VERSION 5.7 ;
  NOWIREEXTENSIONATPIN ON ;
  DIVIDERCHAR "/" ;
  BUSBITCHARS "[]" ;
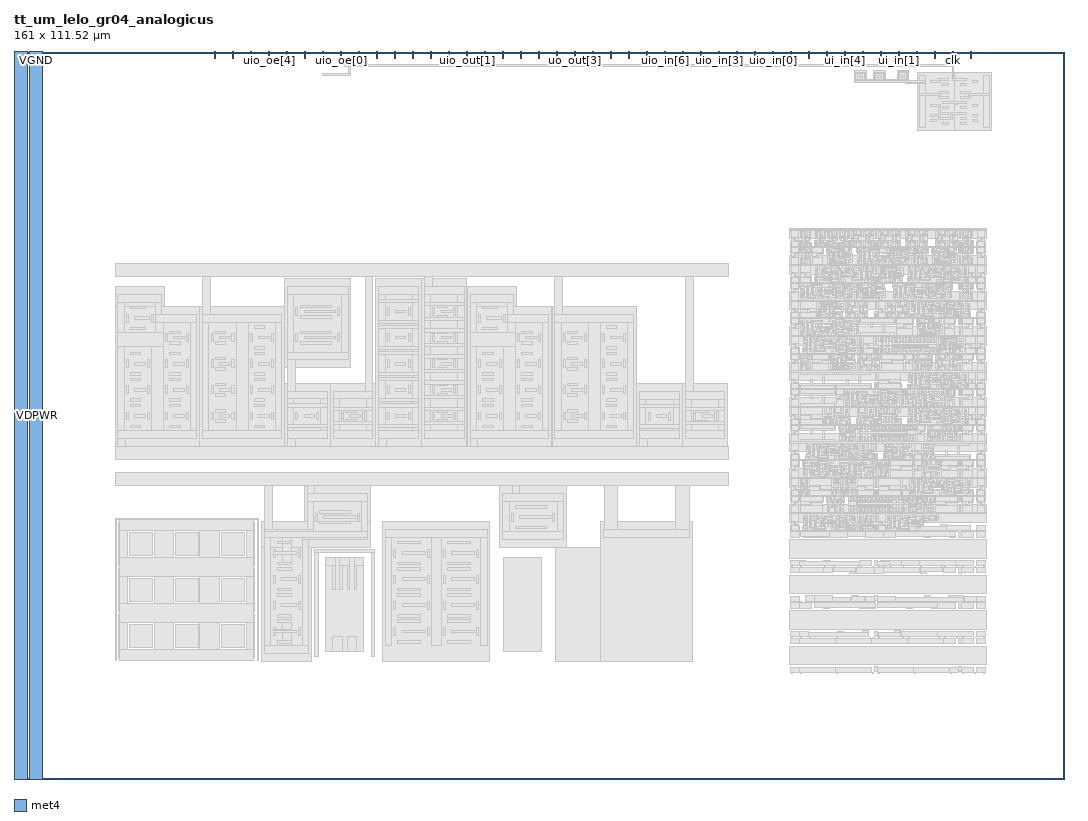
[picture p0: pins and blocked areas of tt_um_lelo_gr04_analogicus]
MACRO tt_um_lelo_gr04_analogicus
  CLASS BLOCK ;
  FOREIGN tt_um_lelo_gr04_analogicus ;
  ORIGIN 0.000 0.000 ;
  SIZE 161.000 BY 111.520 ;
  PIN uio_oe[0]
    DIRECTION OUTPUT ;
    USE SIGNAL ;
    PORT
      LAYER met4 ;
        RECT 49.990 110.520 50.290 111.520 ;
    END
  END uio_oe[0]
  PIN uio_oe[1]
    DIRECTION OUTPUT ;
    USE SIGNAL ;
    PORT
      LAYER met4 ;
        RECT 47.230 110.520 47.530 111.520 ;
    END
  END uio_oe[1]
  PIN uio_oe[2]
    DIRECTION OUTPUT ;
    USE SIGNAL ;
    PORT
      LAYER met4 ;
        RECT 44.470 110.520 44.770 111.520 ;
    END
  END uio_oe[2]
  PIN uio_oe[3]
    DIRECTION OUTPUT ;
    USE SIGNAL ;
    PORT
      LAYER met4 ;
        RECT 41.710 110.520 42.010 111.520 ;
    END
  END uio_oe[3]
  PIN uio_oe[4]
    DIRECTION OUTPUT ;
    USE SIGNAL ;
    PORT
      LAYER met4 ;
        RECT 38.950 110.520 39.250 111.520 ;
    END
  END uio_oe[4]
  PIN uio_oe[5]
    DIRECTION OUTPUT ;
    USE SIGNAL ;
    PORT
      LAYER met4 ;
        RECT 36.190 110.520 36.490 111.520 ;
    END
  END uio_oe[5]
  PIN uio_oe[6]
    DIRECTION OUTPUT ;
    USE SIGNAL ;
    PORT
      LAYER met4 ;
        RECT 33.430 110.520 33.730 111.520 ;
    END
  END uio_oe[6]
  PIN uio_oe[7]
    DIRECTION OUTPUT ;
    USE SIGNAL ;
    PORT
      LAYER met4 ;
        RECT 30.670 110.520 30.970 111.520 ;
    END
  END uio_oe[7]
  PIN uio_out[7]
    DIRECTION OUTPUT ;
    USE SIGNAL ;
    ANTENNADIFFAREA 0.445500 ;
    PORT
      LAYER met4 ;
        RECT 52.750 110.520 53.050 111.520 ;
    END
  END uio_out[7]
  PIN uio_out[6]
    DIRECTION OUTPUT ;
    USE SIGNAL ;
    ANTENNADIFFAREA 0.445500 ;
    PORT
      LAYER met4 ;
        RECT 55.510 110.520 55.810 111.520 ;
    END
  END uio_out[6]
  PIN uio_out[5]
    DIRECTION OUTPUT ;
    USE SIGNAL ;
    ANTENNADIFFAREA 0.445500 ;
    PORT
      LAYER met4 ;
        RECT 58.270 110.520 58.570 111.520 ;
    END
  END uio_out[5]
  PIN uio_out[4]
    DIRECTION OUTPUT ;
    USE SIGNAL ;
    ANTENNADIFFAREA 0.445500 ;
    PORT
      LAYER met4 ;
        RECT 61.030 110.520 61.330 111.520 ;
    END
  END uio_out[4]
  PIN uio_out[3]
    DIRECTION OUTPUT ;
    USE SIGNAL ;
    ANTENNADIFFAREA 0.445500 ;
    PORT
      LAYER met4 ;
        RECT 63.790 110.520 64.090 111.520 ;
    END
  END uio_out[3]
  PIN uio_out[2]
    DIRECTION OUTPUT ;
    USE SIGNAL ;
    ANTENNADIFFAREA 0.445500 ;
    PORT
      LAYER met4 ;
        RECT 66.550 110.520 66.850 111.520 ;
    END
  END uio_out[2]
  PIN uio_out[1]
    DIRECTION OUTPUT ;
    USE SIGNAL ;
    ANTENNADIFFAREA 0.445500 ;
    PORT
      LAYER met4 ;
        RECT 69.310 110.520 69.610 111.520 ;
    END
  END uio_out[1]
  PIN uio_out[0]
    DIRECTION OUTPUT ;
    USE SIGNAL ;
    ANTENNADIFFAREA 0.445500 ;
    PORT
      LAYER met4 ;
        RECT 72.070 110.520 72.370 111.520 ;
    END
  END uio_out[0]
  PIN uo_out[7]
    DIRECTION OUTPUT ;
    USE SIGNAL ;
    PORT
      LAYER met4 ;
        RECT 74.830 110.520 75.130 111.520 ;
    END
  END uo_out[7]
  PIN uo_out[6]
    DIRECTION OUTPUT ;
    USE SIGNAL ;
    PORT
      LAYER met4 ;
        RECT 77.590 110.520 77.890 111.520 ;
    END
  END uo_out[6]
  PIN uo_out[5]
    DIRECTION OUTPUT ;
    USE SIGNAL ;
    PORT
      LAYER met4 ;
        RECT 80.350 110.520 80.650 111.520 ;
    END
  END uo_out[5]
  PIN ui_in[4]
    DIRECTION INPUT ;
    USE SIGNAL ;
    PORT
      LAYER met4 ;
        RECT 127.270 110.520 127.570 111.520 ;
    END
  END ui_in[4]
  PIN ui_in[3]
    DIRECTION INPUT ;
    USE SIGNAL ;
    PORT
      LAYER met4 ;
        RECT 130.030 110.520 130.330 111.520 ;
    END
  END ui_in[3]
  PIN ui_in[2]
    DIRECTION INPUT ;
    USE SIGNAL ;
    PORT
      LAYER met4 ;
        RECT 132.790 110.520 133.090 111.520 ;
    END
  END ui_in[2]
  PIN ui_in[1]
    DIRECTION INPUT ;
    USE SIGNAL ;
    ANTENNAGATEAREA 0.490500 ;
    ANTENNADIFFAREA 0.202500 ;
    PORT
      LAYER met4 ;
        RECT 135.550 110.520 135.850 111.520 ;
    END
  END ui_in[1]
  PIN ui_in[0]
    DIRECTION INPUT ;
    USE SIGNAL ;
    ANTENNAGATEAREA 0.399000 ;
    ANTENNADIFFAREA 0.202500 ;
    PORT
      LAYER met4 ;
        RECT 138.310 110.520 138.610 111.520 ;
    END
  END ui_in[0]
  PIN rst_n
    DIRECTION INPUT ;
    USE SIGNAL ;
    ANTENNAGATEAREA 0.328500 ;
    ANTENNADIFFAREA 0.202500 ;
    PORT
      LAYER met4 ;
        RECT 141.070 110.520 141.370 111.520 ;
    END
  END rst_n
  PIN clk
    DIRECTION INPUT ;
    USE SIGNAL ;
    ANTENNAGATEAREA 0.852000 ;
    PORT
      LAYER met4 ;
        RECT 143.830 110.520 144.130 111.520 ;
    END
  END clk
  PIN ena
    DIRECTION INPUT ;
    USE SIGNAL ;
    PORT
      LAYER met4 ;
        RECT 146.590 110.520 146.890 111.520 ;
    END
  END ena
  PIN uio_in[4]
    DIRECTION INPUT ;
    USE SIGNAL ;
    PORT
      LAYER met4 ;
        RECT 105.190 110.520 105.490 111.520 ;
    END
  END uio_in[4]
  PIN uio_in[3]
    DIRECTION INPUT ;
    USE SIGNAL ;
    PORT
      LAYER met4 ;
        RECT 107.950 110.520 108.250 111.520 ;
    END
  END uio_in[3]
  PIN uio_in[2]
    DIRECTION INPUT ;
    USE SIGNAL ;
    PORT
      LAYER met4 ;
        RECT 110.710 110.520 111.010 111.520 ;
    END
  END uio_in[2]
  PIN uio_in[1]
    DIRECTION INPUT ;
    USE SIGNAL ;
    PORT
      LAYER met4 ;
        RECT 113.470 110.520 113.770 111.520 ;
    END
  END uio_in[1]
  PIN uio_in[0]
    DIRECTION INPUT ;
    USE SIGNAL ;
    PORT
      LAYER met4 ;
        RECT 116.230 110.520 116.530 111.520 ;
    END
  END uio_in[0]
  PIN ui_in[7]
    DIRECTION INPUT ;
    USE SIGNAL ;
    PORT
      LAYER met4 ;
        RECT 118.990 110.520 119.290 111.520 ;
    END
  END ui_in[7]
  PIN ui_in[6]
    DIRECTION INPUT ;
    USE SIGNAL ;
    PORT
      LAYER met4 ;
        RECT 121.750 110.520 122.050 111.520 ;
    END
  END ui_in[6]
  PIN ui_in[5]
    DIRECTION INPUT ;
    USE SIGNAL ;
    PORT
      LAYER met4 ;
        RECT 124.510 110.520 124.810 111.520 ;
    END
  END ui_in[5]
  PIN uo_out[4]
    DIRECTION OUTPUT ;
    USE SIGNAL ;
    PORT
      LAYER met4 ;
        RECT 83.110 110.520 83.410 111.520 ;
    END
  END uo_out[4]
  PIN uo_out[3]
    DIRECTION OUTPUT ;
    USE SIGNAL ;
    PORT
      LAYER met4 ;
        RECT 85.870 110.520 86.170 111.520 ;
    END
  END uo_out[3]
  PIN uo_out[2]
    DIRECTION OUTPUT ;
    USE SIGNAL ;
    PORT
      LAYER met4 ;
        RECT 88.630 110.520 88.930 111.520 ;
    END
  END uo_out[2]
  PIN uo_out[1]
    DIRECTION OUTPUT ;
    USE SIGNAL ;
    ANTENNAGATEAREA 0.288000 ;
    ANTENNADIFFAREA 0.445500 ;
    PORT
      LAYER met4 ;
        RECT 91.390 110.520 91.690 111.520 ;
    END
  END uo_out[1]
  PIN uo_out[0]
    DIRECTION OUTPUT ;
    USE SIGNAL ;
    ANTENNAGATEAREA 0.213000 ;
    ANTENNADIFFAREA 2.246400 ;
    PORT
      LAYER met4 ;
        RECT 94.150 110.520 94.450 111.520 ;
    END
  END uo_out[0]
  PIN uio_in[7]
    DIRECTION INPUT ;
    USE SIGNAL ;
    PORT
      LAYER met4 ;
        RECT 96.910 110.520 97.210 111.520 ;
    END
  END uio_in[7]
  PIN uio_in[6]
    DIRECTION INPUT ;
    USE SIGNAL ;
    PORT
      LAYER met4 ;
        RECT 99.670 110.520 99.970 111.520 ;
    END
  END uio_in[6]
  PIN uio_in[5]
    DIRECTION INPUT ;
    USE SIGNAL ;
    PORT
      LAYER met4 ;
        RECT 102.430 110.520 102.730 111.520 ;
    END
  END uio_in[5]
  PIN VDPWR
    DIRECTION INOUT ;
    USE POWER ;
    PORT
      LAYER met4 ;
        RECT 0.000 0.000 2.000 111.520 ;
    END
  END VDPWR
  PIN VGND
    DIRECTION INOUT ;
    USE GROUND ;
    PORT
      LAYER met4 ;
        RECT 2.400 0.000 4.400 111.520 ;
    END
  END VGND
  OBS
      LAYER pwell ;
        RECT 128.915 106.755 130.745 108.585 ;
        RECT 131.790 106.750 133.620 108.580 ;
        RECT 135.400 106.860 137.230 108.690 ;
        RECT 138.500 99.500 144.200 108.300 ;
      LAYER nwell ;
        RECT 144.200 99.500 149.900 108.300 ;
        RECT 118.870 82.825 149.150 84.430 ;
      LAYER pwell ;
        RECT 119.065 81.625 120.435 82.435 ;
        RECT 120.445 82.305 121.790 82.535 ;
        RECT 122.745 82.305 124.090 82.535 ;
        RECT 124.585 82.305 125.930 82.535 ;
        RECT 126.910 82.305 128.255 82.535 ;
        RECT 120.445 81.625 122.275 82.305 ;
        RECT 122.745 81.625 124.575 82.305 ;
        RECT 124.585 81.625 126.415 82.305 ;
        RECT 126.425 81.625 128.255 82.305 ;
        RECT 128.360 82.305 129.280 82.535 ;
        RECT 128.360 81.625 131.825 82.305 ;
        RECT 131.955 81.710 132.385 82.495 ;
        RECT 132.500 82.305 133.420 82.535 ;
        RECT 136.640 82.305 137.560 82.535 ;
        RECT 141.240 82.305 142.160 82.535 ;
        RECT 132.500 81.625 135.965 82.305 ;
        RECT 136.640 81.625 140.105 82.305 ;
        RECT 141.240 81.625 144.705 82.305 ;
        RECT 144.835 81.710 145.265 82.495 ;
        RECT 145.770 82.305 147.115 82.535 ;
        RECT 145.285 81.625 147.115 82.305 ;
        RECT 147.585 81.625 148.955 82.435 ;
        RECT 119.205 81.415 119.375 81.625 ;
        RECT 121.965 81.415 122.135 81.625 ;
        RECT 122.425 81.575 122.595 81.605 ;
        RECT 124.265 81.575 124.435 81.625 ;
        RECT 122.420 81.465 122.595 81.575 ;
        RECT 124.260 81.465 124.435 81.575 ;
        RECT 122.425 81.415 122.595 81.465 ;
        RECT 124.265 81.435 124.435 81.465 ;
        RECT 125.000 81.415 125.170 81.605 ;
        RECT 126.105 81.435 126.275 81.625 ;
        RECT 126.565 81.435 126.735 81.625 ;
        RECT 128.860 81.465 128.980 81.575 ;
        RECT 129.325 81.415 129.495 81.605 ;
        RECT 131.625 81.435 131.795 81.625 ;
        RECT 135.765 81.435 135.935 81.625 ;
        RECT 136.220 81.465 136.340 81.575 ;
        RECT 138.525 81.415 138.695 81.605 ;
        RECT 139.905 81.435 140.075 81.625 ;
        RECT 140.375 81.575 140.535 81.580 ;
        RECT 140.360 81.470 140.535 81.575 ;
        RECT 140.360 81.465 140.480 81.470 ;
        RECT 141.100 81.415 141.270 81.605 ;
        RECT 144.505 81.435 144.675 81.625 ;
        RECT 145.425 81.415 145.595 81.625 ;
        RECT 147.260 81.465 147.380 81.575 ;
        RECT 148.645 81.415 148.815 81.625 ;
        RECT 119.065 80.605 120.435 81.415 ;
        RECT 120.445 80.735 122.275 81.415 ;
        RECT 120.445 80.505 121.790 80.735 ;
        RECT 122.285 80.605 124.115 81.415 ;
        RECT 124.585 80.735 128.485 81.415 ;
        RECT 129.185 80.735 138.375 81.415 ;
        RECT 138.385 80.735 140.215 81.415 ;
        RECT 124.585 80.505 125.515 80.735 ;
        RECT 133.695 80.515 134.625 80.735 ;
        RECT 137.455 80.505 138.375 80.735 ;
        RECT 138.870 80.505 140.215 80.735 ;
        RECT 140.685 80.735 144.585 81.415 ;
        RECT 140.685 80.505 141.615 80.735 ;
        RECT 144.835 80.545 145.265 81.330 ;
        RECT 145.285 80.735 147.115 81.415 ;
        RECT 145.770 80.505 147.115 80.735 ;
        RECT 147.585 80.605 148.955 81.415 ;
      LAYER nwell ;
        RECT 118.870 77.385 149.150 80.215 ;
      LAYER pwell ;
        RECT 15.500 72.510 23.100 75.510 ;
        RECT 15.500 51.030 28.460 72.510 ;
      LAYER nwell ;
        RECT 28.500 51.030 41.460 72.510 ;
      LAYER pwell ;
        RECT 41.500 63.030 51.660 76.710 ;
        RECT 41.500 51.030 48.460 60.710 ;
      LAYER nwell ;
        RECT 48.500 51.030 55.460 60.710 ;
      LAYER pwell ;
        RECT 55.500 51.030 62.460 76.710 ;
      LAYER nwell ;
        RECT 62.500 51.030 69.460 76.710 ;
      LAYER pwell ;
        RECT 119.065 76.185 120.435 76.995 ;
        RECT 120.445 76.185 122.275 76.995 ;
        RECT 122.745 76.865 123.665 77.095 ;
        RECT 126.495 76.865 127.425 77.085 ;
        RECT 122.745 76.185 131.935 76.865 ;
        RECT 131.955 76.270 132.385 77.055 ;
        RECT 132.405 76.865 133.335 77.095 ;
        RECT 141.515 76.865 142.445 77.085 ;
        RECT 145.275 76.865 146.195 77.095 ;
        RECT 132.405 76.185 136.305 76.865 ;
        RECT 137.005 76.185 146.195 76.865 ;
        RECT 146.205 76.185 147.575 76.995 ;
        RECT 147.585 76.185 148.955 76.995 ;
        RECT 119.205 75.975 119.375 76.185 ;
        RECT 120.585 75.975 120.755 76.185 ;
        RECT 122.420 76.025 122.540 76.135 ;
        RECT 130.060 75.975 130.230 76.165 ;
        RECT 131.625 75.995 131.795 76.185 ;
        RECT 132.820 75.995 132.990 76.185 ;
        RECT 133.935 76.020 134.095 76.130 ;
        RECT 134.845 75.975 135.015 76.165 ;
        RECT 136.680 76.025 136.800 76.135 ;
        RECT 137.145 75.995 137.315 76.185 ;
        RECT 144.055 76.020 144.215 76.130 ;
        RECT 145.425 75.975 145.595 76.165 ;
        RECT 146.345 75.995 146.515 76.185 ;
        RECT 147.260 76.025 147.380 76.135 ;
        RECT 148.645 75.975 148.815 76.185 ;
        RECT 69.500 72.510 77.100 75.510 ;
        RECT 119.065 75.165 120.435 75.975 ;
        RECT 120.445 75.295 129.635 75.975 ;
        RECT 124.955 75.075 125.885 75.295 ;
        RECT 128.715 75.065 129.635 75.295 ;
        RECT 129.645 75.295 133.545 75.975 ;
        RECT 134.705 75.295 143.895 75.975 ;
        RECT 129.645 75.065 130.575 75.295 ;
        RECT 139.215 75.075 140.145 75.295 ;
        RECT 142.975 75.065 143.895 75.295 ;
        RECT 144.835 75.105 145.265 75.890 ;
        RECT 145.285 75.295 147.115 75.975 ;
        RECT 145.770 75.065 147.115 75.295 ;
        RECT 147.585 75.165 148.955 75.975 ;
        RECT 69.500 51.030 82.460 72.510 ;
      LAYER nwell ;
        RECT 82.500 51.030 95.460 72.510 ;
        RECT 118.870 71.945 149.150 74.775 ;
      LAYER pwell ;
        RECT 119.065 70.745 120.435 71.555 ;
        RECT 120.445 70.745 123.195 71.555 ;
        RECT 123.205 71.425 124.135 71.655 ;
        RECT 127.440 71.425 128.360 71.655 ;
        RECT 123.205 70.745 127.105 71.425 ;
        RECT 127.440 70.745 130.905 71.425 ;
        RECT 131.955 70.830 132.385 71.615 ;
        RECT 132.405 70.745 133.775 71.555 ;
        RECT 136.440 71.425 137.360 71.655 ;
        RECT 141.975 71.425 142.905 71.645 ;
        RECT 145.735 71.425 146.655 71.655 ;
        RECT 133.895 70.745 137.360 71.425 ;
        RECT 137.465 70.745 146.655 71.425 ;
        RECT 147.585 70.745 148.955 71.555 ;
        RECT 119.205 70.535 119.375 70.745 ;
        RECT 120.585 70.535 120.755 70.745 ;
        RECT 123.620 70.555 123.790 70.745 ;
        RECT 129.785 70.535 129.955 70.725 ;
        RECT 130.705 70.555 130.875 70.745 ;
        RECT 131.175 70.590 131.335 70.700 ;
        RECT 132.545 70.555 132.715 70.745 ;
        RECT 133.925 70.555 134.095 70.745 ;
        RECT 135.305 70.535 135.475 70.725 ;
        RECT 137.605 70.555 137.775 70.745 ;
        RECT 138.060 70.585 138.180 70.695 ;
        RECT 138.800 70.535 138.970 70.725 ;
        RECT 142.665 70.535 142.835 70.725 ;
        RECT 144.500 70.585 144.620 70.695 ;
        RECT 145.425 70.535 145.595 70.725 ;
        RECT 146.815 70.590 146.975 70.700 ;
        RECT 147.260 70.585 147.380 70.695 ;
        RECT 148.645 70.535 148.815 70.745 ;
        RECT 119.065 69.725 120.435 70.535 ;
        RECT 120.445 69.855 129.635 70.535 ;
        RECT 124.955 69.635 125.885 69.855 ;
        RECT 128.715 69.625 129.635 69.855 ;
        RECT 129.645 69.725 135.155 70.535 ;
        RECT 135.165 69.725 137.915 70.535 ;
        RECT 138.385 69.855 142.285 70.535 ;
        RECT 138.385 69.625 139.315 69.855 ;
        RECT 142.525 69.725 144.355 70.535 ;
        RECT 144.835 69.665 145.265 70.450 ;
        RECT 145.285 69.725 147.115 70.535 ;
        RECT 147.585 69.725 148.955 70.535 ;
      LAYER nwell ;
        RECT 118.870 66.505 149.150 69.335 ;
      LAYER pwell ;
        RECT 119.065 65.305 120.435 66.115 ;
        RECT 125.415 65.985 126.345 66.205 ;
        RECT 129.175 65.985 130.095 66.215 ;
        RECT 120.905 65.305 130.095 65.985 ;
        RECT 130.105 65.305 131.935 66.115 ;
        RECT 131.955 65.390 132.385 66.175 ;
        RECT 141.605 65.985 142.535 66.215 ;
        RECT 132.405 65.305 141.510 65.985 ;
        RECT 141.605 65.305 145.505 65.985 ;
        RECT 145.745 65.305 147.575 66.115 ;
        RECT 147.585 65.305 148.955 66.115 ;
        RECT 119.205 65.095 119.375 65.305 ;
        RECT 120.585 65.255 120.755 65.285 ;
        RECT 120.580 65.145 120.755 65.255 ;
        RECT 120.585 65.095 120.755 65.145 ;
        RECT 121.045 65.115 121.215 65.305 ;
        RECT 122.425 65.095 122.595 65.285 ;
        RECT 125.460 65.095 125.630 65.285 ;
        RECT 130.245 65.115 130.415 65.305 ;
        RECT 132.545 65.095 132.715 65.305 ;
        RECT 133.005 65.095 133.175 65.285 ;
        RECT 136.685 65.095 136.855 65.285 ;
        RECT 138.070 65.095 138.240 65.285 ;
        RECT 142.020 65.115 142.190 65.305 ;
        RECT 144.505 65.095 144.675 65.285 ;
        RECT 145.425 65.095 145.595 65.285 ;
        RECT 145.885 65.115 146.055 65.305 ;
        RECT 147.260 65.145 147.380 65.255 ;
        RECT 148.645 65.095 148.815 65.305 ;
        RECT 119.065 64.285 120.435 65.095 ;
        RECT 120.445 64.415 122.275 65.095 ;
        RECT 122.285 64.285 125.035 65.095 ;
        RECT 125.045 64.415 128.945 65.095 ;
        RECT 129.280 64.415 132.745 65.095 ;
        RECT 125.045 64.185 125.975 64.415 ;
        RECT 129.280 64.185 130.200 64.415 ;
        RECT 132.865 64.285 136.535 65.095 ;
        RECT 136.545 64.285 137.915 65.095 ;
        RECT 137.925 64.185 140.845 65.095 ;
        RECT 141.240 64.415 144.705 65.095 ;
        RECT 141.240 64.185 142.160 64.415 ;
        RECT 144.835 64.225 145.265 65.010 ;
        RECT 145.285 64.285 147.115 65.095 ;
        RECT 147.585 64.285 148.955 65.095 ;
      LAYER nwell ;
        RECT 118.870 61.065 149.150 63.895 ;
      LAYER pwell ;
        RECT 95.500 51.000 102.460 60.680 ;
      LAYER nwell ;
        RECT 102.500 51.000 109.460 60.680 ;
      LAYER pwell ;
        RECT 119.065 59.865 120.435 60.675 ;
        RECT 120.445 59.865 125.955 60.675 ;
        RECT 125.965 59.865 131.475 60.675 ;
        RECT 131.955 59.950 132.385 60.735 ;
        RECT 132.405 59.865 136.075 60.675 ;
        RECT 141.515 60.545 142.445 60.765 ;
        RECT 145.275 60.545 146.195 60.775 ;
        RECT 137.005 59.865 146.195 60.545 ;
        RECT 146.205 59.865 147.575 60.675 ;
        RECT 147.585 59.865 148.955 60.675 ;
        RECT 119.205 59.655 119.375 59.865 ;
        RECT 120.585 59.655 120.755 59.865 ;
        RECT 126.105 59.655 126.275 59.865 ;
        RECT 127.485 59.655 127.655 59.845 ;
        RECT 131.620 59.705 131.740 59.815 ;
        RECT 132.545 59.675 132.715 59.865 ;
        RECT 136.235 59.710 136.395 59.820 ;
        RECT 137.145 59.675 137.315 59.865 ;
        RECT 138.985 59.655 139.155 59.845 ;
        RECT 139.450 59.655 139.620 59.845 ;
        RECT 143.130 59.655 143.300 59.845 ;
        RECT 144.500 59.705 144.620 59.815 ;
        RECT 145.425 59.655 145.595 59.845 ;
        RECT 146.345 59.675 146.515 59.865 ;
        RECT 147.260 59.705 147.380 59.815 ;
        RECT 148.645 59.655 148.815 59.865 ;
        RECT 119.065 58.845 120.435 59.655 ;
        RECT 120.445 58.845 125.955 59.655 ;
        RECT 125.965 58.845 127.335 59.655 ;
        RECT 127.345 58.975 136.535 59.655 ;
        RECT 131.855 58.755 132.785 58.975 ;
        RECT 135.615 58.745 136.535 58.975 ;
        RECT 136.545 58.975 139.295 59.655 ;
        RECT 136.545 58.745 137.475 58.975 ;
        RECT 139.305 58.745 142.975 59.655 ;
        RECT 142.985 58.745 144.335 59.655 ;
        RECT 144.835 58.785 145.265 59.570 ;
        RECT 145.285 58.845 147.115 59.655 ;
        RECT 147.585 58.845 148.955 59.655 ;
      LAYER nwell ;
        RECT 118.870 55.625 149.150 58.455 ;
      LAYER pwell ;
        RECT 119.065 54.425 120.435 55.235 ;
        RECT 120.445 54.425 124.115 55.235 ;
        RECT 124.145 54.425 125.495 55.335 ;
        RECT 125.505 54.425 128.255 55.335 ;
        RECT 129.185 54.425 131.935 55.335 ;
        RECT 131.955 54.510 132.385 55.295 ;
        RECT 134.485 55.105 136.075 55.335 ;
        RECT 141.515 55.105 142.445 55.325 ;
        RECT 145.275 55.105 146.195 55.335 ;
        RECT 132.405 54.425 136.075 55.105 ;
        RECT 137.005 54.425 146.195 55.105 ;
        RECT 146.205 54.425 147.575 55.235 ;
        RECT 147.585 54.425 148.955 55.235 ;
        RECT 119.205 54.215 119.375 54.425 ;
        RECT 120.585 54.215 120.755 54.425 ;
        RECT 125.180 54.235 125.350 54.425 ;
        RECT 125.645 54.235 125.815 54.425 ;
        RECT 126.100 54.265 126.220 54.375 ;
        RECT 126.565 54.215 126.735 54.405 ;
        RECT 128.415 54.270 128.575 54.380 ;
        RECT 129.325 54.215 129.495 54.425 ;
        RECT 132.550 54.235 132.720 54.425 ;
        RECT 136.235 54.270 136.395 54.380 ;
        RECT 137.145 54.235 137.315 54.425 ;
        RECT 138.525 54.215 138.695 54.405 ;
        RECT 142.660 54.215 142.830 54.405 ;
        RECT 144.505 54.215 144.675 54.405 ;
        RECT 145.425 54.215 145.595 54.405 ;
        RECT 146.345 54.235 146.515 54.425 ;
        RECT 147.260 54.265 147.380 54.375 ;
        RECT 148.645 54.215 148.815 54.425 ;
        RECT 119.065 53.405 120.435 54.215 ;
        RECT 120.445 53.405 125.955 54.215 ;
        RECT 126.425 53.535 129.165 54.215 ;
        RECT 129.185 53.535 138.290 54.215 ;
        RECT 138.385 53.405 139.755 54.215 ;
        RECT 140.055 53.305 142.975 54.215 ;
        RECT 142.985 53.305 144.800 54.215 ;
        RECT 144.835 53.345 145.265 54.130 ;
        RECT 145.285 53.405 147.115 54.215 ;
        RECT 147.585 53.405 148.955 54.215 ;
      LAYER nwell ;
        RECT 118.870 50.185 149.150 53.015 ;
      LAYER pwell ;
        RECT 119.065 48.985 120.435 49.795 ;
        RECT 125.875 49.665 126.805 49.885 ;
        RECT 129.635 49.665 130.555 49.895 ;
        RECT 121.365 48.985 130.555 49.665 ;
        RECT 130.585 48.985 131.935 49.895 ;
        RECT 131.955 49.070 132.385 49.855 ;
        RECT 133.325 49.665 134.245 49.895 ;
        RECT 135.825 49.805 136.775 49.895 ;
        RECT 133.325 48.985 135.615 49.665 ;
        RECT 135.825 48.985 137.755 49.805 ;
        RECT 137.925 48.985 139.295 49.795 ;
        RECT 139.305 48.985 141.120 49.895 ;
        RECT 141.145 48.985 146.655 49.795 ;
        RECT 147.585 48.985 148.955 49.795 ;
        RECT 119.205 48.775 119.375 48.985 ;
        RECT 120.595 48.935 120.755 48.940 ;
        RECT 120.580 48.830 120.755 48.935 ;
        RECT 120.580 48.825 120.700 48.830 ;
        RECT 121.505 48.795 121.675 48.985 ;
        RECT 129.785 48.775 129.955 48.965 ;
        RECT 130.245 48.795 130.415 48.965 ;
        RECT 131.620 48.795 131.790 48.985 ;
        RECT 130.265 48.775 130.415 48.795 ;
        RECT 132.550 48.775 132.720 48.965 ;
        RECT 134.385 48.775 134.555 48.965 ;
        RECT 135.305 48.795 135.475 48.985 ;
        RECT 137.605 48.965 137.755 48.985 ;
        RECT 137.605 48.795 137.775 48.965 ;
        RECT 138.065 48.775 138.235 48.985 ;
        RECT 139.445 48.775 139.615 48.965 ;
        RECT 140.825 48.795 140.995 48.985 ;
        RECT 141.285 48.795 141.455 48.985 ;
        RECT 142.205 48.775 142.375 48.965 ;
        RECT 145.425 48.775 145.595 48.965 ;
        RECT 146.815 48.830 146.975 48.940 ;
        RECT 147.260 48.825 147.380 48.935 ;
        RECT 148.645 48.775 148.815 48.985 ;
        RECT 119.065 47.965 120.435 48.775 ;
        RECT 120.905 48.095 130.095 48.775 ;
        RECT 120.905 47.865 121.825 48.095 ;
        RECT 124.655 47.875 125.585 48.095 ;
        RECT 130.265 47.955 132.195 48.775 ;
        RECT 131.245 47.865 132.195 47.955 ;
        RECT 132.405 47.865 134.175 48.775 ;
        RECT 134.245 47.965 137.915 48.775 ;
        RECT 137.925 47.965 139.295 48.775 ;
        RECT 139.305 47.865 142.055 48.775 ;
        RECT 142.065 47.965 144.815 48.775 ;
        RECT 144.835 47.905 145.265 48.690 ;
        RECT 145.285 47.965 147.115 48.775 ;
        RECT 147.585 47.965 148.955 48.775 ;
      LAYER nwell ;
        RECT 44.500 39.480 54.660 44.980 ;
      LAYER pwell ;
        RECT 16.085 38.620 22.785 39.385 ;
        RECT 16.085 33.450 16.850 38.620 ;
        RECT 22.020 33.450 22.785 38.620 ;
        RECT 16.085 32.685 22.785 33.450 ;
        RECT 23.135 38.620 29.835 39.385 ;
        RECT 23.135 33.450 23.900 38.620 ;
        RECT 29.070 33.450 29.835 38.620 ;
        RECT 23.135 32.685 29.835 33.450 ;
        RECT 30.185 38.620 36.885 39.385 ;
        RECT 30.185 33.450 30.950 38.620 ;
        RECT 36.120 33.450 36.885 38.620 ;
        RECT 30.185 32.685 36.885 33.450 ;
      LAYER nwell ;
        RECT 38.000 35.500 54.660 39.480 ;
      LAYER pwell ;
        RECT 16.085 31.570 22.785 32.335 ;
        RECT 16.085 26.400 16.850 31.570 ;
        RECT 22.020 26.400 22.785 31.570 ;
        RECT 16.085 25.635 22.785 26.400 ;
        RECT 23.135 31.570 29.835 32.335 ;
        RECT 23.135 26.400 23.900 31.570 ;
        RECT 29.070 26.400 29.835 31.570 ;
        RECT 23.135 25.635 29.835 26.400 ;
        RECT 30.185 31.570 36.885 32.335 ;
        RECT 30.185 26.400 30.950 31.570 ;
        RECT 36.120 26.400 36.885 31.570 ;
        RECT 30.185 25.635 36.885 26.400 ;
        RECT 16.085 24.520 22.785 25.285 ;
        RECT 16.085 19.350 16.850 24.520 ;
        RECT 22.020 19.350 22.785 24.520 ;
        RECT 16.085 18.585 22.785 19.350 ;
        RECT 23.135 24.520 29.835 25.285 ;
        RECT 23.135 19.350 23.900 24.520 ;
        RECT 29.070 19.350 29.835 24.520 ;
        RECT 23.135 18.585 29.835 19.350 ;
        RECT 30.185 24.520 36.885 25.285 ;
        RECT 30.185 19.350 30.950 24.520 ;
        RECT 36.120 19.350 36.885 24.520 ;
        RECT 30.185 18.585 36.885 19.350 ;
      LAYER nwell ;
        RECT 38.000 18.000 45.600 35.500 ;
      LAYER pwell ;
        RECT 47.820 19.500 53.580 33.900 ;
      LAYER nwell ;
        RECT 56.500 18.000 72.980 39.480 ;
        RECT 74.500 35.500 84.660 44.980 ;
        RECT 118.870 44.745 149.150 47.575 ;
      LAYER pwell ;
        RECT 119.065 43.545 120.435 44.355 ;
        RECT 120.445 43.545 121.815 44.325 ;
        RECT 121.825 43.545 125.495 44.355 ;
        RECT 125.505 43.545 127.320 44.455 ;
        RECT 127.360 43.545 129.175 44.455 ;
        RECT 129.185 43.545 131.935 44.355 ;
        RECT 131.955 43.630 132.385 44.415 ;
        RECT 132.405 43.545 136.075 44.355 ;
        RECT 136.085 43.545 137.455 44.355 ;
        RECT 141.975 44.225 142.905 44.445 ;
        RECT 145.735 44.225 147.075 44.455 ;
        RECT 137.465 43.545 147.075 44.225 ;
        RECT 147.585 43.545 148.955 44.355 ;
        RECT 119.205 43.335 119.375 43.545 ;
        RECT 120.595 43.525 120.765 43.545 ;
        RECT 120.585 43.355 120.765 43.525 ;
        RECT 121.965 43.355 122.135 43.545 ;
        RECT 124.260 43.385 124.380 43.495 ;
        RECT 120.585 43.335 120.755 43.355 ;
        RECT 124.725 43.335 124.895 43.525 ;
        RECT 127.025 43.355 127.195 43.545 ;
        RECT 127.485 43.495 127.655 43.545 ;
        RECT 127.480 43.385 127.655 43.495 ;
        RECT 127.485 43.355 127.655 43.385 ;
        RECT 129.325 43.355 129.495 43.545 ;
        RECT 132.545 43.355 132.715 43.545 ;
        RECT 136.225 43.355 136.395 43.545 ;
        RECT 136.685 43.335 136.855 43.525 ;
        RECT 137.605 43.355 137.775 43.545 ;
        RECT 138.985 43.335 139.155 43.525 ;
        RECT 139.445 43.335 139.615 43.525 ;
        RECT 141.285 43.335 141.455 43.525 ;
        RECT 145.425 43.335 145.595 43.525 ;
        RECT 147.260 43.385 147.380 43.495 ;
        RECT 148.645 43.335 148.815 43.545 ;
        RECT 119.065 42.525 120.435 43.335 ;
        RECT 120.445 42.525 124.115 43.335 ;
        RECT 124.585 42.425 127.335 43.335 ;
        RECT 127.890 42.655 136.995 43.335 ;
        RECT 137.005 42.655 139.295 43.335 ;
        RECT 137.005 42.425 137.925 42.655 ;
        RECT 139.320 42.425 141.135 43.335 ;
        RECT 141.145 42.525 144.815 43.335 ;
        RECT 144.835 42.465 145.265 43.250 ;
        RECT 145.285 42.525 147.115 43.335 ;
        RECT 147.585 42.525 148.955 43.335 ;
        RECT 75.120 19.500 80.880 33.900 ;
        RECT 83.000 18.000 89.960 35.480 ;
      LAYER nwell ;
        RECT 90.000 18.000 104.000 39.480 ;
        RECT 118.870 39.305 149.150 42.135 ;
      LAYER pwell ;
        RECT 119.065 38.105 120.435 38.915 ;
        RECT 125.415 38.785 126.345 39.005 ;
        RECT 129.175 38.785 130.095 39.015 ;
        RECT 120.905 38.105 130.095 38.785 ;
        RECT 130.165 38.105 131.935 39.015 ;
        RECT 131.955 38.190 132.385 38.975 ;
        RECT 132.405 38.105 133.775 38.915 ;
        RECT 138.295 38.785 139.225 39.005 ;
        RECT 142.055 38.785 142.975 39.015 ;
        RECT 133.785 38.105 142.975 38.785 ;
        RECT 142.985 38.105 146.655 38.915 ;
        RECT 147.585 38.105 148.955 38.915 ;
        RECT 119.205 37.895 119.375 38.105 ;
        RECT 120.560 37.915 120.730 38.085 ;
        RECT 121.045 37.915 121.215 38.105 ;
        RECT 120.620 37.895 120.730 37.915 ;
        RECT 125.185 37.895 125.355 38.085 ;
        RECT 127.945 37.895 128.115 38.085 ;
        RECT 130.705 37.895 130.875 38.085 ;
        RECT 131.620 37.915 131.790 38.105 ;
        RECT 132.545 37.915 132.715 38.105 ;
        RECT 133.465 37.895 133.635 38.085 ;
        RECT 133.925 37.915 134.095 38.105 ;
        RECT 135.305 37.895 135.475 38.085 ;
        RECT 143.125 37.915 143.295 38.105 ;
        RECT 144.500 37.945 144.620 38.055 ;
        RECT 145.425 37.895 145.595 38.085 ;
        RECT 146.815 37.950 146.975 38.060 ;
        RECT 147.260 37.945 147.380 38.055 ;
        RECT 148.645 37.895 148.815 38.105 ;
        RECT 119.065 37.085 120.435 37.895 ;
        RECT 120.620 37.215 125.035 37.895 ;
        RECT 121.105 36.985 125.035 37.215 ;
        RECT 125.045 37.085 127.795 37.895 ;
        RECT 127.805 37.215 130.545 37.895 ;
        RECT 130.565 37.085 133.315 37.895 ;
        RECT 133.340 36.985 135.155 37.895 ;
        RECT 135.165 37.215 144.355 37.895 ;
        RECT 139.675 36.995 140.605 37.215 ;
        RECT 143.435 36.985 144.355 37.215 ;
        RECT 144.835 37.025 145.265 37.810 ;
        RECT 145.285 37.085 147.115 37.895 ;
        RECT 147.585 37.085 148.955 37.895 ;
      LAYER nwell ;
        RECT 118.870 33.865 149.150 36.695 ;
      LAYER pwell ;
        RECT 119.065 32.665 120.435 33.475 ;
        RECT 120.445 33.345 121.365 33.575 ;
        RECT 124.195 33.345 125.125 33.565 ;
        RECT 120.445 32.665 129.635 33.345 ;
        RECT 129.645 32.665 131.475 33.475 ;
        RECT 131.955 32.750 132.385 33.535 ;
        RECT 132.890 33.345 134.235 33.575 ;
        RECT 132.405 32.665 134.235 33.345 ;
        RECT 134.245 32.665 136.075 33.475 ;
        RECT 136.085 32.665 138.835 33.575 ;
        RECT 138.845 32.665 144.355 33.475 ;
        RECT 144.365 32.665 147.115 33.475 ;
        RECT 147.585 32.665 148.955 33.475 ;
        RECT 119.205 32.455 119.375 32.665 ;
        RECT 120.585 32.455 120.755 32.645 ;
        RECT 124.265 32.455 124.435 32.645 ;
        RECT 125.645 32.455 125.815 32.645 ;
        RECT 129.325 32.455 129.495 32.665 ;
        RECT 129.785 32.475 129.955 32.665 ;
        RECT 131.620 32.505 131.740 32.615 ;
        RECT 132.545 32.475 132.715 32.665 ;
        RECT 133.000 32.455 133.170 32.645 ;
        RECT 133.465 32.455 133.635 32.645 ;
        RECT 134.385 32.475 134.555 32.665 ;
        RECT 136.225 32.475 136.395 32.665 ;
        RECT 138.985 32.475 139.155 32.665 ;
        RECT 142.205 32.455 142.375 32.645 ;
        RECT 142.665 32.455 142.835 32.645 ;
        RECT 144.505 32.615 144.675 32.665 ;
        RECT 144.500 32.505 144.675 32.615 ;
        RECT 144.505 32.475 144.675 32.505 ;
        RECT 145.425 32.455 145.595 32.645 ;
        RECT 147.260 32.505 147.380 32.615 ;
        RECT 148.645 32.455 148.815 32.665 ;
        RECT 119.065 31.645 120.435 32.455 ;
        RECT 120.445 31.645 124.115 32.455 ;
        RECT 124.125 31.645 125.495 32.455 ;
        RECT 125.615 31.775 129.080 32.455 ;
        RECT 128.160 31.545 129.080 31.775 ;
        RECT 129.185 31.545 131.935 32.455 ;
        RECT 131.965 31.545 133.315 32.455 ;
        RECT 133.325 31.645 138.835 32.455 ;
        RECT 138.940 31.775 142.405 32.455 ;
        RECT 138.940 31.545 139.860 31.775 ;
        RECT 142.525 31.645 144.355 32.455 ;
        RECT 144.835 31.585 145.265 32.370 ;
        RECT 145.285 31.645 147.115 32.455 ;
        RECT 147.585 31.645 148.955 32.455 ;
      LAYER nwell ;
        RECT 118.870 28.425 149.150 31.255 ;
      LAYER pwell ;
        RECT 119.065 27.225 120.435 28.035 ;
        RECT 121.375 27.225 122.725 28.135 ;
        RECT 122.755 27.225 125.485 28.135 ;
        RECT 128.465 28.045 129.415 28.135 ;
        RECT 125.505 27.225 128.245 27.905 ;
        RECT 128.465 27.225 130.395 28.045 ;
        RECT 130.565 27.225 131.935 28.035 ;
        RECT 131.955 27.310 132.385 28.095 ;
        RECT 132.405 27.225 135.155 28.035 ;
        RECT 139.675 27.905 140.605 28.125 ;
        RECT 143.325 27.905 145.535 28.135 ;
        RECT 135.165 27.225 145.535 27.905 ;
        RECT 145.745 27.225 147.575 28.035 ;
        RECT 147.585 27.225 148.955 28.035 ;
        RECT 119.205 27.015 119.375 27.225 ;
        RECT 120.585 27.015 120.755 27.205 ;
        RECT 121.505 27.035 121.675 27.225 ;
        RECT 122.420 27.065 122.540 27.175 ;
        RECT 122.885 27.015 123.055 27.205 ;
        RECT 125.185 27.035 125.355 27.225 ;
        RECT 125.645 27.035 125.815 27.225 ;
        RECT 130.245 27.205 130.395 27.225 ;
        RECT 130.245 27.035 130.415 27.205 ;
        RECT 130.705 27.035 130.875 27.225 ;
        RECT 132.545 27.015 132.715 27.225 ;
        RECT 135.305 27.035 135.475 27.225 ;
        RECT 141.745 27.015 141.915 27.205 ;
        RECT 144.500 27.065 144.620 27.175 ;
        RECT 145.425 27.015 145.595 27.205 ;
        RECT 145.885 27.035 146.055 27.225 ;
        RECT 147.260 27.065 147.380 27.175 ;
        RECT 148.645 27.015 148.815 27.225 ;
        RECT 119.065 26.205 120.435 27.015 ;
        RECT 120.445 26.205 122.275 27.015 ;
        RECT 122.745 26.335 132.025 27.015 ;
        RECT 132.405 26.335 141.595 27.015 ;
        RECT 124.105 26.115 125.025 26.335 ;
        RECT 129.690 26.215 132.025 26.335 ;
        RECT 131.105 26.105 132.025 26.215 ;
        RECT 136.915 26.115 137.845 26.335 ;
        RECT 140.675 26.105 141.595 26.335 ;
        RECT 141.605 26.205 144.355 27.015 ;
        RECT 144.835 26.145 145.265 26.930 ;
        RECT 145.285 26.205 147.115 27.015 ;
        RECT 147.585 26.205 148.955 27.015 ;
      LAYER nwell ;
        RECT 118.870 22.985 149.150 25.815 ;
      LAYER pwell ;
        RECT 119.065 21.785 120.435 22.595 ;
        RECT 120.445 21.785 121.815 22.595 ;
        RECT 126.335 22.465 127.265 22.685 ;
        RECT 130.095 22.465 131.015 22.695 ;
        RECT 121.825 21.785 131.015 22.465 ;
        RECT 131.955 21.870 132.385 22.655 ;
        RECT 135.060 22.465 135.980 22.695 ;
        RECT 132.515 21.785 135.980 22.465 ;
        RECT 136.085 21.785 141.595 22.595 ;
        RECT 141.605 21.785 147.115 22.595 ;
        RECT 147.585 21.785 148.955 22.595 ;
        RECT 119.205 21.575 119.375 21.785 ;
        RECT 120.585 21.575 120.755 21.785 ;
        RECT 121.965 21.595 122.135 21.785 ;
        RECT 126.105 21.575 126.275 21.765 ;
        RECT 131.175 21.630 131.335 21.740 ;
        RECT 131.625 21.575 131.795 21.765 ;
        RECT 132.545 21.595 132.715 21.785 ;
        RECT 136.225 21.595 136.395 21.785 ;
        RECT 137.145 21.575 137.315 21.765 ;
        RECT 141.745 21.595 141.915 21.785 ;
        RECT 142.665 21.575 142.835 21.765 ;
        RECT 144.500 21.625 144.620 21.735 ;
        RECT 145.425 21.575 145.595 21.765 ;
        RECT 147.260 21.625 147.380 21.735 ;
        RECT 148.645 21.575 148.815 21.785 ;
        RECT 119.065 20.765 120.435 21.575 ;
        RECT 120.445 20.765 125.955 21.575 ;
        RECT 125.965 20.765 131.475 21.575 ;
        RECT 131.485 20.765 136.995 21.575 ;
        RECT 137.005 20.765 142.515 21.575 ;
        RECT 142.525 20.765 144.355 21.575 ;
        RECT 144.835 20.705 145.265 21.490 ;
        RECT 145.285 20.765 147.115 21.575 ;
        RECT 147.585 20.765 148.955 21.575 ;
      LAYER nwell ;
        RECT 118.870 17.545 149.150 20.375 ;
      LAYER pwell ;
        RECT 119.065 16.345 120.435 17.155 ;
        RECT 120.445 16.345 125.955 17.155 ;
        RECT 125.965 16.345 131.475 17.155 ;
        RECT 131.955 16.430 132.385 17.215 ;
        RECT 132.405 16.345 137.915 17.155 ;
        RECT 137.925 16.345 143.435 17.155 ;
        RECT 143.445 16.345 144.815 17.155 ;
        RECT 144.835 16.430 145.265 17.215 ;
        RECT 145.285 16.345 147.115 17.155 ;
        RECT 147.585 16.345 148.955 17.155 ;
        RECT 119.205 16.155 119.375 16.345 ;
        RECT 120.585 16.155 120.755 16.345 ;
        RECT 126.105 16.155 126.275 16.345 ;
        RECT 131.620 16.185 131.740 16.295 ;
        RECT 132.545 16.155 132.715 16.345 ;
        RECT 138.065 16.155 138.235 16.345 ;
        RECT 143.585 16.155 143.755 16.345 ;
        RECT 145.425 16.155 145.595 16.345 ;
        RECT 147.260 16.185 147.380 16.295 ;
        RECT 148.645 16.155 148.815 16.345 ;
      LAYER li1 ;
        RECT 50.730 109.320 144.130 109.620 ;
        RECT 51.310 108.170 51.610 109.320 ;
        RECT 47.260 107.870 51.610 108.170 ;
        RECT 129.095 108.235 130.565 108.405 ;
        RECT 129.095 107.220 129.265 108.235 ;
        RECT 129.585 107.505 130.075 107.835 ;
        RECT 130.395 107.220 130.565 108.235 ;
        RECT 131.970 108.230 133.440 108.400 ;
        RECT 131.970 107.220 132.140 108.230 ;
        RECT 132.460 107.500 132.950 107.830 ;
        RECT 133.270 107.220 133.440 108.230 ;
        RECT 135.580 108.340 137.050 108.510 ;
        RECT 135.580 107.220 135.750 108.340 ;
        RECT 136.070 107.610 136.560 107.940 ;
        RECT 136.880 107.220 137.050 108.340 ;
        RECT 129.040 107.150 137.050 107.220 ;
        RECT 138.800 107.150 139.700 107.900 ;
        RECT 143.830 107.450 144.130 109.320 ;
        RECT 129.040 106.730 139.700 107.150 ;
        RECT 141.800 107.150 143.300 107.450 ;
        RECT 143.830 107.150 146.000 107.450 ;
        RECT 141.800 107.050 142.100 107.150 ;
        RECT 140.600 106.750 142.100 107.050 ;
        RECT 146.900 106.750 147.800 107.050 ;
        RECT 136.680 106.710 139.700 106.730 ;
        RECT 138.800 105.050 139.700 106.710 ;
        RECT 142.400 106.650 143.240 106.670 ;
        RECT 145.100 106.650 145.940 106.670 ;
        RECT 142.400 106.350 143.300 106.650 ;
        RECT 145.100 106.350 146.000 106.650 ;
        RECT 142.400 105.450 143.240 105.470 ;
        RECT 145.100 105.450 145.940 105.470 ;
        RECT 141.800 105.150 143.300 105.450 ;
        RECT 145.100 105.150 146.600 105.450 ;
        RECT 141.800 105.050 142.100 105.150 ;
        RECT 138.800 104.750 142.100 105.050 ;
        RECT 138.800 99.900 139.700 104.750 ;
        RECT 141.800 104.650 142.100 104.750 ;
        RECT 146.300 105.050 146.600 105.150 ;
        RECT 148.700 105.050 149.600 107.900 ;
        RECT 146.300 104.750 149.600 105.050 ;
        RECT 142.400 104.650 143.240 104.670 ;
        RECT 145.100 104.650 145.940 104.670 ;
        RECT 146.300 104.650 146.600 104.750 ;
        RECT 141.800 104.350 143.300 104.650 ;
        RECT 145.100 104.350 146.600 104.650 ;
        RECT 144.240 103.850 144.620 103.860 ;
        RECT 142.400 103.550 146.000 103.850 ;
        RECT 140.600 103.150 142.100 103.450 ;
        RECT 144.240 103.400 144.620 103.550 ;
        RECT 146.900 103.150 147.800 103.450 ;
        RECT 140.600 101.550 141.500 101.850 ;
        RECT 141.800 101.450 142.100 103.150 ;
        RECT 142.400 103.050 143.240 103.070 ;
        RECT 145.100 103.050 145.940 103.070 ;
        RECT 142.400 102.750 143.300 103.050 ;
        RECT 145.100 102.750 146.000 103.050 ;
        RECT 142.400 102.250 143.240 102.270 ;
        RECT 142.400 101.950 143.300 102.250 ;
        RECT 143.600 101.950 146.000 102.250 ;
        RECT 143.600 101.450 143.900 101.950 ;
        RECT 146.900 101.550 147.800 101.850 ;
        RECT 141.800 101.150 143.900 101.450 ;
        RECT 145.100 101.150 146.000 101.450 ;
        RECT 140.600 100.750 141.500 101.050 ;
        RECT 146.900 100.750 147.800 101.050 ;
        RECT 142.400 100.650 143.240 100.670 ;
        RECT 145.100 100.650 145.940 100.670 ;
        RECT 142.400 100.350 143.300 100.650 ;
        RECT 145.100 100.350 146.000 100.650 ;
        RECT 148.700 99.900 149.600 104.750 ;
        RECT 119.060 84.155 148.960 84.325 ;
        RECT 119.145 83.065 120.355 84.155 ;
        RECT 119.145 82.355 119.665 82.895 ;
        RECT 119.835 82.525 120.355 83.065 ;
        RECT 120.530 83.005 120.790 84.155 ;
        RECT 120.965 83.080 121.220 83.985 ;
        RECT 121.390 83.395 121.720 84.155 ;
        RECT 121.935 83.225 122.105 83.985 ;
        RECT 119.145 81.605 120.355 82.355 ;
        RECT 120.530 81.605 120.790 82.445 ;
        RECT 120.965 82.350 121.135 83.080 ;
        RECT 121.390 83.055 122.105 83.225 ;
        RECT 121.390 82.845 121.560 83.055 ;
        RECT 122.830 83.005 123.090 84.155 ;
        RECT 123.265 83.080 123.520 83.985 ;
        RECT 123.690 83.395 124.020 84.155 ;
        RECT 124.235 83.225 124.405 83.985 ;
        RECT 121.305 82.515 121.560 82.845 ;
        RECT 120.965 81.775 121.220 82.350 ;
        RECT 121.390 82.325 121.560 82.515 ;
        RECT 121.840 82.505 122.195 82.875 ;
        RECT 121.390 82.155 122.105 82.325 ;
        RECT 121.390 81.605 121.720 81.985 ;
        RECT 121.935 81.775 122.105 82.155 ;
        RECT 122.830 81.605 123.090 82.445 ;
        RECT 123.265 82.350 123.435 83.080 ;
        RECT 123.690 83.055 124.405 83.225 ;
        RECT 123.690 82.845 123.860 83.055 ;
        RECT 124.670 83.005 124.930 84.155 ;
        RECT 125.105 83.080 125.360 83.985 ;
        RECT 125.530 83.395 125.860 84.155 ;
        RECT 126.075 83.225 126.245 83.985 ;
        RECT 123.605 82.515 123.860 82.845 ;
        RECT 123.265 81.775 123.520 82.350 ;
        RECT 123.690 82.325 123.860 82.515 ;
        RECT 124.140 82.505 124.495 82.875 ;
        RECT 123.690 82.155 124.405 82.325 ;
        RECT 123.690 81.605 124.020 81.985 ;
        RECT 124.235 81.775 124.405 82.155 ;
        RECT 124.670 81.605 124.930 82.445 ;
        RECT 125.105 82.350 125.275 83.080 ;
        RECT 125.530 83.055 126.245 83.225 ;
        RECT 126.595 83.225 126.765 83.985 ;
        RECT 126.980 83.395 127.310 84.155 ;
        RECT 126.595 83.055 127.310 83.225 ;
        RECT 127.480 83.080 127.735 83.985 ;
        RECT 125.530 82.845 125.700 83.055 ;
        RECT 125.445 82.515 125.700 82.845 ;
        RECT 125.105 81.775 125.360 82.350 ;
        RECT 125.530 82.325 125.700 82.515 ;
        RECT 125.980 82.505 126.335 82.875 ;
        RECT 126.505 82.505 126.860 82.875 ;
        RECT 127.140 82.845 127.310 83.055 ;
        RECT 127.140 82.515 127.395 82.845 ;
        RECT 127.140 82.325 127.310 82.515 ;
        RECT 127.565 82.350 127.735 83.080 ;
        RECT 127.910 83.005 128.170 84.155 ;
        RECT 128.345 83.015 128.730 83.985 ;
        RECT 128.900 83.695 129.225 84.155 ;
        RECT 129.745 83.525 130.025 83.985 ;
        RECT 128.900 83.305 130.025 83.525 ;
        RECT 125.530 82.155 126.245 82.325 ;
        RECT 125.530 81.605 125.860 81.985 ;
        RECT 126.075 81.775 126.245 82.155 ;
        RECT 126.595 82.155 127.310 82.325 ;
        RECT 126.595 81.775 126.765 82.155 ;
        RECT 126.980 81.605 127.310 81.985 ;
        RECT 127.480 81.775 127.735 82.350 ;
        RECT 127.910 81.605 128.170 82.445 ;
        RECT 128.345 82.345 128.625 83.015 ;
        RECT 128.900 82.845 129.350 83.305 ;
        RECT 130.215 83.135 130.615 83.985 ;
        RECT 131.015 83.695 131.285 84.155 ;
        RECT 131.455 83.525 131.740 83.985 ;
        RECT 128.795 82.515 129.350 82.845 ;
        RECT 129.520 82.575 130.615 83.135 ;
        RECT 128.900 82.405 129.350 82.515 ;
        RECT 128.345 81.775 128.730 82.345 ;
        RECT 128.900 82.235 130.025 82.405 ;
        RECT 128.900 81.605 129.225 82.065 ;
        RECT 129.745 81.775 130.025 82.235 ;
        RECT 130.215 81.775 130.615 82.575 ;
        RECT 130.785 83.305 131.740 83.525 ;
        RECT 130.785 82.405 130.995 83.305 ;
        RECT 131.165 82.575 131.855 83.135 ;
        RECT 132.025 82.990 132.315 84.155 ;
        RECT 132.485 83.015 132.870 83.985 ;
        RECT 133.040 83.695 133.365 84.155 ;
        RECT 133.885 83.525 134.165 83.985 ;
        RECT 133.040 83.305 134.165 83.525 ;
        RECT 130.785 82.235 131.740 82.405 ;
        RECT 132.485 82.345 132.765 83.015 ;
        RECT 133.040 82.845 133.490 83.305 ;
        RECT 134.355 83.135 134.755 83.985 ;
        RECT 135.155 83.695 135.425 84.155 ;
        RECT 135.595 83.525 135.880 83.985 ;
        RECT 132.935 82.515 133.490 82.845 ;
        RECT 133.660 82.575 134.755 83.135 ;
        RECT 133.040 82.405 133.490 82.515 ;
        RECT 131.015 81.605 131.285 82.065 ;
        RECT 131.455 81.775 131.740 82.235 ;
        RECT 132.025 81.605 132.315 82.330 ;
        RECT 132.485 81.775 132.870 82.345 ;
        RECT 133.040 82.235 134.165 82.405 ;
        RECT 133.040 81.605 133.365 82.065 ;
        RECT 133.885 81.775 134.165 82.235 ;
        RECT 134.355 81.775 134.755 82.575 ;
        RECT 134.925 83.305 135.880 83.525 ;
        RECT 134.925 82.405 135.135 83.305 ;
        RECT 135.305 82.575 135.995 83.135 ;
        RECT 136.625 83.015 137.010 83.985 ;
        RECT 137.180 83.695 137.505 84.155 ;
        RECT 138.025 83.525 138.305 83.985 ;
        RECT 137.180 83.305 138.305 83.525 ;
        RECT 134.925 82.235 135.880 82.405 ;
        RECT 135.155 81.605 135.425 82.065 ;
        RECT 135.595 81.775 135.880 82.235 ;
        RECT 136.625 82.345 136.905 83.015 ;
        RECT 137.180 82.845 137.630 83.305 ;
        RECT 138.495 83.135 138.895 83.985 ;
        RECT 139.295 83.695 139.565 84.155 ;
        RECT 139.735 83.525 140.020 83.985 ;
        RECT 137.075 82.515 137.630 82.845 ;
        RECT 137.800 82.575 138.895 83.135 ;
        RECT 137.180 82.405 137.630 82.515 ;
        RECT 136.625 81.775 137.010 82.345 ;
        RECT 137.180 82.235 138.305 82.405 ;
        RECT 137.180 81.605 137.505 82.065 ;
        RECT 138.025 81.775 138.305 82.235 ;
        RECT 138.495 81.775 138.895 82.575 ;
        RECT 139.065 83.305 140.020 83.525 ;
        RECT 139.065 82.405 139.275 83.305 ;
        RECT 139.445 82.575 140.135 83.135 ;
        RECT 141.225 83.015 141.610 83.985 ;
        RECT 141.780 83.695 142.105 84.155 ;
        RECT 142.625 83.525 142.905 83.985 ;
        RECT 141.780 83.305 142.905 83.525 ;
        RECT 139.065 82.235 140.020 82.405 ;
        RECT 139.295 81.605 139.565 82.065 ;
        RECT 139.735 81.775 140.020 82.235 ;
        RECT 141.225 82.345 141.505 83.015 ;
        RECT 141.780 82.845 142.230 83.305 ;
        RECT 143.095 83.135 143.495 83.985 ;
        RECT 143.895 83.695 144.165 84.155 ;
        RECT 144.335 83.525 144.620 83.985 ;
        RECT 141.675 82.515 142.230 82.845 ;
        RECT 142.400 82.575 143.495 83.135 ;
        RECT 141.780 82.405 142.230 82.515 ;
        RECT 141.225 81.775 141.610 82.345 ;
        RECT 141.780 82.235 142.905 82.405 ;
        RECT 141.780 81.605 142.105 82.065 ;
        RECT 142.625 81.775 142.905 82.235 ;
        RECT 143.095 81.775 143.495 82.575 ;
        RECT 143.665 83.305 144.620 83.525 ;
        RECT 143.665 82.405 143.875 83.305 ;
        RECT 144.045 82.575 144.735 83.135 ;
        RECT 144.905 82.990 145.195 84.155 ;
        RECT 145.455 83.225 145.625 83.985 ;
        RECT 145.840 83.395 146.170 84.155 ;
        RECT 145.455 83.055 146.170 83.225 ;
        RECT 146.340 83.080 146.595 83.985 ;
        RECT 145.365 82.505 145.720 82.875 ;
        RECT 146.000 82.845 146.170 83.055 ;
        RECT 146.000 82.515 146.255 82.845 ;
        RECT 143.665 82.235 144.620 82.405 ;
        RECT 143.895 81.605 144.165 82.065 ;
        RECT 144.335 81.775 144.620 82.235 ;
        RECT 144.905 81.605 145.195 82.330 ;
        RECT 146.000 82.325 146.170 82.515 ;
        RECT 146.425 82.350 146.595 83.080 ;
        RECT 146.770 83.005 147.030 84.155 ;
        RECT 147.665 83.065 148.875 84.155 ;
        RECT 147.665 82.525 148.185 83.065 ;
        RECT 145.455 82.155 146.170 82.325 ;
        RECT 145.455 81.775 145.625 82.155 ;
        RECT 145.840 81.605 146.170 81.985 ;
        RECT 146.340 81.775 146.595 82.350 ;
        RECT 146.770 81.605 147.030 82.445 ;
        RECT 148.355 82.355 148.875 82.895 ;
        RECT 147.665 81.605 148.875 82.355 ;
        RECT 119.060 81.435 148.960 81.605 ;
        RECT 119.145 80.685 120.355 81.435 ;
        RECT 119.145 80.145 119.665 80.685 ;
        RECT 120.530 80.595 120.790 81.435 ;
        RECT 120.965 80.690 121.220 81.265 ;
        RECT 121.390 81.055 121.720 81.435 ;
        RECT 121.935 80.885 122.105 81.265 ;
        RECT 121.390 80.715 122.105 80.885 ;
        RECT 119.835 79.975 120.355 80.515 ;
        RECT 15.500 77.030 109.500 79.030 ;
        RECT 119.145 78.885 120.355 79.975 ;
        RECT 120.530 78.885 120.790 80.035 ;
        RECT 120.965 79.960 121.135 80.690 ;
        RECT 121.390 80.525 121.560 80.715 ;
        RECT 122.365 80.665 124.035 81.435 ;
        RECT 124.670 80.695 124.925 81.265 ;
        RECT 125.095 81.035 125.425 81.435 ;
        RECT 125.850 80.900 126.380 81.265 ;
        RECT 126.570 81.095 126.845 81.265 ;
        RECT 126.565 80.925 126.845 81.095 ;
        RECT 125.850 80.865 126.025 80.900 ;
        RECT 125.095 80.695 126.025 80.865 ;
        RECT 121.305 80.195 121.560 80.525 ;
        RECT 121.390 79.985 121.560 80.195 ;
        RECT 121.840 80.165 122.195 80.535 ;
        RECT 122.365 80.145 123.115 80.665 ;
        RECT 120.965 79.055 121.220 79.960 ;
        RECT 121.390 79.815 122.105 79.985 ;
        RECT 123.285 79.975 124.035 80.495 ;
        RECT 121.390 78.885 121.720 79.645 ;
        RECT 121.935 79.055 122.105 79.815 ;
        RECT 122.365 78.885 124.035 79.975 ;
        RECT 124.670 80.025 124.840 80.695 ;
        RECT 125.095 80.525 125.265 80.695 ;
        RECT 125.010 80.195 125.265 80.525 ;
        RECT 125.490 80.195 125.685 80.525 ;
        RECT 124.670 79.055 125.005 80.025 ;
        RECT 125.175 78.885 125.345 80.025 ;
        RECT 125.515 79.225 125.685 80.195 ;
        RECT 125.855 79.565 126.025 80.695 ;
        RECT 126.195 79.905 126.365 80.705 ;
        RECT 126.570 80.105 126.845 80.925 ;
        RECT 127.015 79.905 127.205 81.265 ;
        RECT 127.385 80.900 127.895 81.435 ;
        RECT 128.115 80.625 128.360 81.230 ;
        RECT 129.270 80.885 129.525 81.175 ;
        RECT 129.695 81.055 130.025 81.435 ;
        RECT 129.270 80.715 130.020 80.885 ;
        RECT 127.405 80.455 128.635 80.625 ;
        RECT 126.195 79.735 127.205 79.905 ;
        RECT 127.375 79.890 128.125 80.080 ;
        RECT 125.855 79.395 126.980 79.565 ;
        RECT 127.375 79.225 127.545 79.890 ;
        RECT 128.295 79.645 128.635 80.455 ;
        RECT 129.270 79.895 129.620 80.545 ;
        RECT 129.790 79.725 130.020 80.715 ;
        RECT 125.515 79.055 127.545 79.225 ;
        RECT 127.715 78.885 127.885 79.645 ;
        RECT 128.120 79.235 128.635 79.645 ;
        RECT 129.270 79.555 130.020 79.725 ;
        RECT 129.270 79.055 129.525 79.555 ;
        RECT 129.695 78.885 130.025 79.385 ;
        RECT 130.195 79.055 130.365 81.175 ;
        RECT 130.725 81.075 131.055 81.435 ;
        RECT 131.225 81.045 131.720 81.215 ;
        RECT 131.925 81.045 132.780 81.215 ;
        RECT 130.595 79.855 131.055 80.905 ;
        RECT 130.535 79.070 130.860 79.855 ;
        RECT 131.225 79.685 131.395 81.045 ;
        RECT 131.565 80.135 131.915 80.755 ;
        RECT 132.085 80.535 132.440 80.755 ;
        RECT 132.085 79.945 132.255 80.535 ;
        RECT 132.610 80.335 132.780 81.045 ;
        RECT 133.655 80.975 133.985 81.435 ;
        RECT 134.195 81.075 134.545 81.245 ;
        RECT 132.985 80.505 133.775 80.755 ;
        RECT 134.195 80.685 134.455 81.075 ;
        RECT 134.765 80.985 135.715 81.265 ;
        RECT 135.885 80.995 136.075 81.435 ;
        RECT 136.245 81.055 137.315 81.225 ;
        RECT 133.945 80.335 134.115 80.515 ;
        RECT 131.225 79.515 131.620 79.685 ;
        RECT 131.790 79.555 132.255 79.945 ;
        RECT 132.425 80.165 134.115 80.335 ;
        RECT 131.450 79.385 131.620 79.515 ;
        RECT 132.425 79.385 132.595 80.165 ;
        RECT 134.285 79.995 134.455 80.685 ;
        RECT 132.955 79.825 134.455 79.995 ;
        RECT 134.645 80.025 134.855 80.815 ;
        RECT 135.025 80.195 135.375 80.815 ;
        RECT 135.545 80.205 135.715 80.985 ;
        RECT 136.245 80.825 136.415 81.055 ;
        RECT 135.885 80.655 136.415 80.825 ;
        RECT 135.885 80.375 136.105 80.655 ;
        RECT 136.585 80.485 136.825 80.885 ;
        RECT 135.545 80.035 135.950 80.205 ;
        RECT 136.285 80.115 136.825 80.485 ;
        RECT 136.995 80.700 137.315 81.055 ;
        RECT 137.560 80.975 137.865 81.435 ;
        RECT 138.035 80.725 138.290 81.255 ;
        RECT 136.995 80.525 137.320 80.700 ;
        RECT 136.995 80.225 137.910 80.525 ;
        RECT 137.170 80.195 137.910 80.225 ;
        RECT 134.645 79.865 135.320 80.025 ;
        RECT 135.780 79.945 135.950 80.035 ;
        RECT 134.645 79.855 135.610 79.865 ;
        RECT 134.285 79.685 134.455 79.825 ;
        RECT 131.030 78.885 131.280 79.345 ;
        RECT 131.450 79.055 131.700 79.385 ;
        RECT 131.915 79.055 132.595 79.385 ;
        RECT 132.765 79.485 133.840 79.655 ;
        RECT 134.285 79.515 134.845 79.685 ;
        RECT 135.150 79.565 135.610 79.855 ;
        RECT 135.780 79.775 137.000 79.945 ;
        RECT 132.765 79.145 132.935 79.485 ;
        RECT 133.170 78.885 133.500 79.315 ;
        RECT 133.670 79.145 133.840 79.485 ;
        RECT 134.135 78.885 134.505 79.345 ;
        RECT 134.675 79.055 134.845 79.515 ;
        RECT 135.780 79.395 135.950 79.775 ;
        RECT 137.170 79.605 137.340 80.195 ;
        RECT 138.080 80.075 138.290 80.725 ;
        RECT 138.555 80.885 138.725 81.265 ;
        RECT 138.940 81.055 139.270 81.435 ;
        RECT 138.555 80.715 139.270 80.885 ;
        RECT 138.465 80.165 138.820 80.535 ;
        RECT 139.100 80.525 139.270 80.715 ;
        RECT 139.440 80.690 139.695 81.265 ;
        RECT 139.100 80.195 139.355 80.525 ;
        RECT 135.080 79.055 135.950 79.395 ;
        RECT 136.540 79.435 137.340 79.605 ;
        RECT 136.120 78.885 136.370 79.345 ;
        RECT 136.540 79.145 136.710 79.435 ;
        RECT 136.890 78.885 137.220 79.265 ;
        RECT 137.560 78.885 137.865 80.025 ;
        RECT 138.035 79.195 138.290 80.075 ;
        RECT 139.100 79.985 139.270 80.195 ;
        RECT 138.555 79.815 139.270 79.985 ;
        RECT 139.525 79.960 139.695 80.690 ;
        RECT 139.870 80.595 140.130 81.435 ;
        RECT 140.770 80.695 141.025 81.265 ;
        RECT 141.195 81.035 141.525 81.435 ;
        RECT 141.950 80.900 142.480 81.265 ;
        RECT 142.670 81.095 142.945 81.265 ;
        RECT 142.665 80.925 142.945 81.095 ;
        RECT 141.950 80.865 142.125 80.900 ;
        RECT 141.195 80.695 142.125 80.865 ;
        RECT 138.555 79.055 138.725 79.815 ;
        RECT 138.940 78.885 139.270 79.645 ;
        RECT 139.440 79.055 139.695 79.960 ;
        RECT 139.870 78.885 140.130 80.035 ;
        RECT 140.770 80.025 140.940 80.695 ;
        RECT 141.195 80.525 141.365 80.695 ;
        RECT 141.110 80.195 141.365 80.525 ;
        RECT 141.590 80.195 141.785 80.525 ;
        RECT 140.770 79.055 141.105 80.025 ;
        RECT 141.275 78.885 141.445 80.025 ;
        RECT 141.615 79.225 141.785 80.195 ;
        RECT 141.955 79.565 142.125 80.695 ;
        RECT 142.295 79.905 142.465 80.705 ;
        RECT 142.670 80.105 142.945 80.925 ;
        RECT 143.115 79.905 143.305 81.265 ;
        RECT 143.485 80.900 143.995 81.435 ;
        RECT 144.215 80.625 144.460 81.230 ;
        RECT 144.905 80.710 145.195 81.435 ;
        RECT 145.455 80.885 145.625 81.265 ;
        RECT 145.840 81.055 146.170 81.435 ;
        RECT 145.455 80.715 146.170 80.885 ;
        RECT 143.505 80.455 144.735 80.625 ;
        RECT 142.295 79.735 143.305 79.905 ;
        RECT 143.475 79.890 144.225 80.080 ;
        RECT 141.955 79.395 143.080 79.565 ;
        RECT 143.475 79.225 143.645 79.890 ;
        RECT 144.395 79.645 144.735 80.455 ;
        RECT 145.365 80.165 145.720 80.535 ;
        RECT 146.000 80.525 146.170 80.715 ;
        RECT 146.340 80.690 146.595 81.265 ;
        RECT 146.000 80.195 146.255 80.525 ;
        RECT 141.615 79.055 143.645 79.225 ;
        RECT 143.815 78.885 143.985 79.645 ;
        RECT 144.220 79.235 144.735 79.645 ;
        RECT 144.905 78.885 145.195 80.050 ;
        RECT 146.000 79.985 146.170 80.195 ;
        RECT 145.455 79.815 146.170 79.985 ;
        RECT 146.425 79.960 146.595 80.690 ;
        RECT 146.770 80.595 147.030 81.435 ;
        RECT 147.665 80.685 148.875 81.435 ;
        RECT 145.455 79.055 145.625 79.815 ;
        RECT 145.840 78.885 146.170 79.645 ;
        RECT 146.340 79.055 146.595 79.960 ;
        RECT 146.770 78.885 147.030 80.035 ;
        RECT 147.665 79.975 148.185 80.515 ;
        RECT 148.355 80.145 148.875 80.685 ;
        RECT 147.665 78.885 148.875 79.975 ;
        RECT 119.060 78.715 148.960 78.885 ;
        RECT 119.145 77.625 120.355 78.715 ;
        RECT 120.525 77.625 122.195 78.715 ;
        RECT 15.940 73.070 22.660 74.270 ;
        RECT 15.940 68.470 16.900 73.070 ;
        RECT 17.860 72.070 20.100 72.470 ;
        RECT 21.700 71.270 22.660 73.070 ;
        RECT 28.940 71.270 30.140 77.030 ;
        RECT 41.940 74.270 51.220 75.470 ;
        RECT 17.220 70.070 17.540 71.270 ;
        RECT 18.500 70.470 20.740 70.870 ;
        RECT 21.060 70.070 21.380 71.270 ;
        RECT 21.700 70.070 28.020 71.270 ;
        RECT 17.860 68.870 20.100 69.270 ;
        RECT 21.700 68.470 22.900 70.070 ;
        RECT 15.940 66.270 22.900 68.470 ;
        RECT 23.860 68.270 25.460 68.670 ;
        RECT 23.220 67.070 23.540 68.270 ;
        RECT 24.500 67.470 26.100 67.870 ;
        RECT 26.420 67.070 26.740 68.270 ;
        RECT 23.860 66.670 25.460 67.070 ;
        RECT 15.940 53.470 16.900 66.270 ;
        RECT 17.860 65.070 19.460 65.470 ;
        RECT 17.220 63.070 17.540 64.270 ;
        RECT 18.500 63.470 20.100 63.870 ;
        RECT 20.420 63.070 20.740 64.270 ;
        RECT 17.860 61.870 19.460 62.270 ;
        RECT 17.860 61.070 19.460 61.470 ;
        RECT 17.220 59.070 17.540 60.270 ;
        RECT 18.500 59.470 20.100 59.870 ;
        RECT 20.420 59.070 20.740 60.270 ;
        RECT 17.860 57.870 19.460 58.270 ;
        RECT 17.860 57.070 19.460 57.470 ;
        RECT 17.220 55.070 17.540 56.270 ;
        RECT 18.500 55.470 20.100 55.870 ;
        RECT 20.420 55.070 20.740 56.270 ;
        RECT 17.860 53.870 19.460 54.270 ;
        RECT 21.060 53.470 22.900 66.270 ;
        RECT 23.860 65.070 25.460 65.470 ;
        RECT 23.220 63.070 23.540 64.270 ;
        RECT 24.500 63.470 26.100 63.870 ;
        RECT 26.420 63.070 26.740 64.270 ;
        RECT 23.860 61.870 25.460 62.270 ;
        RECT 23.860 61.070 25.460 61.470 ;
        RECT 23.220 59.070 23.540 60.270 ;
        RECT 24.500 59.470 26.100 59.870 ;
        RECT 26.420 59.070 26.740 60.270 ;
        RECT 23.860 57.870 25.460 58.270 ;
        RECT 23.860 57.070 25.460 57.470 ;
        RECT 23.220 55.070 23.540 56.270 ;
        RECT 24.500 55.470 26.100 55.870 ;
        RECT 26.420 55.070 26.740 56.270 ;
        RECT 23.860 53.870 25.460 54.270 ;
        RECT 27.060 53.470 28.020 70.070 ;
        RECT 15.940 52.270 28.020 53.470 ;
        RECT 28.940 70.070 41.020 71.270 ;
        RECT 28.940 53.470 29.900 70.070 ;
        RECT 30.860 68.270 32.460 68.670 ;
        RECT 30.220 67.070 30.540 68.270 ;
        RECT 31.500 67.470 33.100 67.870 ;
        RECT 33.420 67.070 33.740 68.270 ;
        RECT 30.860 66.670 32.460 67.070 ;
        RECT 30.860 64.270 32.460 64.670 ;
        RECT 30.220 63.070 30.540 64.270 ;
        RECT 31.500 63.470 33.100 63.870 ;
        RECT 33.420 63.070 33.740 64.270 ;
        RECT 30.860 62.670 32.460 63.070 ;
        RECT 30.860 60.270 32.460 60.670 ;
        RECT 30.220 59.070 30.540 60.270 ;
        RECT 31.500 59.470 33.100 59.870 ;
        RECT 33.420 59.070 33.740 60.270 ;
        RECT 30.860 58.670 32.460 59.070 ;
        RECT 30.860 56.270 32.460 56.670 ;
        RECT 30.220 55.070 30.540 56.270 ;
        RECT 31.500 55.470 33.100 55.870 ;
        RECT 33.420 55.070 33.740 56.270 ;
        RECT 30.860 54.670 32.460 55.070 ;
        RECT 34.060 53.470 35.900 70.070 ;
        RECT 36.860 69.070 38.460 69.470 ;
        RECT 36.220 67.070 36.540 68.270 ;
        RECT 37.500 67.470 39.100 67.870 ;
        RECT 39.420 67.070 39.740 68.270 ;
        RECT 36.860 65.870 38.460 66.270 ;
        RECT 36.860 65.070 38.460 65.470 ;
        RECT 36.220 63.070 36.540 64.270 ;
        RECT 37.500 63.470 39.100 63.870 ;
        RECT 39.420 63.070 39.740 64.270 ;
        RECT 36.860 61.870 38.460 62.270 ;
        RECT 36.860 61.070 38.460 61.470 ;
        RECT 36.220 59.070 36.540 60.270 ;
        RECT 37.500 59.470 39.100 59.870 ;
        RECT 39.420 59.070 39.740 60.270 ;
        RECT 36.860 57.870 38.460 58.270 ;
        RECT 36.860 57.070 38.460 57.470 ;
        RECT 36.220 55.070 36.540 56.270 ;
        RECT 37.500 55.470 39.100 55.870 ;
        RECT 39.420 55.070 39.740 56.270 ;
        RECT 36.860 53.870 38.460 54.270 ;
        RECT 40.060 53.470 41.020 70.070 ;
        RECT 28.940 52.270 41.020 53.470 ;
        RECT 41.940 65.470 42.900 74.270 ;
        RECT 43.860 72.270 48.660 72.670 ;
        RECT 43.220 71.070 43.540 72.270 ;
        RECT 44.500 71.470 49.300 71.870 ;
        RECT 49.620 71.070 49.940 72.270 ;
        RECT 43.860 70.670 48.660 71.070 ;
        RECT 43.860 68.270 48.660 68.670 ;
        RECT 43.220 67.070 43.540 68.270 ;
        RECT 44.500 67.470 49.300 67.870 ;
        RECT 49.620 67.070 49.940 68.270 ;
        RECT 43.860 66.670 48.660 67.070 ;
        RECT 50.260 65.470 51.220 74.270 ;
        RECT 41.940 64.270 51.220 65.470 ;
        RECT 41.940 59.470 43.140 64.270 ;
        RECT 53.820 59.470 55.020 77.030 ;
        RECT 62.940 75.470 64.140 77.030 ;
        RECT 41.940 58.270 48.020 59.470 ;
        RECT 41.940 57.530 42.900 58.270 ;
        RECT 47.060 57.530 48.020 58.270 ;
        RECT 41.940 57.030 48.020 57.530 ;
        RECT 41.940 54.330 42.900 57.030 ;
        RECT 43.220 55.070 43.540 56.270 ;
        RECT 44.500 55.470 46.100 55.870 ;
        RECT 46.420 55.070 46.740 56.270 ;
        RECT 47.060 54.330 48.020 57.030 ;
        RECT 41.940 53.830 48.020 54.330 ;
        RECT 41.940 53.470 42.900 53.830 ;
        RECT 47.060 53.470 48.020 53.830 ;
        RECT 41.940 52.270 48.020 53.470 ;
        RECT 48.940 58.270 55.020 59.470 ;
        RECT 48.940 57.030 49.900 58.270 ;
        RECT 54.060 57.030 55.020 58.270 ;
        RECT 48.940 56.530 55.020 57.030 ;
        RECT 48.940 54.830 49.900 56.530 ;
        RECT 50.860 56.270 52.460 56.530 ;
        RECT 50.220 55.070 50.540 56.270 ;
        RECT 51.500 55.470 53.100 55.870 ;
        RECT 53.420 55.070 53.740 56.270 ;
        RECT 50.860 54.830 52.460 55.070 ;
        RECT 54.060 54.830 55.020 56.530 ;
        RECT 48.940 54.330 55.020 54.830 ;
        RECT 48.940 53.470 49.900 54.330 ;
        RECT 54.060 53.470 55.020 54.330 ;
        RECT 48.940 52.270 55.020 53.470 ;
        RECT 55.940 74.270 62.020 75.470 ;
        RECT 55.940 73.530 56.900 74.270 ;
        RECT 61.060 73.530 62.020 74.270 ;
        RECT 55.940 73.030 62.020 73.530 ;
        RECT 55.940 70.330 56.900 73.030 ;
        RECT 57.220 71.070 57.540 72.270 ;
        RECT 58.500 71.470 60.100 71.870 ;
        RECT 60.420 71.070 60.740 72.270 ;
        RECT 61.060 70.330 62.020 73.030 ;
        RECT 55.940 69.830 62.020 70.330 ;
        RECT 55.940 69.530 56.900 69.830 ;
        RECT 61.060 69.530 62.020 69.830 ;
        RECT 55.940 69.030 62.020 69.530 ;
        RECT 55.940 66.330 56.900 69.030 ;
        RECT 57.220 67.070 57.540 68.270 ;
        RECT 58.500 67.470 60.100 67.870 ;
        RECT 60.420 67.070 60.740 68.270 ;
        RECT 61.060 66.330 62.020 69.030 ;
        RECT 55.940 65.830 62.020 66.330 ;
        RECT 55.940 65.530 56.900 65.830 ;
        RECT 61.060 65.530 62.020 65.830 ;
        RECT 55.940 65.030 62.020 65.530 ;
        RECT 55.940 62.330 56.900 65.030 ;
        RECT 57.220 63.070 57.540 64.270 ;
        RECT 58.500 63.470 60.100 63.870 ;
        RECT 60.420 63.070 60.740 64.270 ;
        RECT 61.060 62.330 62.020 65.030 ;
        RECT 55.940 61.830 62.020 62.330 ;
        RECT 55.940 61.530 56.900 61.830 ;
        RECT 61.060 61.530 62.020 61.830 ;
        RECT 55.940 61.030 62.020 61.530 ;
        RECT 55.940 58.330 56.900 61.030 ;
        RECT 57.220 59.070 57.540 60.270 ;
        RECT 58.500 59.470 60.100 59.870 ;
        RECT 60.420 59.070 60.740 60.270 ;
        RECT 61.060 58.330 62.020 61.030 ;
        RECT 55.940 57.830 62.020 58.330 ;
        RECT 55.940 57.530 56.900 57.830 ;
        RECT 61.060 57.530 62.020 57.830 ;
        RECT 55.940 57.030 62.020 57.530 ;
        RECT 55.940 54.330 56.900 57.030 ;
        RECT 57.220 55.070 57.540 56.270 ;
        RECT 58.500 55.470 60.100 55.870 ;
        RECT 60.420 55.070 60.740 56.270 ;
        RECT 61.060 54.330 62.020 57.030 ;
        RECT 55.940 53.830 62.020 54.330 ;
        RECT 55.940 53.470 56.900 53.830 ;
        RECT 61.060 53.470 62.020 53.830 ;
        RECT 55.940 52.270 62.020 53.470 ;
        RECT 62.940 74.270 69.020 75.470 ;
        RECT 62.940 73.030 63.900 74.270 ;
        RECT 68.060 73.030 69.020 74.270 ;
        RECT 62.940 72.530 69.020 73.030 ;
        RECT 62.940 70.830 63.900 72.530 ;
        RECT 64.860 72.270 66.460 72.530 ;
        RECT 64.220 71.070 64.540 72.270 ;
        RECT 65.500 71.470 67.100 71.870 ;
        RECT 67.420 71.070 67.740 72.270 ;
        RECT 64.860 70.830 66.460 71.070 ;
        RECT 68.060 70.830 69.020 72.530 ;
        RECT 62.940 70.330 69.020 70.830 ;
        RECT 62.940 69.030 63.900 70.330 ;
        RECT 68.060 69.030 69.020 70.330 ;
        RECT 62.940 68.530 69.020 69.030 ;
        RECT 62.940 66.830 63.900 68.530 ;
        RECT 64.860 68.270 66.460 68.530 ;
        RECT 64.220 67.070 64.540 68.270 ;
        RECT 65.500 67.470 67.100 67.870 ;
        RECT 67.420 67.070 67.740 68.270 ;
        RECT 64.860 66.830 66.460 67.070 ;
        RECT 68.060 66.830 69.020 68.530 ;
        RECT 62.940 66.330 69.020 66.830 ;
        RECT 62.940 65.030 63.900 66.330 ;
        RECT 68.060 65.030 69.020 66.330 ;
        RECT 62.940 64.530 69.020 65.030 ;
        RECT 62.940 62.830 63.900 64.530 ;
        RECT 64.860 64.270 66.460 64.530 ;
        RECT 64.220 63.070 64.540 64.270 ;
        RECT 65.500 63.470 67.100 63.870 ;
        RECT 67.420 63.070 67.740 64.270 ;
        RECT 64.860 62.830 66.460 63.070 ;
        RECT 68.060 62.830 69.020 64.530 ;
        RECT 62.940 62.330 69.020 62.830 ;
        RECT 62.940 61.030 63.900 62.330 ;
        RECT 68.060 61.030 69.020 62.330 ;
        RECT 62.940 60.530 69.020 61.030 ;
        RECT 62.940 58.830 63.900 60.530 ;
        RECT 64.860 60.270 66.460 60.530 ;
        RECT 64.220 59.070 64.540 60.270 ;
        RECT 65.500 59.470 67.100 59.870 ;
        RECT 67.420 59.070 67.740 60.270 ;
        RECT 64.860 58.830 66.460 59.070 ;
        RECT 68.060 58.830 69.020 60.530 ;
        RECT 62.940 58.330 69.020 58.830 ;
        RECT 62.940 57.030 63.900 58.330 ;
        RECT 68.060 57.030 69.020 58.330 ;
        RECT 62.940 56.530 69.020 57.030 ;
        RECT 62.940 54.830 63.900 56.530 ;
        RECT 64.860 56.270 66.460 56.530 ;
        RECT 64.220 55.070 64.540 56.270 ;
        RECT 65.500 55.470 67.100 55.870 ;
        RECT 67.420 55.070 67.740 56.270 ;
        RECT 64.860 54.830 66.460 55.070 ;
        RECT 68.060 54.830 69.020 56.530 ;
        RECT 62.940 54.330 69.020 54.830 ;
        RECT 62.940 53.470 63.900 54.330 ;
        RECT 68.060 53.470 69.020 54.330 ;
        RECT 62.940 52.270 69.020 53.470 ;
        RECT 69.940 73.070 76.660 74.270 ;
        RECT 69.940 68.470 70.900 73.070 ;
        RECT 71.860 72.070 74.100 72.470 ;
        RECT 75.700 71.270 76.660 73.070 ;
        RECT 82.940 71.270 84.140 77.030 ;
        RECT 71.220 70.070 71.540 71.270 ;
        RECT 72.500 70.470 74.740 70.870 ;
        RECT 75.060 70.070 75.380 71.270 ;
        RECT 75.700 70.070 82.020 71.270 ;
        RECT 71.860 68.870 74.100 69.270 ;
        RECT 75.700 68.470 76.900 70.070 ;
        RECT 69.940 66.270 76.900 68.470 ;
        RECT 77.860 68.270 79.460 68.670 ;
        RECT 77.220 67.070 77.540 68.270 ;
        RECT 78.500 67.470 80.100 67.870 ;
        RECT 80.420 67.070 80.740 68.270 ;
        RECT 77.860 66.670 79.460 67.070 ;
        RECT 69.940 53.470 70.900 66.270 ;
        RECT 71.860 65.070 73.460 65.470 ;
        RECT 71.220 63.070 71.540 64.270 ;
        RECT 72.500 63.470 74.100 63.870 ;
        RECT 74.420 63.070 74.740 64.270 ;
        RECT 71.860 61.870 73.460 62.270 ;
        RECT 71.860 61.070 73.460 61.470 ;
        RECT 71.220 59.070 71.540 60.270 ;
        RECT 72.500 59.470 74.100 59.870 ;
        RECT 74.420 59.070 74.740 60.270 ;
        RECT 71.860 57.870 73.460 58.270 ;
        RECT 71.860 57.070 73.460 57.470 ;
        RECT 71.220 55.070 71.540 56.270 ;
        RECT 72.500 55.470 74.100 55.870 ;
        RECT 74.420 55.070 74.740 56.270 ;
        RECT 71.860 53.870 73.460 54.270 ;
        RECT 75.060 53.470 76.900 66.270 ;
        RECT 77.860 65.070 79.460 65.470 ;
        RECT 77.220 63.070 77.540 64.270 ;
        RECT 78.500 63.470 80.100 63.870 ;
        RECT 80.420 63.070 80.740 64.270 ;
        RECT 77.860 61.870 79.460 62.270 ;
        RECT 77.860 61.070 79.460 61.470 ;
        RECT 77.220 59.070 77.540 60.270 ;
        RECT 78.500 59.470 80.100 59.870 ;
        RECT 80.420 59.070 80.740 60.270 ;
        RECT 77.860 57.870 79.460 58.270 ;
        RECT 77.860 57.070 79.460 57.470 ;
        RECT 77.220 55.070 77.540 56.270 ;
        RECT 78.500 55.470 80.100 55.870 ;
        RECT 80.420 55.070 80.740 56.270 ;
        RECT 77.860 53.870 79.460 54.270 ;
        RECT 81.060 53.470 82.020 70.070 ;
        RECT 69.940 52.270 82.020 53.470 ;
        RECT 82.940 70.070 95.020 71.270 ;
        RECT 82.940 53.470 83.900 70.070 ;
        RECT 84.860 68.270 86.460 68.670 ;
        RECT 84.220 67.070 84.540 68.270 ;
        RECT 85.500 67.470 87.100 67.870 ;
        RECT 87.420 67.070 87.740 68.270 ;
        RECT 84.860 66.670 86.460 67.070 ;
        RECT 84.860 64.270 86.460 64.670 ;
        RECT 84.220 63.070 84.540 64.270 ;
        RECT 85.500 63.470 87.100 63.870 ;
        RECT 87.420 63.070 87.740 64.270 ;
        RECT 84.860 62.670 86.460 63.070 ;
        RECT 84.860 60.270 86.460 60.670 ;
        RECT 84.220 59.070 84.540 60.270 ;
        RECT 85.500 59.470 87.100 59.870 ;
        RECT 87.420 59.070 87.740 60.270 ;
        RECT 84.860 58.670 86.460 59.070 ;
        RECT 84.860 56.270 86.460 56.670 ;
        RECT 84.220 55.070 84.540 56.270 ;
        RECT 85.500 55.470 87.100 55.870 ;
        RECT 87.420 55.070 87.740 56.270 ;
        RECT 84.860 54.670 86.460 55.070 ;
        RECT 88.060 53.470 89.900 70.070 ;
        RECT 90.860 69.070 92.460 69.470 ;
        RECT 90.220 67.070 90.540 68.270 ;
        RECT 91.500 67.470 93.100 67.870 ;
        RECT 93.420 67.070 93.740 68.270 ;
        RECT 90.860 65.870 92.460 66.270 ;
        RECT 90.860 65.070 92.460 65.470 ;
        RECT 90.220 63.070 90.540 64.270 ;
        RECT 91.500 63.470 93.100 63.870 ;
        RECT 93.420 63.070 93.740 64.270 ;
        RECT 90.860 61.870 92.460 62.270 ;
        RECT 90.860 61.070 92.460 61.470 ;
        RECT 90.220 59.070 90.540 60.270 ;
        RECT 91.500 59.470 93.100 59.870 ;
        RECT 93.420 59.070 93.740 60.270 ;
        RECT 90.860 57.870 92.460 58.270 ;
        RECT 90.860 57.070 92.460 57.470 ;
        RECT 90.220 55.070 90.540 56.270 ;
        RECT 91.500 55.470 93.100 55.870 ;
        RECT 93.420 55.070 93.740 56.270 ;
        RECT 90.860 53.870 92.460 54.270 ;
        RECT 94.060 53.470 95.020 70.070 ;
        RECT 102.940 59.440 104.140 77.030 ;
        RECT 119.145 76.915 119.665 77.455 ;
        RECT 119.835 77.085 120.355 77.625 ;
        RECT 120.525 76.935 121.275 77.455 ;
        RECT 121.445 77.105 122.195 77.625 ;
        RECT 122.830 77.525 123.085 78.405 ;
        RECT 123.255 77.575 123.560 78.715 ;
        RECT 123.900 78.335 124.230 78.715 ;
        RECT 124.410 78.165 124.580 78.455 ;
        RECT 124.750 78.255 125.000 78.715 ;
        RECT 123.780 77.995 124.580 78.165 ;
        RECT 125.170 78.205 126.040 78.545 ;
        RECT 119.145 76.165 120.355 76.915 ;
        RECT 120.525 76.165 122.195 76.935 ;
        RECT 122.830 76.875 123.040 77.525 ;
        RECT 123.780 77.405 123.950 77.995 ;
        RECT 125.170 77.825 125.340 78.205 ;
        RECT 126.275 78.085 126.445 78.545 ;
        RECT 126.615 78.255 126.985 78.715 ;
        RECT 127.280 78.115 127.450 78.455 ;
        RECT 127.620 78.285 127.950 78.715 ;
        RECT 128.185 78.115 128.355 78.455 ;
        RECT 124.120 77.655 125.340 77.825 ;
        RECT 125.510 77.745 125.970 78.035 ;
        RECT 126.275 77.915 126.835 78.085 ;
        RECT 127.280 77.945 128.355 78.115 ;
        RECT 128.525 78.215 129.205 78.545 ;
        RECT 129.420 78.215 129.670 78.545 ;
        RECT 129.840 78.255 130.090 78.715 ;
        RECT 126.665 77.775 126.835 77.915 ;
        RECT 125.510 77.735 126.475 77.745 ;
        RECT 125.170 77.565 125.340 77.655 ;
        RECT 125.800 77.575 126.475 77.735 ;
        RECT 123.210 77.375 123.950 77.405 ;
        RECT 123.210 77.075 124.125 77.375 ;
        RECT 123.800 76.900 124.125 77.075 ;
        RECT 122.830 76.345 123.085 76.875 ;
        RECT 123.255 76.165 123.560 76.625 ;
        RECT 123.805 76.545 124.125 76.900 ;
        RECT 124.295 77.115 124.835 77.485 ;
        RECT 125.170 77.395 125.575 77.565 ;
        RECT 124.295 76.715 124.535 77.115 ;
        RECT 125.015 76.945 125.235 77.225 ;
        RECT 124.705 76.775 125.235 76.945 ;
        RECT 124.705 76.545 124.875 76.775 ;
        RECT 125.405 76.615 125.575 77.395 ;
        RECT 125.745 76.785 126.095 77.405 ;
        RECT 126.265 76.785 126.475 77.575 ;
        RECT 126.665 77.605 128.165 77.775 ;
        RECT 126.665 76.915 126.835 77.605 ;
        RECT 128.525 77.435 128.695 78.215 ;
        RECT 129.500 78.085 129.670 78.215 ;
        RECT 127.005 77.265 128.695 77.435 ;
        RECT 128.865 77.655 129.330 78.045 ;
        RECT 129.500 77.915 129.895 78.085 ;
        RECT 127.005 77.085 127.175 77.265 ;
        RECT 123.805 76.375 124.875 76.545 ;
        RECT 125.045 76.165 125.235 76.605 ;
        RECT 125.405 76.335 126.355 76.615 ;
        RECT 126.665 76.525 126.925 76.915 ;
        RECT 127.345 76.845 128.135 77.095 ;
        RECT 126.575 76.355 126.925 76.525 ;
        RECT 127.135 76.165 127.465 76.625 ;
        RECT 128.340 76.555 128.510 77.265 ;
        RECT 128.865 77.065 129.035 77.655 ;
        RECT 128.680 76.845 129.035 77.065 ;
        RECT 129.205 76.845 129.555 77.465 ;
        RECT 129.725 76.555 129.895 77.915 ;
        RECT 130.260 77.745 130.585 78.530 ;
        RECT 130.065 76.695 130.525 77.745 ;
        RECT 128.340 76.385 129.195 76.555 ;
        RECT 129.400 76.385 129.895 76.555 ;
        RECT 130.065 76.165 130.395 76.525 ;
        RECT 130.755 76.425 130.925 78.545 ;
        RECT 131.095 78.215 131.425 78.715 ;
        RECT 131.595 78.045 131.850 78.545 ;
        RECT 131.100 77.875 131.850 78.045 ;
        RECT 131.100 76.885 131.330 77.875 ;
        RECT 131.500 77.055 131.850 77.705 ;
        RECT 132.025 77.550 132.315 78.715 ;
        RECT 132.490 77.575 132.825 78.545 ;
        RECT 132.995 77.575 133.165 78.715 ;
        RECT 133.335 78.375 135.365 78.545 ;
        RECT 132.490 76.905 132.660 77.575 ;
        RECT 133.335 77.405 133.505 78.375 ;
        RECT 132.830 77.075 133.085 77.405 ;
        RECT 133.310 77.075 133.505 77.405 ;
        RECT 133.675 78.035 134.800 78.205 ;
        RECT 132.915 76.905 133.085 77.075 ;
        RECT 133.675 76.905 133.845 78.035 ;
        RECT 131.100 76.715 131.850 76.885 ;
        RECT 131.095 76.165 131.425 76.545 ;
        RECT 131.595 76.425 131.850 76.715 ;
        RECT 132.025 76.165 132.315 76.890 ;
        RECT 132.490 76.335 132.745 76.905 ;
        RECT 132.915 76.735 133.845 76.905 ;
        RECT 134.015 77.695 135.025 77.865 ;
        RECT 134.015 76.895 134.185 77.695 ;
        RECT 134.390 77.015 134.665 77.495 ;
        RECT 134.385 76.845 134.665 77.015 ;
        RECT 133.670 76.700 133.845 76.735 ;
        RECT 132.915 76.165 133.245 76.565 ;
        RECT 133.670 76.335 134.200 76.700 ;
        RECT 134.390 76.335 134.665 76.845 ;
        RECT 134.835 76.335 135.025 77.695 ;
        RECT 135.195 77.710 135.365 78.375 ;
        RECT 135.535 77.955 135.705 78.715 ;
        RECT 135.940 77.955 136.455 78.365 ;
        RECT 135.195 77.520 135.945 77.710 ;
        RECT 136.115 77.145 136.455 77.955 ;
        RECT 137.090 78.045 137.345 78.545 ;
        RECT 137.515 78.215 137.845 78.715 ;
        RECT 137.090 77.875 137.840 78.045 ;
        RECT 135.225 76.975 136.455 77.145 ;
        RECT 137.090 77.055 137.440 77.705 ;
        RECT 135.205 76.165 135.715 76.700 ;
        RECT 135.935 76.370 136.180 76.975 ;
        RECT 137.610 76.885 137.840 77.875 ;
        RECT 137.090 76.715 137.840 76.885 ;
        RECT 137.090 76.425 137.345 76.715 ;
        RECT 137.515 76.165 137.845 76.545 ;
        RECT 138.015 76.425 138.185 78.545 ;
        RECT 138.355 77.745 138.680 78.530 ;
        RECT 138.850 78.255 139.100 78.715 ;
        RECT 139.270 78.215 139.520 78.545 ;
        RECT 139.735 78.215 140.415 78.545 ;
        RECT 139.270 78.085 139.440 78.215 ;
        RECT 139.045 77.915 139.440 78.085 ;
        RECT 138.415 76.695 138.875 77.745 ;
        RECT 139.045 76.555 139.215 77.915 ;
        RECT 139.610 77.655 140.075 78.045 ;
        RECT 139.385 76.845 139.735 77.465 ;
        RECT 139.905 77.065 140.075 77.655 ;
        RECT 140.245 77.435 140.415 78.215 ;
        RECT 140.585 78.115 140.755 78.455 ;
        RECT 140.990 78.285 141.320 78.715 ;
        RECT 141.490 78.115 141.660 78.455 ;
        RECT 141.955 78.255 142.325 78.715 ;
        RECT 140.585 77.945 141.660 78.115 ;
        RECT 142.495 78.085 142.665 78.545 ;
        RECT 142.900 78.205 143.770 78.545 ;
        RECT 143.940 78.255 144.190 78.715 ;
        RECT 142.105 77.915 142.665 78.085 ;
        RECT 142.105 77.775 142.275 77.915 ;
        RECT 140.775 77.605 142.275 77.775 ;
        RECT 142.970 77.745 143.430 78.035 ;
        RECT 140.245 77.265 141.935 77.435 ;
        RECT 139.905 76.845 140.260 77.065 ;
        RECT 140.430 76.555 140.600 77.265 ;
        RECT 140.805 76.845 141.595 77.095 ;
        RECT 141.765 77.085 141.935 77.265 ;
        RECT 142.105 76.915 142.275 77.605 ;
        RECT 138.545 76.165 138.875 76.525 ;
        RECT 139.045 76.385 139.540 76.555 ;
        RECT 139.745 76.385 140.600 76.555 ;
        RECT 141.475 76.165 141.805 76.625 ;
        RECT 142.015 76.525 142.275 76.915 ;
        RECT 142.465 77.735 143.430 77.745 ;
        RECT 143.600 77.825 143.770 78.205 ;
        RECT 144.360 78.165 144.530 78.455 ;
        RECT 144.710 78.335 145.040 78.715 ;
        RECT 144.360 77.995 145.160 78.165 ;
        RECT 142.465 77.575 143.140 77.735 ;
        RECT 143.600 77.655 144.820 77.825 ;
        RECT 142.465 76.785 142.675 77.575 ;
        RECT 143.600 77.565 143.770 77.655 ;
        RECT 142.845 76.785 143.195 77.405 ;
        RECT 143.365 77.395 143.770 77.565 ;
        RECT 143.365 76.615 143.535 77.395 ;
        RECT 143.705 76.945 143.925 77.225 ;
        RECT 144.105 77.115 144.645 77.485 ;
        RECT 144.990 77.405 145.160 77.995 ;
        RECT 145.380 77.575 145.685 78.715 ;
        RECT 145.855 77.525 146.110 78.405 ;
        RECT 146.285 77.625 147.495 78.715 ;
        RECT 144.990 77.375 145.730 77.405 ;
        RECT 143.705 76.775 144.235 76.945 ;
        RECT 142.015 76.355 142.365 76.525 ;
        RECT 142.585 76.335 143.535 76.615 ;
        RECT 143.705 76.165 143.895 76.605 ;
        RECT 144.065 76.545 144.235 76.775 ;
        RECT 144.405 76.715 144.645 77.115 ;
        RECT 144.815 77.075 145.730 77.375 ;
        RECT 144.815 76.900 145.140 77.075 ;
        RECT 144.815 76.545 145.135 76.900 ;
        RECT 145.900 76.875 146.110 77.525 ;
        RECT 144.065 76.375 145.135 76.545 ;
        RECT 145.380 76.165 145.685 76.625 ;
        RECT 145.855 76.345 146.110 76.875 ;
        RECT 146.285 76.915 146.805 77.455 ;
        RECT 146.975 77.085 147.495 77.625 ;
        RECT 147.665 77.625 148.875 78.715 ;
        RECT 147.665 77.085 148.185 77.625 ;
        RECT 148.355 76.915 148.875 77.455 ;
        RECT 146.285 76.165 147.495 76.915 ;
        RECT 147.665 76.165 148.875 76.915 ;
        RECT 119.060 75.995 148.960 76.165 ;
        RECT 119.145 75.245 120.355 75.995 ;
        RECT 120.530 75.445 120.785 75.735 ;
        RECT 120.955 75.615 121.285 75.995 ;
        RECT 120.530 75.275 121.280 75.445 ;
        RECT 119.145 74.705 119.665 75.245 ;
        RECT 119.835 74.535 120.355 75.075 ;
        RECT 119.145 73.445 120.355 74.535 ;
        RECT 120.530 74.455 120.880 75.105 ;
        RECT 121.050 74.285 121.280 75.275 ;
        RECT 120.530 74.115 121.280 74.285 ;
        RECT 120.530 73.615 120.785 74.115 ;
        RECT 120.955 73.445 121.285 73.945 ;
        RECT 121.455 73.615 121.625 75.735 ;
        RECT 121.985 75.635 122.315 75.995 ;
        RECT 122.485 75.605 122.980 75.775 ;
        RECT 123.185 75.605 124.040 75.775 ;
        RECT 121.855 74.415 122.315 75.465 ;
        RECT 121.795 73.630 122.120 74.415 ;
        RECT 122.485 74.245 122.655 75.605 ;
        RECT 122.825 74.695 123.175 75.315 ;
        RECT 123.345 75.095 123.700 75.315 ;
        RECT 123.345 74.505 123.515 75.095 ;
        RECT 123.870 74.895 124.040 75.605 ;
        RECT 124.915 75.535 125.245 75.995 ;
        RECT 125.455 75.635 125.805 75.805 ;
        RECT 124.245 75.065 125.035 75.315 ;
        RECT 125.455 75.245 125.715 75.635 ;
        RECT 126.025 75.545 126.975 75.825 ;
        RECT 127.145 75.555 127.335 75.995 ;
        RECT 127.505 75.615 128.575 75.785 ;
        RECT 125.205 74.895 125.375 75.075 ;
        RECT 122.485 74.075 122.880 74.245 ;
        RECT 123.050 74.115 123.515 74.505 ;
        RECT 123.685 74.725 125.375 74.895 ;
        RECT 122.710 73.945 122.880 74.075 ;
        RECT 123.685 73.945 123.855 74.725 ;
        RECT 125.545 74.555 125.715 75.245 ;
        RECT 124.215 74.385 125.715 74.555 ;
        RECT 125.905 74.585 126.115 75.375 ;
        RECT 126.285 74.755 126.635 75.375 ;
        RECT 126.805 74.765 126.975 75.545 ;
        RECT 127.505 75.385 127.675 75.615 ;
        RECT 127.145 75.215 127.675 75.385 ;
        RECT 127.145 74.935 127.365 75.215 ;
        RECT 127.845 75.045 128.085 75.445 ;
        RECT 126.805 74.595 127.210 74.765 ;
        RECT 127.545 74.675 128.085 75.045 ;
        RECT 128.255 75.260 128.575 75.615 ;
        RECT 128.820 75.535 129.125 75.995 ;
        RECT 129.295 75.285 129.550 75.815 ;
        RECT 128.255 75.085 128.580 75.260 ;
        RECT 128.255 74.785 129.170 75.085 ;
        RECT 128.430 74.755 129.170 74.785 ;
        RECT 125.905 74.425 126.580 74.585 ;
        RECT 127.040 74.505 127.210 74.595 ;
        RECT 125.905 74.415 126.870 74.425 ;
        RECT 125.545 74.245 125.715 74.385 ;
        RECT 122.290 73.445 122.540 73.905 ;
        RECT 122.710 73.615 122.960 73.945 ;
        RECT 123.175 73.615 123.855 73.945 ;
        RECT 124.025 74.045 125.100 74.215 ;
        RECT 125.545 74.075 126.105 74.245 ;
        RECT 126.410 74.125 126.870 74.415 ;
        RECT 127.040 74.335 128.260 74.505 ;
        RECT 124.025 73.705 124.195 74.045 ;
        RECT 124.430 73.445 124.760 73.875 ;
        RECT 124.930 73.705 125.100 74.045 ;
        RECT 125.395 73.445 125.765 73.905 ;
        RECT 125.935 73.615 126.105 74.075 ;
        RECT 127.040 73.955 127.210 74.335 ;
        RECT 128.430 74.165 128.600 74.755 ;
        RECT 129.340 74.635 129.550 75.285 ;
        RECT 126.340 73.615 127.210 73.955 ;
        RECT 127.800 73.995 128.600 74.165 ;
        RECT 127.380 73.445 127.630 73.905 ;
        RECT 127.800 73.705 127.970 73.995 ;
        RECT 128.150 73.445 128.480 73.825 ;
        RECT 128.820 73.445 129.125 74.585 ;
        RECT 129.295 73.755 129.550 74.635 ;
        RECT 129.730 75.255 129.985 75.825 ;
        RECT 130.155 75.595 130.485 75.995 ;
        RECT 130.910 75.460 131.440 75.825 ;
        RECT 130.910 75.425 131.085 75.460 ;
        RECT 130.155 75.255 131.085 75.425 ;
        RECT 129.730 74.585 129.900 75.255 ;
        RECT 130.155 75.085 130.325 75.255 ;
        RECT 130.070 74.755 130.325 75.085 ;
        RECT 130.550 74.755 130.745 75.085 ;
        RECT 129.730 73.615 130.065 74.585 ;
        RECT 130.235 73.445 130.405 74.585 ;
        RECT 130.575 73.785 130.745 74.755 ;
        RECT 130.915 74.125 131.085 75.255 ;
        RECT 131.255 74.465 131.425 75.265 ;
        RECT 131.630 74.975 131.905 75.825 ;
        RECT 131.625 74.805 131.905 74.975 ;
        RECT 131.630 74.665 131.905 74.805 ;
        RECT 132.075 74.465 132.265 75.825 ;
        RECT 132.445 75.460 132.955 75.995 ;
        RECT 133.175 75.185 133.420 75.790 ;
        RECT 134.790 75.445 135.045 75.735 ;
        RECT 135.215 75.615 135.545 75.995 ;
        RECT 134.790 75.275 135.540 75.445 ;
        RECT 132.465 75.015 133.695 75.185 ;
        RECT 131.255 74.295 132.265 74.465 ;
        RECT 132.435 74.450 133.185 74.640 ;
        RECT 130.915 73.955 132.040 74.125 ;
        RECT 132.435 73.785 132.605 74.450 ;
        RECT 133.355 74.205 133.695 75.015 ;
        RECT 134.790 74.455 135.140 75.105 ;
        RECT 135.310 74.285 135.540 75.275 ;
        RECT 130.575 73.615 132.605 73.785 ;
        RECT 132.775 73.445 132.945 74.205 ;
        RECT 133.180 73.795 133.695 74.205 ;
        RECT 134.790 74.115 135.540 74.285 ;
        RECT 134.790 73.615 135.045 74.115 ;
        RECT 135.215 73.445 135.545 73.945 ;
        RECT 135.715 73.615 135.885 75.735 ;
        RECT 136.245 75.635 136.575 75.995 ;
        RECT 136.745 75.605 137.240 75.775 ;
        RECT 137.445 75.605 138.300 75.775 ;
        RECT 136.115 74.415 136.575 75.465 ;
        RECT 136.055 73.630 136.380 74.415 ;
        RECT 136.745 74.245 136.915 75.605 ;
        RECT 137.085 74.695 137.435 75.315 ;
        RECT 137.605 75.095 137.960 75.315 ;
        RECT 137.605 74.505 137.775 75.095 ;
        RECT 138.130 74.895 138.300 75.605 ;
        RECT 139.175 75.535 139.505 75.995 ;
        RECT 139.715 75.635 140.065 75.805 ;
        RECT 138.505 75.065 139.295 75.315 ;
        RECT 139.715 75.245 139.975 75.635 ;
        RECT 140.285 75.545 141.235 75.825 ;
        RECT 141.405 75.555 141.595 75.995 ;
        RECT 141.765 75.615 142.835 75.785 ;
        RECT 139.465 74.895 139.635 75.075 ;
        RECT 136.745 74.075 137.140 74.245 ;
        RECT 137.310 74.115 137.775 74.505 ;
        RECT 137.945 74.725 139.635 74.895 ;
        RECT 136.970 73.945 137.140 74.075 ;
        RECT 137.945 73.945 138.115 74.725 ;
        RECT 139.805 74.555 139.975 75.245 ;
        RECT 138.475 74.385 139.975 74.555 ;
        RECT 140.165 74.585 140.375 75.375 ;
        RECT 140.545 74.755 140.895 75.375 ;
        RECT 141.065 74.765 141.235 75.545 ;
        RECT 141.765 75.385 141.935 75.615 ;
        RECT 141.405 75.215 141.935 75.385 ;
        RECT 141.405 74.935 141.625 75.215 ;
        RECT 142.105 75.045 142.345 75.445 ;
        RECT 141.065 74.595 141.470 74.765 ;
        RECT 141.805 74.675 142.345 75.045 ;
        RECT 142.515 75.260 142.835 75.615 ;
        RECT 143.080 75.535 143.385 75.995 ;
        RECT 143.555 75.285 143.810 75.815 ;
        RECT 142.515 75.085 142.840 75.260 ;
        RECT 142.515 74.785 143.430 75.085 ;
        RECT 142.690 74.755 143.430 74.785 ;
        RECT 140.165 74.425 140.840 74.585 ;
        RECT 141.300 74.505 141.470 74.595 ;
        RECT 140.165 74.415 141.130 74.425 ;
        RECT 139.805 74.245 139.975 74.385 ;
        RECT 136.550 73.445 136.800 73.905 ;
        RECT 136.970 73.615 137.220 73.945 ;
        RECT 137.435 73.615 138.115 73.945 ;
        RECT 138.285 74.045 139.360 74.215 ;
        RECT 139.805 74.075 140.365 74.245 ;
        RECT 140.670 74.125 141.130 74.415 ;
        RECT 141.300 74.335 142.520 74.505 ;
        RECT 138.285 73.705 138.455 74.045 ;
        RECT 138.690 73.445 139.020 73.875 ;
        RECT 139.190 73.705 139.360 74.045 ;
        RECT 139.655 73.445 140.025 73.905 ;
        RECT 140.195 73.615 140.365 74.075 ;
        RECT 141.300 73.955 141.470 74.335 ;
        RECT 142.690 74.165 142.860 74.755 ;
        RECT 143.600 74.635 143.810 75.285 ;
        RECT 144.905 75.270 145.195 75.995 ;
        RECT 145.455 75.445 145.625 75.825 ;
        RECT 145.840 75.615 146.170 75.995 ;
        RECT 145.455 75.275 146.170 75.445 ;
        RECT 145.365 74.725 145.720 75.095 ;
        RECT 146.000 75.085 146.170 75.275 ;
        RECT 146.340 75.250 146.595 75.825 ;
        RECT 146.000 74.755 146.255 75.085 ;
        RECT 140.600 73.615 141.470 73.955 ;
        RECT 142.060 73.995 142.860 74.165 ;
        RECT 141.640 73.445 141.890 73.905 ;
        RECT 142.060 73.705 142.230 73.995 ;
        RECT 142.410 73.445 142.740 73.825 ;
        RECT 143.080 73.445 143.385 74.585 ;
        RECT 143.555 73.755 143.810 74.635 ;
        RECT 144.905 73.445 145.195 74.610 ;
        RECT 146.000 74.545 146.170 74.755 ;
        RECT 145.455 74.375 146.170 74.545 ;
        RECT 146.425 74.520 146.595 75.250 ;
        RECT 146.770 75.155 147.030 75.995 ;
        RECT 147.665 75.245 148.875 75.995 ;
        RECT 145.455 73.615 145.625 74.375 ;
        RECT 145.840 73.445 146.170 74.205 ;
        RECT 146.340 73.615 146.595 74.520 ;
        RECT 146.770 73.445 147.030 74.595 ;
        RECT 147.665 74.535 148.185 75.075 ;
        RECT 148.355 74.705 148.875 75.245 ;
        RECT 147.665 73.445 148.875 74.535 ;
        RECT 119.060 73.275 148.960 73.445 ;
        RECT 119.145 72.185 120.355 73.275 ;
        RECT 120.525 72.185 123.115 73.275 ;
        RECT 119.145 71.475 119.665 72.015 ;
        RECT 119.835 71.645 120.355 72.185 ;
        RECT 120.525 71.495 121.735 72.015 ;
        RECT 121.905 71.665 123.115 72.185 ;
        RECT 123.290 72.135 123.625 73.105 ;
        RECT 123.795 72.135 123.965 73.275 ;
        RECT 124.135 72.935 126.165 73.105 ;
        RECT 119.145 70.725 120.355 71.475 ;
        RECT 120.525 70.725 123.115 71.495 ;
        RECT 123.290 71.465 123.460 72.135 ;
        RECT 124.135 71.965 124.305 72.935 ;
        RECT 123.630 71.635 123.885 71.965 ;
        RECT 124.110 71.635 124.305 71.965 ;
        RECT 124.475 72.595 125.600 72.765 ;
        RECT 123.715 71.465 123.885 71.635 ;
        RECT 124.475 71.465 124.645 72.595 ;
        RECT 123.290 70.895 123.545 71.465 ;
        RECT 123.715 71.295 124.645 71.465 ;
        RECT 124.815 72.255 125.825 72.425 ;
        RECT 124.815 71.455 124.985 72.255 ;
        RECT 125.190 71.575 125.465 72.055 ;
        RECT 125.185 71.405 125.465 71.575 ;
        RECT 124.470 71.260 124.645 71.295 ;
        RECT 123.715 70.725 124.045 71.125 ;
        RECT 124.470 70.895 125.000 71.260 ;
        RECT 125.190 70.895 125.465 71.405 ;
        RECT 125.635 70.895 125.825 72.255 ;
        RECT 125.995 72.270 126.165 72.935 ;
        RECT 126.335 72.515 126.505 73.275 ;
        RECT 126.740 72.515 127.255 72.925 ;
        RECT 125.995 72.080 126.745 72.270 ;
        RECT 126.915 71.705 127.255 72.515 ;
        RECT 126.025 71.535 127.255 71.705 ;
        RECT 127.425 72.135 127.810 73.105 ;
        RECT 127.980 72.815 128.305 73.275 ;
        RECT 128.825 72.645 129.105 73.105 ;
        RECT 127.980 72.425 129.105 72.645 ;
        RECT 126.005 70.725 126.515 71.260 ;
        RECT 126.735 70.930 126.980 71.535 ;
        RECT 127.425 71.465 127.705 72.135 ;
        RECT 127.980 71.965 128.430 72.425 ;
        RECT 129.295 72.255 129.695 73.105 ;
        RECT 130.095 72.815 130.365 73.275 ;
        RECT 130.535 72.645 130.820 73.105 ;
        RECT 127.875 71.635 128.430 71.965 ;
        RECT 128.600 71.695 129.695 72.255 ;
        RECT 127.980 71.525 128.430 71.635 ;
        RECT 127.425 70.895 127.810 71.465 ;
        RECT 127.980 71.355 129.105 71.525 ;
        RECT 127.980 70.725 128.305 71.185 ;
        RECT 128.825 70.895 129.105 71.355 ;
        RECT 129.295 70.895 129.695 71.695 ;
        RECT 129.865 72.425 130.820 72.645 ;
        RECT 129.865 71.525 130.075 72.425 ;
        RECT 130.245 71.695 130.935 72.255 ;
        RECT 132.025 72.110 132.315 73.275 ;
        RECT 132.485 72.185 133.695 73.275 ;
        RECT 133.980 72.645 134.265 73.105 ;
        RECT 134.435 72.815 134.705 73.275 ;
        RECT 133.980 72.425 134.935 72.645 ;
        RECT 129.865 71.355 130.820 71.525 ;
        RECT 132.485 71.475 133.005 72.015 ;
        RECT 133.175 71.645 133.695 72.185 ;
        RECT 133.865 71.695 134.555 72.255 ;
        RECT 134.725 71.525 134.935 72.425 ;
        RECT 130.095 70.725 130.365 71.185 ;
        RECT 130.535 70.895 130.820 71.355 ;
        RECT 132.025 70.725 132.315 71.450 ;
        RECT 132.485 70.725 133.695 71.475 ;
        RECT 133.980 71.355 134.935 71.525 ;
        RECT 135.105 72.255 135.505 73.105 ;
        RECT 135.695 72.645 135.975 73.105 ;
        RECT 136.495 72.815 136.820 73.275 ;
        RECT 135.695 72.425 136.820 72.645 ;
        RECT 135.105 71.695 136.200 72.255 ;
        RECT 136.370 71.965 136.820 72.425 ;
        RECT 136.990 72.135 137.375 73.105 ;
        RECT 137.550 72.605 137.805 73.105 ;
        RECT 137.975 72.775 138.305 73.275 ;
        RECT 137.550 72.435 138.300 72.605 ;
        RECT 133.980 70.895 134.265 71.355 ;
        RECT 134.435 70.725 134.705 71.185 ;
        RECT 135.105 70.895 135.505 71.695 ;
        RECT 136.370 71.635 136.925 71.965 ;
        RECT 136.370 71.525 136.820 71.635 ;
        RECT 135.695 71.355 136.820 71.525 ;
        RECT 137.095 71.465 137.375 72.135 ;
        RECT 137.550 71.615 137.900 72.265 ;
        RECT 135.695 70.895 135.975 71.355 ;
        RECT 136.495 70.725 136.820 71.185 ;
        RECT 136.990 70.895 137.375 71.465 ;
        RECT 138.070 71.445 138.300 72.435 ;
        RECT 137.550 71.275 138.300 71.445 ;
        RECT 137.550 70.985 137.805 71.275 ;
        RECT 137.975 70.725 138.305 71.105 ;
        RECT 138.475 70.985 138.645 73.105 ;
        RECT 138.815 72.305 139.140 73.090 ;
        RECT 139.310 72.815 139.560 73.275 ;
        RECT 139.730 72.775 139.980 73.105 ;
        RECT 140.195 72.775 140.875 73.105 ;
        RECT 139.730 72.645 139.900 72.775 ;
        RECT 139.505 72.475 139.900 72.645 ;
        RECT 138.875 71.255 139.335 72.305 ;
        RECT 139.505 71.115 139.675 72.475 ;
        RECT 140.070 72.215 140.535 72.605 ;
        RECT 139.845 71.405 140.195 72.025 ;
        RECT 140.365 71.625 140.535 72.215 ;
        RECT 140.705 71.995 140.875 72.775 ;
        RECT 141.045 72.675 141.215 73.015 ;
        RECT 141.450 72.845 141.780 73.275 ;
        RECT 141.950 72.675 142.120 73.015 ;
        RECT 142.415 72.815 142.785 73.275 ;
        RECT 141.045 72.505 142.120 72.675 ;
        RECT 142.955 72.645 143.125 73.105 ;
        RECT 143.360 72.765 144.230 73.105 ;
        RECT 144.400 72.815 144.650 73.275 ;
        RECT 142.565 72.475 143.125 72.645 ;
        RECT 142.565 72.335 142.735 72.475 ;
        RECT 141.235 72.165 142.735 72.335 ;
        RECT 143.430 72.305 143.890 72.595 ;
        RECT 140.705 71.825 142.395 71.995 ;
        RECT 140.365 71.405 140.720 71.625 ;
        RECT 140.890 71.115 141.060 71.825 ;
        RECT 141.265 71.405 142.055 71.655 ;
        RECT 142.225 71.645 142.395 71.825 ;
        RECT 142.565 71.475 142.735 72.165 ;
        RECT 139.005 70.725 139.335 71.085 ;
        RECT 139.505 70.945 140.000 71.115 ;
        RECT 140.205 70.945 141.060 71.115 ;
        RECT 141.935 70.725 142.265 71.185 ;
        RECT 142.475 71.085 142.735 71.475 ;
        RECT 142.925 72.295 143.890 72.305 ;
        RECT 144.060 72.385 144.230 72.765 ;
        RECT 144.820 72.725 144.990 73.015 ;
        RECT 145.170 72.895 145.500 73.275 ;
        RECT 144.820 72.555 145.620 72.725 ;
        RECT 142.925 72.135 143.600 72.295 ;
        RECT 144.060 72.215 145.280 72.385 ;
        RECT 142.925 71.345 143.135 72.135 ;
        RECT 144.060 72.125 144.230 72.215 ;
        RECT 143.305 71.345 143.655 71.965 ;
        RECT 143.825 71.955 144.230 72.125 ;
        RECT 143.825 71.175 143.995 71.955 ;
        RECT 144.165 71.505 144.385 71.785 ;
        RECT 144.565 71.675 145.105 72.045 ;
        RECT 145.450 71.965 145.620 72.555 ;
        RECT 145.840 72.135 146.145 73.275 ;
        RECT 146.315 72.085 146.570 72.965 ;
        RECT 145.450 71.935 146.190 71.965 ;
        RECT 144.165 71.335 144.695 71.505 ;
        RECT 142.475 70.915 142.825 71.085 ;
        RECT 143.045 70.895 143.995 71.175 ;
        RECT 144.165 70.725 144.355 71.165 ;
        RECT 144.525 71.105 144.695 71.335 ;
        RECT 144.865 71.275 145.105 71.675 ;
        RECT 145.275 71.635 146.190 71.935 ;
        RECT 145.275 71.460 145.600 71.635 ;
        RECT 145.275 71.105 145.595 71.460 ;
        RECT 146.360 71.435 146.570 72.085 ;
        RECT 147.665 72.185 148.875 73.275 ;
        RECT 147.665 71.645 148.185 72.185 ;
        RECT 148.355 71.475 148.875 72.015 ;
        RECT 144.525 70.935 145.595 71.105 ;
        RECT 145.840 70.725 146.145 71.185 ;
        RECT 146.315 70.905 146.570 71.435 ;
        RECT 147.665 70.725 148.875 71.475 ;
        RECT 119.060 70.555 148.960 70.725 ;
        RECT 119.145 69.805 120.355 70.555 ;
        RECT 120.530 70.005 120.785 70.295 ;
        RECT 120.955 70.175 121.285 70.555 ;
        RECT 120.530 69.835 121.280 70.005 ;
        RECT 119.145 69.265 119.665 69.805 ;
        RECT 119.835 69.095 120.355 69.635 ;
        RECT 119.145 68.005 120.355 69.095 ;
        RECT 120.530 69.015 120.880 69.665 ;
        RECT 121.050 68.845 121.280 69.835 ;
        RECT 120.530 68.675 121.280 68.845 ;
        RECT 120.530 68.175 120.785 68.675 ;
        RECT 120.955 68.005 121.285 68.505 ;
        RECT 121.455 68.175 121.625 70.295 ;
        RECT 121.985 70.195 122.315 70.555 ;
        RECT 122.485 70.165 122.980 70.335 ;
        RECT 123.185 70.165 124.040 70.335 ;
        RECT 121.855 68.975 122.315 70.025 ;
        RECT 121.795 68.190 122.120 68.975 ;
        RECT 122.485 68.805 122.655 70.165 ;
        RECT 122.825 69.255 123.175 69.875 ;
        RECT 123.345 69.655 123.700 69.875 ;
        RECT 123.345 69.065 123.515 69.655 ;
        RECT 123.870 69.455 124.040 70.165 ;
        RECT 124.915 70.095 125.245 70.555 ;
        RECT 125.455 70.195 125.805 70.365 ;
        RECT 124.245 69.625 125.035 69.875 ;
        RECT 125.455 69.805 125.715 70.195 ;
        RECT 126.025 70.105 126.975 70.385 ;
        RECT 127.145 70.115 127.335 70.555 ;
        RECT 127.505 70.175 128.575 70.345 ;
        RECT 125.205 69.455 125.375 69.635 ;
        RECT 122.485 68.635 122.880 68.805 ;
        RECT 123.050 68.675 123.515 69.065 ;
        RECT 123.685 69.285 125.375 69.455 ;
        RECT 122.710 68.505 122.880 68.635 ;
        RECT 123.685 68.505 123.855 69.285 ;
        RECT 125.545 69.115 125.715 69.805 ;
        RECT 124.215 68.945 125.715 69.115 ;
        RECT 125.905 69.145 126.115 69.935 ;
        RECT 126.285 69.315 126.635 69.935 ;
        RECT 126.805 69.325 126.975 70.105 ;
        RECT 127.505 69.945 127.675 70.175 ;
        RECT 127.145 69.775 127.675 69.945 ;
        RECT 127.145 69.495 127.365 69.775 ;
        RECT 127.845 69.605 128.085 70.005 ;
        RECT 126.805 69.155 127.210 69.325 ;
        RECT 127.545 69.235 128.085 69.605 ;
        RECT 128.255 69.820 128.575 70.175 ;
        RECT 128.820 70.095 129.125 70.555 ;
        RECT 129.295 69.845 129.550 70.375 ;
        RECT 129.725 70.010 135.070 70.555 ;
        RECT 128.255 69.645 128.580 69.820 ;
        RECT 128.255 69.345 129.170 69.645 ;
        RECT 128.430 69.315 129.170 69.345 ;
        RECT 125.905 68.985 126.580 69.145 ;
        RECT 127.040 69.065 127.210 69.155 ;
        RECT 125.905 68.975 126.870 68.985 ;
        RECT 125.545 68.805 125.715 68.945 ;
        RECT 122.290 68.005 122.540 68.465 ;
        RECT 122.710 68.175 122.960 68.505 ;
        RECT 123.175 68.175 123.855 68.505 ;
        RECT 124.025 68.605 125.100 68.775 ;
        RECT 125.545 68.635 126.105 68.805 ;
        RECT 126.410 68.685 126.870 68.975 ;
        RECT 127.040 68.895 128.260 69.065 ;
        RECT 124.025 68.265 124.195 68.605 ;
        RECT 124.430 68.005 124.760 68.435 ;
        RECT 124.930 68.265 125.100 68.605 ;
        RECT 125.395 68.005 125.765 68.465 ;
        RECT 125.935 68.175 126.105 68.635 ;
        RECT 127.040 68.515 127.210 68.895 ;
        RECT 128.430 68.725 128.600 69.315 ;
        RECT 129.340 69.195 129.550 69.845 ;
        RECT 126.340 68.175 127.210 68.515 ;
        RECT 127.800 68.555 128.600 68.725 ;
        RECT 127.380 68.005 127.630 68.465 ;
        RECT 127.800 68.265 127.970 68.555 ;
        RECT 128.150 68.005 128.480 68.385 ;
        RECT 128.820 68.005 129.125 69.145 ;
        RECT 129.295 68.315 129.550 69.195 ;
        RECT 131.310 69.180 131.650 70.010 ;
        RECT 135.245 69.785 137.835 70.555 ;
        RECT 138.470 69.815 138.725 70.385 ;
        RECT 138.895 70.155 139.225 70.555 ;
        RECT 139.650 70.020 140.180 70.385 ;
        RECT 140.370 70.215 140.645 70.385 ;
        RECT 140.365 70.045 140.645 70.215 ;
        RECT 139.650 69.985 139.825 70.020 ;
        RECT 138.895 69.815 139.825 69.985 ;
        RECT 133.130 68.440 133.480 69.690 ;
        RECT 135.245 69.265 136.455 69.785 ;
        RECT 136.625 69.095 137.835 69.615 ;
        RECT 129.725 68.005 135.070 68.440 ;
        RECT 135.245 68.005 137.835 69.095 ;
        RECT 138.470 69.145 138.640 69.815 ;
        RECT 138.895 69.645 139.065 69.815 ;
        RECT 138.810 69.315 139.065 69.645 ;
        RECT 139.290 69.315 139.485 69.645 ;
        RECT 138.470 68.175 138.805 69.145 ;
        RECT 138.975 68.005 139.145 69.145 ;
        RECT 139.315 68.345 139.485 69.315 ;
        RECT 139.655 68.685 139.825 69.815 ;
        RECT 139.995 69.025 140.165 69.825 ;
        RECT 140.370 69.225 140.645 70.045 ;
        RECT 140.815 69.025 141.005 70.385 ;
        RECT 141.185 70.020 141.695 70.555 ;
        RECT 141.915 69.745 142.160 70.350 ;
        RECT 142.605 69.785 144.275 70.555 ;
        RECT 144.905 69.830 145.195 70.555 ;
        RECT 145.365 69.785 147.035 70.555 ;
        RECT 147.665 69.805 148.875 70.555 ;
        RECT 141.205 69.575 142.435 69.745 ;
        RECT 139.995 68.855 141.005 69.025 ;
        RECT 141.175 69.010 141.925 69.200 ;
        RECT 139.655 68.515 140.780 68.685 ;
        RECT 141.175 68.345 141.345 69.010 ;
        RECT 142.095 68.765 142.435 69.575 ;
        RECT 142.605 69.265 143.355 69.785 ;
        RECT 143.525 69.095 144.275 69.615 ;
        RECT 145.365 69.265 146.115 69.785 ;
        RECT 139.315 68.175 141.345 68.345 ;
        RECT 141.515 68.005 141.685 68.765 ;
        RECT 141.920 68.355 142.435 68.765 ;
        RECT 142.605 68.005 144.275 69.095 ;
        RECT 144.905 68.005 145.195 69.170 ;
        RECT 146.285 69.095 147.035 69.615 ;
        RECT 145.365 68.005 147.035 69.095 ;
        RECT 147.665 69.095 148.185 69.635 ;
        RECT 148.355 69.265 148.875 69.805 ;
        RECT 147.665 68.005 148.875 69.095 ;
        RECT 119.060 67.835 148.960 68.005 ;
        RECT 119.145 66.745 120.355 67.835 ;
        RECT 120.990 67.165 121.245 67.665 ;
        RECT 121.415 67.335 121.745 67.835 ;
        RECT 120.990 66.995 121.740 67.165 ;
        RECT 119.145 66.035 119.665 66.575 ;
        RECT 119.835 66.205 120.355 66.745 ;
        RECT 120.990 66.175 121.340 66.825 ;
        RECT 119.145 65.285 120.355 66.035 ;
        RECT 121.510 66.005 121.740 66.995 ;
        RECT 120.990 65.835 121.740 66.005 ;
        RECT 120.990 65.545 121.245 65.835 ;
        RECT 121.415 65.285 121.745 65.665 ;
        RECT 121.915 65.545 122.085 67.665 ;
        RECT 122.255 66.865 122.580 67.650 ;
        RECT 122.750 67.375 123.000 67.835 ;
        RECT 123.170 67.335 123.420 67.665 ;
        RECT 123.635 67.335 124.315 67.665 ;
        RECT 123.170 67.205 123.340 67.335 ;
        RECT 122.945 67.035 123.340 67.205 ;
        RECT 122.315 65.815 122.775 66.865 ;
        RECT 122.945 65.675 123.115 67.035 ;
        RECT 123.510 66.775 123.975 67.165 ;
        RECT 123.285 65.965 123.635 66.585 ;
        RECT 123.805 66.185 123.975 66.775 ;
        RECT 124.145 66.555 124.315 67.335 ;
        RECT 124.485 67.235 124.655 67.575 ;
        RECT 124.890 67.405 125.220 67.835 ;
        RECT 125.390 67.235 125.560 67.575 ;
        RECT 125.855 67.375 126.225 67.835 ;
        RECT 124.485 67.065 125.560 67.235 ;
        RECT 126.395 67.205 126.565 67.665 ;
        RECT 126.800 67.325 127.670 67.665 ;
        RECT 127.840 67.375 128.090 67.835 ;
        RECT 126.005 67.035 126.565 67.205 ;
        RECT 126.005 66.895 126.175 67.035 ;
        RECT 124.675 66.725 126.175 66.895 ;
        RECT 126.870 66.865 127.330 67.155 ;
        RECT 124.145 66.385 125.835 66.555 ;
        RECT 123.805 65.965 124.160 66.185 ;
        RECT 124.330 65.675 124.500 66.385 ;
        RECT 124.705 65.965 125.495 66.215 ;
        RECT 125.665 66.205 125.835 66.385 ;
        RECT 126.005 66.035 126.175 66.725 ;
        RECT 122.445 65.285 122.775 65.645 ;
        RECT 122.945 65.505 123.440 65.675 ;
        RECT 123.645 65.505 124.500 65.675 ;
        RECT 125.375 65.285 125.705 65.745 ;
        RECT 125.915 65.645 126.175 66.035 ;
        RECT 126.365 66.855 127.330 66.865 ;
        RECT 127.500 66.945 127.670 67.325 ;
        RECT 128.260 67.285 128.430 67.575 ;
        RECT 128.610 67.455 128.940 67.835 ;
        RECT 128.260 67.115 129.060 67.285 ;
        RECT 126.365 66.695 127.040 66.855 ;
        RECT 127.500 66.775 128.720 66.945 ;
        RECT 126.365 65.905 126.575 66.695 ;
        RECT 127.500 66.685 127.670 66.775 ;
        RECT 126.745 65.905 127.095 66.525 ;
        RECT 127.265 66.515 127.670 66.685 ;
        RECT 127.265 65.735 127.435 66.515 ;
        RECT 127.605 66.065 127.825 66.345 ;
        RECT 128.005 66.235 128.545 66.605 ;
        RECT 128.890 66.525 129.060 67.115 ;
        RECT 129.280 66.695 129.585 67.835 ;
        RECT 129.755 66.645 130.010 67.525 ;
        RECT 130.185 66.745 131.855 67.835 ;
        RECT 128.890 66.495 129.630 66.525 ;
        RECT 127.605 65.895 128.135 66.065 ;
        RECT 125.915 65.475 126.265 65.645 ;
        RECT 126.485 65.455 127.435 65.735 ;
        RECT 127.605 65.285 127.795 65.725 ;
        RECT 127.965 65.665 128.135 65.895 ;
        RECT 128.305 65.835 128.545 66.235 ;
        RECT 128.715 66.195 129.630 66.495 ;
        RECT 128.715 66.020 129.040 66.195 ;
        RECT 128.715 65.665 129.035 66.020 ;
        RECT 129.800 65.995 130.010 66.645 ;
        RECT 127.965 65.495 129.035 65.665 ;
        RECT 129.280 65.285 129.585 65.745 ;
        RECT 129.755 65.465 130.010 65.995 ;
        RECT 130.185 66.055 130.935 66.575 ;
        RECT 131.105 66.225 131.855 66.745 ;
        RECT 132.025 66.670 132.315 67.835 ;
        RECT 132.495 67.025 132.790 67.835 ;
        RECT 132.970 66.525 133.215 67.665 ;
        RECT 133.390 67.025 133.650 67.835 ;
        RECT 134.250 67.830 140.525 67.835 ;
        RECT 133.830 66.525 134.080 67.660 ;
        RECT 134.250 67.035 134.510 67.830 ;
        RECT 134.680 66.935 134.940 67.660 ;
        RECT 135.110 67.105 135.370 67.830 ;
        RECT 135.540 66.935 135.800 67.660 ;
        RECT 135.970 67.105 136.230 67.830 ;
        RECT 136.400 66.935 136.660 67.660 ;
        RECT 136.830 67.105 137.090 67.830 ;
        RECT 137.260 66.935 137.520 67.660 ;
        RECT 137.690 67.105 137.935 67.830 ;
        RECT 138.105 66.935 138.365 67.660 ;
        RECT 138.550 67.105 138.795 67.830 ;
        RECT 138.965 66.935 139.225 67.660 ;
        RECT 139.410 67.105 139.655 67.830 ;
        RECT 139.825 66.935 140.085 67.660 ;
        RECT 140.270 67.105 140.525 67.830 ;
        RECT 134.680 66.920 140.085 66.935 ;
        RECT 140.695 66.920 140.985 67.660 ;
        RECT 141.155 67.090 141.425 67.835 ;
        RECT 134.680 66.695 141.425 66.920 ;
        RECT 130.185 65.285 131.855 66.055 ;
        RECT 132.025 65.285 132.315 66.010 ;
        RECT 132.485 65.965 132.800 66.525 ;
        RECT 132.970 66.275 140.090 66.525 ;
        RECT 132.485 65.285 132.790 65.795 ;
        RECT 132.970 65.465 133.220 66.275 ;
        RECT 133.390 65.285 133.650 65.810 ;
        RECT 133.830 65.465 134.080 66.275 ;
        RECT 140.260 66.105 141.425 66.695 ;
        RECT 134.680 65.935 141.425 66.105 ;
        RECT 141.690 66.695 142.025 67.665 ;
        RECT 142.195 66.695 142.365 67.835 ;
        RECT 142.535 67.495 144.565 67.665 ;
        RECT 141.690 66.025 141.860 66.695 ;
        RECT 142.535 66.525 142.705 67.495 ;
        RECT 142.030 66.195 142.285 66.525 ;
        RECT 142.510 66.195 142.705 66.525 ;
        RECT 142.875 67.155 144.000 67.325 ;
        RECT 142.115 66.025 142.285 66.195 ;
        RECT 142.875 66.025 143.045 67.155 ;
        RECT 134.250 65.285 134.510 65.845 ;
        RECT 134.680 65.480 134.940 65.935 ;
        RECT 135.110 65.285 135.370 65.765 ;
        RECT 135.540 65.480 135.800 65.935 ;
        RECT 135.970 65.285 136.230 65.765 ;
        RECT 136.400 65.480 136.660 65.935 ;
        RECT 136.830 65.285 137.075 65.765 ;
        RECT 137.245 65.480 137.520 65.935 ;
        RECT 137.690 65.285 137.935 65.765 ;
        RECT 138.105 65.480 138.365 65.935 ;
        RECT 138.545 65.285 138.795 65.765 ;
        RECT 138.965 65.480 139.225 65.935 ;
        RECT 139.405 65.285 139.655 65.765 ;
        RECT 139.825 65.480 140.085 65.935 ;
        RECT 140.265 65.285 140.525 65.765 ;
        RECT 140.695 65.480 140.955 65.935 ;
        RECT 141.125 65.285 141.425 65.765 ;
        RECT 141.690 65.455 141.945 66.025 ;
        RECT 142.115 65.855 143.045 66.025 ;
        RECT 143.215 66.815 144.225 66.985 ;
        RECT 143.215 66.015 143.385 66.815 ;
        RECT 143.590 66.135 143.865 66.615 ;
        RECT 143.585 65.965 143.865 66.135 ;
        RECT 142.870 65.820 143.045 65.855 ;
        RECT 142.115 65.285 142.445 65.685 ;
        RECT 142.870 65.455 143.400 65.820 ;
        RECT 143.590 65.455 143.865 65.965 ;
        RECT 144.035 65.455 144.225 66.815 ;
        RECT 144.395 66.830 144.565 67.495 ;
        RECT 144.735 67.075 144.905 67.835 ;
        RECT 145.140 67.075 145.655 67.485 ;
        RECT 144.395 66.640 145.145 66.830 ;
        RECT 145.315 66.265 145.655 67.075 ;
        RECT 145.825 66.745 147.495 67.835 ;
        RECT 144.425 66.095 145.655 66.265 ;
        RECT 144.405 65.285 144.915 65.820 ;
        RECT 145.135 65.490 145.380 66.095 ;
        RECT 145.825 66.055 146.575 66.575 ;
        RECT 146.745 66.225 147.495 66.745 ;
        RECT 147.665 66.745 148.875 67.835 ;
        RECT 147.665 66.205 148.185 66.745 ;
        RECT 145.825 65.285 147.495 66.055 ;
        RECT 148.355 66.035 148.875 66.575 ;
        RECT 147.665 65.285 148.875 66.035 ;
        RECT 119.060 65.115 148.960 65.285 ;
        RECT 119.145 64.365 120.355 65.115 ;
        RECT 120.525 64.615 120.785 64.945 ;
        RECT 120.995 64.635 121.270 65.115 ;
        RECT 119.145 63.825 119.665 64.365 ;
        RECT 119.835 63.655 120.355 64.195 ;
        RECT 119.145 62.565 120.355 63.655 ;
        RECT 120.525 63.705 120.695 64.615 ;
        RECT 121.480 64.545 121.685 64.945 ;
        RECT 121.855 64.715 122.190 65.115 ;
        RECT 120.865 63.875 121.225 64.455 ;
        RECT 121.480 64.375 122.165 64.545 ;
        RECT 121.405 63.705 121.655 64.205 ;
        RECT 120.525 63.535 121.655 63.705 ;
        RECT 120.525 62.765 120.795 63.535 ;
        RECT 121.825 63.345 122.165 64.375 ;
        RECT 122.365 64.345 124.955 65.115 ;
        RECT 125.130 64.375 125.385 64.945 ;
        RECT 125.555 64.715 125.885 65.115 ;
        RECT 126.310 64.580 126.840 64.945 ;
        RECT 126.310 64.545 126.485 64.580 ;
        RECT 125.555 64.375 126.485 64.545 ;
        RECT 122.365 63.825 123.575 64.345 ;
        RECT 123.745 63.655 124.955 64.175 ;
        RECT 120.965 62.565 121.295 63.345 ;
        RECT 121.500 63.170 122.165 63.345 ;
        RECT 121.500 62.765 121.685 63.170 ;
        RECT 121.855 62.565 122.190 62.990 ;
        RECT 122.365 62.565 124.955 63.655 ;
        RECT 125.130 63.705 125.300 64.375 ;
        RECT 125.555 64.205 125.725 64.375 ;
        RECT 125.470 63.875 125.725 64.205 ;
        RECT 125.950 63.875 126.145 64.205 ;
        RECT 125.130 62.735 125.465 63.705 ;
        RECT 125.635 62.565 125.805 63.705 ;
        RECT 125.975 62.905 126.145 63.875 ;
        RECT 126.315 63.245 126.485 64.375 ;
        RECT 126.655 63.585 126.825 64.385 ;
        RECT 127.030 64.095 127.305 64.945 ;
        RECT 127.025 63.925 127.305 64.095 ;
        RECT 127.030 63.785 127.305 63.925 ;
        RECT 127.475 63.585 127.665 64.945 ;
        RECT 127.845 64.580 128.355 65.115 ;
        RECT 128.575 64.305 128.820 64.910 ;
        RECT 129.265 64.375 129.650 64.945 ;
        RECT 129.820 64.655 130.145 65.115 ;
        RECT 130.665 64.485 130.945 64.945 ;
        RECT 127.865 64.135 129.095 64.305 ;
        RECT 126.655 63.415 127.665 63.585 ;
        RECT 127.835 63.570 128.585 63.760 ;
        RECT 126.315 63.075 127.440 63.245 ;
        RECT 127.835 62.905 128.005 63.570 ;
        RECT 128.755 63.325 129.095 64.135 ;
        RECT 125.975 62.735 128.005 62.905 ;
        RECT 128.175 62.565 128.345 63.325 ;
        RECT 128.580 62.915 129.095 63.325 ;
        RECT 129.265 63.705 129.545 64.375 ;
        RECT 129.820 64.315 130.945 64.485 ;
        RECT 129.820 64.205 130.270 64.315 ;
        RECT 129.715 63.875 130.270 64.205 ;
        RECT 131.135 64.145 131.535 64.945 ;
        RECT 131.935 64.655 132.205 65.115 ;
        RECT 132.375 64.485 132.660 64.945 ;
        RECT 129.265 62.735 129.650 63.705 ;
        RECT 129.820 63.415 130.270 63.875 ;
        RECT 130.440 63.585 131.535 64.145 ;
        RECT 129.820 63.195 130.945 63.415 ;
        RECT 129.820 62.565 130.145 63.025 ;
        RECT 130.665 62.735 130.945 63.195 ;
        RECT 131.135 62.735 131.535 63.585 ;
        RECT 131.705 64.315 132.660 64.485 ;
        RECT 132.945 64.345 136.455 65.115 ;
        RECT 136.625 64.365 137.835 65.115 ;
        RECT 138.015 64.390 138.345 64.900 ;
        RECT 138.515 64.715 138.845 65.115 ;
        RECT 139.895 64.545 140.225 64.885 ;
        RECT 140.395 64.715 140.725 65.115 ;
        RECT 131.705 63.415 131.915 64.315 ;
        RECT 132.085 63.585 132.775 64.145 ;
        RECT 132.945 63.825 134.595 64.345 ;
        RECT 134.765 63.655 136.455 64.175 ;
        RECT 136.625 63.825 137.145 64.365 ;
        RECT 137.315 63.655 137.835 64.195 ;
        RECT 131.705 63.195 132.660 63.415 ;
        RECT 131.935 62.565 132.205 63.025 ;
        RECT 132.375 62.735 132.660 63.195 ;
        RECT 132.945 62.565 136.455 63.655 ;
        RECT 136.625 62.565 137.835 63.655 ;
        RECT 138.015 63.625 138.205 64.390 ;
        RECT 138.515 64.375 140.880 64.545 ;
        RECT 138.515 64.205 138.685 64.375 ;
        RECT 138.375 63.875 138.685 64.205 ;
        RECT 138.855 63.875 139.160 64.205 ;
        RECT 138.015 62.775 138.345 63.625 ;
        RECT 138.515 62.565 138.765 63.705 ;
        RECT 138.945 63.545 139.160 63.875 ;
        RECT 139.335 63.545 139.620 64.205 ;
        RECT 139.815 63.545 140.080 64.205 ;
        RECT 140.295 63.545 140.540 64.205 ;
        RECT 140.710 63.375 140.880 64.375 ;
        RECT 138.955 63.205 140.245 63.375 ;
        RECT 138.955 62.785 139.205 63.205 ;
        RECT 139.435 62.565 139.765 63.035 ;
        RECT 139.995 62.785 140.245 63.205 ;
        RECT 140.425 63.205 140.880 63.375 ;
        RECT 141.225 64.375 141.610 64.945 ;
        RECT 141.780 64.655 142.105 65.115 ;
        RECT 142.625 64.485 142.905 64.945 ;
        RECT 141.225 63.705 141.505 64.375 ;
        RECT 141.780 64.315 142.905 64.485 ;
        RECT 141.780 64.205 142.230 64.315 ;
        RECT 141.675 63.875 142.230 64.205 ;
        RECT 143.095 64.145 143.495 64.945 ;
        RECT 143.895 64.655 144.165 65.115 ;
        RECT 144.335 64.485 144.620 64.945 ;
        RECT 140.425 62.775 140.755 63.205 ;
        RECT 141.225 62.735 141.610 63.705 ;
        RECT 141.780 63.415 142.230 63.875 ;
        RECT 142.400 63.585 143.495 64.145 ;
        RECT 141.780 63.195 142.905 63.415 ;
        RECT 141.780 62.565 142.105 63.025 ;
        RECT 142.625 62.735 142.905 63.195 ;
        RECT 143.095 62.735 143.495 63.585 ;
        RECT 143.665 64.315 144.620 64.485 ;
        RECT 144.905 64.390 145.195 65.115 ;
        RECT 145.365 64.345 147.035 65.115 ;
        RECT 147.665 64.365 148.875 65.115 ;
        RECT 143.665 63.415 143.875 64.315 ;
        RECT 144.045 63.585 144.735 64.145 ;
        RECT 145.365 63.825 146.115 64.345 ;
        RECT 143.665 63.195 144.620 63.415 ;
        RECT 143.895 62.565 144.165 63.025 ;
        RECT 144.335 62.735 144.620 63.195 ;
        RECT 144.905 62.565 145.195 63.730 ;
        RECT 146.285 63.655 147.035 64.175 ;
        RECT 145.365 62.565 147.035 63.655 ;
        RECT 147.665 63.655 148.185 64.195 ;
        RECT 148.355 63.825 148.875 64.365 ;
        RECT 147.665 62.565 148.875 63.655 ;
        RECT 119.060 62.395 148.960 62.565 ;
        RECT 119.145 61.305 120.355 62.395 ;
        RECT 120.525 61.960 125.870 62.395 ;
        RECT 126.045 61.960 131.390 62.395 ;
        RECT 119.145 60.595 119.665 61.135 ;
        RECT 119.835 60.765 120.355 61.305 ;
        RECT 119.145 59.845 120.355 60.595 ;
        RECT 122.110 60.390 122.450 61.220 ;
        RECT 123.930 60.710 124.280 61.960 ;
        RECT 127.630 60.390 127.970 61.220 ;
        RECT 129.450 60.710 129.800 61.960 ;
        RECT 132.025 61.230 132.315 62.395 ;
        RECT 132.485 61.305 135.995 62.395 ;
        RECT 137.090 61.725 137.345 62.225 ;
        RECT 137.515 61.895 137.845 62.395 ;
        RECT 137.090 61.555 137.840 61.725 ;
        RECT 132.485 60.615 134.135 61.135 ;
        RECT 134.305 60.785 135.995 61.305 ;
        RECT 137.090 60.735 137.440 61.385 ;
        RECT 120.525 59.845 125.870 60.390 ;
        RECT 126.045 59.845 131.390 60.390 ;
        RECT 132.025 59.845 132.315 60.570 ;
        RECT 132.485 59.845 135.995 60.615 ;
        RECT 137.610 60.565 137.840 61.555 ;
        RECT 137.090 60.395 137.840 60.565 ;
        RECT 137.090 60.105 137.345 60.395 ;
        RECT 137.515 59.845 137.845 60.225 ;
        RECT 138.015 60.105 138.185 62.225 ;
        RECT 138.355 61.425 138.680 62.210 ;
        RECT 138.850 61.935 139.100 62.395 ;
        RECT 139.270 61.895 139.520 62.225 ;
        RECT 139.735 61.895 140.415 62.225 ;
        RECT 139.270 61.765 139.440 61.895 ;
        RECT 139.045 61.595 139.440 61.765 ;
        RECT 138.415 60.375 138.875 61.425 ;
        RECT 139.045 60.235 139.215 61.595 ;
        RECT 139.610 61.335 140.075 61.725 ;
        RECT 139.385 60.525 139.735 61.145 ;
        RECT 139.905 60.745 140.075 61.335 ;
        RECT 140.245 61.115 140.415 61.895 ;
        RECT 140.585 61.795 140.755 62.135 ;
        RECT 140.990 61.965 141.320 62.395 ;
        RECT 141.490 61.795 141.660 62.135 ;
        RECT 141.955 61.935 142.325 62.395 ;
        RECT 140.585 61.625 141.660 61.795 ;
        RECT 142.495 61.765 142.665 62.225 ;
        RECT 142.900 61.885 143.770 62.225 ;
        RECT 143.940 61.935 144.190 62.395 ;
        RECT 142.105 61.595 142.665 61.765 ;
        RECT 142.105 61.455 142.275 61.595 ;
        RECT 140.775 61.285 142.275 61.455 ;
        RECT 142.970 61.425 143.430 61.715 ;
        RECT 140.245 60.945 141.935 61.115 ;
        RECT 139.905 60.525 140.260 60.745 ;
        RECT 140.430 60.235 140.600 60.945 ;
        RECT 140.805 60.525 141.595 60.775 ;
        RECT 141.765 60.765 141.935 60.945 ;
        RECT 142.105 60.595 142.275 61.285 ;
        RECT 138.545 59.845 138.875 60.205 ;
        RECT 139.045 60.065 139.540 60.235 ;
        RECT 139.745 60.065 140.600 60.235 ;
        RECT 141.475 59.845 141.805 60.305 ;
        RECT 142.015 60.205 142.275 60.595 ;
        RECT 142.465 61.415 143.430 61.425 ;
        RECT 143.600 61.505 143.770 61.885 ;
        RECT 144.360 61.845 144.530 62.135 ;
        RECT 144.710 62.015 145.040 62.395 ;
        RECT 144.360 61.675 145.160 61.845 ;
        RECT 142.465 61.255 143.140 61.415 ;
        RECT 143.600 61.335 144.820 61.505 ;
        RECT 142.465 60.465 142.675 61.255 ;
        RECT 143.600 61.245 143.770 61.335 ;
        RECT 142.845 60.465 143.195 61.085 ;
        RECT 143.365 61.075 143.770 61.245 ;
        RECT 143.365 60.295 143.535 61.075 ;
        RECT 143.705 60.625 143.925 60.905 ;
        RECT 144.105 60.795 144.645 61.165 ;
        RECT 144.990 61.085 145.160 61.675 ;
        RECT 145.380 61.255 145.685 62.395 ;
        RECT 145.855 61.205 146.110 62.085 ;
        RECT 146.285 61.305 147.495 62.395 ;
        RECT 144.990 61.055 145.730 61.085 ;
        RECT 143.705 60.455 144.235 60.625 ;
        RECT 142.015 60.035 142.365 60.205 ;
        RECT 142.585 60.015 143.535 60.295 ;
        RECT 143.705 59.845 143.895 60.285 ;
        RECT 144.065 60.225 144.235 60.455 ;
        RECT 144.405 60.395 144.645 60.795 ;
        RECT 144.815 60.755 145.730 61.055 ;
        RECT 144.815 60.580 145.140 60.755 ;
        RECT 144.815 60.225 145.135 60.580 ;
        RECT 145.900 60.555 146.110 61.205 ;
        RECT 144.065 60.055 145.135 60.225 ;
        RECT 145.380 59.845 145.685 60.305 ;
        RECT 145.855 60.025 146.110 60.555 ;
        RECT 146.285 60.595 146.805 61.135 ;
        RECT 146.975 60.765 147.495 61.305 ;
        RECT 147.665 61.305 148.875 62.395 ;
        RECT 147.665 60.765 148.185 61.305 ;
        RECT 148.355 60.595 148.875 61.135 ;
        RECT 146.285 59.845 147.495 60.595 ;
        RECT 147.665 59.845 148.875 60.595 ;
        RECT 119.060 59.675 148.960 59.845 ;
        RECT 82.940 52.270 95.020 53.470 ;
        RECT 95.940 58.240 102.020 59.440 ;
        RECT 95.940 57.500 96.900 58.240 ;
        RECT 101.060 57.500 102.020 58.240 ;
        RECT 95.940 57.000 102.020 57.500 ;
        RECT 95.940 54.300 96.900 57.000 ;
        RECT 97.220 55.040 97.540 56.240 ;
        RECT 98.500 55.440 100.100 55.840 ;
        RECT 100.420 55.040 100.740 56.240 ;
        RECT 101.060 54.300 102.020 57.000 ;
        RECT 95.940 53.800 102.020 54.300 ;
        RECT 95.940 53.440 96.900 53.800 ;
        RECT 101.060 53.440 102.020 53.800 ;
        RECT 15.940 51.030 17.140 52.270 ;
        RECT 41.940 51.030 43.140 52.270 ;
        RECT 55.940 51.030 57.140 52.270 ;
        RECT 69.940 51.030 71.140 52.270 ;
        RECT 95.940 52.240 102.020 53.440 ;
        RECT 102.940 58.240 109.020 59.440 ;
        RECT 119.145 58.925 120.355 59.675 ;
        RECT 120.525 59.130 125.870 59.675 ;
        RECT 119.145 58.385 119.665 58.925 ;
        RECT 102.940 57.000 103.900 58.240 ;
        RECT 108.060 57.000 109.020 58.240 ;
        RECT 119.835 58.215 120.355 58.755 ;
        RECT 122.110 58.300 122.450 59.130 ;
        RECT 126.045 58.925 127.255 59.675 ;
        RECT 127.430 59.125 127.685 59.415 ;
        RECT 127.855 59.295 128.185 59.675 ;
        RECT 127.430 58.955 128.180 59.125 ;
        RECT 119.145 57.125 120.355 58.215 ;
        RECT 123.930 57.560 124.280 58.810 ;
        RECT 126.045 58.385 126.565 58.925 ;
        RECT 126.735 58.215 127.255 58.755 ;
        RECT 120.525 57.125 125.870 57.560 ;
        RECT 126.045 57.125 127.255 58.215 ;
        RECT 127.430 58.135 127.780 58.785 ;
        RECT 127.950 57.965 128.180 58.955 ;
        RECT 127.430 57.795 128.180 57.965 ;
        RECT 127.430 57.295 127.685 57.795 ;
        RECT 127.855 57.125 128.185 57.625 ;
        RECT 128.355 57.295 128.525 59.415 ;
        RECT 128.885 59.315 129.215 59.675 ;
        RECT 129.385 59.285 129.880 59.455 ;
        RECT 130.085 59.285 130.940 59.455 ;
        RECT 128.755 58.095 129.215 59.145 ;
        RECT 128.695 57.310 129.020 58.095 ;
        RECT 129.385 57.925 129.555 59.285 ;
        RECT 129.725 58.375 130.075 58.995 ;
        RECT 130.245 58.775 130.600 58.995 ;
        RECT 130.245 58.185 130.415 58.775 ;
        RECT 130.770 58.575 130.940 59.285 ;
        RECT 131.815 59.215 132.145 59.675 ;
        RECT 132.355 59.315 132.705 59.485 ;
        RECT 131.145 58.745 131.935 58.995 ;
        RECT 132.355 58.925 132.615 59.315 ;
        RECT 132.925 59.225 133.875 59.505 ;
        RECT 134.045 59.235 134.235 59.675 ;
        RECT 134.405 59.295 135.475 59.465 ;
        RECT 132.105 58.575 132.275 58.755 ;
        RECT 129.385 57.755 129.780 57.925 ;
        RECT 129.950 57.795 130.415 58.185 ;
        RECT 130.585 58.405 132.275 58.575 ;
        RECT 129.610 57.625 129.780 57.755 ;
        RECT 130.585 57.625 130.755 58.405 ;
        RECT 132.445 58.235 132.615 58.925 ;
        RECT 131.115 58.065 132.615 58.235 ;
        RECT 132.805 58.265 133.015 59.055 ;
        RECT 133.185 58.435 133.535 59.055 ;
        RECT 133.705 58.445 133.875 59.225 ;
        RECT 134.405 59.065 134.575 59.295 ;
        RECT 134.045 58.895 134.575 59.065 ;
        RECT 134.045 58.615 134.265 58.895 ;
        RECT 134.745 58.725 134.985 59.125 ;
        RECT 133.705 58.275 134.110 58.445 ;
        RECT 134.445 58.355 134.985 58.725 ;
        RECT 135.155 58.940 135.475 59.295 ;
        RECT 135.720 59.215 136.025 59.675 ;
        RECT 136.195 58.965 136.450 59.495 ;
        RECT 135.155 58.765 135.480 58.940 ;
        RECT 135.155 58.465 136.070 58.765 ;
        RECT 135.330 58.435 136.070 58.465 ;
        RECT 132.805 58.105 133.480 58.265 ;
        RECT 133.940 58.185 134.110 58.275 ;
        RECT 132.805 58.095 133.770 58.105 ;
        RECT 132.445 57.925 132.615 58.065 ;
        RECT 129.190 57.125 129.440 57.585 ;
        RECT 129.610 57.295 129.860 57.625 ;
        RECT 130.075 57.295 130.755 57.625 ;
        RECT 130.925 57.725 132.000 57.895 ;
        RECT 132.445 57.755 133.005 57.925 ;
        RECT 133.310 57.805 133.770 58.095 ;
        RECT 133.940 58.015 135.160 58.185 ;
        RECT 130.925 57.385 131.095 57.725 ;
        RECT 131.330 57.125 131.660 57.555 ;
        RECT 131.830 57.385 132.000 57.725 ;
        RECT 132.295 57.125 132.665 57.585 ;
        RECT 132.835 57.295 133.005 57.755 ;
        RECT 133.940 57.635 134.110 58.015 ;
        RECT 135.330 57.845 135.500 58.435 ;
        RECT 136.240 58.315 136.450 58.965 ;
        RECT 133.240 57.295 134.110 57.635 ;
        RECT 134.700 57.675 135.500 57.845 ;
        RECT 134.280 57.125 134.530 57.585 ;
        RECT 134.700 57.385 134.870 57.675 ;
        RECT 135.050 57.125 135.380 57.505 ;
        RECT 135.720 57.125 136.025 58.265 ;
        RECT 136.195 57.435 136.450 58.315 ;
        RECT 136.645 58.985 136.885 59.505 ;
        RECT 137.055 59.180 137.450 59.675 ;
        RECT 138.015 59.345 138.185 59.490 ;
        RECT 137.810 59.150 138.185 59.345 ;
        RECT 136.645 58.180 136.820 58.985 ;
        RECT 137.810 58.815 137.980 59.150 ;
        RECT 138.465 59.105 138.705 59.480 ;
        RECT 138.875 59.170 139.210 59.675 ;
        RECT 139.385 59.200 139.725 59.460 ;
        RECT 138.465 58.955 138.685 59.105 ;
        RECT 136.995 58.455 137.980 58.815 ;
        RECT 138.150 58.625 138.685 58.955 ;
        RECT 136.995 58.435 138.280 58.455 ;
        RECT 137.420 58.285 138.280 58.435 ;
        RECT 136.645 57.395 136.950 58.180 ;
        RECT 137.125 57.805 137.820 58.115 ;
        RECT 137.130 57.125 137.815 57.595 ;
        RECT 137.995 57.340 138.280 58.285 ;
        RECT 138.450 57.975 138.685 58.625 ;
        RECT 138.855 58.145 139.155 58.995 ;
        RECT 138.450 57.745 139.125 57.975 ;
        RECT 138.455 57.125 138.785 57.575 ;
        RECT 138.955 57.315 139.125 57.745 ;
        RECT 139.385 57.595 139.645 59.200 ;
        RECT 139.895 59.195 140.225 59.675 ;
        RECT 140.415 59.025 140.830 59.460 ;
        RECT 141.000 59.160 141.950 59.345 ;
        RECT 139.815 58.950 140.830 59.025 ;
        RECT 139.815 58.855 140.635 58.950 ;
        RECT 139.815 57.935 139.985 58.855 ;
        RECT 140.305 58.125 140.635 58.685 ;
        RECT 140.835 58.435 141.215 58.765 ;
        RECT 141.525 58.435 141.745 59.160 ;
        RECT 142.180 58.765 142.385 59.365 ;
        RECT 142.555 58.950 142.895 59.675 ;
        RECT 143.085 58.865 143.325 59.675 ;
        RECT 143.495 58.865 143.825 59.505 ;
        RECT 143.995 58.865 144.265 59.675 ;
        RECT 144.905 58.950 145.195 59.675 ;
        RECT 145.365 58.905 147.035 59.675 ;
        RECT 147.665 58.925 148.875 59.675 ;
        RECT 140.835 58.315 141.135 58.435 ;
        RECT 140.825 58.145 141.135 58.315 ;
        RECT 140.835 58.140 141.135 58.145 ;
        RECT 142.005 58.135 142.385 58.765 ;
        RECT 142.615 58.135 142.870 58.765 ;
        RECT 143.065 58.435 143.415 58.685 ;
        RECT 143.585 58.265 143.755 58.865 ;
        RECT 143.925 58.435 144.275 58.685 ;
        RECT 145.365 58.385 146.115 58.905 ;
        RECT 143.075 58.095 143.755 58.265 ;
        RECT 139.815 57.765 140.665 57.935 ;
        RECT 139.385 57.335 139.725 57.595 ;
        RECT 139.895 57.125 140.145 57.585 ;
        RECT 140.335 57.335 140.665 57.765 ;
        RECT 140.835 57.795 142.805 57.965 ;
        RECT 140.835 57.295 141.005 57.795 ;
        RECT 141.215 57.125 141.465 57.585 ;
        RECT 141.675 57.295 141.845 57.795 ;
        RECT 142.145 57.125 142.395 57.585 ;
        RECT 142.635 57.295 142.805 57.795 ;
        RECT 143.075 57.310 143.405 58.095 ;
        RECT 143.935 57.125 144.265 58.265 ;
        RECT 144.905 57.125 145.195 58.290 ;
        RECT 146.285 58.215 147.035 58.735 ;
        RECT 145.365 57.125 147.035 58.215 ;
        RECT 147.665 58.215 148.185 58.755 ;
        RECT 148.355 58.385 148.875 58.925 ;
        RECT 147.665 57.125 148.875 58.215 ;
        RECT 102.940 56.500 109.020 57.000 ;
        RECT 119.060 56.955 148.960 57.125 ;
        RECT 102.940 54.800 103.900 56.500 ;
        RECT 104.860 56.240 106.460 56.500 ;
        RECT 104.220 55.040 104.540 56.240 ;
        RECT 105.500 55.440 107.100 55.840 ;
        RECT 107.420 55.040 107.740 56.240 ;
        RECT 104.860 54.800 106.460 55.040 ;
        RECT 108.060 54.800 109.020 56.500 ;
        RECT 119.145 55.865 120.355 56.955 ;
        RECT 120.525 55.865 124.035 56.955 ;
        RECT 102.940 54.300 109.020 54.800 ;
        RECT 119.145 55.155 119.665 55.695 ;
        RECT 119.835 55.325 120.355 55.865 ;
        RECT 120.525 55.175 122.175 55.695 ;
        RECT 122.345 55.345 124.035 55.865 ;
        RECT 124.215 55.815 124.545 56.955 ;
        RECT 125.075 55.985 125.405 56.770 ;
        RECT 124.725 55.815 125.405 55.985 ;
        RECT 124.205 55.395 124.555 55.645 ;
        RECT 124.725 55.215 124.895 55.815 ;
        RECT 125.065 55.395 125.415 55.645 ;
        RECT 125.585 55.350 125.865 56.785 ;
        RECT 126.035 56.180 126.745 56.955 ;
        RECT 126.915 56.010 127.245 56.785 ;
        RECT 126.095 55.795 127.245 56.010 ;
        RECT 119.145 54.405 120.355 55.155 ;
        RECT 120.525 54.405 124.035 55.175 ;
        RECT 124.215 54.405 124.485 55.215 ;
        RECT 124.655 54.575 124.985 55.215 ;
        RECT 125.155 54.405 125.395 55.215 ;
        RECT 125.585 54.575 125.925 55.350 ;
        RECT 126.095 55.225 126.380 55.795 ;
        RECT 126.565 55.395 127.035 55.625 ;
        RECT 127.440 55.595 127.655 56.710 ;
        RECT 127.835 56.235 128.165 56.955 ;
        RECT 127.945 55.595 128.175 55.935 ;
        RECT 127.205 55.415 127.655 55.595 ;
        RECT 127.205 55.395 127.535 55.415 ;
        RECT 127.845 55.395 128.175 55.595 ;
        RECT 129.265 55.350 129.545 56.785 ;
        RECT 129.715 56.180 130.425 56.955 ;
        RECT 130.595 56.010 130.925 56.785 ;
        RECT 129.775 55.795 130.925 56.010 ;
        RECT 126.095 55.035 126.805 55.225 ;
        RECT 126.505 54.895 126.805 55.035 ;
        RECT 126.995 55.035 128.175 55.225 ;
        RECT 126.995 54.955 127.325 55.035 ;
        RECT 126.505 54.885 126.820 54.895 ;
        RECT 126.505 54.875 126.830 54.885 ;
        RECT 126.505 54.870 126.840 54.875 ;
        RECT 126.095 54.405 126.265 54.865 ;
        RECT 126.505 54.860 126.845 54.870 ;
        RECT 126.505 54.855 126.850 54.860 ;
        RECT 126.505 54.845 126.855 54.855 ;
        RECT 126.505 54.840 126.860 54.845 ;
        RECT 126.505 54.575 126.865 54.840 ;
        RECT 127.495 54.405 127.665 54.865 ;
        RECT 127.835 54.575 128.175 55.035 ;
        RECT 129.265 54.575 129.605 55.350 ;
        RECT 129.775 55.225 130.060 55.795 ;
        RECT 130.245 55.395 130.715 55.625 ;
        RECT 131.120 55.595 131.335 56.710 ;
        RECT 131.515 56.235 131.845 56.955 ;
        RECT 131.625 55.595 131.855 55.935 ;
        RECT 132.025 55.790 132.315 56.955 ;
        RECT 132.495 56.575 132.825 56.955 ;
        RECT 130.885 55.415 131.335 55.595 ;
        RECT 130.885 55.395 131.215 55.415 ;
        RECT 131.525 55.395 131.855 55.595 ;
        RECT 129.775 55.035 130.485 55.225 ;
        RECT 130.185 54.895 130.485 55.035 ;
        RECT 130.675 55.035 131.855 55.225 ;
        RECT 130.675 54.955 131.005 55.035 ;
        RECT 130.185 54.885 130.500 54.895 ;
        RECT 130.185 54.875 130.510 54.885 ;
        RECT 130.185 54.870 130.520 54.875 ;
        RECT 129.775 54.405 129.945 54.865 ;
        RECT 130.185 54.860 130.525 54.870 ;
        RECT 130.185 54.855 130.530 54.860 ;
        RECT 130.185 54.845 130.535 54.855 ;
        RECT 130.185 54.840 130.540 54.845 ;
        RECT 130.185 54.575 130.545 54.840 ;
        RECT 131.175 54.405 131.345 54.865 ;
        RECT 131.515 54.575 131.855 55.035 ;
        RECT 132.025 54.405 132.315 55.130 ;
        RECT 132.525 55.075 132.730 56.395 ;
        RECT 133.000 55.985 133.250 56.785 ;
        RECT 133.470 56.235 133.800 56.955 ;
        RECT 133.985 55.985 134.235 56.785 ;
        RECT 134.635 56.155 134.965 56.955 ;
        RECT 132.900 55.815 134.955 55.985 ;
        RECT 135.135 55.815 135.470 56.785 ;
        RECT 135.645 56.155 135.975 56.955 ;
        RECT 137.090 56.285 137.345 56.785 ;
        RECT 137.515 56.455 137.845 56.955 ;
        RECT 137.090 56.115 137.840 56.285 ;
        RECT 132.900 54.905 133.070 55.815 ;
        RECT 132.575 54.575 133.070 54.905 ;
        RECT 133.290 54.740 133.645 55.645 ;
        RECT 133.820 55.625 133.990 55.645 ;
        RECT 133.820 54.735 134.120 55.625 ;
        RECT 134.300 54.735 134.560 55.645 ;
        RECT 134.730 55.635 134.955 55.815 ;
        RECT 134.730 55.395 135.125 55.635 ;
        RECT 134.730 54.405 134.965 55.210 ;
        RECT 135.295 55.125 135.470 55.815 ;
        RECT 137.090 55.295 137.440 55.945 ;
        RECT 135.135 54.915 135.470 55.125 ;
        RECT 135.135 54.745 135.475 54.915 ;
        RECT 135.135 54.660 135.470 54.745 ;
        RECT 135.135 54.615 135.465 54.660 ;
        RECT 135.655 54.405 135.985 55.130 ;
        RECT 137.610 55.125 137.840 56.115 ;
        RECT 137.090 54.955 137.840 55.125 ;
        RECT 137.090 54.665 137.345 54.955 ;
        RECT 137.515 54.405 137.845 54.785 ;
        RECT 138.015 54.665 138.185 56.785 ;
        RECT 138.355 55.985 138.680 56.770 ;
        RECT 138.850 56.495 139.100 56.955 ;
        RECT 139.270 56.455 139.520 56.785 ;
        RECT 139.735 56.455 140.415 56.785 ;
        RECT 139.270 56.325 139.440 56.455 ;
        RECT 139.045 56.155 139.440 56.325 ;
        RECT 138.415 54.935 138.875 55.985 ;
        RECT 139.045 54.795 139.215 56.155 ;
        RECT 139.610 55.895 140.075 56.285 ;
        RECT 139.385 55.085 139.735 55.705 ;
        RECT 139.905 55.305 140.075 55.895 ;
        RECT 140.245 55.675 140.415 56.455 ;
        RECT 140.585 56.355 140.755 56.695 ;
        RECT 140.990 56.525 141.320 56.955 ;
        RECT 141.490 56.355 141.660 56.695 ;
        RECT 141.955 56.495 142.325 56.955 ;
        RECT 140.585 56.185 141.660 56.355 ;
        RECT 142.495 56.325 142.665 56.785 ;
        RECT 142.900 56.445 143.770 56.785 ;
        RECT 143.940 56.495 144.190 56.955 ;
        RECT 142.105 56.155 142.665 56.325 ;
        RECT 142.105 56.015 142.275 56.155 ;
        RECT 140.775 55.845 142.275 56.015 ;
        RECT 142.970 55.985 143.430 56.275 ;
        RECT 140.245 55.505 141.935 55.675 ;
        RECT 139.905 55.085 140.260 55.305 ;
        RECT 140.430 54.795 140.600 55.505 ;
        RECT 140.805 55.085 141.595 55.335 ;
        RECT 141.765 55.325 141.935 55.505 ;
        RECT 142.105 55.155 142.275 55.845 ;
        RECT 138.545 54.405 138.875 54.765 ;
        RECT 139.045 54.625 139.540 54.795 ;
        RECT 139.745 54.625 140.600 54.795 ;
        RECT 141.475 54.405 141.805 54.865 ;
        RECT 142.015 54.765 142.275 55.155 ;
        RECT 142.465 55.975 143.430 55.985 ;
        RECT 143.600 56.065 143.770 56.445 ;
        RECT 144.360 56.405 144.530 56.695 ;
        RECT 144.710 56.575 145.040 56.955 ;
        RECT 144.360 56.235 145.160 56.405 ;
        RECT 142.465 55.815 143.140 55.975 ;
        RECT 143.600 55.895 144.820 56.065 ;
        RECT 142.465 55.025 142.675 55.815 ;
        RECT 143.600 55.805 143.770 55.895 ;
        RECT 142.845 55.025 143.195 55.645 ;
        RECT 143.365 55.635 143.770 55.805 ;
        RECT 143.365 54.855 143.535 55.635 ;
        RECT 143.705 55.185 143.925 55.465 ;
        RECT 144.105 55.355 144.645 55.725 ;
        RECT 144.990 55.645 145.160 56.235 ;
        RECT 145.380 55.815 145.685 56.955 ;
        RECT 145.855 55.765 146.110 56.645 ;
        RECT 146.285 55.865 147.495 56.955 ;
        RECT 144.990 55.615 145.730 55.645 ;
        RECT 143.705 55.015 144.235 55.185 ;
        RECT 142.015 54.595 142.365 54.765 ;
        RECT 142.585 54.575 143.535 54.855 ;
        RECT 143.705 54.405 143.895 54.845 ;
        RECT 144.065 54.785 144.235 55.015 ;
        RECT 144.405 54.955 144.645 55.355 ;
        RECT 144.815 55.315 145.730 55.615 ;
        RECT 144.815 55.140 145.140 55.315 ;
        RECT 144.815 54.785 145.135 55.140 ;
        RECT 145.900 55.115 146.110 55.765 ;
        RECT 144.065 54.615 145.135 54.785 ;
        RECT 145.380 54.405 145.685 54.865 ;
        RECT 145.855 54.585 146.110 55.115 ;
        RECT 146.285 55.155 146.805 55.695 ;
        RECT 146.975 55.325 147.495 55.865 ;
        RECT 147.665 55.865 148.875 56.955 ;
        RECT 147.665 55.325 148.185 55.865 ;
        RECT 148.355 55.155 148.875 55.695 ;
        RECT 146.285 54.405 147.495 55.155 ;
        RECT 147.665 54.405 148.875 55.155 ;
        RECT 102.940 53.440 103.900 54.300 ;
        RECT 108.060 53.440 109.020 54.300 ;
        RECT 119.060 54.235 148.960 54.405 ;
        RECT 102.940 52.240 109.020 53.440 ;
        RECT 119.145 53.485 120.355 54.235 ;
        RECT 120.525 53.690 125.870 54.235 ;
        RECT 126.505 53.735 126.805 54.065 ;
        RECT 126.975 53.755 127.250 54.235 ;
        RECT 119.145 52.945 119.665 53.485 ;
        RECT 119.835 52.775 120.355 53.315 ;
        RECT 122.110 52.860 122.450 53.690 ;
        RECT 95.940 51.030 97.140 52.240 ;
        RECT 119.145 51.685 120.355 52.775 ;
        RECT 123.930 52.120 124.280 53.370 ;
        RECT 126.505 52.825 126.675 53.735 ;
        RECT 127.430 53.585 127.725 53.975 ;
        RECT 127.895 53.755 128.150 54.235 ;
        RECT 128.325 53.585 128.585 53.975 ;
        RECT 128.755 53.755 129.035 54.235 ;
        RECT 129.265 53.725 129.570 54.235 ;
        RECT 126.845 52.995 127.195 53.565 ;
        RECT 127.430 53.415 129.080 53.585 ;
        RECT 127.365 53.075 128.505 53.245 ;
        RECT 127.365 52.825 127.535 53.075 ;
        RECT 128.675 52.905 129.080 53.415 ;
        RECT 129.265 52.995 129.580 53.555 ;
        RECT 129.750 53.245 130.000 54.055 ;
        RECT 130.170 53.710 130.430 54.235 ;
        RECT 130.610 53.245 130.860 54.055 ;
        RECT 131.030 53.675 131.290 54.235 ;
        RECT 131.460 53.585 131.720 54.040 ;
        RECT 131.890 53.755 132.150 54.235 ;
        RECT 132.320 53.585 132.580 54.040 ;
        RECT 132.750 53.755 133.010 54.235 ;
        RECT 133.180 53.585 133.440 54.040 ;
        RECT 133.610 53.755 133.855 54.235 ;
        RECT 134.025 53.585 134.300 54.040 ;
        RECT 134.470 53.755 134.715 54.235 ;
        RECT 134.885 53.585 135.145 54.040 ;
        RECT 135.325 53.755 135.575 54.235 ;
        RECT 135.745 53.585 136.005 54.040 ;
        RECT 136.185 53.755 136.435 54.235 ;
        RECT 136.605 53.585 136.865 54.040 ;
        RECT 137.045 53.755 137.305 54.235 ;
        RECT 137.475 53.585 137.735 54.040 ;
        RECT 137.905 53.755 138.205 54.235 ;
        RECT 131.460 53.415 138.205 53.585 ;
        RECT 129.750 52.995 136.870 53.245 ;
        RECT 126.505 52.655 127.535 52.825 ;
        RECT 128.325 52.735 129.080 52.905 ;
        RECT 120.525 51.685 125.870 52.120 ;
        RECT 126.505 51.855 126.815 52.655 ;
        RECT 128.325 52.485 128.585 52.735 ;
        RECT 126.985 51.685 127.295 52.485 ;
        RECT 127.465 52.315 128.585 52.485 ;
        RECT 127.465 51.855 127.725 52.315 ;
        RECT 127.895 51.685 128.150 52.145 ;
        RECT 128.325 51.855 128.585 52.315 ;
        RECT 128.755 51.685 129.040 52.555 ;
        RECT 129.275 51.685 129.570 52.495 ;
        RECT 129.750 51.855 129.995 52.995 ;
        RECT 130.170 51.685 130.430 52.495 ;
        RECT 130.610 51.860 130.860 52.995 ;
        RECT 137.040 52.825 138.205 53.415 ;
        RECT 138.465 53.485 139.675 54.235 ;
        RECT 140.175 53.835 140.505 54.235 ;
        RECT 140.675 53.665 141.005 54.005 ;
        RECT 142.055 53.835 142.385 54.235 ;
        RECT 140.020 53.495 142.385 53.665 ;
        RECT 142.555 53.510 142.885 54.020 ;
        RECT 138.465 52.945 138.985 53.485 ;
        RECT 131.460 52.600 138.205 52.825 ;
        RECT 139.155 52.775 139.675 53.315 ;
        RECT 131.460 52.585 136.865 52.600 ;
        RECT 131.030 51.690 131.290 52.485 ;
        RECT 131.460 51.860 131.720 52.585 ;
        RECT 131.890 51.690 132.150 52.415 ;
        RECT 132.320 51.860 132.580 52.585 ;
        RECT 132.750 51.690 133.010 52.415 ;
        RECT 133.180 51.860 133.440 52.585 ;
        RECT 133.610 51.690 133.870 52.415 ;
        RECT 134.040 51.860 134.300 52.585 ;
        RECT 134.470 51.690 134.715 52.415 ;
        RECT 134.885 51.860 135.145 52.585 ;
        RECT 135.330 51.690 135.575 52.415 ;
        RECT 135.745 51.860 136.005 52.585 ;
        RECT 136.190 51.690 136.435 52.415 ;
        RECT 136.605 51.860 136.865 52.585 ;
        RECT 137.050 51.690 137.305 52.415 ;
        RECT 137.475 51.860 137.765 52.600 ;
        RECT 131.030 51.685 137.305 51.690 ;
        RECT 137.935 51.685 138.205 52.430 ;
        RECT 138.465 51.685 139.675 52.775 ;
        RECT 140.020 52.495 140.190 53.495 ;
        RECT 142.215 53.325 142.385 53.495 ;
        RECT 140.360 52.665 140.605 53.325 ;
        RECT 140.820 52.665 141.085 53.325 ;
        RECT 141.280 52.665 141.565 53.325 ;
        RECT 141.740 52.995 142.045 53.325 ;
        RECT 142.215 52.995 142.525 53.325 ;
        RECT 141.740 52.665 141.955 52.995 ;
        RECT 140.020 52.325 140.475 52.495 ;
        RECT 140.145 51.895 140.475 52.325 ;
        RECT 140.655 52.325 141.945 52.495 ;
        RECT 140.655 51.905 140.905 52.325 ;
        RECT 141.135 51.685 141.465 52.155 ;
        RECT 141.695 51.905 141.945 52.325 ;
        RECT 142.135 51.685 142.385 52.825 ;
        RECT 142.695 52.745 142.885 53.510 ;
        RECT 143.075 53.505 143.375 54.235 ;
        RECT 143.555 53.325 143.785 53.945 ;
        RECT 143.985 53.675 144.210 54.055 ;
        RECT 144.380 53.845 144.710 54.235 ;
        RECT 143.985 53.495 144.315 53.675 ;
        RECT 143.080 52.995 143.375 53.325 ;
        RECT 143.555 52.995 143.970 53.325 ;
        RECT 144.140 52.825 144.315 53.495 ;
        RECT 144.485 52.995 144.725 53.645 ;
        RECT 144.905 53.510 145.195 54.235 ;
        RECT 145.365 53.465 147.035 54.235 ;
        RECT 147.665 53.485 148.875 54.235 ;
        RECT 145.365 52.945 146.115 53.465 ;
        RECT 142.555 51.895 142.885 52.745 ;
        RECT 143.075 52.465 143.970 52.795 ;
        RECT 144.140 52.635 144.725 52.825 ;
        RECT 143.075 52.295 144.280 52.465 ;
        RECT 143.075 51.865 143.405 52.295 ;
        RECT 143.585 51.685 143.780 52.125 ;
        RECT 143.950 51.865 144.280 52.295 ;
        RECT 144.450 51.865 144.725 52.635 ;
        RECT 144.905 51.685 145.195 52.850 ;
        RECT 146.285 52.775 147.035 53.295 ;
        RECT 145.365 51.685 147.035 52.775 ;
        RECT 147.665 52.775 148.185 53.315 ;
        RECT 148.355 52.945 148.875 53.485 ;
        RECT 147.665 51.685 148.875 52.775 ;
        RECT 119.060 51.515 148.960 51.685 ;
        RECT 15.500 49.030 109.500 51.030 ;
        RECT 119.145 50.425 120.355 51.515 ;
        RECT 121.450 50.845 121.705 51.345 ;
        RECT 121.875 51.015 122.205 51.515 ;
        RECT 121.450 50.675 122.200 50.845 ;
        RECT 119.145 49.715 119.665 50.255 ;
        RECT 119.835 49.885 120.355 50.425 ;
        RECT 121.450 49.855 121.800 50.505 ;
        RECT 119.145 48.965 120.355 49.715 ;
        RECT 121.970 49.685 122.200 50.675 ;
        RECT 121.450 49.515 122.200 49.685 ;
        RECT 121.450 49.225 121.705 49.515 ;
        RECT 121.875 48.965 122.205 49.345 ;
        RECT 122.375 49.225 122.545 51.345 ;
        RECT 122.715 50.545 123.040 51.330 ;
        RECT 123.210 51.055 123.460 51.515 ;
        RECT 123.630 51.015 123.880 51.345 ;
        RECT 124.095 51.015 124.775 51.345 ;
        RECT 123.630 50.885 123.800 51.015 ;
        RECT 123.405 50.715 123.800 50.885 ;
        RECT 122.775 49.495 123.235 50.545 ;
        RECT 123.405 49.355 123.575 50.715 ;
        RECT 123.970 50.455 124.435 50.845 ;
        RECT 123.745 49.645 124.095 50.265 ;
        RECT 124.265 49.865 124.435 50.455 ;
        RECT 124.605 50.235 124.775 51.015 ;
        RECT 124.945 50.915 125.115 51.255 ;
        RECT 125.350 51.085 125.680 51.515 ;
        RECT 125.850 50.915 126.020 51.255 ;
        RECT 126.315 51.055 126.685 51.515 ;
        RECT 124.945 50.745 126.020 50.915 ;
        RECT 126.855 50.885 127.025 51.345 ;
        RECT 127.260 51.005 128.130 51.345 ;
        RECT 128.300 51.055 128.550 51.515 ;
        RECT 126.465 50.715 127.025 50.885 ;
        RECT 126.465 50.575 126.635 50.715 ;
        RECT 125.135 50.405 126.635 50.575 ;
        RECT 127.330 50.545 127.790 50.835 ;
        RECT 124.605 50.065 126.295 50.235 ;
        RECT 124.265 49.645 124.620 49.865 ;
        RECT 124.790 49.355 124.960 50.065 ;
        RECT 125.165 49.645 125.955 49.895 ;
        RECT 126.125 49.885 126.295 50.065 ;
        RECT 126.465 49.715 126.635 50.405 ;
        RECT 122.905 48.965 123.235 49.325 ;
        RECT 123.405 49.185 123.900 49.355 ;
        RECT 124.105 49.185 124.960 49.355 ;
        RECT 125.835 48.965 126.165 49.425 ;
        RECT 126.375 49.325 126.635 49.715 ;
        RECT 126.825 50.535 127.790 50.545 ;
        RECT 127.960 50.625 128.130 51.005 ;
        RECT 128.720 50.965 128.890 51.255 ;
        RECT 129.070 51.135 129.400 51.515 ;
        RECT 128.720 50.795 129.520 50.965 ;
        RECT 126.825 50.375 127.500 50.535 ;
        RECT 127.960 50.455 129.180 50.625 ;
        RECT 126.825 49.585 127.035 50.375 ;
        RECT 127.960 50.365 128.130 50.455 ;
        RECT 127.205 49.585 127.555 50.205 ;
        RECT 127.725 50.195 128.130 50.365 ;
        RECT 127.725 49.415 127.895 50.195 ;
        RECT 128.065 49.745 128.285 50.025 ;
        RECT 128.465 49.915 129.005 50.285 ;
        RECT 129.350 50.205 129.520 50.795 ;
        RECT 129.740 50.375 130.045 51.515 ;
        RECT 130.215 50.325 130.470 51.205 ;
        RECT 130.655 50.375 130.985 51.515 ;
        RECT 131.515 50.545 131.845 51.330 ;
        RECT 131.165 50.375 131.845 50.545 ;
        RECT 129.350 50.175 130.090 50.205 ;
        RECT 128.065 49.575 128.595 49.745 ;
        RECT 126.375 49.155 126.725 49.325 ;
        RECT 126.945 49.135 127.895 49.415 ;
        RECT 128.065 48.965 128.255 49.405 ;
        RECT 128.425 49.345 128.595 49.575 ;
        RECT 128.765 49.515 129.005 49.915 ;
        RECT 129.175 49.875 130.090 50.175 ;
        RECT 129.175 49.700 129.500 49.875 ;
        RECT 129.175 49.345 129.495 49.700 ;
        RECT 130.260 49.675 130.470 50.325 ;
        RECT 130.645 49.955 130.995 50.205 ;
        RECT 131.165 49.775 131.335 50.375 ;
        RECT 132.025 50.350 132.315 51.515 ;
        RECT 133.405 50.645 133.680 51.345 ;
        RECT 133.850 50.970 134.105 51.515 ;
        RECT 134.275 51.005 134.755 51.345 ;
        RECT 134.930 50.960 135.535 51.515 ;
        RECT 134.920 50.860 135.535 50.960 ;
        RECT 134.920 50.835 135.105 50.860 ;
        RECT 131.505 49.955 131.855 50.205 ;
        RECT 128.425 49.175 129.495 49.345 ;
        RECT 129.740 48.965 130.045 49.425 ;
        RECT 130.215 49.145 130.470 49.675 ;
        RECT 130.655 48.965 130.925 49.775 ;
        RECT 131.095 49.135 131.425 49.775 ;
        RECT 131.595 48.965 131.835 49.775 ;
        RECT 132.025 48.965 132.315 49.690 ;
        RECT 133.405 49.615 133.575 50.645 ;
        RECT 133.850 50.515 134.605 50.765 ;
        RECT 134.775 50.590 135.105 50.835 ;
        RECT 135.705 50.795 136.165 51.345 ;
        RECT 136.355 50.795 136.685 51.515 ;
        RECT 133.850 50.480 134.620 50.515 ;
        RECT 133.850 50.470 134.635 50.480 ;
        RECT 133.745 50.455 134.640 50.470 ;
        RECT 133.745 50.440 134.660 50.455 ;
        RECT 133.745 50.430 134.680 50.440 ;
        RECT 133.745 50.420 134.705 50.430 ;
        RECT 133.745 50.390 134.775 50.420 ;
        RECT 133.745 50.360 134.795 50.390 ;
        RECT 133.745 50.330 134.815 50.360 ;
        RECT 133.745 50.305 134.845 50.330 ;
        RECT 133.745 50.270 134.880 50.305 ;
        RECT 133.745 50.265 134.910 50.270 ;
        RECT 133.745 49.870 133.975 50.265 ;
        RECT 134.520 50.260 134.910 50.265 ;
        RECT 134.545 50.250 134.910 50.260 ;
        RECT 134.560 50.245 134.910 50.250 ;
        RECT 134.575 50.240 134.910 50.245 ;
        RECT 135.275 50.240 135.535 50.690 ;
        RECT 134.575 50.235 135.535 50.240 ;
        RECT 134.585 50.225 135.535 50.235 ;
        RECT 134.595 50.220 135.535 50.225 ;
        RECT 134.605 50.210 135.535 50.220 ;
        RECT 134.610 50.200 135.535 50.210 ;
        RECT 134.615 50.195 135.535 50.200 ;
        RECT 134.625 50.180 135.535 50.195 ;
        RECT 134.630 50.165 135.535 50.180 ;
        RECT 134.640 50.140 135.535 50.165 ;
        RECT 134.145 49.670 134.475 50.095 ;
        RECT 133.405 49.135 133.665 49.615 ;
        RECT 133.835 48.965 134.085 49.505 ;
        RECT 134.255 49.185 134.475 49.670 ;
        RECT 134.645 50.070 135.535 50.140 ;
        RECT 134.645 49.345 134.815 50.070 ;
        RECT 134.985 49.515 135.535 49.900 ;
        RECT 135.705 49.425 135.955 50.795 ;
        RECT 136.885 50.625 137.185 51.175 ;
        RECT 137.355 50.845 137.635 51.515 ;
        RECT 136.245 50.455 137.185 50.625 ;
        RECT 136.245 50.205 136.415 50.455 ;
        RECT 137.555 50.205 137.820 50.565 ;
        RECT 138.005 50.425 139.215 51.515 ;
        RECT 136.125 49.875 136.415 50.205 ;
        RECT 136.585 49.955 136.925 50.205 ;
        RECT 137.145 49.955 137.820 50.205 ;
        RECT 136.245 49.785 136.415 49.875 ;
        RECT 136.245 49.595 137.635 49.785 ;
        RECT 134.645 49.175 135.535 49.345 ;
        RECT 135.705 49.135 136.265 49.425 ;
        RECT 136.435 48.965 136.685 49.425 ;
        RECT 137.305 49.235 137.635 49.595 ;
        RECT 138.005 49.715 138.525 50.255 ;
        RECT 138.695 49.885 139.215 50.425 ;
        RECT 139.395 50.905 139.725 51.335 ;
        RECT 139.905 51.075 140.100 51.515 ;
        RECT 140.270 50.905 140.600 51.335 ;
        RECT 139.395 50.735 140.600 50.905 ;
        RECT 139.395 50.405 140.290 50.735 ;
        RECT 140.770 50.565 141.045 51.335 ;
        RECT 141.225 51.080 146.570 51.515 ;
        RECT 140.460 50.375 141.045 50.565 ;
        RECT 139.400 49.875 139.695 50.205 ;
        RECT 139.875 49.875 140.290 50.205 ;
        RECT 138.005 48.965 139.215 49.715 ;
        RECT 139.395 48.965 139.695 49.695 ;
        RECT 139.875 49.255 140.105 49.875 ;
        RECT 140.460 49.705 140.635 50.375 ;
        RECT 140.305 49.525 140.635 49.705 ;
        RECT 140.805 49.555 141.045 50.205 ;
        RECT 140.305 49.145 140.530 49.525 ;
        RECT 142.810 49.510 143.150 50.340 ;
        RECT 144.630 49.830 144.980 51.080 ;
        RECT 147.665 50.425 148.875 51.515 ;
        RECT 147.665 49.885 148.185 50.425 ;
        RECT 148.355 49.715 148.875 50.255 ;
        RECT 140.700 48.965 141.030 49.355 ;
        RECT 141.225 48.965 146.570 49.510 ;
        RECT 147.665 48.965 148.875 49.715 ;
        RECT 119.060 48.795 148.960 48.965 ;
        RECT 119.145 48.045 120.355 48.795 ;
        RECT 120.990 48.085 121.245 48.615 ;
        RECT 121.415 48.335 121.720 48.795 ;
        RECT 121.965 48.415 123.035 48.585 ;
        RECT 119.145 47.505 119.665 48.045 ;
        RECT 119.835 47.335 120.355 47.875 ;
        RECT 15.500 45.000 109.500 47.000 ;
        RECT 119.145 46.245 120.355 47.335 ;
        RECT 120.990 47.435 121.200 48.085 ;
        RECT 121.965 48.060 122.285 48.415 ;
        RECT 121.960 47.885 122.285 48.060 ;
        RECT 121.370 47.585 122.285 47.885 ;
        RECT 122.455 47.845 122.695 48.245 ;
        RECT 122.865 48.185 123.035 48.415 ;
        RECT 123.205 48.355 123.395 48.795 ;
        RECT 123.565 48.345 124.515 48.625 ;
        RECT 124.735 48.435 125.085 48.605 ;
        RECT 122.865 48.015 123.395 48.185 ;
        RECT 121.370 47.555 122.110 47.585 ;
        RECT 120.990 46.555 121.245 47.435 ;
        RECT 121.415 46.245 121.720 47.385 ;
        RECT 121.940 46.965 122.110 47.555 ;
        RECT 122.455 47.475 122.995 47.845 ;
        RECT 123.175 47.735 123.395 48.015 ;
        RECT 123.565 47.565 123.735 48.345 ;
        RECT 123.330 47.395 123.735 47.565 ;
        RECT 123.905 47.555 124.255 48.175 ;
        RECT 123.330 47.305 123.500 47.395 ;
        RECT 124.425 47.385 124.635 48.175 ;
        RECT 122.280 47.135 123.500 47.305 ;
        RECT 123.960 47.225 124.635 47.385 ;
        RECT 121.940 46.795 122.740 46.965 ;
        RECT 122.060 46.245 122.390 46.625 ;
        RECT 122.570 46.505 122.740 46.795 ;
        RECT 123.330 46.755 123.500 47.135 ;
        RECT 123.670 47.215 124.635 47.225 ;
        RECT 124.825 48.045 125.085 48.435 ;
        RECT 125.295 48.335 125.625 48.795 ;
        RECT 126.500 48.405 127.355 48.575 ;
        RECT 127.560 48.405 128.055 48.575 ;
        RECT 128.225 48.435 128.555 48.795 ;
        RECT 124.825 47.355 124.995 48.045 ;
        RECT 125.165 47.695 125.335 47.875 ;
        RECT 125.505 47.865 126.295 48.115 ;
        RECT 126.500 47.695 126.670 48.405 ;
        RECT 126.840 47.895 127.195 48.115 ;
        RECT 125.165 47.525 126.855 47.695 ;
        RECT 123.670 46.925 124.130 47.215 ;
        RECT 124.825 47.185 126.325 47.355 ;
        RECT 124.825 47.045 124.995 47.185 ;
        RECT 124.435 46.875 124.995 47.045 ;
        RECT 122.910 46.245 123.160 46.705 ;
        RECT 123.330 46.415 124.200 46.755 ;
        RECT 124.435 46.415 124.605 46.875 ;
        RECT 125.440 46.845 126.515 47.015 ;
        RECT 124.775 46.245 125.145 46.705 ;
        RECT 125.440 46.505 125.610 46.845 ;
        RECT 125.780 46.245 126.110 46.675 ;
        RECT 126.345 46.505 126.515 46.845 ;
        RECT 126.685 46.745 126.855 47.525 ;
        RECT 127.025 47.305 127.195 47.895 ;
        RECT 127.365 47.495 127.715 48.115 ;
        RECT 127.025 46.915 127.490 47.305 ;
        RECT 127.885 47.045 128.055 48.405 ;
        RECT 128.225 47.215 128.685 48.265 ;
        RECT 127.660 46.875 128.055 47.045 ;
        RECT 127.660 46.745 127.830 46.875 ;
        RECT 126.685 46.415 127.365 46.745 ;
        RECT 127.580 46.415 127.830 46.745 ;
        RECT 128.000 46.245 128.250 46.705 ;
        RECT 128.420 46.430 128.745 47.215 ;
        RECT 128.915 46.415 129.085 48.535 ;
        RECT 129.255 48.415 129.585 48.795 ;
        RECT 129.755 48.245 130.010 48.535 ;
        RECT 129.260 48.075 130.010 48.245 ;
        RECT 130.385 48.165 130.715 48.525 ;
        RECT 131.335 48.335 131.585 48.795 ;
        RECT 131.755 48.335 132.315 48.625 ;
        RECT 129.260 47.085 129.490 48.075 ;
        RECT 130.385 47.975 131.775 48.165 ;
        RECT 129.660 47.255 130.010 47.905 ;
        RECT 131.605 47.885 131.775 47.975 ;
        RECT 130.200 47.555 130.875 47.805 ;
        RECT 131.095 47.555 131.435 47.805 ;
        RECT 131.605 47.555 131.895 47.885 ;
        RECT 130.200 47.195 130.465 47.555 ;
        RECT 131.605 47.305 131.775 47.555 ;
        RECT 130.835 47.135 131.775 47.305 ;
        RECT 129.260 46.915 130.010 47.085 ;
        RECT 129.255 46.245 129.585 46.745 ;
        RECT 129.755 46.415 130.010 46.915 ;
        RECT 130.385 46.245 130.665 46.915 ;
        RECT 130.835 46.585 131.135 47.135 ;
        RECT 132.065 46.965 132.315 48.335 ;
        RECT 132.490 48.225 132.745 48.495 ;
        RECT 132.915 48.395 133.245 48.795 ;
        RECT 133.415 48.225 133.585 48.495 ;
        RECT 133.755 48.395 134.085 48.795 ;
        RECT 132.490 48.055 133.715 48.225 ;
        RECT 132.490 47.555 132.825 47.885 ;
        RECT 132.995 47.555 133.375 47.885 ;
        RECT 131.335 46.245 131.665 46.965 ;
        RECT 131.855 46.415 132.315 46.965 ;
        RECT 132.490 46.600 132.825 47.385 ;
        RECT 132.995 46.875 133.230 47.555 ;
        RECT 133.545 47.385 133.715 48.055 ;
        RECT 133.400 47.215 133.715 47.385 ;
        RECT 133.885 47.215 134.155 48.225 ;
        RECT 134.325 48.025 137.835 48.795 ;
        RECT 138.005 48.045 139.215 48.795 ;
        RECT 134.325 47.505 135.975 48.025 ;
        RECT 136.145 47.335 137.835 47.855 ;
        RECT 138.005 47.505 138.525 48.045 ;
        RECT 138.695 47.335 139.215 47.875 ;
        RECT 133.400 46.600 133.570 47.215 ;
        RECT 132.490 46.430 133.570 46.600 ;
        RECT 133.835 46.245 134.150 47.045 ;
        RECT 134.325 46.245 137.835 47.335 ;
        RECT 138.005 46.245 139.215 47.335 ;
        RECT 139.385 47.850 139.725 48.625 ;
        RECT 139.895 48.335 140.065 48.795 ;
        RECT 140.305 48.360 140.665 48.625 ;
        RECT 140.305 48.355 140.660 48.360 ;
        RECT 140.305 48.345 140.655 48.355 ;
        RECT 140.305 48.340 140.650 48.345 ;
        RECT 140.305 48.330 140.645 48.340 ;
        RECT 141.295 48.335 141.465 48.795 ;
        RECT 140.305 48.325 140.640 48.330 ;
        RECT 140.305 48.315 140.630 48.325 ;
        RECT 140.305 48.305 140.620 48.315 ;
        RECT 140.305 48.165 140.605 48.305 ;
        RECT 139.895 47.975 140.605 48.165 ;
        RECT 140.795 48.165 141.125 48.245 ;
        RECT 141.635 48.165 141.975 48.625 ;
        RECT 140.795 47.975 141.975 48.165 ;
        RECT 142.145 48.025 144.735 48.795 ;
        RECT 144.905 48.070 145.195 48.795 ;
        RECT 145.365 48.025 147.035 48.795 ;
        RECT 147.665 48.045 148.875 48.795 ;
        RECT 139.385 46.415 139.665 47.850 ;
        RECT 139.895 47.405 140.180 47.975 ;
        RECT 140.365 47.575 140.835 47.805 ;
        RECT 141.005 47.785 141.335 47.805 ;
        RECT 141.005 47.605 141.455 47.785 ;
        RECT 141.645 47.605 141.975 47.805 ;
        RECT 139.895 47.190 141.045 47.405 ;
        RECT 139.835 46.245 140.545 47.020 ;
        RECT 140.715 46.415 141.045 47.190 ;
        RECT 141.240 46.490 141.455 47.605 ;
        RECT 141.745 47.265 141.975 47.605 ;
        RECT 142.145 47.505 143.355 48.025 ;
        RECT 143.525 47.335 144.735 47.855 ;
        RECT 145.365 47.505 146.115 48.025 ;
        RECT 141.635 46.245 141.965 46.965 ;
        RECT 142.145 46.245 144.735 47.335 ;
        RECT 144.905 46.245 145.195 47.410 ;
        RECT 146.285 47.335 147.035 47.855 ;
        RECT 145.365 46.245 147.035 47.335 ;
        RECT 147.665 47.335 148.185 47.875 ;
        RECT 148.355 47.505 148.875 48.045 ;
        RECT 147.665 46.245 148.875 47.335 ;
        RECT 119.060 46.075 148.960 46.245 ;
        RECT 15.500 39.800 37.470 39.970 ;
        RECT 15.500 18.170 15.670 39.800 ;
        RECT 16.185 38.080 36.785 39.800 ;
        RECT 16.185 33.990 17.390 38.080 ;
        RECT 17.700 34.300 21.170 37.770 ;
        RECT 21.480 33.990 24.485 38.080 ;
        RECT 24.750 34.300 28.220 37.770 ;
        RECT 28.485 33.990 31.490 38.080 ;
        RECT 31.800 34.300 35.270 37.770 ;
        RECT 35.580 33.990 36.785 38.080 ;
        RECT 16.185 30.985 36.785 33.990 ;
        RECT 16.185 26.985 17.390 30.985 ;
        RECT 17.700 27.250 21.170 30.720 ;
        RECT 21.480 26.985 24.485 30.985 ;
        RECT 24.750 27.250 28.220 30.720 ;
        RECT 28.485 26.985 31.490 30.985 ;
        RECT 31.800 27.250 35.270 30.720 ;
        RECT 35.580 26.985 36.785 30.985 ;
        RECT 16.185 23.980 36.785 26.985 ;
        RECT 16.185 19.890 17.390 23.980 ;
        RECT 17.700 20.200 21.170 23.670 ;
        RECT 21.480 19.890 24.485 23.980 ;
        RECT 24.750 20.200 28.220 23.670 ;
        RECT 28.485 19.890 31.490 23.980 ;
        RECT 31.800 20.200 35.270 23.670 ;
        RECT 35.580 19.890 36.785 23.980 ;
        RECT 16.185 18.170 36.785 19.890 ;
        RECT 37.300 18.170 37.470 39.800 ;
        RECT 38.440 38.240 39.640 45.000 ;
        RECT 44.940 43.740 46.140 45.000 ;
        RECT 76.500 43.740 77.500 45.000 ;
        RECT 44.940 42.540 54.220 43.740 ;
        RECT 44.940 38.240 45.900 42.540 ;
        RECT 46.860 40.740 51.660 41.140 ;
        RECT 46.220 39.540 46.540 40.740 ;
        RECT 47.500 39.940 52.300 40.340 ;
        RECT 52.620 39.540 52.940 40.740 ;
        RECT 46.860 39.140 51.660 39.540 ;
        RECT 38.440 37.940 45.900 38.240 ;
        RECT 53.260 37.940 54.220 42.540 ;
        RECT 74.940 42.540 84.220 43.740 ;
        RECT 38.440 37.040 54.220 37.940 ;
        RECT 38.440 20.440 39.400 37.040 ;
        RECT 41.200 36.440 42.600 37.040 ;
        RECT 40.360 36.040 42.600 36.440 ;
        RECT 39.720 34.900 40.040 35.240 ;
        RECT 41.200 34.900 42.600 36.040 ;
        RECT 44.200 36.740 54.220 37.040 ;
        RECT 56.940 37.040 72.540 38.240 ;
        RECT 39.720 34.840 42.600 34.900 ;
        RECT 39.720 34.440 43.240 34.840 ;
        RECT 39.720 34.400 42.600 34.440 ;
        RECT 39.720 34.040 40.040 34.400 ;
        RECT 41.200 33.240 42.600 34.400 ;
        RECT 43.560 34.040 43.880 35.240 ;
        RECT 40.360 32.840 42.600 33.240 ;
        RECT 40.360 32.040 42.600 32.440 ;
        RECT 39.720 30.040 40.040 31.240 ;
        RECT 41.000 30.440 43.240 30.840 ;
        RECT 43.560 30.040 43.880 31.240 ;
        RECT 40.360 28.840 42.600 29.240 ;
        RECT 40.360 28.040 42.600 28.440 ;
        RECT 39.720 26.040 40.040 27.240 ;
        RECT 41.000 26.440 43.240 26.840 ;
        RECT 43.560 26.040 43.880 27.240 ;
        RECT 40.360 24.840 42.600 25.240 ;
        RECT 40.360 24.040 42.600 24.440 ;
        RECT 39.720 22.900 40.040 23.240 ;
        RECT 41.200 22.900 42.600 24.040 ;
        RECT 39.720 22.840 42.600 22.900 ;
        RECT 39.720 22.440 43.240 22.840 ;
        RECT 39.720 22.400 42.600 22.440 ;
        RECT 39.720 22.040 40.040 22.400 ;
        RECT 41.200 21.240 42.600 22.400 ;
        RECT 43.560 22.040 43.880 23.240 ;
        RECT 40.360 20.840 42.600 21.240 ;
        RECT 41.200 20.440 42.600 20.840 ;
        RECT 44.200 20.440 45.160 36.740 ;
        RECT 38.440 19.240 45.160 20.440 ;
        RECT 46.080 34.660 55.320 35.220 ;
        RECT 46.080 18.740 46.640 34.660 ;
        RECT 52.550 33.900 53.450 33.950 ;
        RECT 47.820 32.700 49.260 33.900 ;
        RECT 48.900 29.100 49.260 32.700 ;
        RECT 49.980 32.700 51.420 33.900 ;
        RECT 49.980 29.100 50.340 32.700 ;
        RECT 51.060 29.100 51.420 32.700 ;
        RECT 52.140 32.700 53.580 33.900 ;
        RECT 52.140 29.100 52.500 32.700 ;
        RECT 48.900 19.500 50.340 21.900 ;
        RECT 51.060 19.500 52.500 21.900 ;
        RECT 54.760 18.740 55.320 34.660 ;
        RECT 56.940 20.440 57.900 37.040 ;
        RECT 58.860 36.040 62.380 36.440 ;
        RECT 58.220 34.040 58.540 35.240 ;
        RECT 59.500 34.440 63.020 34.840 ;
        RECT 63.340 34.040 63.660 35.240 ;
        RECT 58.860 32.840 62.380 33.240 ;
        RECT 58.860 32.040 62.380 32.440 ;
        RECT 58.220 30.040 58.540 31.240 ;
        RECT 59.500 30.440 63.020 30.840 ;
        RECT 63.340 30.040 63.660 31.240 ;
        RECT 58.860 28.840 62.380 29.240 ;
        RECT 58.860 28.040 62.380 28.440 ;
        RECT 58.220 26.040 58.540 27.240 ;
        RECT 59.500 26.440 63.020 26.840 ;
        RECT 63.340 26.040 63.660 27.240 ;
        RECT 58.860 24.840 62.380 25.240 ;
        RECT 58.860 24.040 62.380 24.440 ;
        RECT 58.220 22.040 58.540 23.240 ;
        RECT 59.500 22.440 63.020 22.840 ;
        RECT 63.340 22.040 63.660 23.240 ;
        RECT 58.860 20.840 62.380 21.240 ;
        RECT 63.980 20.440 65.500 37.040 ;
        RECT 66.460 36.040 69.980 36.440 ;
        RECT 65.820 34.040 66.140 35.240 ;
        RECT 67.100 34.440 70.620 34.840 ;
        RECT 70.940 34.040 71.260 35.240 ;
        RECT 66.460 32.840 69.980 33.240 ;
        RECT 66.460 32.040 69.980 32.440 ;
        RECT 65.820 30.040 66.140 31.240 ;
        RECT 67.100 30.440 70.620 30.840 ;
        RECT 70.940 30.040 71.260 31.240 ;
        RECT 66.460 28.840 69.980 29.240 ;
        RECT 66.460 28.040 69.980 28.440 ;
        RECT 65.820 26.040 66.140 27.240 ;
        RECT 67.100 26.440 70.620 26.840 ;
        RECT 70.940 26.040 71.260 27.240 ;
        RECT 66.460 24.840 69.980 25.240 ;
        RECT 66.460 24.040 69.980 24.440 ;
        RECT 65.820 22.040 66.140 23.240 ;
        RECT 67.100 22.440 70.620 22.840 ;
        RECT 70.940 22.040 71.260 23.240 ;
        RECT 66.460 20.840 69.980 21.240 ;
        RECT 71.580 20.440 72.540 37.040 ;
        RECT 74.940 37.940 75.900 42.540 ;
        RECT 76.860 41.540 81.660 41.940 ;
        RECT 76.220 39.540 76.540 40.740 ;
        RECT 77.500 39.940 82.300 40.340 ;
        RECT 82.620 39.540 82.940 40.740 ;
        RECT 76.860 38.340 81.660 38.740 ;
        RECT 83.260 37.940 84.220 42.540 ;
        RECT 90.500 38.240 92.500 45.000 ;
        RECT 101.500 38.240 103.500 45.000 ;
        RECT 119.145 44.985 120.355 46.075 ;
        RECT 119.145 44.275 119.665 44.815 ;
        RECT 119.835 44.445 120.355 44.985 ;
        RECT 120.605 45.145 120.785 45.905 ;
        RECT 120.965 45.315 121.295 46.075 ;
        RECT 120.605 44.975 121.280 45.145 ;
        RECT 121.465 45.000 121.735 45.905 ;
        RECT 121.110 44.830 121.280 44.975 ;
        RECT 120.545 44.425 120.885 44.795 ;
        RECT 121.110 44.500 121.385 44.830 ;
        RECT 119.145 43.525 120.355 44.275 ;
        RECT 121.110 44.245 121.280 44.500 ;
        RECT 120.615 44.075 121.280 44.245 ;
        RECT 121.555 44.200 121.735 45.000 ;
        RECT 121.905 44.985 125.415 46.075 ;
        RECT 120.615 43.695 120.785 44.075 ;
        RECT 120.965 43.525 121.295 43.905 ;
        RECT 121.475 43.695 121.735 44.200 ;
        RECT 121.905 44.295 123.555 44.815 ;
        RECT 123.725 44.465 125.415 44.985 ;
        RECT 125.595 45.465 125.925 45.895 ;
        RECT 126.105 45.635 126.300 46.075 ;
        RECT 126.470 45.465 126.800 45.895 ;
        RECT 125.595 45.295 126.800 45.465 ;
        RECT 125.595 44.965 126.490 45.295 ;
        RECT 126.970 45.125 127.245 45.895 ;
        RECT 126.660 44.935 127.245 45.125 ;
        RECT 127.435 45.125 127.710 45.895 ;
        RECT 127.880 45.465 128.210 45.895 ;
        RECT 128.380 45.635 128.575 46.075 ;
        RECT 128.755 45.465 129.085 45.895 ;
        RECT 127.880 45.295 129.085 45.465 ;
        RECT 127.435 44.935 128.020 45.125 ;
        RECT 128.190 44.965 129.085 45.295 ;
        RECT 129.265 44.985 131.855 46.075 ;
        RECT 125.600 44.435 125.895 44.765 ;
        RECT 126.075 44.435 126.490 44.765 ;
        RECT 121.905 43.525 125.415 44.295 ;
        RECT 125.595 43.525 125.895 44.255 ;
        RECT 126.075 43.815 126.305 44.435 ;
        RECT 126.660 44.265 126.835 44.935 ;
        RECT 126.505 44.085 126.835 44.265 ;
        RECT 127.005 44.115 127.245 44.765 ;
        RECT 127.435 44.115 127.675 44.765 ;
        RECT 127.845 44.265 128.020 44.935 ;
        RECT 128.190 44.435 128.605 44.765 ;
        RECT 128.785 44.435 129.080 44.765 ;
        RECT 127.845 44.085 128.175 44.265 ;
        RECT 126.505 43.705 126.730 44.085 ;
        RECT 126.900 43.525 127.230 43.915 ;
        RECT 127.450 43.525 127.780 43.915 ;
        RECT 127.950 43.705 128.175 44.085 ;
        RECT 128.375 43.815 128.605 44.435 ;
        RECT 129.265 44.295 130.475 44.815 ;
        RECT 130.645 44.465 131.855 44.985 ;
        RECT 132.025 44.910 132.315 46.075 ;
        RECT 132.485 44.985 135.995 46.075 ;
        RECT 136.165 44.985 137.375 46.075 ;
        RECT 137.550 45.405 137.805 45.905 ;
        RECT 137.975 45.575 138.305 46.075 ;
        RECT 137.550 45.235 138.300 45.405 ;
        RECT 132.485 44.295 134.135 44.815 ;
        RECT 134.305 44.465 135.995 44.985 ;
        RECT 128.785 43.525 129.085 44.255 ;
        RECT 129.265 43.525 131.855 44.295 ;
        RECT 132.025 43.525 132.315 44.250 ;
        RECT 132.485 43.525 135.995 44.295 ;
        RECT 136.165 44.275 136.685 44.815 ;
        RECT 136.855 44.445 137.375 44.985 ;
        RECT 137.550 44.415 137.900 45.065 ;
        RECT 136.165 43.525 137.375 44.275 ;
        RECT 138.070 44.245 138.300 45.235 ;
        RECT 137.550 44.075 138.300 44.245 ;
        RECT 137.550 43.785 137.805 44.075 ;
        RECT 137.975 43.525 138.305 43.905 ;
        RECT 138.475 43.785 138.645 45.905 ;
        RECT 138.815 45.105 139.140 45.890 ;
        RECT 139.310 45.615 139.560 46.075 ;
        RECT 139.730 45.575 139.980 45.905 ;
        RECT 140.195 45.575 140.875 45.905 ;
        RECT 139.730 45.445 139.900 45.575 ;
        RECT 139.505 45.275 139.900 45.445 ;
        RECT 138.875 44.055 139.335 45.105 ;
        RECT 139.505 43.915 139.675 45.275 ;
        RECT 140.070 45.015 140.535 45.405 ;
        RECT 139.845 44.205 140.195 44.825 ;
        RECT 140.365 44.425 140.535 45.015 ;
        RECT 140.705 44.795 140.875 45.575 ;
        RECT 141.045 45.475 141.215 45.815 ;
        RECT 141.450 45.645 141.780 46.075 ;
        RECT 141.950 45.475 142.120 45.815 ;
        RECT 142.415 45.615 142.785 46.075 ;
        RECT 141.045 45.305 142.120 45.475 ;
        RECT 142.955 45.445 143.125 45.905 ;
        RECT 143.360 45.565 144.230 45.905 ;
        RECT 144.400 45.615 144.650 46.075 ;
        RECT 142.565 45.275 143.125 45.445 ;
        RECT 142.565 45.135 142.735 45.275 ;
        RECT 141.235 44.965 142.735 45.135 ;
        RECT 143.430 45.105 143.890 45.395 ;
        RECT 140.705 44.625 142.395 44.795 ;
        RECT 140.365 44.205 140.720 44.425 ;
        RECT 140.890 43.915 141.060 44.625 ;
        RECT 141.265 44.205 142.055 44.455 ;
        RECT 142.225 44.445 142.395 44.625 ;
        RECT 142.565 44.275 142.735 44.965 ;
        RECT 139.005 43.525 139.335 43.885 ;
        RECT 139.505 43.745 140.000 43.915 ;
        RECT 140.205 43.745 141.060 43.915 ;
        RECT 141.935 43.525 142.265 43.985 ;
        RECT 142.475 43.885 142.735 44.275 ;
        RECT 142.925 45.095 143.890 45.105 ;
        RECT 144.060 45.185 144.230 45.565 ;
        RECT 144.820 45.525 144.990 45.815 ;
        RECT 145.170 45.695 145.500 46.075 ;
        RECT 144.820 45.355 145.620 45.525 ;
        RECT 142.925 44.935 143.600 45.095 ;
        RECT 144.060 45.015 145.280 45.185 ;
        RECT 142.925 44.145 143.135 44.935 ;
        RECT 144.060 44.925 144.230 45.015 ;
        RECT 143.305 44.145 143.655 44.765 ;
        RECT 143.825 44.755 144.230 44.925 ;
        RECT 143.825 43.975 143.995 44.755 ;
        RECT 144.165 44.305 144.385 44.585 ;
        RECT 144.565 44.475 145.105 44.845 ;
        RECT 145.450 44.765 145.620 45.355 ;
        RECT 145.840 44.935 146.145 46.075 ;
        RECT 146.315 44.885 146.565 45.765 ;
        RECT 146.735 44.935 146.985 46.075 ;
        RECT 147.665 44.985 148.875 46.075 ;
        RECT 145.450 44.735 146.190 44.765 ;
        RECT 144.165 44.135 144.695 44.305 ;
        RECT 142.475 43.715 142.825 43.885 ;
        RECT 143.045 43.695 143.995 43.975 ;
        RECT 144.165 43.525 144.355 43.965 ;
        RECT 144.525 43.905 144.695 44.135 ;
        RECT 144.865 44.075 145.105 44.475 ;
        RECT 145.275 44.435 146.190 44.735 ;
        RECT 145.275 44.260 145.600 44.435 ;
        RECT 145.275 43.905 145.595 44.260 ;
        RECT 146.360 44.235 146.565 44.885 ;
        RECT 147.665 44.445 148.185 44.985 ;
        RECT 144.525 43.735 145.595 43.905 ;
        RECT 145.840 43.525 146.145 43.985 ;
        RECT 146.315 43.705 146.565 44.235 ;
        RECT 146.735 43.525 146.985 44.280 ;
        RECT 148.355 44.275 148.875 44.815 ;
        RECT 147.665 43.525 148.875 44.275 ;
        RECT 119.060 43.355 148.960 43.525 ;
        RECT 119.145 42.605 120.355 43.355 ;
        RECT 119.145 42.065 119.665 42.605 ;
        RECT 120.525 42.585 124.035 43.355 ;
        RECT 119.835 41.895 120.355 42.435 ;
        RECT 120.525 42.065 122.175 42.585 ;
        RECT 122.345 41.895 124.035 42.415 ;
        RECT 119.145 40.805 120.355 41.895 ;
        RECT 120.525 40.805 124.035 41.895 ;
        RECT 124.665 42.410 125.005 43.185 ;
        RECT 125.175 42.895 125.345 43.355 ;
        RECT 125.585 42.920 125.945 43.185 ;
        RECT 125.585 42.915 125.940 42.920 ;
        RECT 125.585 42.905 125.935 42.915 ;
        RECT 125.585 42.900 125.930 42.905 ;
        RECT 125.585 42.890 125.925 42.900 ;
        RECT 126.575 42.895 126.745 43.355 ;
        RECT 125.585 42.885 125.920 42.890 ;
        RECT 125.585 42.875 125.910 42.885 ;
        RECT 125.585 42.865 125.900 42.875 ;
        RECT 125.585 42.725 125.885 42.865 ;
        RECT 125.175 42.535 125.885 42.725 ;
        RECT 126.075 42.725 126.405 42.805 ;
        RECT 126.915 42.725 127.255 43.185 ;
        RECT 127.975 42.875 128.275 43.355 ;
        RECT 126.075 42.535 127.255 42.725 ;
        RECT 128.445 42.705 128.705 43.160 ;
        RECT 128.875 42.875 129.135 43.355 ;
        RECT 129.315 42.705 129.575 43.160 ;
        RECT 129.745 42.875 129.995 43.355 ;
        RECT 130.175 42.705 130.435 43.160 ;
        RECT 130.605 42.875 130.855 43.355 ;
        RECT 131.035 42.705 131.295 43.160 ;
        RECT 131.465 42.875 131.710 43.355 ;
        RECT 131.880 42.705 132.155 43.160 ;
        RECT 132.325 42.875 132.570 43.355 ;
        RECT 132.740 42.705 133.000 43.160 ;
        RECT 133.170 42.875 133.430 43.355 ;
        RECT 133.600 42.705 133.860 43.160 ;
        RECT 134.030 42.875 134.290 43.355 ;
        RECT 134.460 42.705 134.720 43.160 ;
        RECT 134.890 42.795 135.150 43.355 ;
        RECT 127.975 42.535 134.720 42.705 ;
        RECT 124.665 40.975 124.945 42.410 ;
        RECT 125.175 41.965 125.460 42.535 ;
        RECT 125.645 42.135 126.115 42.365 ;
        RECT 126.285 42.345 126.615 42.365 ;
        RECT 126.285 42.165 126.735 42.345 ;
        RECT 126.925 42.165 127.255 42.365 ;
        RECT 125.175 41.750 126.325 41.965 ;
        RECT 125.115 40.805 125.825 41.580 ;
        RECT 125.995 40.975 126.325 41.750 ;
        RECT 126.520 41.050 126.735 42.165 ;
        RECT 127.025 41.825 127.255 42.165 ;
        RECT 127.975 41.945 129.140 42.535 ;
        RECT 135.320 42.365 135.570 43.175 ;
        RECT 135.750 42.830 136.010 43.355 ;
        RECT 136.180 42.365 136.430 43.175 ;
        RECT 136.610 42.845 136.915 43.355 ;
        RECT 137.085 42.705 137.345 43.185 ;
        RECT 137.515 42.815 137.765 43.355 ;
        RECT 129.310 42.115 136.430 42.365 ;
        RECT 136.600 42.115 136.915 42.675 ;
        RECT 127.975 41.720 134.720 41.945 ;
        RECT 126.915 40.805 127.245 41.525 ;
        RECT 127.975 40.805 128.245 41.550 ;
        RECT 128.415 40.980 128.705 41.720 ;
        RECT 129.315 41.705 134.720 41.720 ;
        RECT 128.875 40.810 129.130 41.535 ;
        RECT 129.315 40.980 129.575 41.705 ;
        RECT 129.745 40.810 129.990 41.535 ;
        RECT 130.175 40.980 130.435 41.705 ;
        RECT 130.605 40.810 130.850 41.535 ;
        RECT 131.035 40.980 131.295 41.705 ;
        RECT 131.465 40.810 131.710 41.535 ;
        RECT 131.880 40.980 132.140 41.705 ;
        RECT 132.310 40.810 132.570 41.535 ;
        RECT 132.740 40.980 133.000 41.705 ;
        RECT 133.170 40.810 133.430 41.535 ;
        RECT 133.600 40.980 133.860 41.705 ;
        RECT 134.030 40.810 134.290 41.535 ;
        RECT 134.460 40.980 134.720 41.705 ;
        RECT 134.890 40.810 135.150 41.605 ;
        RECT 135.320 40.980 135.570 42.115 ;
        RECT 128.875 40.805 135.150 40.810 ;
        RECT 135.750 40.805 136.010 41.615 ;
        RECT 136.185 40.975 136.430 42.115 ;
        RECT 137.085 41.675 137.255 42.705 ;
        RECT 137.935 42.650 138.155 43.135 ;
        RECT 137.425 42.055 137.655 42.450 ;
        RECT 137.825 42.225 138.155 42.650 ;
        RECT 138.325 42.975 139.215 43.145 ;
        RECT 138.325 42.250 138.495 42.975 ;
        RECT 139.410 42.965 139.740 43.355 ;
        RECT 138.665 42.420 139.215 42.805 ;
        RECT 139.910 42.795 140.135 43.175 ;
        RECT 138.325 42.180 139.215 42.250 ;
        RECT 138.320 42.155 139.215 42.180 ;
        RECT 138.310 42.140 139.215 42.155 ;
        RECT 138.305 42.125 139.215 42.140 ;
        RECT 138.295 42.120 139.215 42.125 ;
        RECT 138.290 42.110 139.215 42.120 ;
        RECT 139.395 42.115 139.635 42.765 ;
        RECT 139.805 42.615 140.135 42.795 ;
        RECT 138.285 42.100 139.215 42.110 ;
        RECT 138.275 42.095 139.215 42.100 ;
        RECT 138.265 42.085 139.215 42.095 ;
        RECT 138.255 42.080 139.215 42.085 ;
        RECT 138.255 42.075 138.590 42.080 ;
        RECT 138.240 42.070 138.590 42.075 ;
        RECT 138.225 42.060 138.590 42.070 ;
        RECT 138.200 42.055 138.590 42.060 ;
        RECT 137.425 42.050 138.590 42.055 ;
        RECT 137.425 42.015 138.560 42.050 ;
        RECT 137.425 41.990 138.525 42.015 ;
        RECT 137.425 41.960 138.495 41.990 ;
        RECT 137.425 41.930 138.475 41.960 ;
        RECT 137.425 41.900 138.455 41.930 ;
        RECT 137.425 41.890 138.385 41.900 ;
        RECT 137.425 41.880 138.360 41.890 ;
        RECT 137.425 41.865 138.340 41.880 ;
        RECT 137.425 41.850 138.320 41.865 ;
        RECT 137.530 41.840 138.315 41.850 ;
        RECT 137.530 41.805 138.300 41.840 ;
        RECT 136.610 40.805 136.905 41.615 ;
        RECT 137.085 40.975 137.360 41.675 ;
        RECT 137.530 41.555 138.285 41.805 ;
        RECT 138.455 41.485 138.785 41.730 ;
        RECT 138.955 41.630 139.215 42.080 ;
        RECT 139.805 41.945 139.980 42.615 ;
        RECT 140.335 42.445 140.565 43.065 ;
        RECT 140.745 42.625 141.045 43.355 ;
        RECT 141.225 42.585 144.735 43.355 ;
        RECT 144.905 42.630 145.195 43.355 ;
        RECT 145.365 42.585 147.035 43.355 ;
        RECT 147.665 42.605 148.875 43.355 ;
        RECT 140.150 42.115 140.565 42.445 ;
        RECT 140.745 42.115 141.040 42.445 ;
        RECT 141.225 42.065 142.875 42.585 ;
        RECT 139.395 41.755 139.980 41.945 ;
        RECT 138.600 41.460 138.785 41.485 ;
        RECT 138.600 41.360 139.215 41.460 ;
        RECT 137.530 40.805 137.785 41.350 ;
        RECT 137.955 40.975 138.435 41.315 ;
        RECT 138.610 40.805 139.215 41.360 ;
        RECT 139.395 40.985 139.670 41.755 ;
        RECT 140.150 41.585 141.045 41.915 ;
        RECT 143.045 41.895 144.735 42.415 ;
        RECT 145.365 42.065 146.115 42.585 ;
        RECT 139.840 41.415 141.045 41.585 ;
        RECT 139.840 40.985 140.170 41.415 ;
        RECT 140.340 40.805 140.535 41.245 ;
        RECT 140.715 40.985 141.045 41.415 ;
        RECT 141.225 40.805 144.735 41.895 ;
        RECT 144.905 40.805 145.195 41.970 ;
        RECT 146.285 41.895 147.035 42.415 ;
        RECT 145.365 40.805 147.035 41.895 ;
        RECT 147.665 41.895 148.185 42.435 ;
        RECT 148.355 42.065 148.875 42.605 ;
        RECT 147.665 40.805 148.875 41.895 ;
        RECT 119.060 40.635 148.960 40.805 ;
        RECT 119.145 39.545 120.355 40.635 ;
        RECT 120.990 39.965 121.245 40.465 ;
        RECT 121.415 40.135 121.745 40.635 ;
        RECT 120.990 39.795 121.740 39.965 ;
        RECT 119.145 38.835 119.665 39.375 ;
        RECT 119.835 39.005 120.355 39.545 ;
        RECT 120.990 38.975 121.340 39.625 ;
        RECT 74.940 36.740 84.220 37.940 ;
        RECT 90.440 37.040 103.560 38.240 ;
        RECT 119.145 38.085 120.355 38.835 ;
        RECT 121.510 38.805 121.740 39.795 ;
        RECT 120.990 38.635 121.740 38.805 ;
        RECT 120.990 38.345 121.245 38.635 ;
        RECT 121.415 38.085 121.745 38.465 ;
        RECT 121.915 38.345 122.085 40.465 ;
        RECT 122.255 39.665 122.580 40.450 ;
        RECT 122.750 40.175 123.000 40.635 ;
        RECT 123.170 40.135 123.420 40.465 ;
        RECT 123.635 40.135 124.315 40.465 ;
        RECT 123.170 40.005 123.340 40.135 ;
        RECT 122.945 39.835 123.340 40.005 ;
        RECT 122.315 38.615 122.775 39.665 ;
        RECT 122.945 38.475 123.115 39.835 ;
        RECT 123.510 39.575 123.975 39.965 ;
        RECT 123.285 38.765 123.635 39.385 ;
        RECT 123.805 38.985 123.975 39.575 ;
        RECT 124.145 39.355 124.315 40.135 ;
        RECT 124.485 40.035 124.655 40.375 ;
        RECT 124.890 40.205 125.220 40.635 ;
        RECT 125.390 40.035 125.560 40.375 ;
        RECT 125.855 40.175 126.225 40.635 ;
        RECT 124.485 39.865 125.560 40.035 ;
        RECT 126.395 40.005 126.565 40.465 ;
        RECT 126.800 40.125 127.670 40.465 ;
        RECT 127.840 40.175 128.090 40.635 ;
        RECT 126.005 39.835 126.565 40.005 ;
        RECT 126.005 39.695 126.175 39.835 ;
        RECT 124.675 39.525 126.175 39.695 ;
        RECT 126.870 39.665 127.330 39.955 ;
        RECT 124.145 39.185 125.835 39.355 ;
        RECT 123.805 38.765 124.160 38.985 ;
        RECT 124.330 38.475 124.500 39.185 ;
        RECT 124.705 38.765 125.495 39.015 ;
        RECT 125.665 39.005 125.835 39.185 ;
        RECT 126.005 38.835 126.175 39.525 ;
        RECT 122.445 38.085 122.775 38.445 ;
        RECT 122.945 38.305 123.440 38.475 ;
        RECT 123.645 38.305 124.500 38.475 ;
        RECT 125.375 38.085 125.705 38.545 ;
        RECT 125.915 38.445 126.175 38.835 ;
        RECT 126.365 39.655 127.330 39.665 ;
        RECT 127.500 39.745 127.670 40.125 ;
        RECT 128.260 40.085 128.430 40.375 ;
        RECT 128.610 40.255 128.940 40.635 ;
        RECT 128.260 39.915 129.060 40.085 ;
        RECT 126.365 39.495 127.040 39.655 ;
        RECT 127.500 39.575 128.720 39.745 ;
        RECT 126.365 38.705 126.575 39.495 ;
        RECT 127.500 39.485 127.670 39.575 ;
        RECT 126.745 38.705 127.095 39.325 ;
        RECT 127.265 39.315 127.670 39.485 ;
        RECT 127.265 38.535 127.435 39.315 ;
        RECT 127.605 38.865 127.825 39.145 ;
        RECT 128.005 39.035 128.545 39.405 ;
        RECT 128.890 39.325 129.060 39.915 ;
        RECT 129.280 39.495 129.585 40.635 ;
        RECT 129.755 39.445 130.010 40.325 ;
        RECT 130.190 39.835 130.505 40.635 ;
        RECT 130.770 40.280 131.850 40.450 ;
        RECT 130.770 39.665 130.940 40.280 ;
        RECT 128.890 39.295 129.630 39.325 ;
        RECT 127.605 38.695 128.135 38.865 ;
        RECT 125.915 38.275 126.265 38.445 ;
        RECT 126.485 38.255 127.435 38.535 ;
        RECT 127.605 38.085 127.795 38.525 ;
        RECT 127.965 38.465 128.135 38.695 ;
        RECT 128.305 38.635 128.545 39.035 ;
        RECT 128.715 38.995 129.630 39.295 ;
        RECT 128.715 38.820 129.040 38.995 ;
        RECT 128.715 38.465 129.035 38.820 ;
        RECT 129.800 38.795 130.010 39.445 ;
        RECT 127.965 38.295 129.035 38.465 ;
        RECT 129.280 38.085 129.585 38.545 ;
        RECT 129.755 38.265 130.010 38.795 ;
        RECT 130.185 38.655 130.455 39.665 ;
        RECT 130.625 39.495 130.940 39.665 ;
        RECT 130.625 38.825 130.795 39.495 ;
        RECT 131.110 39.325 131.345 40.005 ;
        RECT 131.515 39.495 131.850 40.280 ;
        RECT 132.025 39.470 132.315 40.635 ;
        RECT 132.485 39.545 133.695 40.635 ;
        RECT 133.870 39.965 134.125 40.465 ;
        RECT 134.295 40.135 134.625 40.635 ;
        RECT 133.870 39.795 134.620 39.965 ;
        RECT 130.965 38.995 131.345 39.325 ;
        RECT 131.515 38.995 131.850 39.325 ;
        RECT 132.485 38.835 133.005 39.375 ;
        RECT 133.175 39.005 133.695 39.545 ;
        RECT 133.870 38.975 134.220 39.625 ;
        RECT 130.625 38.655 131.850 38.825 ;
        RECT 130.255 38.085 130.585 38.485 ;
        RECT 130.755 38.385 130.925 38.655 ;
        RECT 131.095 38.085 131.425 38.485 ;
        RECT 131.595 38.385 131.850 38.655 ;
        RECT 132.025 38.085 132.315 38.810 ;
        RECT 132.485 38.085 133.695 38.835 ;
        RECT 134.390 38.805 134.620 39.795 ;
        RECT 133.870 38.635 134.620 38.805 ;
        RECT 133.870 38.345 134.125 38.635 ;
        RECT 134.295 38.085 134.625 38.465 ;
        RECT 134.795 38.345 134.965 40.465 ;
        RECT 135.135 39.665 135.460 40.450 ;
        RECT 135.630 40.175 135.880 40.635 ;
        RECT 136.050 40.135 136.300 40.465 ;
        RECT 136.515 40.135 137.195 40.465 ;
        RECT 136.050 40.005 136.220 40.135 ;
        RECT 135.825 39.835 136.220 40.005 ;
        RECT 135.195 38.615 135.655 39.665 ;
        RECT 135.825 38.475 135.995 39.835 ;
        RECT 136.390 39.575 136.855 39.965 ;
        RECT 136.165 38.765 136.515 39.385 ;
        RECT 136.685 38.985 136.855 39.575 ;
        RECT 137.025 39.355 137.195 40.135 ;
        RECT 137.365 40.035 137.535 40.375 ;
        RECT 137.770 40.205 138.100 40.635 ;
        RECT 138.270 40.035 138.440 40.375 ;
        RECT 138.735 40.175 139.105 40.635 ;
        RECT 137.365 39.865 138.440 40.035 ;
        RECT 139.275 40.005 139.445 40.465 ;
        RECT 139.680 40.125 140.550 40.465 ;
        RECT 140.720 40.175 140.970 40.635 ;
        RECT 138.885 39.835 139.445 40.005 ;
        RECT 138.885 39.695 139.055 39.835 ;
        RECT 137.555 39.525 139.055 39.695 ;
        RECT 139.750 39.665 140.210 39.955 ;
        RECT 137.025 39.185 138.715 39.355 ;
        RECT 136.685 38.765 137.040 38.985 ;
        RECT 137.210 38.475 137.380 39.185 ;
        RECT 137.585 38.765 138.375 39.015 ;
        RECT 138.545 39.005 138.715 39.185 ;
        RECT 138.885 38.835 139.055 39.525 ;
        RECT 135.325 38.085 135.655 38.445 ;
        RECT 135.825 38.305 136.320 38.475 ;
        RECT 136.525 38.305 137.380 38.475 ;
        RECT 138.255 38.085 138.585 38.545 ;
        RECT 138.795 38.445 139.055 38.835 ;
        RECT 139.245 39.655 140.210 39.665 ;
        RECT 140.380 39.745 140.550 40.125 ;
        RECT 141.140 40.085 141.310 40.375 ;
        RECT 141.490 40.255 141.820 40.635 ;
        RECT 141.140 39.915 141.940 40.085 ;
        RECT 139.245 39.495 139.920 39.655 ;
        RECT 140.380 39.575 141.600 39.745 ;
        RECT 139.245 38.705 139.455 39.495 ;
        RECT 140.380 39.485 140.550 39.575 ;
        RECT 139.625 38.705 139.975 39.325 ;
        RECT 140.145 39.315 140.550 39.485 ;
        RECT 140.145 38.535 140.315 39.315 ;
        RECT 140.485 38.865 140.705 39.145 ;
        RECT 140.885 39.035 141.425 39.405 ;
        RECT 141.770 39.325 141.940 39.915 ;
        RECT 142.160 39.495 142.465 40.635 ;
        RECT 142.635 39.445 142.890 40.325 ;
        RECT 143.065 39.545 146.575 40.635 ;
        RECT 141.770 39.295 142.510 39.325 ;
        RECT 140.485 38.695 141.015 38.865 ;
        RECT 138.795 38.275 139.145 38.445 ;
        RECT 139.365 38.255 140.315 38.535 ;
        RECT 140.485 38.085 140.675 38.525 ;
        RECT 140.845 38.465 141.015 38.695 ;
        RECT 141.185 38.635 141.425 39.035 ;
        RECT 141.595 38.995 142.510 39.295 ;
        RECT 141.595 38.820 141.920 38.995 ;
        RECT 141.595 38.465 141.915 38.820 ;
        RECT 142.680 38.795 142.890 39.445 ;
        RECT 140.845 38.295 141.915 38.465 ;
        RECT 142.160 38.085 142.465 38.545 ;
        RECT 142.635 38.265 142.890 38.795 ;
        RECT 143.065 38.855 144.715 39.375 ;
        RECT 144.885 39.025 146.575 39.545 ;
        RECT 147.665 39.545 148.875 40.635 ;
        RECT 147.665 39.005 148.185 39.545 ;
        RECT 143.065 38.085 146.575 38.855 ;
        RECT 148.355 38.835 148.875 39.375 ;
        RECT 147.665 38.085 148.875 38.835 ;
        RECT 119.060 37.915 148.960 38.085 ;
        RECT 56.940 19.240 72.540 20.440 ;
        RECT 73.380 34.660 82.620 35.220 ;
        RECT 46.080 18.180 55.320 18.740 ;
        RECT 73.380 18.740 73.940 34.660 ;
        RECT 75.120 32.700 76.560 33.900 ;
        RECT 76.200 29.100 76.560 32.700 ;
        RECT 77.280 32.700 78.720 33.900 ;
        RECT 77.280 29.100 77.640 32.700 ;
        RECT 78.360 29.100 78.720 32.700 ;
        RECT 79.440 32.700 80.880 33.900 ;
        RECT 79.440 29.100 79.800 32.700 ;
        RECT 76.200 19.500 77.640 21.900 ;
        RECT 78.360 19.500 79.800 21.900 ;
        RECT 82.060 18.740 82.620 34.660 ;
        RECT 73.380 18.180 82.620 18.740 ;
        RECT 83.440 33.040 89.520 34.240 ;
        RECT 83.440 20.440 84.400 33.040 ;
        RECT 85.360 32.040 86.960 32.440 ;
        RECT 84.720 30.040 85.040 31.240 ;
        RECT 86.000 30.440 87.600 30.840 ;
        RECT 87.920 30.040 88.240 31.240 ;
        RECT 85.360 28.840 86.960 29.240 ;
        RECT 85.360 28.040 86.960 28.440 ;
        RECT 84.720 26.040 85.040 27.240 ;
        RECT 86.000 26.440 87.600 26.840 ;
        RECT 87.920 26.040 88.240 27.240 ;
        RECT 85.360 24.840 86.960 25.240 ;
        RECT 85.360 23.240 86.960 23.640 ;
        RECT 84.720 22.040 85.040 23.240 ;
        RECT 86.000 22.440 87.600 22.840 ;
        RECT 87.920 22.040 88.240 23.240 ;
        RECT 85.360 21.640 86.960 22.040 ;
        RECT 88.560 20.440 89.520 33.040 ;
        RECT 83.440 19.240 89.520 20.440 ;
        RECT 90.440 20.440 91.400 37.040 ;
        RECT 92.360 36.040 94.600 36.440 ;
        RECT 91.720 34.040 92.040 35.240 ;
        RECT 93.000 34.440 95.240 34.840 ;
        RECT 95.560 34.040 95.880 35.240 ;
        RECT 92.360 32.840 94.600 33.240 ;
        RECT 92.360 32.040 94.600 32.440 ;
        RECT 91.720 30.040 92.040 31.240 ;
        RECT 93.000 30.440 95.240 30.840 ;
        RECT 95.560 30.040 95.880 31.240 ;
        RECT 92.360 28.840 94.600 29.240 ;
        RECT 92.360 28.040 94.600 28.440 ;
        RECT 91.720 26.040 92.040 27.240 ;
        RECT 93.000 26.440 95.240 26.840 ;
        RECT 95.560 26.040 95.880 27.240 ;
        RECT 92.360 24.840 94.600 25.240 ;
        RECT 92.360 24.040 94.600 24.440 ;
        RECT 91.720 22.040 92.040 23.240 ;
        RECT 93.000 22.440 95.240 22.840 ;
        RECT 95.560 22.040 95.880 23.240 ;
        RECT 92.360 20.840 94.600 21.240 ;
        RECT 96.200 20.440 97.800 37.040 ;
        RECT 98.760 36.040 101.000 36.440 ;
        RECT 98.120 34.040 98.440 35.240 ;
        RECT 99.400 34.440 101.640 34.840 ;
        RECT 101.960 34.040 102.280 35.240 ;
        RECT 98.760 32.840 101.000 33.240 ;
        RECT 98.760 32.040 101.000 32.440 ;
        RECT 98.120 30.040 98.440 31.240 ;
        RECT 99.400 30.440 101.640 30.840 ;
        RECT 101.960 30.040 102.280 31.240 ;
        RECT 98.760 28.840 101.000 29.240 ;
        RECT 98.760 28.040 101.000 28.440 ;
        RECT 98.120 26.040 98.440 27.240 ;
        RECT 99.400 26.440 101.640 26.840 ;
        RECT 101.960 26.040 102.280 27.240 ;
        RECT 98.760 24.840 101.000 25.240 ;
        RECT 98.760 24.040 101.000 24.440 ;
        RECT 98.120 22.040 98.440 23.240 ;
        RECT 99.400 22.440 101.640 22.840 ;
        RECT 101.960 22.040 102.280 23.240 ;
        RECT 98.760 20.840 101.000 21.240 ;
        RECT 102.600 20.440 103.560 37.040 ;
        RECT 119.145 37.165 120.355 37.915 ;
        RECT 120.525 37.345 120.960 37.745 ;
        RECT 121.130 37.515 121.515 37.915 ;
        RECT 120.525 37.175 121.515 37.345 ;
        RECT 121.685 37.175 122.110 37.745 ;
        RECT 122.300 37.345 122.555 37.745 ;
        RECT 122.725 37.515 123.110 37.915 ;
        RECT 122.300 37.175 123.110 37.345 ;
        RECT 123.280 37.175 123.525 37.745 ;
        RECT 123.715 37.345 123.970 37.745 ;
        RECT 124.140 37.515 124.525 37.915 ;
        RECT 123.715 37.175 124.525 37.345 ;
        RECT 124.695 37.175 124.955 37.745 ;
        RECT 119.145 36.625 119.665 37.165 ;
        RECT 121.180 37.005 121.515 37.175 ;
        RECT 121.760 37.005 122.110 37.175 ;
        RECT 122.760 37.005 123.110 37.175 ;
        RECT 123.355 37.005 123.525 37.175 ;
        RECT 124.175 37.005 124.525 37.175 ;
        RECT 119.835 36.455 120.355 36.995 ;
        RECT 119.145 35.365 120.355 36.455 ;
        RECT 120.525 36.300 121.010 37.005 ;
        RECT 121.180 36.675 121.590 37.005 ;
        RECT 121.180 36.130 121.515 36.675 ;
        RECT 121.760 36.505 122.590 37.005 ;
        RECT 120.525 35.960 121.515 36.130 ;
        RECT 121.685 36.325 122.590 36.505 ;
        RECT 122.760 36.675 123.185 37.005 ;
        RECT 120.525 35.535 120.960 35.960 ;
        RECT 121.130 35.365 121.515 35.790 ;
        RECT 121.685 35.535 122.110 36.325 ;
        RECT 122.760 36.155 123.110 36.675 ;
        RECT 123.355 36.505 124.005 37.005 ;
        RECT 122.280 35.960 123.110 36.155 ;
        RECT 123.280 36.325 124.005 36.505 ;
        RECT 124.175 36.675 124.600 37.005 ;
        RECT 122.280 35.535 122.555 35.960 ;
        RECT 122.725 35.365 123.110 35.790 ;
        RECT 123.280 35.535 123.525 36.325 ;
        RECT 124.175 36.155 124.525 36.675 ;
        RECT 124.770 36.505 124.955 37.175 ;
        RECT 125.125 37.145 127.715 37.915 ;
        RECT 127.885 37.415 128.185 37.745 ;
        RECT 128.355 37.435 128.630 37.915 ;
        RECT 125.125 36.625 126.335 37.145 ;
        RECT 123.715 35.960 124.525 36.155 ;
        RECT 123.715 35.535 123.970 35.960 ;
        RECT 124.140 35.365 124.525 35.790 ;
        RECT 124.695 35.535 124.955 36.505 ;
        RECT 126.505 36.455 127.715 36.975 ;
        RECT 125.125 35.365 127.715 36.455 ;
        RECT 127.885 36.505 128.055 37.415 ;
        RECT 128.810 37.265 129.105 37.655 ;
        RECT 129.275 37.435 129.530 37.915 ;
        RECT 129.705 37.265 129.965 37.655 ;
        RECT 130.135 37.435 130.415 37.915 ;
        RECT 128.225 36.675 128.575 37.245 ;
        RECT 128.810 37.095 130.460 37.265 ;
        RECT 128.745 36.755 129.885 36.925 ;
        RECT 128.745 36.505 128.915 36.755 ;
        RECT 130.055 36.585 130.460 37.095 ;
        RECT 130.645 37.145 133.235 37.915 ;
        RECT 133.430 37.525 133.760 37.915 ;
        RECT 133.930 37.355 134.155 37.735 ;
        RECT 130.645 36.625 131.855 37.145 ;
        RECT 127.885 36.335 128.915 36.505 ;
        RECT 129.705 36.415 130.460 36.585 ;
        RECT 132.025 36.455 133.235 36.975 ;
        RECT 133.415 36.675 133.655 37.325 ;
        RECT 133.825 37.175 134.155 37.355 ;
        RECT 133.825 36.505 134.000 37.175 ;
        RECT 134.355 37.005 134.585 37.625 ;
        RECT 134.765 37.185 135.065 37.915 ;
        RECT 135.250 37.365 135.505 37.655 ;
        RECT 135.675 37.535 136.005 37.915 ;
        RECT 135.250 37.195 136.000 37.365 ;
        RECT 134.170 36.675 134.585 37.005 ;
        RECT 134.765 36.675 135.060 37.005 ;
        RECT 127.885 35.535 128.195 36.335 ;
        RECT 129.705 36.165 129.965 36.415 ;
        RECT 128.365 35.365 128.675 36.165 ;
        RECT 128.845 35.995 129.965 36.165 ;
        RECT 128.845 35.535 129.105 35.995 ;
        RECT 129.275 35.365 129.530 35.825 ;
        RECT 129.705 35.535 129.965 35.995 ;
        RECT 130.135 35.365 130.420 36.235 ;
        RECT 130.645 35.365 133.235 36.455 ;
        RECT 133.415 36.315 134.000 36.505 ;
        RECT 133.415 35.545 133.690 36.315 ;
        RECT 134.170 36.145 135.065 36.475 ;
        RECT 135.250 36.375 135.600 37.025 ;
        RECT 135.770 36.205 136.000 37.195 ;
        RECT 133.860 35.975 135.065 36.145 ;
        RECT 133.860 35.545 134.190 35.975 ;
        RECT 134.360 35.365 134.555 35.805 ;
        RECT 134.735 35.545 135.065 35.975 ;
        RECT 135.250 36.035 136.000 36.205 ;
        RECT 135.250 35.535 135.505 36.035 ;
        RECT 135.675 35.365 136.005 35.865 ;
        RECT 136.175 35.535 136.345 37.655 ;
        RECT 136.705 37.555 137.035 37.915 ;
        RECT 137.205 37.525 137.700 37.695 ;
        RECT 137.905 37.525 138.760 37.695 ;
        RECT 136.575 36.335 137.035 37.385 ;
        RECT 136.515 35.550 136.840 36.335 ;
        RECT 137.205 36.165 137.375 37.525 ;
        RECT 137.545 36.615 137.895 37.235 ;
        RECT 138.065 37.015 138.420 37.235 ;
        RECT 138.065 36.425 138.235 37.015 ;
        RECT 138.590 36.815 138.760 37.525 ;
        RECT 139.635 37.455 139.965 37.915 ;
        RECT 140.175 37.555 140.525 37.725 ;
        RECT 138.965 36.985 139.755 37.235 ;
        RECT 140.175 37.165 140.435 37.555 ;
        RECT 140.745 37.465 141.695 37.745 ;
        RECT 141.865 37.475 142.055 37.915 ;
        RECT 142.225 37.535 143.295 37.705 ;
        RECT 139.925 36.815 140.095 36.995 ;
        RECT 137.205 35.995 137.600 36.165 ;
        RECT 137.770 36.035 138.235 36.425 ;
        RECT 138.405 36.645 140.095 36.815 ;
        RECT 137.430 35.865 137.600 35.995 ;
        RECT 138.405 35.865 138.575 36.645 ;
        RECT 140.265 36.475 140.435 37.165 ;
        RECT 138.935 36.305 140.435 36.475 ;
        RECT 140.625 36.505 140.835 37.295 ;
        RECT 141.005 36.675 141.355 37.295 ;
        RECT 141.525 36.685 141.695 37.465 ;
        RECT 142.225 37.305 142.395 37.535 ;
        RECT 141.865 37.135 142.395 37.305 ;
        RECT 141.865 36.855 142.085 37.135 ;
        RECT 142.565 36.965 142.805 37.365 ;
        RECT 141.525 36.515 141.930 36.685 ;
        RECT 142.265 36.595 142.805 36.965 ;
        RECT 142.975 37.180 143.295 37.535 ;
        RECT 143.540 37.455 143.845 37.915 ;
        RECT 144.015 37.205 144.270 37.735 ;
        RECT 142.975 37.005 143.300 37.180 ;
        RECT 142.975 36.705 143.890 37.005 ;
        RECT 143.150 36.675 143.890 36.705 ;
        RECT 140.625 36.345 141.300 36.505 ;
        RECT 141.760 36.425 141.930 36.515 ;
        RECT 140.625 36.335 141.590 36.345 ;
        RECT 140.265 36.165 140.435 36.305 ;
        RECT 137.010 35.365 137.260 35.825 ;
        RECT 137.430 35.535 137.680 35.865 ;
        RECT 137.895 35.535 138.575 35.865 ;
        RECT 138.745 35.965 139.820 36.135 ;
        RECT 140.265 35.995 140.825 36.165 ;
        RECT 141.130 36.045 141.590 36.335 ;
        RECT 141.760 36.255 142.980 36.425 ;
        RECT 138.745 35.625 138.915 35.965 ;
        RECT 139.150 35.365 139.480 35.795 ;
        RECT 139.650 35.625 139.820 35.965 ;
        RECT 140.115 35.365 140.485 35.825 ;
        RECT 140.655 35.535 140.825 35.995 ;
        RECT 141.760 35.875 141.930 36.255 ;
        RECT 143.150 36.085 143.320 36.675 ;
        RECT 144.060 36.555 144.270 37.205 ;
        RECT 144.905 37.190 145.195 37.915 ;
        RECT 145.365 37.145 147.035 37.915 ;
        RECT 147.665 37.165 148.875 37.915 ;
        RECT 145.365 36.625 146.115 37.145 ;
        RECT 141.060 35.535 141.930 35.875 ;
        RECT 142.520 35.915 143.320 36.085 ;
        RECT 142.100 35.365 142.350 35.825 ;
        RECT 142.520 35.625 142.690 35.915 ;
        RECT 142.870 35.365 143.200 35.745 ;
        RECT 143.540 35.365 143.845 36.505 ;
        RECT 144.015 35.675 144.270 36.555 ;
        RECT 144.905 35.365 145.195 36.530 ;
        RECT 146.285 36.455 147.035 36.975 ;
        RECT 145.365 35.365 147.035 36.455 ;
        RECT 147.665 36.455 148.185 36.995 ;
        RECT 148.355 36.625 148.875 37.165 ;
        RECT 147.665 35.365 148.875 36.455 ;
        RECT 119.060 35.195 148.960 35.365 ;
        RECT 119.145 34.105 120.355 35.195 ;
        RECT 119.145 33.395 119.665 33.935 ;
        RECT 119.835 33.565 120.355 34.105 ;
        RECT 120.530 34.005 120.785 34.885 ;
        RECT 120.955 34.055 121.260 35.195 ;
        RECT 121.600 34.815 121.930 35.195 ;
        RECT 122.110 34.645 122.280 34.935 ;
        RECT 122.450 34.735 122.700 35.195 ;
        RECT 121.480 34.475 122.280 34.645 ;
        RECT 122.870 34.685 123.740 35.025 ;
        RECT 119.145 32.645 120.355 33.395 ;
        RECT 120.530 33.355 120.740 34.005 ;
        RECT 121.480 33.885 121.650 34.475 ;
        RECT 122.870 34.305 123.040 34.685 ;
        RECT 123.975 34.565 124.145 35.025 ;
        RECT 124.315 34.735 124.685 35.195 ;
        RECT 124.980 34.595 125.150 34.935 ;
        RECT 125.320 34.765 125.650 35.195 ;
        RECT 125.885 34.595 126.055 34.935 ;
        RECT 121.820 34.135 123.040 34.305 ;
        RECT 123.210 34.225 123.670 34.515 ;
        RECT 123.975 34.395 124.535 34.565 ;
        RECT 124.980 34.425 126.055 34.595 ;
        RECT 126.225 34.695 126.905 35.025 ;
        RECT 127.120 34.695 127.370 35.025 ;
        RECT 127.540 34.735 127.790 35.195 ;
        RECT 124.365 34.255 124.535 34.395 ;
        RECT 123.210 34.215 124.175 34.225 ;
        RECT 122.870 34.045 123.040 34.135 ;
        RECT 123.500 34.055 124.175 34.215 ;
        RECT 120.910 33.855 121.650 33.885 ;
        RECT 120.910 33.555 121.825 33.855 ;
        RECT 121.500 33.380 121.825 33.555 ;
        RECT 120.530 32.825 120.785 33.355 ;
        RECT 120.955 32.645 121.260 33.105 ;
        RECT 121.505 33.025 121.825 33.380 ;
        RECT 121.995 33.595 122.535 33.965 ;
        RECT 122.870 33.875 123.275 34.045 ;
        RECT 121.995 33.195 122.235 33.595 ;
        RECT 122.715 33.425 122.935 33.705 ;
        RECT 122.405 33.255 122.935 33.425 ;
        RECT 122.405 33.025 122.575 33.255 ;
        RECT 123.105 33.095 123.275 33.875 ;
        RECT 123.445 33.265 123.795 33.885 ;
        RECT 123.965 33.265 124.175 34.055 ;
        RECT 124.365 34.085 125.865 34.255 ;
        RECT 124.365 33.395 124.535 34.085 ;
        RECT 126.225 33.915 126.395 34.695 ;
        RECT 127.200 34.565 127.370 34.695 ;
        RECT 124.705 33.745 126.395 33.915 ;
        RECT 126.565 34.135 127.030 34.525 ;
        RECT 127.200 34.395 127.595 34.565 ;
        RECT 124.705 33.565 124.875 33.745 ;
        RECT 121.505 32.855 122.575 33.025 ;
        RECT 122.745 32.645 122.935 33.085 ;
        RECT 123.105 32.815 124.055 33.095 ;
        RECT 124.365 33.005 124.625 33.395 ;
        RECT 125.045 33.325 125.835 33.575 ;
        RECT 124.275 32.835 124.625 33.005 ;
        RECT 124.835 32.645 125.165 33.105 ;
        RECT 126.040 33.035 126.210 33.745 ;
        RECT 126.565 33.545 126.735 34.135 ;
        RECT 126.380 33.325 126.735 33.545 ;
        RECT 126.905 33.325 127.255 33.945 ;
        RECT 127.425 33.035 127.595 34.395 ;
        RECT 127.960 34.225 128.285 35.010 ;
        RECT 127.765 33.175 128.225 34.225 ;
        RECT 126.040 32.865 126.895 33.035 ;
        RECT 127.100 32.865 127.595 33.035 ;
        RECT 127.765 32.645 128.095 33.005 ;
        RECT 128.455 32.905 128.625 35.025 ;
        RECT 128.795 34.695 129.125 35.195 ;
        RECT 129.295 34.525 129.550 35.025 ;
        RECT 128.800 34.355 129.550 34.525 ;
        RECT 128.800 33.365 129.030 34.355 ;
        RECT 129.200 33.535 129.550 34.185 ;
        RECT 129.725 34.105 131.395 35.195 ;
        RECT 129.725 33.415 130.475 33.935 ;
        RECT 130.645 33.585 131.395 34.105 ;
        RECT 132.025 34.030 132.315 35.195 ;
        RECT 132.575 34.265 132.745 35.025 ;
        RECT 132.960 34.435 133.290 35.195 ;
        RECT 132.575 34.095 133.290 34.265 ;
        RECT 133.460 34.120 133.715 35.025 ;
        RECT 132.485 33.545 132.840 33.915 ;
        RECT 133.120 33.885 133.290 34.095 ;
        RECT 133.120 33.555 133.375 33.885 ;
        RECT 128.800 33.195 129.550 33.365 ;
        RECT 128.795 32.645 129.125 33.025 ;
        RECT 129.295 32.905 129.550 33.195 ;
        RECT 129.725 32.645 131.395 33.415 ;
        RECT 132.025 32.645 132.315 33.370 ;
        RECT 133.120 33.365 133.290 33.555 ;
        RECT 133.545 33.390 133.715 34.120 ;
        RECT 133.890 34.045 134.150 35.195 ;
        RECT 134.325 34.105 135.995 35.195 ;
        RECT 132.575 33.195 133.290 33.365 ;
        RECT 132.575 32.815 132.745 33.195 ;
        RECT 132.960 32.645 133.290 33.025 ;
        RECT 133.460 32.815 133.715 33.390 ;
        RECT 133.890 32.645 134.150 33.485 ;
        RECT 134.325 33.415 135.075 33.935 ;
        RECT 135.245 33.585 135.995 34.105 ;
        RECT 136.165 33.590 136.445 35.025 ;
        RECT 136.615 34.420 137.325 35.195 ;
        RECT 137.495 34.250 137.825 35.025 ;
        RECT 136.675 34.035 137.825 34.250 ;
        RECT 134.325 32.645 135.995 33.415 ;
        RECT 136.165 32.815 136.505 33.590 ;
        RECT 136.675 33.465 136.960 34.035 ;
        RECT 137.145 33.635 137.615 33.865 ;
        RECT 138.020 33.835 138.235 34.950 ;
        RECT 138.415 34.475 138.745 35.195 ;
        RECT 138.925 34.760 144.270 35.195 ;
        RECT 138.525 33.835 138.755 34.175 ;
        RECT 137.785 33.655 138.235 33.835 ;
        RECT 137.785 33.635 138.115 33.655 ;
        RECT 138.425 33.635 138.755 33.835 ;
        RECT 136.675 33.275 137.385 33.465 ;
        RECT 137.085 33.135 137.385 33.275 ;
        RECT 137.575 33.275 138.755 33.465 ;
        RECT 137.575 33.195 137.905 33.275 ;
        RECT 137.085 33.125 137.400 33.135 ;
        RECT 137.085 33.115 137.410 33.125 ;
        RECT 137.085 33.110 137.420 33.115 ;
        RECT 136.675 32.645 136.845 33.105 ;
        RECT 137.085 33.100 137.425 33.110 ;
        RECT 137.085 33.095 137.430 33.100 ;
        RECT 137.085 33.085 137.435 33.095 ;
        RECT 137.085 33.080 137.440 33.085 ;
        RECT 137.085 32.815 137.445 33.080 ;
        RECT 138.075 32.645 138.245 33.105 ;
        RECT 138.415 32.815 138.755 33.275 ;
        RECT 140.510 33.190 140.850 34.020 ;
        RECT 142.330 33.510 142.680 34.760 ;
        RECT 144.445 34.105 147.035 35.195 ;
        RECT 144.445 33.415 145.655 33.935 ;
        RECT 145.825 33.585 147.035 34.105 ;
        RECT 147.665 34.105 148.875 35.195 ;
        RECT 147.665 33.565 148.185 34.105 ;
        RECT 138.925 32.645 144.270 33.190 ;
        RECT 144.445 32.645 147.035 33.415 ;
        RECT 148.355 33.395 148.875 33.935 ;
        RECT 147.665 32.645 148.875 33.395 ;
        RECT 119.060 32.475 148.960 32.645 ;
        RECT 119.145 31.725 120.355 32.475 ;
        RECT 119.145 31.185 119.665 31.725 ;
        RECT 120.525 31.705 124.035 32.475 ;
        RECT 124.205 31.725 125.415 32.475 ;
        RECT 125.700 31.845 125.985 32.305 ;
        RECT 126.155 32.015 126.425 32.475 ;
        RECT 119.835 31.015 120.355 31.555 ;
        RECT 120.525 31.185 122.175 31.705 ;
        RECT 122.345 31.015 124.035 31.535 ;
        RECT 124.205 31.185 124.725 31.725 ;
        RECT 125.700 31.675 126.655 31.845 ;
        RECT 124.895 31.015 125.415 31.555 ;
        RECT 119.145 29.925 120.355 31.015 ;
        RECT 120.525 29.925 124.035 31.015 ;
        RECT 124.205 29.925 125.415 31.015 ;
        RECT 125.585 30.945 126.275 31.505 ;
        RECT 126.445 30.775 126.655 31.675 ;
        RECT 125.700 30.555 126.655 30.775 ;
        RECT 126.825 31.505 127.225 32.305 ;
        RECT 127.415 31.845 127.695 32.305 ;
        RECT 128.215 32.015 128.540 32.475 ;
        RECT 127.415 31.675 128.540 31.845 ;
        RECT 128.710 31.735 129.095 32.305 ;
        RECT 128.090 31.565 128.540 31.675 ;
        RECT 126.825 30.945 127.920 31.505 ;
        RECT 128.090 31.235 128.645 31.565 ;
        RECT 125.700 30.095 125.985 30.555 ;
        RECT 126.155 29.925 126.425 30.385 ;
        RECT 126.825 30.095 127.225 30.945 ;
        RECT 128.090 30.775 128.540 31.235 ;
        RECT 128.815 31.065 129.095 31.735 ;
        RECT 127.415 30.555 128.540 30.775 ;
        RECT 127.415 30.095 127.695 30.555 ;
        RECT 128.215 29.925 128.540 30.385 ;
        RECT 128.710 30.095 129.095 31.065 ;
        RECT 129.265 31.530 129.605 32.305 ;
        RECT 129.775 32.015 129.945 32.475 ;
        RECT 130.185 32.040 130.545 32.305 ;
        RECT 130.185 32.035 130.540 32.040 ;
        RECT 130.185 32.025 130.535 32.035 ;
        RECT 130.185 32.020 130.530 32.025 ;
        RECT 130.185 32.010 130.525 32.020 ;
        RECT 131.175 32.015 131.345 32.475 ;
        RECT 130.185 32.005 130.520 32.010 ;
        RECT 130.185 31.995 130.510 32.005 ;
        RECT 130.185 31.985 130.500 31.995 ;
        RECT 130.185 31.845 130.485 31.985 ;
        RECT 129.775 31.655 130.485 31.845 ;
        RECT 130.675 31.845 131.005 31.925 ;
        RECT 131.515 31.845 131.855 32.305 ;
        RECT 130.675 31.655 131.855 31.845 ;
        RECT 132.035 31.665 132.305 32.475 ;
        RECT 132.475 31.665 132.805 32.305 ;
        RECT 132.975 31.665 133.215 32.475 ;
        RECT 133.405 31.930 138.750 32.475 ;
        RECT 129.265 30.095 129.545 31.530 ;
        RECT 129.775 31.085 130.060 31.655 ;
        RECT 130.245 31.255 130.715 31.485 ;
        RECT 130.885 31.465 131.215 31.485 ;
        RECT 130.885 31.285 131.335 31.465 ;
        RECT 131.525 31.285 131.855 31.485 ;
        RECT 129.775 30.870 130.925 31.085 ;
        RECT 129.715 29.925 130.425 30.700 ;
        RECT 130.595 30.095 130.925 30.870 ;
        RECT 131.120 30.170 131.335 31.285 ;
        RECT 131.625 30.945 131.855 31.285 ;
        RECT 132.025 31.235 132.375 31.485 ;
        RECT 132.545 31.065 132.715 31.665 ;
        RECT 132.885 31.235 133.235 31.485 ;
        RECT 134.990 31.100 135.330 31.930 ;
        RECT 138.925 31.735 139.310 32.305 ;
        RECT 139.480 32.015 139.805 32.475 ;
        RECT 140.325 31.845 140.605 32.305 ;
        RECT 131.515 29.925 131.845 30.645 ;
        RECT 132.035 29.925 132.365 31.065 ;
        RECT 132.545 30.895 133.225 31.065 ;
        RECT 132.895 30.110 133.225 30.895 ;
        RECT 136.810 30.360 137.160 31.610 ;
        RECT 138.925 31.065 139.205 31.735 ;
        RECT 139.480 31.675 140.605 31.845 ;
        RECT 139.480 31.565 139.930 31.675 ;
        RECT 139.375 31.235 139.930 31.565 ;
        RECT 140.795 31.505 141.195 32.305 ;
        RECT 141.595 32.015 141.865 32.475 ;
        RECT 142.035 31.845 142.320 32.305 ;
        RECT 133.405 29.925 138.750 30.360 ;
        RECT 138.925 30.095 139.310 31.065 ;
        RECT 139.480 30.775 139.930 31.235 ;
        RECT 140.100 30.945 141.195 31.505 ;
        RECT 139.480 30.555 140.605 30.775 ;
        RECT 139.480 29.925 139.805 30.385 ;
        RECT 140.325 30.095 140.605 30.555 ;
        RECT 140.795 30.095 141.195 30.945 ;
        RECT 141.365 31.675 142.320 31.845 ;
        RECT 142.605 31.705 144.275 32.475 ;
        RECT 144.905 31.750 145.195 32.475 ;
        RECT 145.365 31.705 147.035 32.475 ;
        RECT 147.665 31.725 148.875 32.475 ;
        RECT 141.365 30.775 141.575 31.675 ;
        RECT 141.745 30.945 142.435 31.505 ;
        RECT 142.605 31.185 143.355 31.705 ;
        RECT 143.525 31.015 144.275 31.535 ;
        RECT 145.365 31.185 146.115 31.705 ;
        RECT 141.365 30.555 142.320 30.775 ;
        RECT 141.595 29.925 141.865 30.385 ;
        RECT 142.035 30.095 142.320 30.555 ;
        RECT 142.605 29.925 144.275 31.015 ;
        RECT 144.905 29.925 145.195 31.090 ;
        RECT 146.285 31.015 147.035 31.535 ;
        RECT 145.365 29.925 147.035 31.015 ;
        RECT 147.665 31.015 148.185 31.555 ;
        RECT 148.355 31.185 148.875 31.725 ;
        RECT 147.665 29.925 148.875 31.015 ;
        RECT 119.060 29.755 148.960 29.925 ;
        RECT 119.145 28.665 120.355 29.755 ;
        RECT 119.145 27.955 119.665 28.495 ;
        RECT 119.835 28.125 120.355 28.665 ;
        RECT 121.485 28.615 121.715 29.755 ;
        RECT 121.885 28.605 122.215 29.585 ;
        RECT 122.385 28.615 122.595 29.755 ;
        RECT 122.845 28.865 123.105 29.575 ;
        RECT 123.275 29.045 123.605 29.755 ;
        RECT 123.775 28.865 124.005 29.575 ;
        RECT 122.845 28.625 124.005 28.865 ;
        RECT 124.185 28.845 124.455 29.575 ;
        RECT 124.635 29.025 124.975 29.755 ;
        RECT 124.185 28.625 124.955 28.845 ;
        RECT 121.465 28.195 121.795 28.445 ;
        RECT 119.145 27.205 120.355 27.955 ;
        RECT 121.485 27.205 121.715 28.025 ;
        RECT 121.965 28.005 122.215 28.605 ;
        RECT 122.835 28.115 123.135 28.445 ;
        RECT 123.315 28.135 123.840 28.445 ;
        RECT 124.020 28.135 124.485 28.445 ;
        RECT 121.885 27.375 122.215 28.005 ;
        RECT 122.385 27.205 122.595 28.025 ;
        RECT 122.845 27.205 123.135 27.935 ;
        RECT 123.315 27.495 123.545 28.135 ;
        RECT 124.665 27.955 124.955 28.625 ;
        RECT 123.725 27.755 124.955 27.955 ;
        RECT 123.725 27.385 124.035 27.755 ;
        RECT 124.215 27.205 124.885 27.575 ;
        RECT 125.145 27.385 125.405 29.575 ;
        RECT 125.585 28.785 125.895 29.585 ;
        RECT 126.065 28.955 126.375 29.755 ;
        RECT 126.545 29.125 126.805 29.585 ;
        RECT 126.975 29.295 127.230 29.755 ;
        RECT 127.405 29.125 127.665 29.585 ;
        RECT 126.545 28.955 127.665 29.125 ;
        RECT 125.585 28.615 126.615 28.785 ;
        RECT 125.585 27.705 125.755 28.615 ;
        RECT 125.925 27.875 126.275 28.445 ;
        RECT 126.445 28.365 126.615 28.615 ;
        RECT 127.405 28.705 127.665 28.955 ;
        RECT 127.835 28.885 128.120 29.755 ;
        RECT 128.345 29.035 128.805 29.585 ;
        RECT 128.995 29.035 129.325 29.755 ;
        RECT 127.405 28.535 128.160 28.705 ;
        RECT 126.445 28.195 127.585 28.365 ;
        RECT 127.755 28.025 128.160 28.535 ;
        RECT 126.510 27.855 128.160 28.025 ;
        RECT 125.585 27.375 125.885 27.705 ;
        RECT 126.055 27.205 126.330 27.685 ;
        RECT 126.510 27.465 126.805 27.855 ;
        RECT 126.975 27.205 127.230 27.685 ;
        RECT 127.405 27.465 127.665 27.855 ;
        RECT 127.835 27.205 128.115 27.685 ;
        RECT 128.345 27.665 128.595 29.035 ;
        RECT 129.525 28.865 129.825 29.415 ;
        RECT 129.995 29.085 130.275 29.755 ;
        RECT 128.885 28.695 129.825 28.865 ;
        RECT 128.885 28.445 129.055 28.695 ;
        RECT 130.195 28.445 130.460 28.805 ;
        RECT 130.645 28.665 131.855 29.755 ;
        RECT 128.765 28.115 129.055 28.445 ;
        RECT 129.225 28.195 129.565 28.445 ;
        RECT 129.785 28.195 130.460 28.445 ;
        RECT 128.885 28.025 129.055 28.115 ;
        RECT 128.885 27.835 130.275 28.025 ;
        RECT 128.345 27.375 128.905 27.665 ;
        RECT 129.075 27.205 129.325 27.665 ;
        RECT 129.945 27.475 130.275 27.835 ;
        RECT 130.645 27.955 131.165 28.495 ;
        RECT 131.335 28.125 131.855 28.665 ;
        RECT 132.025 28.590 132.315 29.755 ;
        RECT 132.485 28.665 135.075 29.755 ;
        RECT 135.250 29.085 135.505 29.585 ;
        RECT 135.675 29.255 136.005 29.755 ;
        RECT 135.250 28.915 136.000 29.085 ;
        RECT 132.485 27.975 133.695 28.495 ;
        RECT 133.865 28.145 135.075 28.665 ;
        RECT 135.250 28.095 135.600 28.745 ;
        RECT 130.645 27.205 131.855 27.955 ;
        RECT 132.025 27.205 132.315 27.930 ;
        RECT 132.485 27.205 135.075 27.975 ;
        RECT 135.770 27.925 136.000 28.915 ;
        RECT 135.250 27.755 136.000 27.925 ;
        RECT 135.250 27.465 135.505 27.755 ;
        RECT 135.675 27.205 136.005 27.585 ;
        RECT 136.175 27.465 136.345 29.585 ;
        RECT 136.515 28.785 136.840 29.570 ;
        RECT 137.010 29.295 137.260 29.755 ;
        RECT 137.430 29.255 137.680 29.585 ;
        RECT 137.895 29.255 138.575 29.585 ;
        RECT 137.430 29.125 137.600 29.255 ;
        RECT 137.205 28.955 137.600 29.125 ;
        RECT 136.575 27.735 137.035 28.785 ;
        RECT 137.205 27.595 137.375 28.955 ;
        RECT 137.770 28.695 138.235 29.085 ;
        RECT 137.545 27.885 137.895 28.505 ;
        RECT 138.065 28.105 138.235 28.695 ;
        RECT 138.405 28.475 138.575 29.255 ;
        RECT 138.745 29.155 138.915 29.495 ;
        RECT 139.150 29.325 139.480 29.755 ;
        RECT 139.650 29.155 139.820 29.495 ;
        RECT 140.115 29.295 140.485 29.755 ;
        RECT 138.745 28.985 139.820 29.155 ;
        RECT 140.655 29.125 140.825 29.585 ;
        RECT 141.060 29.245 141.930 29.585 ;
        RECT 142.100 29.295 142.350 29.755 ;
        RECT 140.265 28.955 140.825 29.125 ;
        RECT 140.265 28.815 140.435 28.955 ;
        RECT 138.935 28.645 140.435 28.815 ;
        RECT 141.130 28.785 141.590 29.075 ;
        RECT 138.405 28.305 140.095 28.475 ;
        RECT 138.065 27.885 138.420 28.105 ;
        RECT 138.590 27.595 138.760 28.305 ;
        RECT 138.965 27.885 139.755 28.135 ;
        RECT 139.925 28.125 140.095 28.305 ;
        RECT 140.265 27.955 140.435 28.645 ;
        RECT 136.705 27.205 137.035 27.565 ;
        RECT 137.205 27.425 137.700 27.595 ;
        RECT 137.905 27.425 138.760 27.595 ;
        RECT 139.635 27.205 139.965 27.665 ;
        RECT 140.175 27.565 140.435 27.955 ;
        RECT 140.625 28.775 141.590 28.785 ;
        RECT 141.760 28.865 141.930 29.245 ;
        RECT 142.520 29.205 142.690 29.495 ;
        RECT 142.870 29.375 143.200 29.755 ;
        RECT 142.520 29.035 143.320 29.205 ;
        RECT 140.625 28.615 141.300 28.775 ;
        RECT 141.760 28.695 142.980 28.865 ;
        RECT 140.625 27.825 140.835 28.615 ;
        RECT 141.760 28.605 141.930 28.695 ;
        RECT 141.005 27.825 141.355 28.445 ;
        RECT 141.525 28.435 141.930 28.605 ;
        RECT 141.525 27.655 141.695 28.435 ;
        RECT 141.865 27.985 142.085 28.265 ;
        RECT 142.265 28.155 142.805 28.525 ;
        RECT 143.150 28.415 143.320 29.035 ;
        RECT 143.495 28.695 143.665 29.755 ;
        RECT 143.875 28.745 144.165 29.585 ;
        RECT 144.335 28.915 144.505 29.755 ;
        RECT 144.715 28.745 144.965 29.585 ;
        RECT 145.175 28.915 145.345 29.755 ;
        RECT 143.875 28.575 145.600 28.745 ;
        RECT 145.825 28.665 147.495 29.755 ;
        RECT 141.865 27.815 142.395 27.985 ;
        RECT 140.175 27.395 140.525 27.565 ;
        RECT 140.745 27.375 141.695 27.655 ;
        RECT 141.865 27.205 142.055 27.645 ;
        RECT 142.225 27.585 142.395 27.815 ;
        RECT 142.565 27.755 142.805 28.155 ;
        RECT 142.975 28.405 143.320 28.415 ;
        RECT 142.975 28.195 145.005 28.405 ;
        RECT 142.975 27.940 143.300 28.195 ;
        RECT 145.190 28.025 145.600 28.575 ;
        RECT 142.975 27.585 143.295 27.940 ;
        RECT 142.225 27.415 143.295 27.585 ;
        RECT 143.495 27.205 143.665 28.015 ;
        RECT 143.835 27.855 145.600 28.025 ;
        RECT 145.825 27.975 146.575 28.495 ;
        RECT 146.745 28.145 147.495 28.665 ;
        RECT 147.665 28.665 148.875 29.755 ;
        RECT 147.665 28.125 148.185 28.665 ;
        RECT 143.835 27.375 144.165 27.855 ;
        RECT 144.335 27.205 144.505 27.675 ;
        RECT 144.675 27.375 145.005 27.855 ;
        RECT 145.175 27.205 145.345 27.675 ;
        RECT 145.825 27.205 147.495 27.975 ;
        RECT 148.355 27.955 148.875 28.495 ;
        RECT 147.665 27.205 148.875 27.955 ;
        RECT 119.060 27.035 148.960 27.205 ;
        RECT 119.145 26.285 120.355 27.035 ;
        RECT 119.145 25.745 119.665 26.285 ;
        RECT 120.525 26.265 122.195 27.035 ;
        RECT 122.915 26.485 123.085 26.775 ;
        RECT 123.255 26.655 123.585 27.035 ;
        RECT 122.915 26.315 123.580 26.485 ;
        RECT 119.835 25.575 120.355 26.115 ;
        RECT 120.525 25.745 121.275 26.265 ;
        RECT 121.445 25.575 122.195 26.095 ;
        RECT 119.145 24.485 120.355 25.575 ;
        RECT 120.525 24.485 122.195 25.575 ;
        RECT 122.830 25.495 123.180 26.145 ;
        RECT 123.350 25.325 123.580 26.315 ;
        RECT 122.915 25.155 123.580 25.325 ;
        RECT 122.915 24.655 123.085 25.155 ;
        RECT 123.255 24.485 123.585 24.985 ;
        RECT 123.755 24.655 123.980 26.775 ;
        RECT 124.195 26.655 124.525 27.035 ;
        RECT 124.695 26.485 124.865 26.815 ;
        RECT 125.165 26.655 126.180 26.855 ;
        RECT 124.170 26.295 124.865 26.485 ;
        RECT 124.170 25.325 124.340 26.295 ;
        RECT 124.510 25.495 124.920 26.115 ;
        RECT 125.090 25.545 125.310 26.415 ;
        RECT 125.490 26.105 125.840 26.475 ;
        RECT 126.010 25.925 126.180 26.655 ;
        RECT 126.350 26.595 126.760 27.035 ;
        RECT 127.050 26.395 127.300 26.825 ;
        RECT 127.500 26.575 127.820 27.035 ;
        RECT 128.380 26.645 129.230 26.815 ;
        RECT 126.350 26.055 126.760 26.385 ;
        RECT 127.050 26.055 127.470 26.395 ;
        RECT 125.760 25.885 126.180 25.925 ;
        RECT 125.760 25.715 127.110 25.885 ;
        RECT 124.170 25.155 124.865 25.325 ;
        RECT 125.090 25.165 125.590 25.545 ;
        RECT 124.195 24.485 124.525 24.985 ;
        RECT 124.695 24.655 124.865 25.155 ;
        RECT 125.760 24.870 125.930 25.715 ;
        RECT 126.860 25.555 127.110 25.715 ;
        RECT 126.100 25.285 126.350 25.545 ;
        RECT 127.280 25.285 127.470 26.055 ;
        RECT 126.100 25.035 127.470 25.285 ;
        RECT 127.640 26.225 128.890 26.395 ;
        RECT 127.640 25.465 127.810 26.225 ;
        RECT 128.560 26.105 128.890 26.225 ;
        RECT 127.980 25.645 128.160 26.055 ;
        RECT 129.060 25.885 129.230 26.645 ;
        RECT 129.430 26.555 130.090 27.035 ;
        RECT 130.270 26.440 130.590 26.770 ;
        RECT 129.420 26.115 130.080 26.385 ;
        RECT 129.420 26.055 129.750 26.115 ;
        RECT 129.900 25.885 130.230 25.945 ;
        RECT 128.330 25.715 130.230 25.885 ;
        RECT 127.640 25.155 128.160 25.465 ;
        RECT 128.330 25.205 128.500 25.715 ;
        RECT 130.400 25.545 130.590 26.440 ;
        RECT 128.670 25.375 130.590 25.545 ;
        RECT 130.270 25.355 130.590 25.375 ;
        RECT 130.790 26.125 131.040 26.775 ;
        RECT 131.220 26.575 131.505 27.035 ;
        RECT 131.685 26.695 131.940 26.855 ;
        RECT 131.685 26.525 132.025 26.695 ;
        RECT 131.685 26.325 131.940 26.525 ;
        RECT 130.790 25.795 131.590 26.125 ;
        RECT 128.330 25.035 129.540 25.205 ;
        RECT 125.100 24.700 125.930 24.870 ;
        RECT 126.170 24.485 126.550 24.865 ;
        RECT 126.730 24.745 126.900 25.035 ;
        RECT 128.330 24.955 128.500 25.035 ;
        RECT 127.070 24.485 127.400 24.865 ;
        RECT 127.870 24.705 128.500 24.955 ;
        RECT 128.680 24.485 129.100 24.865 ;
        RECT 129.300 24.745 129.540 25.035 ;
        RECT 129.770 24.485 130.100 25.175 ;
        RECT 130.270 24.745 130.440 25.355 ;
        RECT 130.790 25.205 131.040 25.795 ;
        RECT 131.760 25.465 131.940 26.325 ;
        RECT 132.490 26.485 132.745 26.775 ;
        RECT 132.915 26.655 133.245 27.035 ;
        RECT 132.490 26.315 133.240 26.485 ;
        RECT 132.490 25.495 132.840 26.145 ;
        RECT 130.710 24.695 131.040 25.205 ;
        RECT 131.220 24.485 131.505 25.285 ;
        RECT 131.685 24.795 131.940 25.465 ;
        RECT 133.010 25.325 133.240 26.315 ;
        RECT 132.490 25.155 133.240 25.325 ;
        RECT 132.490 24.655 132.745 25.155 ;
        RECT 132.915 24.485 133.245 24.985 ;
        RECT 133.415 24.655 133.585 26.775 ;
        RECT 133.945 26.675 134.275 27.035 ;
        RECT 134.445 26.645 134.940 26.815 ;
        RECT 135.145 26.645 136.000 26.815 ;
        RECT 133.815 25.455 134.275 26.505 ;
        RECT 133.755 24.670 134.080 25.455 ;
        RECT 134.445 25.285 134.615 26.645 ;
        RECT 134.785 25.735 135.135 26.355 ;
        RECT 135.305 26.135 135.660 26.355 ;
        RECT 135.305 25.545 135.475 26.135 ;
        RECT 135.830 25.935 136.000 26.645 ;
        RECT 136.875 26.575 137.205 27.035 ;
        RECT 137.415 26.675 137.765 26.845 ;
        RECT 136.205 26.105 136.995 26.355 ;
        RECT 137.415 26.285 137.675 26.675 ;
        RECT 137.985 26.585 138.935 26.865 ;
        RECT 139.105 26.595 139.295 27.035 ;
        RECT 139.465 26.655 140.535 26.825 ;
        RECT 137.165 25.935 137.335 26.115 ;
        RECT 134.445 25.115 134.840 25.285 ;
        RECT 135.010 25.155 135.475 25.545 ;
        RECT 135.645 25.765 137.335 25.935 ;
        RECT 134.670 24.985 134.840 25.115 ;
        RECT 135.645 24.985 135.815 25.765 ;
        RECT 137.505 25.595 137.675 26.285 ;
        RECT 136.175 25.425 137.675 25.595 ;
        RECT 137.865 25.625 138.075 26.415 ;
        RECT 138.245 25.795 138.595 26.415 ;
        RECT 138.765 25.805 138.935 26.585 ;
        RECT 139.465 26.425 139.635 26.655 ;
        RECT 139.105 26.255 139.635 26.425 ;
        RECT 139.105 25.975 139.325 26.255 ;
        RECT 139.805 26.085 140.045 26.485 ;
        RECT 138.765 25.635 139.170 25.805 ;
        RECT 139.505 25.715 140.045 26.085 ;
        RECT 140.215 26.300 140.535 26.655 ;
        RECT 140.780 26.575 141.085 27.035 ;
        RECT 141.255 26.325 141.510 26.855 ;
        RECT 140.215 26.125 140.540 26.300 ;
        RECT 140.215 25.825 141.130 26.125 ;
        RECT 140.390 25.795 141.130 25.825 ;
        RECT 137.865 25.465 138.540 25.625 ;
        RECT 139.000 25.545 139.170 25.635 ;
        RECT 137.865 25.455 138.830 25.465 ;
        RECT 137.505 25.285 137.675 25.425 ;
        RECT 134.250 24.485 134.500 24.945 ;
        RECT 134.670 24.655 134.920 24.985 ;
        RECT 135.135 24.655 135.815 24.985 ;
        RECT 135.985 25.085 137.060 25.255 ;
        RECT 137.505 25.115 138.065 25.285 ;
        RECT 138.370 25.165 138.830 25.455 ;
        RECT 139.000 25.375 140.220 25.545 ;
        RECT 135.985 24.745 136.155 25.085 ;
        RECT 136.390 24.485 136.720 24.915 ;
        RECT 136.890 24.745 137.060 25.085 ;
        RECT 137.355 24.485 137.725 24.945 ;
        RECT 137.895 24.655 138.065 25.115 ;
        RECT 139.000 24.995 139.170 25.375 ;
        RECT 140.390 25.205 140.560 25.795 ;
        RECT 141.300 25.675 141.510 26.325 ;
        RECT 141.685 26.265 144.275 27.035 ;
        RECT 144.905 26.310 145.195 27.035 ;
        RECT 145.365 26.265 147.035 27.035 ;
        RECT 147.665 26.285 148.875 27.035 ;
        RECT 141.685 25.745 142.895 26.265 ;
        RECT 138.300 24.655 139.170 24.995 ;
        RECT 139.760 25.035 140.560 25.205 ;
        RECT 139.340 24.485 139.590 24.945 ;
        RECT 139.760 24.745 139.930 25.035 ;
        RECT 140.110 24.485 140.440 24.865 ;
        RECT 140.780 24.485 141.085 25.625 ;
        RECT 141.255 24.795 141.510 25.675 ;
        RECT 143.065 25.575 144.275 26.095 ;
        RECT 145.365 25.745 146.115 26.265 ;
        RECT 141.685 24.485 144.275 25.575 ;
        RECT 144.905 24.485 145.195 25.650 ;
        RECT 146.285 25.575 147.035 26.095 ;
        RECT 145.365 24.485 147.035 25.575 ;
        RECT 147.665 25.575 148.185 26.115 ;
        RECT 148.355 25.745 148.875 26.285 ;
        RECT 147.665 24.485 148.875 25.575 ;
        RECT 119.060 24.315 148.960 24.485 ;
        RECT 119.145 23.225 120.355 24.315 ;
        RECT 120.525 23.225 121.735 24.315 ;
        RECT 121.910 23.645 122.165 24.145 ;
        RECT 122.335 23.815 122.665 24.315 ;
        RECT 121.910 23.475 122.660 23.645 ;
        RECT 119.145 22.515 119.665 23.055 ;
        RECT 119.835 22.685 120.355 23.225 ;
        RECT 120.525 22.515 121.045 23.055 ;
        RECT 121.215 22.685 121.735 23.225 ;
        RECT 121.910 22.655 122.260 23.305 ;
        RECT 119.145 21.765 120.355 22.515 ;
        RECT 120.525 21.765 121.735 22.515 ;
        RECT 122.430 22.485 122.660 23.475 ;
        RECT 121.910 22.315 122.660 22.485 ;
        RECT 121.910 22.025 122.165 22.315 ;
        RECT 122.335 21.765 122.665 22.145 ;
        RECT 122.835 22.025 123.005 24.145 ;
        RECT 123.175 23.345 123.500 24.130 ;
        RECT 123.670 23.855 123.920 24.315 ;
        RECT 124.090 23.815 124.340 24.145 ;
        RECT 124.555 23.815 125.235 24.145 ;
        RECT 124.090 23.685 124.260 23.815 ;
        RECT 123.865 23.515 124.260 23.685 ;
        RECT 123.235 22.295 123.695 23.345 ;
        RECT 123.865 22.155 124.035 23.515 ;
        RECT 124.430 23.255 124.895 23.645 ;
        RECT 124.205 22.445 124.555 23.065 ;
        RECT 124.725 22.665 124.895 23.255 ;
        RECT 125.065 23.035 125.235 23.815 ;
        RECT 125.405 23.715 125.575 24.055 ;
        RECT 125.810 23.885 126.140 24.315 ;
        RECT 126.310 23.715 126.480 24.055 ;
        RECT 126.775 23.855 127.145 24.315 ;
        RECT 125.405 23.545 126.480 23.715 ;
        RECT 127.315 23.685 127.485 24.145 ;
        RECT 127.720 23.805 128.590 24.145 ;
        RECT 128.760 23.855 129.010 24.315 ;
        RECT 126.925 23.515 127.485 23.685 ;
        RECT 126.925 23.375 127.095 23.515 ;
        RECT 125.595 23.205 127.095 23.375 ;
        RECT 127.790 23.345 128.250 23.635 ;
        RECT 125.065 22.865 126.755 23.035 ;
        RECT 124.725 22.445 125.080 22.665 ;
        RECT 125.250 22.155 125.420 22.865 ;
        RECT 125.625 22.445 126.415 22.695 ;
        RECT 126.585 22.685 126.755 22.865 ;
        RECT 126.925 22.515 127.095 23.205 ;
        RECT 123.365 21.765 123.695 22.125 ;
        RECT 123.865 21.985 124.360 22.155 ;
        RECT 124.565 21.985 125.420 22.155 ;
        RECT 126.295 21.765 126.625 22.225 ;
        RECT 126.835 22.125 127.095 22.515 ;
        RECT 127.285 23.335 128.250 23.345 ;
        RECT 128.420 23.425 128.590 23.805 ;
        RECT 129.180 23.765 129.350 24.055 ;
        RECT 129.530 23.935 129.860 24.315 ;
        RECT 129.180 23.595 129.980 23.765 ;
        RECT 127.285 23.175 127.960 23.335 ;
        RECT 128.420 23.255 129.640 23.425 ;
        RECT 127.285 22.385 127.495 23.175 ;
        RECT 128.420 23.165 128.590 23.255 ;
        RECT 127.665 22.385 128.015 23.005 ;
        RECT 128.185 22.995 128.590 23.165 ;
        RECT 128.185 22.215 128.355 22.995 ;
        RECT 128.525 22.545 128.745 22.825 ;
        RECT 128.925 22.715 129.465 23.085 ;
        RECT 129.810 23.005 129.980 23.595 ;
        RECT 130.200 23.175 130.505 24.315 ;
        RECT 130.675 23.125 130.930 24.005 ;
        RECT 132.025 23.150 132.315 24.315 ;
        RECT 132.600 23.685 132.885 24.145 ;
        RECT 133.055 23.855 133.325 24.315 ;
        RECT 132.600 23.465 133.555 23.685 ;
        RECT 129.810 22.975 130.550 23.005 ;
        RECT 128.525 22.375 129.055 22.545 ;
        RECT 126.835 21.955 127.185 22.125 ;
        RECT 127.405 21.935 128.355 22.215 ;
        RECT 128.525 21.765 128.715 22.205 ;
        RECT 128.885 22.145 129.055 22.375 ;
        RECT 129.225 22.315 129.465 22.715 ;
        RECT 129.635 22.675 130.550 22.975 ;
        RECT 129.635 22.500 129.960 22.675 ;
        RECT 129.635 22.145 129.955 22.500 ;
        RECT 130.720 22.475 130.930 23.125 ;
        RECT 132.485 22.735 133.175 23.295 ;
        RECT 133.345 22.565 133.555 23.465 ;
        RECT 128.885 21.975 129.955 22.145 ;
        RECT 130.200 21.765 130.505 22.225 ;
        RECT 130.675 21.945 130.930 22.475 ;
        RECT 132.025 21.765 132.315 22.490 ;
        RECT 132.600 22.395 133.555 22.565 ;
        RECT 133.725 23.295 134.125 24.145 ;
        RECT 134.315 23.685 134.595 24.145 ;
        RECT 135.115 23.855 135.440 24.315 ;
        RECT 134.315 23.465 135.440 23.685 ;
        RECT 133.725 22.735 134.820 23.295 ;
        RECT 134.990 23.005 135.440 23.465 ;
        RECT 135.610 23.175 135.995 24.145 ;
        RECT 136.165 23.880 141.510 24.315 ;
        RECT 141.685 23.880 147.030 24.315 ;
        RECT 132.600 21.935 132.885 22.395 ;
        RECT 133.055 21.765 133.325 22.225 ;
        RECT 133.725 21.935 134.125 22.735 ;
        RECT 134.990 22.675 135.545 23.005 ;
        RECT 134.990 22.565 135.440 22.675 ;
        RECT 134.315 22.395 135.440 22.565 ;
        RECT 135.715 22.505 135.995 23.175 ;
        RECT 134.315 21.935 134.595 22.395 ;
        RECT 135.115 21.765 135.440 22.225 ;
        RECT 135.610 21.935 135.995 22.505 ;
        RECT 137.750 22.310 138.090 23.140 ;
        RECT 139.570 22.630 139.920 23.880 ;
        RECT 143.270 22.310 143.610 23.140 ;
        RECT 145.090 22.630 145.440 23.880 ;
        RECT 147.665 23.225 148.875 24.315 ;
        RECT 147.665 22.685 148.185 23.225 ;
        RECT 148.355 22.515 148.875 23.055 ;
        RECT 136.165 21.765 141.510 22.310 ;
        RECT 141.685 21.765 147.030 22.310 ;
        RECT 147.665 21.765 148.875 22.515 ;
        RECT 119.060 21.595 148.960 21.765 ;
        RECT 90.440 19.240 103.560 20.440 ;
        RECT 119.145 20.845 120.355 21.595 ;
        RECT 120.525 21.050 125.870 21.595 ;
        RECT 126.045 21.050 131.390 21.595 ;
        RECT 131.565 21.050 136.910 21.595 ;
        RECT 137.085 21.050 142.430 21.595 ;
        RECT 119.145 20.305 119.665 20.845 ;
        RECT 119.835 20.135 120.355 20.675 ;
        RECT 122.110 20.220 122.450 21.050 ;
        RECT 15.500 18.000 37.470 18.170 ;
        RECT 46.500 18.000 48.500 18.180 ;
        RECT 73.380 18.000 73.940 18.180 ;
        RECT 83.440 18.000 84.640 19.240 ;
        RECT 119.145 19.045 120.355 20.135 ;
        RECT 123.930 19.480 124.280 20.730 ;
        RECT 127.630 20.220 127.970 21.050 ;
        RECT 129.450 19.480 129.800 20.730 ;
        RECT 133.150 20.220 133.490 21.050 ;
        RECT 134.970 19.480 135.320 20.730 ;
        RECT 138.670 20.220 139.010 21.050 ;
        RECT 142.605 20.825 144.275 21.595 ;
        RECT 144.905 20.870 145.195 21.595 ;
        RECT 145.365 20.825 147.035 21.595 ;
        RECT 147.665 20.845 148.875 21.595 ;
        RECT 140.490 19.480 140.840 20.730 ;
        RECT 142.605 20.305 143.355 20.825 ;
        RECT 143.525 20.135 144.275 20.655 ;
        RECT 145.365 20.305 146.115 20.825 ;
        RECT 120.525 19.045 125.870 19.480 ;
        RECT 126.045 19.045 131.390 19.480 ;
        RECT 131.565 19.045 136.910 19.480 ;
        RECT 137.085 19.045 142.430 19.480 ;
        RECT 142.605 19.045 144.275 20.135 ;
        RECT 144.905 19.045 145.195 20.210 ;
        RECT 146.285 20.135 147.035 20.655 ;
        RECT 145.365 19.045 147.035 20.135 ;
        RECT 147.665 20.135 148.185 20.675 ;
        RECT 148.355 20.305 148.875 20.845 ;
        RECT 147.665 19.045 148.875 20.135 ;
        RECT 119.060 18.875 148.960 19.045 ;
        RECT 15.500 16.000 109.500 18.000 ;
        RECT 119.145 17.785 120.355 18.875 ;
        RECT 120.525 18.440 125.870 18.875 ;
        RECT 126.045 18.440 131.390 18.875 ;
        RECT 119.145 17.075 119.665 17.615 ;
        RECT 119.835 17.245 120.355 17.785 ;
        RECT 119.145 16.325 120.355 17.075 ;
        RECT 122.110 16.870 122.450 17.700 ;
        RECT 123.930 17.190 124.280 18.440 ;
        RECT 127.630 16.870 127.970 17.700 ;
        RECT 129.450 17.190 129.800 18.440 ;
        RECT 132.025 17.710 132.315 18.875 ;
        RECT 132.485 18.440 137.830 18.875 ;
        RECT 138.005 18.440 143.350 18.875 ;
        RECT 120.525 16.325 125.870 16.870 ;
        RECT 126.045 16.325 131.390 16.870 ;
        RECT 132.025 16.325 132.315 17.050 ;
        RECT 134.070 16.870 134.410 17.700 ;
        RECT 135.890 17.190 136.240 18.440 ;
        RECT 139.590 16.870 139.930 17.700 ;
        RECT 141.410 17.190 141.760 18.440 ;
        RECT 143.525 17.785 144.735 18.875 ;
        RECT 143.525 17.075 144.045 17.615 ;
        RECT 144.215 17.245 144.735 17.785 ;
        RECT 144.905 17.710 145.195 18.875 ;
        RECT 145.365 17.785 147.035 18.875 ;
        RECT 145.365 17.095 146.115 17.615 ;
        RECT 146.285 17.265 147.035 17.785 ;
        RECT 147.665 17.785 148.875 18.875 ;
        RECT 147.665 17.245 148.185 17.785 ;
        RECT 132.485 16.325 137.830 16.870 ;
        RECT 138.005 16.325 143.350 16.870 ;
        RECT 143.525 16.325 144.735 17.075 ;
        RECT 144.905 16.325 145.195 17.050 ;
        RECT 145.365 16.325 147.035 17.095 ;
        RECT 148.355 17.075 148.875 17.615 ;
        RECT 147.665 16.325 148.875 17.075 ;
        RECT 119.060 16.155 148.960 16.325 ;
      LAYER met1 ;
        RECT 130.490 108.660 130.850 108.960 ;
        RECT 45.130 108.170 45.430 108.200 ;
        RECT 45.130 107.870 47.590 108.170 ;
        RECT 130.520 107.940 130.820 108.660 ;
        RECT 133.110 107.950 133.650 108.450 ;
        RECT 137.080 108.010 137.620 108.090 ;
        RECT 45.130 107.840 45.430 107.870 ;
        RECT 129.500 107.380 131.040 107.940 ;
        RECT 132.430 107.530 133.650 107.950 ;
        RECT 136.080 107.570 137.620 108.010 ;
        RECT 132.430 107.410 133.560 107.530 ;
        RECT 137.080 107.200 137.620 107.570 ;
        RECT 137.170 107.000 137.530 107.200 ;
        RECT 142.400 106.350 143.280 106.690 ;
        RECT 145.100 106.350 145.980 106.690 ;
        RECT 142.400 105.150 143.280 105.490 ;
        RECT 145.100 105.150 145.980 105.490 ;
        RECT 142.400 104.350 143.280 104.690 ;
        RECT 145.100 104.350 145.980 104.690 ;
        RECT 142.400 102.750 143.280 103.090 ;
        RECT 142.400 101.950 143.280 102.290 ;
        RECT 140.970 101.850 141.270 101.910 ;
        RECT 130.540 101.550 141.270 101.850 ;
        RECT 140.970 101.490 141.270 101.550 ;
        RECT 138.110 100.720 141.060 101.020 ;
        RECT 144.270 100.890 144.570 103.750 ;
        RECT 145.100 102.750 145.980 103.090 ;
        RECT 142.400 100.350 143.280 100.690 ;
        RECT 144.240 100.590 144.600 100.890 ;
        RECT 145.100 100.350 145.980 100.690 ;
        RECT 5.470 77.000 17.530 79.000 ;
        RECT 17.220 72.460 17.540 72.470 ;
        RECT 16.500 71.400 17.540 72.460 ;
        RECT 17.220 68.870 17.540 71.400 ;
        RECT 17.220 59.040 17.540 65.470 ;
        RECT 16.520 58.020 17.540 59.040 ;
        RECT 17.220 57.870 17.540 58.020 ;
        RECT 17.220 57.430 17.540 57.470 ;
        RECT 16.500 53.870 17.540 57.430 ;
        RECT 16.500 51.200 17.500 53.870 ;
        RECT 12.000 51.030 14.000 51.060 ;
        RECT 12.000 49.030 17.530 51.030 ;
        RECT 17.860 50.020 18.820 72.470 ;
        RECT 19.780 70.040 20.740 72.470 ;
        RECT 28.470 71.430 29.530 72.430 ;
        RECT 19.780 69.020 20.780 70.040 ;
        RECT 19.780 68.870 20.740 69.020 ;
        RECT 23.220 66.840 23.540 69.470 ;
        RECT 22.520 65.870 23.540 66.840 ;
        RECT 22.520 65.820 23.480 65.870 ;
        RECT 19.140 64.510 20.710 65.470 ;
        RECT 19.140 61.870 20.100 64.510 ;
        RECT 19.140 57.870 20.100 61.470 ;
        RECT 23.220 59.040 23.540 65.470 ;
        RECT 19.140 54.830 20.100 57.470 ;
        RECT 19.140 53.870 20.710 54.830 ;
        RECT 12.000 49.000 14.000 49.030 ;
        RECT 5.500 47.000 7.500 47.030 ;
        RECT 5.500 45.000 17.530 47.000 ;
        RECT 21.020 46.490 21.980 59.040 ;
        RECT 22.520 58.020 23.540 59.040 ;
        RECT 23.220 57.870 23.540 58.020 ;
        RECT 22.500 57.470 23.500 57.530 ;
        RECT 22.500 53.870 23.540 57.470 ;
        RECT 22.500 52.230 23.500 53.870 ;
        RECT 22.470 51.230 23.530 52.230 ;
        RECT 23.860 50.020 24.820 69.470 ;
        RECT 25.140 65.870 26.100 70.040 ;
        RECT 25.140 62.830 26.100 65.470 ;
        RECT 25.140 61.870 26.710 62.830 ;
        RECT 25.140 57.870 26.100 61.470 ;
        RECT 25.140 55.010 26.100 57.470 ;
        RECT 27.020 55.010 27.980 59.040 ;
        RECT 25.110 54.050 26.130 55.010 ;
        RECT 26.990 54.050 28.010 55.010 ;
        RECT 25.140 53.870 26.100 54.050 ;
        RECT 28.500 51.200 29.500 71.430 ;
        RECT 29.960 70.550 30.980 71.510 ;
        RECT 30.220 61.870 30.540 70.550 ;
        RECT 30.220 50.560 30.540 61.470 ;
        RECT 30.860 60.940 31.820 69.470 ;
        RECT 32.140 66.810 33.100 69.470 ;
        RECT 32.140 65.850 33.710 66.810 ;
        RECT 32.140 62.830 33.100 65.850 ;
        RECT 32.110 61.870 33.130 62.830 ;
        RECT 34.220 61.820 35.180 70.040 ;
        RECT 36.865 69.470 37.820 78.035 ;
        RECT 42.520 73.470 43.480 73.500 ;
        RECT 42.520 72.480 43.540 73.470 ;
        RECT 36.220 66.860 36.540 69.470 ;
        RECT 35.520 65.840 36.540 66.860 ;
        RECT 36.860 65.870 37.820 69.470 ;
        RECT 38.140 66.830 39.100 69.470 ;
        RECT 38.110 65.870 39.130 66.830 ;
        RECT 36.220 65.500 36.540 65.840 ;
        RECT 35.520 64.480 36.540 65.500 ;
        RECT 36.865 65.470 37.820 65.870 ;
        RECT 30.820 59.920 31.820 60.940 ;
        RECT 30.860 53.870 31.820 59.920 ;
        RECT 32.140 59.010 33.100 61.470 ;
        RECT 32.110 58.050 33.130 59.010 ;
        RECT 32.140 53.870 33.100 58.050 ;
        RECT 34.220 58.020 35.180 60.940 ;
        RECT 36.220 57.870 36.540 64.480 ;
        RECT 36.860 61.870 37.820 65.470 ;
        RECT 38.140 62.840 39.100 65.470 ;
        RECT 38.140 61.870 39.480 62.840 ;
        RECT 36.865 61.470 37.820 61.870 ;
        RECT 38.520 61.820 39.480 61.870 ;
        RECT 36.860 57.870 37.820 61.470 ;
        RECT 38.140 59.010 39.100 61.470 ;
        RECT 38.110 58.050 39.130 59.010 ;
        RECT 38.140 57.870 39.100 58.050 ;
        RECT 35.500 53.530 36.540 57.550 ;
        RECT 36.865 57.470 37.820 57.870 ;
        RECT 36.860 53.870 37.820 57.470 ;
        RECT 38.140 57.440 39.100 57.470 ;
        RECT 38.140 56.420 39.480 57.440 ;
        RECT 39.920 56.420 40.880 66.860 ;
        RECT 38.140 53.870 39.100 56.420 ;
        RECT 41.520 53.550 42.480 70.040 ;
        RECT 43.220 69.870 43.540 72.480 ;
        RECT 43.220 59.840 43.540 69.470 ;
        RECT 43.220 54.220 43.540 57.470 ;
        RECT 43.040 53.870 43.540 54.220 ;
        RECT 43.040 53.840 43.360 53.870 ;
        RECT 35.470 52.530 36.540 53.530 ;
        RECT 35.500 52.480 36.540 52.530 ;
        RECT 30.000 49.500 31.000 50.560 ;
        RECT 43.860 50.020 44.820 73.470 ;
        RECT 45.120 57.470 46.080 57.500 ;
        RECT 45.120 56.480 46.100 57.470 ;
        RECT 45.140 53.870 46.100 56.480 ;
        RECT 46.480 52.480 47.520 94.550 ;
        RECT 79.110 93.520 80.130 94.480 ;
        RECT 48.340 71.510 49.300 75.040 ;
        RECT 48.340 70.550 50.010 71.510 ;
        RECT 48.340 65.220 49.300 70.550 ;
        RECT 48.310 59.870 48.690 60.190 ;
        RECT 48.340 51.690 48.660 59.870 ;
        RECT 50.220 54.190 50.540 57.470 ;
        RECT 50.010 53.870 50.540 54.190 ;
        RECT 50.860 53.870 51.820 78.040 ;
        RECT 59.120 73.470 60.080 73.500 ;
        RECT 57.220 70.220 57.540 73.470 ;
        RECT 57.040 69.870 57.540 70.220 ;
        RECT 57.040 69.840 57.360 69.870 ;
        RECT 57.220 66.220 57.540 69.470 ;
        RECT 57.040 65.870 57.540 66.220 ;
        RECT 57.040 65.840 57.360 65.870 ;
        RECT 52.140 56.510 53.710 57.470 ;
        RECT 52.140 53.870 53.100 56.510 ;
        RECT 48.310 51.370 48.690 51.690 ;
        RECT 5.500 44.970 7.500 45.000 ;
        RECT 17.910 36.985 20.960 37.560 ;
        RECT 24.960 36.985 28.010 37.560 ;
        RECT 32.010 36.985 35.060 37.560 ;
        RECT 17.910 34.985 35.060 36.985 ;
        RECT 17.910 34.510 20.960 34.985 ;
        RECT 24.960 34.510 28.010 34.985 ;
        RECT 32.010 34.510 35.060 34.985 ;
        RECT 18.485 30.510 20.485 34.510 ;
        RECT 17.910 27.460 20.960 30.510 ;
        RECT 18.485 23.460 20.485 27.460 ;
        RECT 24.785 27.285 28.185 30.685 ;
        RECT 32.485 30.510 34.485 34.510 ;
        RECT 36.970 33.000 38.030 34.000 ;
        RECT 32.010 27.460 35.060 30.510 ;
        RECT 26.020 24.810 26.980 27.285 ;
        RECT 32.485 23.460 34.485 27.460 ;
        RECT 17.910 22.985 20.960 23.460 ;
        RECT 24.960 22.985 28.010 23.460 ;
        RECT 32.010 22.985 35.060 23.460 ;
        RECT 17.910 20.985 35.060 22.985 ;
        RECT 37.000 22.970 38.000 33.000 ;
        RECT 39.720 32.840 40.040 36.440 ;
        RECT 40.360 34.030 41.320 46.010 ;
        RECT 40.360 32.970 41.500 34.030 ;
        RECT 40.360 32.840 41.320 32.970 ;
        RECT 42.280 32.840 43.240 36.440 ;
        RECT 39.720 28.030 40.040 32.440 ;
        RECT 40.360 32.110 41.320 32.440 ;
        RECT 40.260 31.090 41.320 32.110 ;
        RECT 39.000 26.970 40.040 28.030 ;
        RECT 39.720 24.840 40.040 26.970 ;
        RECT 40.360 24.840 41.320 31.090 ;
        RECT 42.280 29.800 43.240 32.440 ;
        RECT 44.020 31.090 44.980 39.510 ;
        RECT 46.220 38.000 46.540 41.940 ;
        RECT 46.860 38.340 47.820 46.010 ;
        RECT 42.250 28.840 43.270 29.800 ;
        RECT 42.280 24.840 43.240 28.440 ;
        RECT 17.910 20.410 20.960 20.985 ;
        RECT 24.960 20.410 28.010 20.985 ;
        RECT 32.010 20.410 35.060 20.985 ;
        RECT 39.720 20.840 40.040 24.440 ;
        RECT 40.360 24.030 41.320 24.440 ;
        RECT 40.360 22.970 41.500 24.030 ;
        RECT 40.360 20.840 41.320 22.970 ;
        RECT 42.280 20.840 43.240 24.440 ;
        RECT 46.000 22.970 47.000 38.000 ;
        RECT 48.030 32.770 49.030 36.530 ;
        RECT 50.000 24.970 51.000 50.530 ;
        RECT 54.500 50.000 55.500 63.560 ;
        RECT 57.220 62.220 57.540 65.470 ;
        RECT 57.040 61.870 57.540 62.220 ;
        RECT 57.040 61.840 57.360 61.870 ;
        RECT 57.220 58.220 57.540 61.470 ;
        RECT 57.040 57.870 57.540 58.220 ;
        RECT 57.040 57.840 57.360 57.870 ;
        RECT 56.520 57.470 57.480 57.500 ;
        RECT 56.520 56.480 57.540 57.470 ;
        RECT 57.220 54.220 57.540 56.480 ;
        RECT 57.040 53.870 57.540 54.220 ;
        RECT 57.040 53.840 57.360 53.870 ;
        RECT 51.340 39.510 52.300 41.940 ;
        RECT 51.340 38.490 52.480 39.510 ;
        RECT 51.340 38.340 52.300 38.490 ;
        RECT 52.520 29.800 53.480 34.010 ;
        RECT 52.490 28.840 53.510 29.800 ;
        RECT 56.000 22.970 57.000 52.260 ;
        RECT 57.860 51.010 58.820 73.470 ;
        RECT 59.120 72.480 60.100 73.470 ;
        RECT 59.140 69.870 60.100 72.480 ;
        RECT 59.120 69.470 60.080 69.500 ;
        RECT 59.120 68.480 60.100 69.470 ;
        RECT 62.020 68.480 62.980 71.040 ;
        RECT 64.220 70.190 64.540 73.470 ;
        RECT 64.010 69.870 64.540 70.190 ;
        RECT 59.140 65.870 60.100 68.480 ;
        RECT 59.120 65.470 60.080 65.500 ;
        RECT 59.120 64.480 60.100 65.470 ;
        RECT 62.020 64.480 62.980 67.040 ;
        RECT 64.220 66.190 64.540 69.470 ;
        RECT 64.010 65.870 64.540 66.190 ;
        RECT 59.140 61.870 60.100 64.480 ;
        RECT 59.120 61.470 60.080 61.500 ;
        RECT 62.020 61.470 62.980 63.040 ;
        RECT 64.220 62.190 64.540 65.470 ;
        RECT 64.010 61.870 64.540 62.190 ;
        RECT 59.120 60.480 60.100 61.470 ;
        RECT 61.990 60.510 63.010 61.470 ;
        RECT 59.140 57.870 60.100 60.480 ;
        RECT 59.120 57.470 60.080 57.500 ;
        RECT 59.120 56.480 60.100 57.470 ;
        RECT 62.020 56.480 62.980 59.040 ;
        RECT 64.220 58.190 64.540 61.470 ;
        RECT 64.010 57.870 64.540 58.190 ;
        RECT 59.140 53.870 60.100 56.480 ;
        RECT 57.830 50.050 58.850 51.010 ;
        RECT 61.650 50.560 62.150 55.310 ;
        RECT 64.220 54.190 64.540 57.470 ;
        RECT 64.010 53.870 64.540 54.190 ;
        RECT 64.860 53.870 65.820 78.040 ;
        RECT 66.140 72.510 67.710 73.470 ;
        RECT 66.140 69.870 67.100 72.510 ;
        RECT 71.220 72.460 71.540 72.470 ;
        RECT 70.500 71.400 71.540 72.460 ;
        RECT 66.140 68.510 67.710 69.470 ;
        RECT 71.220 68.870 71.540 71.400 ;
        RECT 66.140 65.870 67.100 68.510 ;
        RECT 66.140 64.510 67.710 65.470 ;
        RECT 66.140 61.870 67.100 64.510 ;
        RECT 66.140 60.510 67.710 61.470 ;
        RECT 66.140 57.870 67.100 60.510 ;
        RECT 71.220 59.040 71.540 65.470 ;
        RECT 70.520 58.020 71.540 59.040 ;
        RECT 71.220 57.870 71.540 58.020 ;
        RECT 66.140 56.510 67.710 57.470 ;
        RECT 71.220 57.430 71.540 57.470 ;
        RECT 66.140 53.870 67.100 56.510 ;
        RECT 70.500 53.870 71.540 57.430 ;
        RECT 70.500 51.200 71.500 53.870 ;
        RECT 61.500 49.500 62.500 50.560 ;
        RECT 71.860 50.020 72.820 72.470 ;
        RECT 73.780 70.040 74.740 72.470 ;
        RECT 73.780 69.020 74.780 70.040 ;
        RECT 73.780 68.870 74.740 69.020 ;
        RECT 77.220 66.840 77.540 69.470 ;
        RECT 76.520 65.870 77.540 66.840 ;
        RECT 76.520 65.820 77.480 65.870 ;
        RECT 73.140 64.510 74.710 65.470 ;
        RECT 73.140 61.870 74.100 64.510 ;
        RECT 73.140 57.870 74.100 61.470 ;
        RECT 77.220 59.040 77.540 65.470 ;
        RECT 73.140 54.830 74.100 57.470 ;
        RECT 73.140 53.870 74.710 54.830 ;
        RECT 61.650 49.480 62.150 49.500 ;
        RECT 75.020 47.990 75.980 59.040 ;
        RECT 76.520 58.020 77.540 59.040 ;
        RECT 77.220 57.870 77.540 58.020 ;
        RECT 76.500 57.470 77.500 57.530 ;
        RECT 76.500 53.870 77.540 57.470 ;
        RECT 76.500 52.230 77.500 53.870 ;
        RECT 76.470 51.230 77.530 52.230 ;
        RECT 77.860 50.020 78.820 69.470 ;
        RECT 79.140 65.870 80.100 93.520 ;
        RECT 119.060 84.000 148.960 84.480 ;
        RECT 120.050 83.800 120.370 83.860 ;
        RECT 120.985 83.800 121.275 83.845 ;
        RECT 120.050 83.660 121.275 83.800 ;
        RECT 120.050 83.600 120.370 83.660 ;
        RECT 120.985 83.615 121.275 83.660 ;
        RECT 123.270 83.600 123.590 83.860 ;
        RECT 125.110 83.600 125.430 83.860 ;
        RECT 127.425 83.800 127.715 83.845 ;
        RECT 129.250 83.800 129.570 83.860 ;
        RECT 127.425 83.660 129.570 83.800 ;
        RECT 127.425 83.615 127.715 83.660 ;
        RECT 129.250 83.600 129.570 83.660 ;
        RECT 140.290 83.800 140.610 83.860 ;
        RECT 146.285 83.800 146.575 83.845 ;
        RECT 140.290 83.660 146.575 83.800 ;
        RECT 140.290 83.600 140.610 83.660 ;
        RECT 146.285 83.615 146.575 83.660 ;
        RECT 129.250 83.120 129.570 83.180 ;
        RECT 131.105 83.120 131.395 83.165 ;
        RECT 121.980 82.980 131.395 83.120 ;
        RECT 121.980 82.825 122.120 82.980 ;
        RECT 129.250 82.920 129.570 82.980 ;
        RECT 131.105 82.935 131.395 82.980 ;
        RECT 121.905 82.595 122.195 82.825 ;
        RECT 124.205 82.780 124.495 82.825 ;
        RECT 124.205 82.640 125.800 82.780 ;
        RECT 124.205 82.595 124.495 82.640 ;
        RECT 125.660 82.440 125.800 82.640 ;
        RECT 126.030 82.580 126.350 82.840 ;
        RECT 126.490 82.780 126.810 82.840 ;
        RECT 135.245 82.780 135.535 82.825 ;
        RECT 126.490 82.640 135.535 82.780 ;
        RECT 126.490 82.580 126.810 82.640 ;
        RECT 135.245 82.595 135.535 82.640 ;
        RECT 137.530 82.780 137.850 82.840 ;
        RECT 139.385 82.780 139.675 82.825 ;
        RECT 137.530 82.640 139.675 82.780 ;
        RECT 137.530 82.580 137.850 82.640 ;
        RECT 139.385 82.595 139.675 82.640 ;
        RECT 144.430 82.580 144.750 82.840 ;
        RECT 145.350 82.580 145.670 82.840 ;
        RECT 130.170 82.440 130.490 82.500 ;
        RECT 125.660 82.300 130.490 82.440 ;
        RECT 130.170 82.240 130.490 82.300 ;
        RECT 126.030 82.100 126.350 82.160 ;
        RECT 127.870 82.100 128.190 82.160 ;
        RECT 126.030 81.960 128.190 82.100 ;
        RECT 126.030 81.900 126.350 81.960 ;
        RECT 127.870 81.900 128.190 81.960 ;
        RECT 128.330 81.900 128.650 82.160 ;
        RECT 132.470 81.900 132.790 82.160 ;
        RECT 136.610 81.900 136.930 82.160 ;
        RECT 141.225 82.100 141.515 82.145 ;
        RECT 142.590 82.100 142.910 82.160 ;
        RECT 141.225 81.960 142.910 82.100 ;
        RECT 141.225 81.915 141.515 81.960 ;
        RECT 142.590 81.900 142.910 81.960 ;
        RECT 119.060 81.280 148.960 81.760 ;
        RECT 126.505 81.080 126.795 81.125 ;
        RECT 128.330 81.080 128.650 81.140 ;
        RECT 126.505 80.940 128.650 81.080 ;
        RECT 126.505 80.895 126.795 80.940 ;
        RECT 128.330 80.880 128.650 80.940 ;
        RECT 137.530 81.080 137.850 81.140 ;
        RECT 138.005 81.080 138.295 81.125 ;
        RECT 137.530 80.940 138.295 81.080 ;
        RECT 137.530 80.880 137.850 80.940 ;
        RECT 138.005 80.895 138.295 80.940 ;
        RECT 132.930 80.785 133.250 80.800 ;
        RECT 132.925 80.740 133.575 80.785 ;
        RECT 136.525 80.740 136.815 80.785 ;
        RECT 132.925 80.600 136.815 80.740 ;
        RECT 132.925 80.555 133.575 80.600 ;
        RECT 136.225 80.555 136.815 80.600 ;
        RECT 132.930 80.540 133.250 80.555 ;
        RECT 121.430 80.400 121.750 80.460 ;
        RECT 121.905 80.400 122.195 80.445 ;
        RECT 121.430 80.260 122.195 80.400 ;
        RECT 121.430 80.200 121.750 80.260 ;
        RECT 121.905 80.215 122.195 80.260 ;
        RECT 129.730 80.400 130.020 80.445 ;
        RECT 131.565 80.400 131.855 80.445 ;
        RECT 135.145 80.400 135.435 80.445 ;
        RECT 129.730 80.260 135.435 80.400 ;
        RECT 129.730 80.215 130.020 80.260 ;
        RECT 131.565 80.215 131.855 80.260 ;
        RECT 135.145 80.215 135.435 80.260 ;
        RECT 136.225 80.240 136.515 80.555 ;
        RECT 138.080 80.400 138.220 80.895 ;
        RECT 142.590 80.880 142.910 81.140 ;
        RECT 146.270 80.880 146.590 81.140 ;
        RECT 138.465 80.400 138.755 80.445 ;
        RECT 138.080 80.260 138.755 80.400 ;
        RECT 138.465 80.215 138.755 80.260 ;
        RECT 145.365 80.400 145.655 80.445 ;
        RECT 146.270 80.400 146.590 80.460 ;
        RECT 145.365 80.260 146.590 80.400 ;
        RECT 145.365 80.215 145.655 80.260 ;
        RECT 146.270 80.200 146.590 80.260 ;
        RECT 125.570 80.060 125.890 80.120 ;
        RECT 126.965 80.060 127.255 80.105 ;
        RECT 125.570 79.920 127.255 80.060 ;
        RECT 125.570 79.860 125.890 79.920 ;
        RECT 126.965 79.875 127.255 79.920 ;
        RECT 127.885 79.875 128.175 80.105 ;
        RECT 129.265 80.060 129.555 80.105 ;
        RECT 130.645 80.060 130.935 80.105 ;
        RECT 131.090 80.060 131.410 80.120 ;
        RECT 129.265 79.920 129.940 80.060 ;
        RECT 129.265 79.875 129.555 79.920 ;
        RECT 127.410 79.720 127.730 79.780 ;
        RECT 127.960 79.720 128.100 79.875 ;
        RECT 127.410 79.580 128.100 79.720 ;
        RECT 127.410 79.520 127.730 79.580 ;
        RECT 120.970 79.180 121.290 79.440 ;
        RECT 121.890 79.380 122.210 79.440 ;
        RECT 124.665 79.380 124.955 79.425 ;
        RECT 121.890 79.240 124.955 79.380 ;
        RECT 129.800 79.380 129.940 79.920 ;
        RECT 130.645 79.920 131.410 80.060 ;
        RECT 130.645 79.875 130.935 79.920 ;
        RECT 131.090 79.860 131.410 79.920 ;
        RECT 137.070 80.060 137.390 80.120 ;
        RECT 137.070 79.920 139.600 80.060 ;
        RECT 137.070 79.860 137.390 79.920 ;
        RECT 139.460 79.765 139.600 79.920 ;
        RECT 143.050 79.860 143.370 80.120 ;
        RECT 143.525 79.875 143.815 80.105 ;
        RECT 130.135 79.720 130.425 79.765 ;
        RECT 132.025 79.720 132.315 79.765 ;
        RECT 135.145 79.720 135.435 79.765 ;
        RECT 130.135 79.580 135.435 79.720 ;
        RECT 130.135 79.535 130.425 79.580 ;
        RECT 132.025 79.535 132.315 79.580 ;
        RECT 135.145 79.535 135.435 79.580 ;
        RECT 139.385 79.535 139.675 79.765 ;
        RECT 141.670 79.720 141.990 79.780 ;
        RECT 143.600 79.720 143.740 79.875 ;
        RECT 141.670 79.580 143.740 79.720 ;
        RECT 141.670 79.520 141.990 79.580 ;
        RECT 131.550 79.380 131.870 79.440 ;
        RECT 129.800 79.240 131.870 79.380 ;
        RECT 121.890 79.180 122.210 79.240 ;
        RECT 124.665 79.195 124.955 79.240 ;
        RECT 131.550 79.180 131.870 79.240 ;
        RECT 140.750 79.180 141.070 79.440 ;
        RECT 119.060 78.560 148.960 79.040 ;
        RECT 122.825 78.360 123.115 78.405 ;
        RECT 126.490 78.360 126.810 78.420 ;
        RECT 122.825 78.220 126.810 78.360 ;
        RECT 122.825 78.175 123.115 78.220 ;
        RECT 126.490 78.160 126.810 78.220 ;
        RECT 131.090 78.360 131.410 78.420 ;
        RECT 132.485 78.360 132.775 78.405 ;
        RECT 131.090 78.220 132.775 78.360 ;
        RECT 131.090 78.160 131.410 78.220 ;
        RECT 132.485 78.175 132.775 78.220 ;
        RECT 144.430 78.360 144.750 78.420 ;
        RECT 145.825 78.360 146.115 78.405 ;
        RECT 144.430 78.220 146.115 78.360 ;
        RECT 144.430 78.160 144.750 78.220 ;
        RECT 145.825 78.175 146.115 78.220 ;
        RECT 84.190 74.370 84.570 74.690 ;
        RECT 82.470 71.430 83.530 72.430 ;
        RECT 79.140 62.830 80.100 65.470 ;
        RECT 79.140 61.870 80.710 62.830 ;
        RECT 79.140 57.870 80.100 61.470 ;
        RECT 79.140 55.010 80.100 57.470 ;
        RECT 81.020 55.010 81.980 59.040 ;
        RECT 79.110 54.050 80.130 55.010 ;
        RECT 80.990 54.050 82.010 55.010 ;
        RECT 79.140 53.870 80.100 54.050 ;
        RECT 82.500 51.200 83.500 71.430 ;
        RECT 84.220 61.870 84.540 74.370 ;
        RECT 84.220 50.560 84.540 61.470 ;
        RECT 84.860 60.940 85.820 69.470 ;
        RECT 86.140 66.810 87.100 69.470 ;
        RECT 86.140 65.850 87.710 66.810 ;
        RECT 86.140 62.830 87.100 65.850 ;
        RECT 86.110 61.870 87.130 62.830 ;
        RECT 88.220 61.820 89.180 70.040 ;
        RECT 90.865 69.470 91.820 78.035 ;
        RECT 125.685 78.020 125.975 78.065 ;
        RECT 128.805 78.020 129.095 78.065 ;
        RECT 130.695 78.020 130.985 78.065 ;
        RECT 125.685 77.880 130.985 78.020 ;
        RECT 125.685 77.835 125.975 77.880 ;
        RECT 128.805 77.835 129.095 77.880 ;
        RECT 130.695 77.835 130.985 77.880 ;
        RECT 137.955 78.020 138.245 78.065 ;
        RECT 139.845 78.020 140.135 78.065 ;
        RECT 142.965 78.020 143.255 78.065 ;
        RECT 137.955 77.880 143.255 78.020 ;
        RECT 137.955 77.835 138.245 77.880 ;
        RECT 139.845 77.835 140.135 77.880 ;
        RECT 142.965 77.835 143.255 77.880 ;
        RECT 127.410 77.680 127.730 77.740 ;
        RECT 135.245 77.680 135.535 77.725 ;
        RECT 127.410 77.540 135.535 77.680 ;
        RECT 127.410 77.480 127.730 77.540 ;
        RECT 135.245 77.495 135.535 77.540 ;
        RECT 138.465 77.680 138.755 77.725 ;
        RECT 140.750 77.680 141.070 77.740 ;
        RECT 138.465 77.540 141.070 77.680 ;
        RECT 138.465 77.495 138.755 77.540 ;
        RECT 140.750 77.480 141.070 77.540 ;
        RECT 124.605 77.045 124.895 77.360 ;
        RECT 125.685 77.340 125.975 77.385 ;
        RECT 129.265 77.340 129.555 77.385 ;
        RECT 131.100 77.340 131.390 77.385 ;
        RECT 125.685 77.200 131.390 77.340 ;
        RECT 125.685 77.155 125.975 77.200 ;
        RECT 129.265 77.155 129.555 77.200 ;
        RECT 131.100 77.155 131.390 77.200 ;
        RECT 131.550 77.340 131.870 77.400 ;
        RECT 137.070 77.340 137.390 77.400 ;
        RECT 131.550 77.200 137.390 77.340 ;
        RECT 131.550 77.140 131.870 77.200 ;
        RECT 137.070 77.140 137.390 77.200 ;
        RECT 137.550 77.340 137.840 77.385 ;
        RECT 139.385 77.340 139.675 77.385 ;
        RECT 142.965 77.340 143.255 77.385 ;
        RECT 137.550 77.200 143.255 77.340 ;
        RECT 137.550 77.155 137.840 77.200 ;
        RECT 139.385 77.155 139.675 77.200 ;
        RECT 142.965 77.155 143.255 77.200 ;
        RECT 124.305 77.000 124.895 77.045 ;
        RECT 127.545 77.000 128.195 77.045 ;
        RECT 129.710 77.000 130.030 77.060 ;
        RECT 130.185 77.000 130.475 77.045 ;
        RECT 124.305 76.860 128.560 77.000 ;
        RECT 124.305 76.815 124.595 76.860 ;
        RECT 127.545 76.815 128.195 76.860 ;
        RECT 128.420 76.720 128.560 76.860 ;
        RECT 129.710 76.860 130.475 77.000 ;
        RECT 129.710 76.800 130.030 76.860 ;
        RECT 130.185 76.815 130.475 76.860 ;
        RECT 134.325 77.000 134.615 77.045 ;
        RECT 136.610 77.000 136.930 77.060 ;
        RECT 134.325 76.860 136.930 77.000 ;
        RECT 134.325 76.815 134.615 76.860 ;
        RECT 136.610 76.800 136.930 76.860 ;
        RECT 140.745 77.000 141.395 77.045 ;
        RECT 142.130 77.000 142.450 77.060 ;
        RECT 144.045 77.045 144.335 77.360 ;
        RECT 144.045 77.000 144.635 77.045 ;
        RECT 140.745 76.860 144.635 77.000 ;
        RECT 140.745 76.815 141.395 76.860 ;
        RECT 142.130 76.800 142.450 76.860 ;
        RECT 144.345 76.815 144.635 76.860 ;
        RECT 128.330 76.660 128.650 76.720 ;
        RECT 132.930 76.660 133.250 76.720 ;
        RECT 128.330 76.520 133.250 76.660 ;
        RECT 128.330 76.460 128.650 76.520 ;
        RECT 132.930 76.460 133.250 76.520 ;
        RECT 133.850 76.660 134.170 76.720 ;
        RECT 134.785 76.660 135.075 76.705 ;
        RECT 133.850 76.520 135.075 76.660 ;
        RECT 133.850 76.460 134.170 76.520 ;
        RECT 134.785 76.475 135.075 76.520 ;
        RECT 119.060 75.840 148.960 76.320 ;
        RECT 131.550 75.640 131.870 75.700 ;
        RECT 121.060 75.500 131.870 75.640 ;
        RECT 121.060 75.300 121.200 75.500 ;
        RECT 131.550 75.440 131.870 75.500 ;
        RECT 143.970 75.640 144.290 75.700 ;
        RECT 146.285 75.640 146.575 75.685 ;
        RECT 143.970 75.500 146.575 75.640 ;
        RECT 143.970 75.440 144.290 75.500 ;
        RECT 146.285 75.455 146.575 75.500 ;
        RECT 120.600 75.160 121.200 75.300 ;
        RECT 90.220 66.860 90.540 69.470 ;
        RECT 89.520 65.840 90.540 66.860 ;
        RECT 90.860 65.870 91.820 69.470 ;
        RECT 92.140 66.830 93.100 69.470 ;
        RECT 92.110 65.870 93.130 66.830 ;
        RECT 90.220 65.500 90.540 65.840 ;
        RECT 89.520 64.480 90.540 65.500 ;
        RECT 90.865 65.470 91.820 65.870 ;
        RECT 84.820 59.920 85.820 60.940 ;
        RECT 84.860 53.870 85.820 59.920 ;
        RECT 86.140 59.010 87.100 61.470 ;
        RECT 86.110 58.050 87.130 59.010 ;
        RECT 86.140 53.870 87.100 58.050 ;
        RECT 88.220 58.020 89.180 60.940 ;
        RECT 90.220 57.870 90.540 64.480 ;
        RECT 90.860 61.870 91.820 65.470 ;
        RECT 92.140 62.840 93.100 65.470 ;
        RECT 92.140 61.870 93.480 62.840 ;
        RECT 90.865 61.470 91.820 61.870 ;
        RECT 92.520 61.820 93.480 61.870 ;
        RECT 90.860 57.870 91.820 61.470 ;
        RECT 92.140 59.010 93.100 61.470 ;
        RECT 92.110 58.050 93.130 59.010 ;
        RECT 92.140 57.870 93.100 58.050 ;
        RECT 89.480 57.470 90.520 57.550 ;
        RECT 90.865 57.470 91.820 57.870 ;
        RECT 89.480 53.870 90.540 57.470 ;
        RECT 90.860 53.870 91.820 57.470 ;
        RECT 92.140 57.440 93.100 57.470 ;
        RECT 92.140 56.420 93.480 57.440 ;
        RECT 93.920 56.420 94.880 66.860 ;
        RECT 95.400 63.550 96.600 70.100 ;
        RECT 92.140 53.870 93.100 56.420 ;
        RECT 89.480 52.480 90.520 53.870 ;
        RECT 95.520 50.980 96.480 60.510 ;
        RECT 97.220 54.190 97.540 57.440 ;
        RECT 97.040 53.810 97.540 54.190 ;
        RECT 97.860 53.840 98.820 60.510 ;
        RECT 99.120 57.440 100.080 57.470 ;
        RECT 99.120 56.450 100.100 57.440 ;
        RECT 97.220 53.580 97.540 53.810 ;
        RECT 97.180 52.480 98.220 53.580 ;
        RECT 99.140 52.260 100.100 56.450 ;
        RECT 99.000 51.200 100.100 52.260 ;
        RECT 99.140 51.020 100.100 51.200 ;
        RECT 84.000 49.500 85.000 50.560 ;
        RECT 95.490 50.020 96.510 50.980 ;
        RECT 76.220 39.300 76.540 41.940 ;
        RECT 58.860 37.250 59.820 38.210 ;
        RECT 66.460 37.280 67.420 38.210 ;
        RECT 66.460 37.250 67.480 37.280 ;
        RECT 58.220 25.830 58.540 36.440 ;
        RECT 58.830 36.290 59.850 37.250 ;
        RECT 57.520 24.810 58.540 25.830 ;
        RECT 58.220 20.840 58.540 24.810 ;
        RECT 58.860 20.840 59.820 36.290 ;
        RECT 62.060 20.840 63.020 36.440 ;
        RECT 65.820 33.010 66.140 36.440 ;
        RECT 66.460 36.290 67.510 37.250 ;
        RECT 66.460 36.260 67.480 36.290 ;
        RECT 65.200 31.990 66.160 33.010 ;
        RECT 65.820 20.840 66.140 31.990 ;
        RECT 66.460 20.840 67.420 36.260 ;
        RECT 69.660 26.180 70.620 36.440 ;
        RECT 69.630 25.220 70.650 26.180 ;
        RECT 69.660 20.840 70.620 25.220 ;
        RECT 73.500 24.000 74.500 39.300 ;
        RECT 75.635 38.240 76.635 39.300 ;
        RECT 76.860 38.340 77.820 46.010 ;
        RECT 75.390 36.290 76.410 37.250 ;
        RECT 75.420 32.790 76.380 36.290 ;
        RECT 79.620 32.790 80.580 33.810 ;
        RECT 81.340 32.790 82.300 41.940 ;
        RECT 83.000 26.970 84.000 30.530 ;
        RECT 84.720 26.180 85.040 32.440 ;
        RECT 83.990 25.220 85.040 26.180 ;
        RECT 84.720 24.840 85.040 25.220 ;
        RECT 84.720 24.030 85.040 24.440 ;
        RECT 73.470 23.000 74.530 24.000 ;
        RECT 84.130 22.970 85.130 24.030 ;
        RECT 84.720 20.840 85.040 22.970 ;
        RECT 11.970 16.000 17.530 18.000 ;
        RECT 85.360 16.990 86.320 32.440 ;
        RECT 86.640 30.310 87.600 32.440 ;
        RECT 86.620 29.290 87.600 30.310 ;
        RECT 86.640 28.840 87.600 29.290 ;
        RECT 86.640 26.210 87.600 28.440 ;
        RECT 91.720 28.030 92.040 36.440 ;
        RECT 91.000 26.970 92.040 28.030 ;
        RECT 86.620 25.190 87.600 26.210 ;
        RECT 86.640 20.840 87.600 25.190 ;
        RECT 88.970 23.000 90.030 24.000 ;
        RECT 89.000 20.970 90.000 23.000 ;
        RECT 91.720 20.840 92.040 26.970 ;
        RECT 92.360 20.840 93.320 46.010 ;
        RECT 99.020 36.440 99.980 36.470 ;
        RECT 94.250 35.480 95.270 36.440 ;
        RECT 94.280 32.840 95.240 35.480 ;
        RECT 94.250 31.480 95.270 32.440 ;
        RECT 94.280 28.840 95.240 31.480 ;
        RECT 94.250 27.480 95.270 28.440 ;
        RECT 94.280 24.840 95.240 27.480 ;
        RECT 94.250 23.480 95.270 24.440 ;
        RECT 94.280 20.840 95.240 23.480 ;
        RECT 98.120 22.030 98.440 36.440 ;
        RECT 98.760 35.450 99.980 36.440 ;
        RECT 98.760 32.840 99.720 35.450 ;
        RECT 100.680 32.840 101.640 36.480 ;
        RECT 99.020 32.440 99.980 32.470 ;
        RECT 98.760 31.450 99.980 32.440 ;
        RECT 98.760 28.840 99.720 31.450 ;
        RECT 100.680 30.030 101.640 32.480 ;
        RECT 100.680 28.970 102.000 30.030 ;
        RECT 100.680 28.840 101.640 28.970 ;
        RECT 99.020 28.440 99.980 28.470 ;
        RECT 98.760 27.450 99.980 28.440 ;
        RECT 98.760 24.840 99.720 27.450 ;
        RECT 100.680 26.030 101.640 28.480 ;
        RECT 100.680 24.970 102.000 26.030 ;
        RECT 100.680 24.840 101.640 24.970 ;
        RECT 99.020 24.440 99.980 24.470 ;
        RECT 98.760 23.450 99.980 24.440 ;
        RECT 97.500 20.970 98.500 22.030 ;
        RECT 98.120 20.840 98.440 20.970 ;
        RECT 98.760 20.840 99.720 23.450 ;
        RECT 100.680 22.030 101.640 24.480 ;
        RECT 100.680 20.970 102.000 22.030 ;
        RECT 102.500 20.970 103.500 75.030 ;
        RECT 120.600 75.020 120.740 75.160 ;
        RECT 121.890 75.100 122.210 75.360 ;
        RECT 124.185 75.300 124.835 75.345 ;
        RECT 127.785 75.300 128.075 75.345 ;
        RECT 128.330 75.300 128.650 75.360 ;
        RECT 132.470 75.300 132.790 75.360 ;
        RECT 137.530 75.300 137.850 75.360 ;
        RECT 124.185 75.160 128.650 75.300 ;
        RECT 124.185 75.115 124.835 75.160 ;
        RECT 127.485 75.115 128.075 75.160 ;
        RECT 120.510 74.760 120.830 75.020 ;
        RECT 120.990 74.960 121.280 75.005 ;
        RECT 122.825 74.960 123.115 75.005 ;
        RECT 126.405 74.960 126.695 75.005 ;
        RECT 120.990 74.820 126.695 74.960 ;
        RECT 120.990 74.775 121.280 74.820 ;
        RECT 122.825 74.775 123.115 74.820 ;
        RECT 126.405 74.775 126.695 74.820 ;
        RECT 127.485 74.800 127.775 75.115 ;
        RECT 128.330 75.100 128.650 75.160 ;
        RECT 131.640 75.160 132.790 75.300 ;
        RECT 131.640 75.005 131.780 75.160 ;
        RECT 132.470 75.100 132.790 75.160 ;
        RECT 134.860 75.160 137.850 75.300 ;
        RECT 134.860 75.005 135.000 75.160 ;
        RECT 137.530 75.100 137.850 75.160 ;
        RECT 138.445 75.300 139.095 75.345 ;
        RECT 142.045 75.300 142.335 75.345 ;
        RECT 143.510 75.300 143.830 75.360 ;
        RECT 138.445 75.160 143.830 75.300 ;
        RECT 138.445 75.115 139.095 75.160 ;
        RECT 141.745 75.115 142.335 75.160 ;
        RECT 131.565 74.775 131.855 75.005 ;
        RECT 134.785 74.775 135.075 75.005 ;
        RECT 135.250 74.960 135.540 75.005 ;
        RECT 137.085 74.960 137.375 75.005 ;
        RECT 140.665 74.960 140.955 75.005 ;
        RECT 135.250 74.820 140.955 74.960 ;
        RECT 135.250 74.775 135.540 74.820 ;
        RECT 137.085 74.775 137.375 74.820 ;
        RECT 140.665 74.775 140.955 74.820 ;
        RECT 141.745 74.800 142.035 75.115 ;
        RECT 143.510 75.100 143.830 75.160 ;
        RECT 144.430 74.960 144.750 75.020 ;
        RECT 145.365 74.960 145.655 75.005 ;
        RECT 144.430 74.820 145.655 74.960 ;
        RECT 144.430 74.760 144.750 74.820 ;
        RECT 145.365 74.775 145.655 74.820 ;
        RECT 129.250 74.420 129.570 74.680 ;
        RECT 132.010 74.420 132.330 74.680 ;
        RECT 132.485 74.435 132.775 74.665 ;
        RECT 136.165 74.620 136.455 74.665 ;
        RECT 136.610 74.620 136.930 74.680 ;
        RECT 136.165 74.480 136.930 74.620 ;
        RECT 136.165 74.435 136.455 74.480 ;
        RECT 121.395 74.280 121.685 74.325 ;
        RECT 123.285 74.280 123.575 74.325 ;
        RECT 126.405 74.280 126.695 74.325 ;
        RECT 121.395 74.140 126.695 74.280 ;
        RECT 121.395 74.095 121.685 74.140 ;
        RECT 123.285 74.095 123.575 74.140 ;
        RECT 126.405 74.095 126.695 74.140 ;
        RECT 129.710 74.080 130.030 74.340 ;
        RECT 124.650 73.940 124.970 74.000 ;
        RECT 127.410 73.940 127.730 74.000 ;
        RECT 132.560 73.940 132.700 74.435 ;
        RECT 136.610 74.420 136.930 74.480 ;
        RECT 135.655 74.280 135.945 74.325 ;
        RECT 137.545 74.280 137.835 74.325 ;
        RECT 140.665 74.280 140.955 74.325 ;
        RECT 135.655 74.140 140.955 74.280 ;
        RECT 135.655 74.095 135.945 74.140 ;
        RECT 137.545 74.095 137.835 74.140 ;
        RECT 140.665 74.095 140.955 74.140 ;
        RECT 124.650 73.800 132.700 73.940 ;
        RECT 142.590 73.940 142.910 74.000 ;
        RECT 143.525 73.940 143.815 73.985 ;
        RECT 145.350 73.940 145.670 74.000 ;
        RECT 142.590 73.800 145.670 73.940 ;
        RECT 124.650 73.740 124.970 73.800 ;
        RECT 127.410 73.740 127.730 73.800 ;
        RECT 142.590 73.740 142.910 73.800 ;
        RECT 143.525 73.755 143.815 73.800 ;
        RECT 145.350 73.740 145.670 73.800 ;
        RECT 119.060 73.120 148.960 73.600 ;
        RECT 138.415 72.580 138.705 72.625 ;
        RECT 140.305 72.580 140.595 72.625 ;
        RECT 143.425 72.580 143.715 72.625 ;
        RECT 138.415 72.440 143.715 72.580 ;
        RECT 138.415 72.395 138.705 72.440 ;
        RECT 140.305 72.395 140.595 72.440 ;
        RECT 143.425 72.395 143.715 72.440 ;
        RECT 124.650 72.240 124.970 72.300 ;
        RECT 126.045 72.240 126.335 72.285 ;
        RECT 124.650 72.100 126.335 72.240 ;
        RECT 124.650 72.040 124.970 72.100 ;
        RECT 126.045 72.055 126.335 72.100 ;
        RECT 130.170 72.040 130.490 72.300 ;
        RECT 134.325 72.240 134.615 72.285 ;
        RECT 142.590 72.240 142.910 72.300 ;
        RECT 134.325 72.100 142.910 72.240 ;
        RECT 134.325 72.055 134.615 72.100 ;
        RECT 142.590 72.040 142.910 72.100 ;
        RECT 137.530 71.700 137.850 71.960 ;
        RECT 138.010 71.900 138.300 71.945 ;
        RECT 139.845 71.900 140.135 71.945 ;
        RECT 143.425 71.900 143.715 71.945 ;
        RECT 138.010 71.760 143.715 71.900 ;
        RECT 138.010 71.715 138.300 71.760 ;
        RECT 139.845 71.715 140.135 71.760 ;
        RECT 143.425 71.715 143.715 71.760 ;
        RECT 125.125 71.560 125.415 71.605 ;
        RECT 127.425 71.560 127.715 71.605 ;
        RECT 125.125 71.420 127.715 71.560 ;
        RECT 125.125 71.375 125.415 71.420 ;
        RECT 127.425 71.375 127.715 71.420 ;
        RECT 138.925 71.560 139.215 71.605 ;
        RECT 141.205 71.560 141.855 71.605 ;
        RECT 142.130 71.560 142.450 71.620 ;
        RECT 144.505 71.605 144.795 71.920 ;
        RECT 144.505 71.560 145.095 71.605 ;
        RECT 138.925 71.420 140.980 71.560 ;
        RECT 138.925 71.375 139.215 71.420 ;
        RECT 140.840 71.280 140.980 71.420 ;
        RECT 141.205 71.420 145.095 71.560 ;
        RECT 141.205 71.375 141.855 71.420 ;
        RECT 142.130 71.360 142.450 71.420 ;
        RECT 144.805 71.375 145.095 71.420 ;
        RECT 121.890 71.220 122.210 71.280 ;
        RECT 123.285 71.220 123.575 71.265 ;
        RECT 121.890 71.080 123.575 71.220 ;
        RECT 121.890 71.020 122.210 71.080 ;
        RECT 123.285 71.035 123.575 71.080 ;
        RECT 125.585 71.220 125.875 71.265 ;
        RECT 126.030 71.220 126.350 71.280 ;
        RECT 125.585 71.080 126.350 71.220 ;
        RECT 125.585 71.035 125.875 71.080 ;
        RECT 126.030 71.020 126.350 71.080 ;
        RECT 137.085 71.220 137.375 71.265 ;
        RECT 140.290 71.220 140.610 71.280 ;
        RECT 137.085 71.080 140.610 71.220 ;
        RECT 137.085 71.035 137.375 71.080 ;
        RECT 140.290 71.020 140.610 71.080 ;
        RECT 140.750 71.020 141.070 71.280 ;
        RECT 146.270 71.020 146.590 71.280 ;
        RECT 119.060 70.400 148.960 70.880 ;
        RECT 129.265 70.200 129.555 70.245 ;
        RECT 130.170 70.200 130.490 70.260 ;
        RECT 129.265 70.060 130.490 70.200 ;
        RECT 129.265 70.015 129.555 70.060 ;
        RECT 130.170 70.000 130.490 70.060 ;
        RECT 136.610 70.200 136.930 70.260 ;
        RECT 138.465 70.200 138.755 70.245 ;
        RECT 136.610 70.060 138.755 70.200 ;
        RECT 136.610 70.000 136.930 70.060 ;
        RECT 138.465 70.015 138.755 70.060 ;
        RECT 140.290 70.000 140.610 70.260 ;
        RECT 121.890 69.660 122.210 69.920 ;
        RECT 124.185 69.860 124.835 69.905 ;
        RECT 127.785 69.860 128.075 69.905 ;
        RECT 128.330 69.860 128.650 69.920 ;
        RECT 124.185 69.720 128.650 69.860 ;
        RECT 124.185 69.675 124.835 69.720 ;
        RECT 127.485 69.675 128.075 69.720 ;
        RECT 120.510 69.320 120.830 69.580 ;
        RECT 120.990 69.520 121.280 69.565 ;
        RECT 122.825 69.520 123.115 69.565 ;
        RECT 126.405 69.520 126.695 69.565 ;
        RECT 120.990 69.380 126.695 69.520 ;
        RECT 120.990 69.335 121.280 69.380 ;
        RECT 122.825 69.335 123.115 69.380 ;
        RECT 126.405 69.335 126.695 69.380 ;
        RECT 127.485 69.360 127.775 69.675 ;
        RECT 128.330 69.660 128.650 69.720 ;
        RECT 140.290 69.180 140.610 69.240 ;
        RECT 140.765 69.180 141.055 69.225 ;
        RECT 140.290 69.040 141.055 69.180 ;
        RECT 140.290 68.980 140.610 69.040 ;
        RECT 140.765 68.995 141.055 69.040 ;
        RECT 141.225 69.180 141.515 69.225 ;
        RECT 141.670 69.180 141.990 69.240 ;
        RECT 141.225 69.040 141.990 69.180 ;
        RECT 141.225 68.995 141.515 69.040 ;
        RECT 121.395 68.840 121.685 68.885 ;
        RECT 123.285 68.840 123.575 68.885 ;
        RECT 126.405 68.840 126.695 68.885 ;
        RECT 141.300 68.840 141.440 68.995 ;
        RECT 141.670 68.980 141.990 69.040 ;
        RECT 121.395 68.700 126.695 68.840 ;
        RECT 121.395 68.655 121.685 68.700 ;
        RECT 123.285 68.655 123.575 68.700 ;
        RECT 126.405 68.655 126.695 68.700 ;
        RECT 140.840 68.700 141.440 68.840 ;
        RECT 124.650 68.500 124.970 68.560 ;
        RECT 140.840 68.500 140.980 68.700 ;
        RECT 124.650 68.360 140.980 68.500 ;
        RECT 124.650 68.300 124.970 68.360 ;
        RECT 119.060 67.680 148.960 68.160 ;
        RECT 127.870 67.480 128.190 67.540 ;
        RECT 129.725 67.480 130.015 67.525 ;
        RECT 132.010 67.480 132.330 67.540 ;
        RECT 127.870 67.340 132.330 67.480 ;
        RECT 127.870 67.280 128.190 67.340 ;
        RECT 129.725 67.295 130.015 67.340 ;
        RECT 132.010 67.280 132.330 67.340 ;
        RECT 137.530 67.480 137.850 67.540 ;
        RECT 138.925 67.480 139.215 67.525 ;
        RECT 137.530 67.340 139.215 67.480 ;
        RECT 137.530 67.280 137.850 67.340 ;
        RECT 138.925 67.295 139.215 67.340 ;
        RECT 140.750 67.480 141.070 67.540 ;
        RECT 141.685 67.480 141.975 67.525 ;
        RECT 140.750 67.340 141.975 67.480 ;
        RECT 140.750 67.280 141.070 67.340 ;
        RECT 141.685 67.295 141.975 67.340 ;
        RECT 121.855 67.140 122.145 67.185 ;
        RECT 123.745 67.140 124.035 67.185 ;
        RECT 126.865 67.140 127.155 67.185 ;
        RECT 121.855 67.000 127.155 67.140 ;
        RECT 121.855 66.955 122.145 67.000 ;
        RECT 123.745 66.955 124.035 67.000 ;
        RECT 126.865 66.955 127.155 67.000 ;
        RECT 120.985 66.800 121.275 66.845 ;
        RECT 128.790 66.800 129.110 66.860 ;
        RECT 120.985 66.660 129.110 66.800 ;
        RECT 120.985 66.615 121.275 66.660 ;
        RECT 128.790 66.600 129.110 66.660 ;
        RECT 141.670 66.800 141.990 66.860 ;
        RECT 144.445 66.800 144.735 66.845 ;
        RECT 141.670 66.660 144.735 66.800 ;
        RECT 141.670 66.600 141.990 66.660 ;
        RECT 144.445 66.615 144.735 66.660 ;
        RECT 121.450 66.460 121.740 66.505 ;
        RECT 123.285 66.460 123.575 66.505 ;
        RECT 126.865 66.460 127.155 66.505 ;
        RECT 121.450 66.320 127.155 66.460 ;
        RECT 121.450 66.275 121.740 66.320 ;
        RECT 123.285 66.275 123.575 66.320 ;
        RECT 126.865 66.275 127.155 66.320 ;
        RECT 127.870 66.480 128.190 66.520 ;
        RECT 127.870 66.260 128.235 66.480 ;
        RECT 122.350 65.920 122.670 66.180 ;
        RECT 127.945 66.165 128.235 66.260 ;
        RECT 124.645 66.120 125.295 66.165 ;
        RECT 127.945 66.120 128.535 66.165 ;
        RECT 124.645 65.980 128.535 66.120 ;
        RECT 124.645 65.935 125.295 65.980 ;
        RECT 128.245 65.935 128.535 65.980 ;
        RECT 132.485 66.120 132.775 66.165 ;
        RECT 136.610 66.120 136.930 66.180 ;
        RECT 132.485 65.980 136.930 66.120 ;
        RECT 132.485 65.935 132.775 65.980 ;
        RECT 136.610 65.920 136.930 65.980 ;
        RECT 141.210 66.120 141.530 66.180 ;
        RECT 143.525 66.120 143.815 66.165 ;
        RECT 141.210 65.980 143.815 66.120 ;
        RECT 141.210 65.920 141.530 65.980 ;
        RECT 143.525 65.935 143.815 65.980 ;
        RECT 143.970 65.580 144.290 65.840 ;
        RECT 119.060 64.960 148.960 65.440 ;
        RECT 122.350 64.760 122.670 64.820 ;
        RECT 125.125 64.760 125.415 64.805 ;
        RECT 122.350 64.620 125.415 64.760 ;
        RECT 122.350 64.560 122.670 64.620 ;
        RECT 125.125 64.575 125.415 64.620 ;
        RECT 141.210 64.560 141.530 64.820 ;
        RECT 118.210 64.420 118.530 64.480 ;
        RECT 120.985 64.420 121.275 64.465 ;
        RECT 118.210 64.280 121.275 64.420 ;
        RECT 118.210 64.220 118.530 64.280 ;
        RECT 120.985 64.235 121.275 64.280 ;
        RECT 126.965 64.080 127.255 64.125 ;
        RECT 129.265 64.080 129.555 64.125 ;
        RECT 126.965 63.940 129.555 64.080 ;
        RECT 126.965 63.895 127.255 63.940 ;
        RECT 129.265 63.895 129.555 63.940 ;
        RECT 132.010 63.880 132.330 64.140 ;
        RECT 139.830 63.880 140.150 64.140 ;
        RECT 140.305 64.080 140.595 64.125 ;
        RECT 143.970 64.080 144.290 64.140 ;
        RECT 140.305 63.940 144.290 64.080 ;
        RECT 140.305 63.895 140.595 63.940 ;
        RECT 143.970 63.880 144.290 63.940 ;
        RECT 144.445 64.080 144.735 64.125 ;
        RECT 146.270 64.080 146.590 64.140 ;
        RECT 144.445 63.940 146.590 64.080 ;
        RECT 144.445 63.895 144.735 63.940 ;
        RECT 146.270 63.880 146.590 63.940 ;
        RECT 127.410 63.540 127.730 63.800 ;
        RECT 127.885 63.555 128.175 63.785 ;
        RECT 138.925 63.555 139.215 63.785 ;
        RECT 139.385 63.740 139.675 63.785 ;
        RECT 141.670 63.740 141.990 63.800 ;
        RECT 143.050 63.740 143.370 63.800 ;
        RECT 139.385 63.600 143.370 63.740 ;
        RECT 139.385 63.555 139.675 63.600 ;
        RECT 121.905 63.400 122.195 63.445 ;
        RECT 126.490 63.400 126.810 63.460 ;
        RECT 127.960 63.400 128.100 63.555 ;
        RECT 121.905 63.260 126.810 63.400 ;
        RECT 121.905 63.215 122.195 63.260 ;
        RECT 126.490 63.200 126.810 63.260 ;
        RECT 127.500 63.260 128.100 63.400 ;
        RECT 139.000 63.400 139.140 63.555 ;
        RECT 141.670 63.540 141.990 63.600 ;
        RECT 143.050 63.540 143.370 63.600 ;
        RECT 141.210 63.400 141.530 63.460 ;
        RECT 139.000 63.260 141.530 63.400 ;
        RECT 124.650 63.060 124.970 63.120 ;
        RECT 127.500 63.060 127.640 63.260 ;
        RECT 141.210 63.200 141.530 63.260 ;
        RECT 124.650 62.920 127.640 63.060 ;
        RECT 137.530 63.060 137.850 63.120 ;
        RECT 138.005 63.060 138.295 63.105 ;
        RECT 137.530 62.920 138.295 63.060 ;
        RECT 124.650 62.860 124.970 62.920 ;
        RECT 137.530 62.860 137.850 62.920 ;
        RECT 138.005 62.875 138.295 62.920 ;
        RECT 119.060 62.240 148.960 62.720 ;
        RECT 143.970 62.040 144.290 62.100 ;
        RECT 145.825 62.040 146.115 62.085 ;
        RECT 143.970 61.900 146.115 62.040 ;
        RECT 143.970 61.840 144.290 61.900 ;
        RECT 145.825 61.855 146.115 61.900 ;
        RECT 137.955 61.700 138.245 61.745 ;
        RECT 139.845 61.700 140.135 61.745 ;
        RECT 142.965 61.700 143.255 61.745 ;
        RECT 137.955 61.560 143.255 61.700 ;
        RECT 137.955 61.515 138.245 61.560 ;
        RECT 139.845 61.515 140.135 61.560 ;
        RECT 142.965 61.515 143.255 61.560 ;
        RECT 126.490 61.020 126.810 61.080 ;
        RECT 136.150 61.020 136.470 61.080 ;
        RECT 137.085 61.020 137.375 61.065 ;
        RECT 126.490 60.880 137.375 61.020 ;
        RECT 126.490 60.820 126.810 60.880 ;
        RECT 136.150 60.820 136.470 60.880 ;
        RECT 137.085 60.835 137.375 60.880 ;
        RECT 137.550 61.020 137.840 61.065 ;
        RECT 139.385 61.020 139.675 61.065 ;
        RECT 142.965 61.020 143.255 61.065 ;
        RECT 137.550 60.880 143.255 61.020 ;
        RECT 137.550 60.835 137.840 60.880 ;
        RECT 139.385 60.835 139.675 60.880 ;
        RECT 142.965 60.835 143.255 60.880 ;
        RECT 138.465 60.495 138.755 60.725 ;
        RECT 140.745 60.680 141.395 60.725 ;
        RECT 143.510 60.680 143.830 60.740 ;
        RECT 144.045 60.725 144.335 61.040 ;
        RECT 144.045 60.680 144.635 60.725 ;
        RECT 140.745 60.540 144.635 60.680 ;
        RECT 140.745 60.495 141.395 60.540 ;
        RECT 137.070 60.340 137.390 60.400 ;
        RECT 138.540 60.340 138.680 60.495 ;
        RECT 143.510 60.480 143.830 60.540 ;
        RECT 144.345 60.495 144.635 60.540 ;
        RECT 137.070 60.200 138.680 60.340 ;
        RECT 137.070 60.140 137.390 60.200 ;
        RECT 119.060 59.520 148.960 60.000 ;
        RECT 136.625 59.320 136.915 59.365 ;
        RECT 137.070 59.320 137.390 59.380 ;
        RECT 136.625 59.180 137.390 59.320 ;
        RECT 136.625 59.135 136.915 59.180 ;
        RECT 137.070 59.120 137.390 59.180 ;
        RECT 139.920 59.180 141.440 59.320 ;
        RECT 131.085 58.980 131.735 59.025 ;
        RECT 134.685 58.980 134.975 59.025 ;
        RECT 139.920 58.980 140.060 59.180 ;
        RECT 131.085 58.840 140.060 58.980 ;
        RECT 141.300 58.980 141.440 59.180 ;
        RECT 141.670 59.120 141.990 59.380 ;
        RECT 142.145 59.320 142.435 59.365 ;
        RECT 143.970 59.320 144.290 59.380 ;
        RECT 142.145 59.180 144.290 59.320 ;
        RECT 142.145 59.135 142.435 59.180 ;
        RECT 143.970 59.120 144.290 59.180 ;
        RECT 143.510 58.980 143.830 59.040 ;
        RECT 141.300 58.840 143.830 58.980 ;
        RECT 131.085 58.795 131.735 58.840 ;
        RECT 134.385 58.795 134.975 58.840 ;
        RECT 127.890 58.640 128.180 58.685 ;
        RECT 129.725 58.640 130.015 58.685 ;
        RECT 133.305 58.640 133.595 58.685 ;
        RECT 127.890 58.500 133.595 58.640 ;
        RECT 127.890 58.455 128.180 58.500 ;
        RECT 129.725 58.455 130.015 58.500 ;
        RECT 133.305 58.455 133.595 58.500 ;
        RECT 134.385 58.480 134.675 58.795 ;
        RECT 143.510 58.780 143.830 58.840 ;
        RECT 142.130 58.640 142.450 58.700 ;
        RECT 137.160 58.500 142.450 58.640 ;
        RECT 126.490 58.300 126.810 58.360 ;
        RECT 127.425 58.300 127.715 58.345 ;
        RECT 126.490 58.160 127.715 58.300 ;
        RECT 126.490 58.100 126.810 58.160 ;
        RECT 127.425 58.115 127.715 58.160 ;
        RECT 128.805 58.300 129.095 58.345 ;
        RECT 129.250 58.300 129.570 58.360 ;
        RECT 128.805 58.160 129.570 58.300 ;
        RECT 128.805 58.115 129.095 58.160 ;
        RECT 129.250 58.100 129.570 58.160 ;
        RECT 133.850 58.300 134.170 58.360 ;
        RECT 136.165 58.300 136.455 58.345 ;
        RECT 133.850 58.160 136.455 58.300 ;
        RECT 133.850 58.100 134.170 58.160 ;
        RECT 136.165 58.115 136.455 58.160 ;
        RECT 128.295 57.960 128.585 58.005 ;
        RECT 130.185 57.960 130.475 58.005 ;
        RECT 133.305 57.960 133.595 58.005 ;
        RECT 137.160 57.960 137.300 58.500 ;
        RECT 142.130 58.440 142.450 58.500 ;
        RECT 143.050 58.440 143.370 58.700 ;
        RECT 143.970 58.440 144.290 58.700 ;
        RECT 138.925 58.300 139.215 58.345 ;
        RECT 139.385 58.300 139.675 58.345 ;
        RECT 138.925 58.160 139.675 58.300 ;
        RECT 138.925 58.115 139.215 58.160 ;
        RECT 139.385 58.115 139.675 58.160 ;
        RECT 140.305 58.115 140.595 58.345 ;
        RECT 128.295 57.820 133.595 57.960 ;
        RECT 128.295 57.775 128.585 57.820 ;
        RECT 130.185 57.775 130.475 57.820 ;
        RECT 133.305 57.775 133.595 57.820 ;
        RECT 135.780 57.820 137.300 57.960 ;
        RECT 126.950 57.620 127.270 57.680 ;
        RECT 135.780 57.620 135.920 57.820 ;
        RECT 137.530 57.760 137.850 58.020 ;
        RECT 140.380 57.960 140.520 58.115 ;
        RECT 140.750 58.100 141.070 58.360 ;
        RECT 141.210 58.300 141.530 58.360 ;
        RECT 142.605 58.300 142.895 58.345 ;
        RECT 141.210 58.160 142.895 58.300 ;
        RECT 141.210 58.100 141.530 58.160 ;
        RECT 142.605 58.115 142.895 58.160 ;
        RECT 142.130 57.960 142.450 58.020 ;
        RECT 140.380 57.820 142.450 57.960 ;
        RECT 142.130 57.760 142.450 57.820 ;
        RECT 126.950 57.480 135.920 57.620 ;
        RECT 136.150 57.620 136.470 57.680 ;
        RECT 137.070 57.620 137.390 57.680 ;
        RECT 136.150 57.480 137.390 57.620 ;
        RECT 104.220 54.160 104.540 57.440 ;
        RECT 104.010 53.840 104.540 54.160 ;
        RECT 104.860 53.840 105.820 57.440 ;
        RECT 106.140 56.480 107.710 57.440 ;
        RECT 126.950 57.420 127.270 57.480 ;
        RECT 136.150 57.420 136.470 57.480 ;
        RECT 137.070 57.420 137.390 57.480 ;
        RECT 138.450 57.620 138.770 57.680 ;
        RECT 143.065 57.620 143.355 57.665 ;
        RECT 138.450 57.480 143.355 57.620 ;
        RECT 138.450 57.420 138.770 57.480 ;
        RECT 143.065 57.435 143.355 57.480 ;
        RECT 119.060 56.800 148.960 57.280 ;
        RECT 104.220 53.580 104.540 53.840 ;
        RECT 104.180 52.480 105.220 53.580 ;
        RECT 106.140 52.230 107.100 56.480 ;
        RECT 129.250 56.400 129.570 56.660 ;
        RECT 141.670 56.600 141.990 56.660 ;
        RECT 144.430 56.600 144.750 56.660 ;
        RECT 145.825 56.600 146.115 56.645 ;
        RECT 141.670 56.460 146.115 56.600 ;
        RECT 141.670 56.400 141.990 56.460 ;
        RECT 144.430 56.400 144.750 56.460 ;
        RECT 145.825 56.415 146.115 56.460 ;
        RECT 131.105 56.260 131.395 56.305 ;
        RECT 131.550 56.260 131.870 56.320 ;
        RECT 127.040 56.120 131.870 56.260 ;
        RECT 124.665 55.920 124.955 55.965 ;
        RECT 124.665 55.780 126.720 55.920 ;
        RECT 124.665 55.735 124.955 55.780 ;
        RECT 124.190 55.380 124.510 55.640 ;
        RECT 126.580 55.625 126.720 55.780 ;
        RECT 125.125 55.395 125.415 55.625 ;
        RECT 126.505 55.395 126.795 55.625 ;
        RECT 125.200 55.240 125.340 55.395 ;
        RECT 127.040 55.240 127.180 56.120 ;
        RECT 131.105 56.075 131.395 56.120 ;
        RECT 131.550 56.060 131.870 56.120 ;
        RECT 132.470 56.060 132.790 56.320 ;
        RECT 137.955 56.260 138.245 56.305 ;
        RECT 139.845 56.260 140.135 56.305 ;
        RECT 142.965 56.260 143.255 56.305 ;
        RECT 137.955 56.120 143.255 56.260 ;
        RECT 137.955 56.075 138.245 56.120 ;
        RECT 139.845 56.075 140.135 56.120 ;
        RECT 142.965 56.075 143.255 56.120 ;
        RECT 127.425 55.920 127.715 55.965 ;
        RECT 132.010 55.920 132.330 55.980 ;
        RECT 127.425 55.780 132.330 55.920 ;
        RECT 127.425 55.735 127.715 55.780 ;
        RECT 132.010 55.720 132.330 55.780 ;
        RECT 137.070 55.720 137.390 55.980 ;
        RECT 138.450 55.720 138.770 55.980 ;
        RECT 127.885 55.395 128.175 55.625 ;
        RECT 125.200 55.100 127.180 55.240 ;
        RECT 127.960 55.240 128.100 55.395 ;
        RECT 130.170 55.380 130.490 55.640 ;
        RECT 131.565 55.580 131.855 55.625 ;
        RECT 133.390 55.580 133.710 55.640 ;
        RECT 131.565 55.440 133.710 55.580 ;
        RECT 131.565 55.395 131.855 55.440 ;
        RECT 133.390 55.380 133.710 55.440 ;
        RECT 133.850 55.580 134.170 55.640 ;
        RECT 134.325 55.580 134.615 55.625 ;
        RECT 133.850 55.440 134.615 55.580 ;
        RECT 133.850 55.380 134.170 55.440 ;
        RECT 134.325 55.395 134.615 55.440 ;
        RECT 137.550 55.580 137.840 55.625 ;
        RECT 139.385 55.580 139.675 55.625 ;
        RECT 142.965 55.580 143.255 55.625 ;
        RECT 137.550 55.440 143.255 55.580 ;
        RECT 137.550 55.395 137.840 55.440 ;
        RECT 139.385 55.395 139.675 55.440 ;
        RECT 142.965 55.395 143.255 55.440 ;
        RECT 143.510 55.580 143.830 55.640 ;
        RECT 144.045 55.580 144.335 55.600 ;
        RECT 143.510 55.440 144.335 55.580 ;
        RECT 143.510 55.380 143.830 55.440 ;
        RECT 130.630 55.240 130.950 55.300 ;
        RECT 132.470 55.240 132.790 55.300 ;
        RECT 144.045 55.285 144.335 55.440 ;
        RECT 127.960 55.100 132.790 55.240 ;
        RECT 130.630 55.040 130.950 55.100 ;
        RECT 132.470 55.040 132.790 55.100 ;
        RECT 140.745 55.240 141.395 55.285 ;
        RECT 144.045 55.240 144.635 55.285 ;
        RECT 140.745 55.100 144.635 55.240 ;
        RECT 140.745 55.055 141.395 55.100 ;
        RECT 122.810 54.900 123.130 54.960 ;
        RECT 125.585 54.900 125.875 54.945 ;
        RECT 122.810 54.760 125.875 54.900 ;
        RECT 122.810 54.700 123.130 54.760 ;
        RECT 125.585 54.715 125.875 54.760 ;
        RECT 132.930 54.900 133.250 54.960 ;
        RECT 133.865 54.900 134.155 54.945 ;
        RECT 132.930 54.760 134.155 54.900 ;
        RECT 132.930 54.700 133.250 54.760 ;
        RECT 133.865 54.715 134.155 54.760 ;
        RECT 135.230 54.700 135.550 54.960 ;
        RECT 135.690 54.900 136.010 54.960 ;
        RECT 144.060 54.900 144.200 55.100 ;
        RECT 144.345 55.055 144.635 55.100 ;
        RECT 135.690 54.760 144.200 54.900 ;
        RECT 135.690 54.700 136.010 54.760 ;
        RECT 119.060 54.080 148.960 54.560 ;
        RECT 128.330 53.880 128.650 53.940 ;
        RECT 135.690 53.880 136.010 53.940 ;
        RECT 128.330 53.740 136.010 53.880 ;
        RECT 128.330 53.680 128.650 53.740 ;
        RECT 135.690 53.680 136.010 53.740 ;
        RECT 136.610 53.680 136.930 53.940 ;
        RECT 142.130 53.880 142.450 53.940 ;
        RECT 137.160 53.740 142.450 53.880 ;
        RECT 124.190 53.540 124.510 53.600 ;
        RECT 129.710 53.540 130.030 53.600 ;
        RECT 137.160 53.540 137.300 53.740 ;
        RECT 142.130 53.680 142.450 53.740 ;
        RECT 142.605 53.880 142.895 53.925 ;
        RECT 143.050 53.880 143.370 53.940 ;
        RECT 143.970 53.925 144.290 53.940 ;
        RECT 143.950 53.880 144.290 53.925 ;
        RECT 142.605 53.740 143.370 53.880 ;
        RECT 143.775 53.740 144.290 53.880 ;
        RECT 142.605 53.695 142.895 53.740 ;
        RECT 143.050 53.680 143.370 53.740 ;
        RECT 143.950 53.695 144.290 53.740 ;
        RECT 143.970 53.680 144.290 53.695 ;
        RECT 141.670 53.540 141.990 53.600 ;
        RECT 143.525 53.540 143.815 53.585 ;
        RECT 124.190 53.400 137.300 53.540 ;
        RECT 140.840 53.400 143.815 53.540 ;
        RECT 124.190 53.340 124.510 53.400 ;
        RECT 129.710 53.340 130.030 53.400 ;
        RECT 140.840 53.260 140.980 53.400 ;
        RECT 141.670 53.340 141.990 53.400 ;
        RECT 143.525 53.355 143.815 53.400 ;
        RECT 144.430 53.340 144.750 53.600 ;
        RECT 123.730 53.200 124.050 53.260 ;
        RECT 126.950 53.200 127.270 53.260 ;
        RECT 123.730 53.060 127.270 53.200 ;
        RECT 123.730 53.000 124.050 53.060 ;
        RECT 126.950 53.000 127.270 53.060 ;
        RECT 129.250 53.000 129.570 53.260 ;
        RECT 140.750 53.000 141.070 53.260 ;
        RECT 141.225 53.200 141.515 53.245 ;
        RECT 142.590 53.200 142.910 53.260 ;
        RECT 141.225 53.060 142.910 53.200 ;
        RECT 141.225 53.015 141.515 53.060 ;
        RECT 142.590 53.000 142.910 53.060 ;
        RECT 143.065 53.015 143.355 53.245 ;
        RECT 133.390 52.860 133.710 52.920 ;
        RECT 140.305 52.860 140.595 52.905 ;
        RECT 133.390 52.720 140.595 52.860 ;
        RECT 133.390 52.660 133.710 52.720 ;
        RECT 140.305 52.675 140.595 52.720 ;
        RECT 141.685 52.675 141.975 52.905 ;
        RECT 141.210 52.520 141.530 52.580 ;
        RECT 141.760 52.520 141.900 52.675 ;
        RECT 143.140 52.520 143.280 53.015 ;
        RECT 139.460 52.380 143.280 52.520 ;
        RECT 139.460 52.240 139.600 52.380 ;
        RECT 141.210 52.320 141.530 52.380 ;
        RECT 105.970 51.230 107.100 52.230 ;
        RECT 131.090 52.180 131.410 52.240 ;
        RECT 135.230 52.180 135.550 52.240 ;
        RECT 139.370 52.180 139.690 52.240 ;
        RECT 131.090 52.040 139.690 52.180 ;
        RECT 131.090 51.980 131.410 52.040 ;
        RECT 135.230 51.980 135.550 52.040 ;
        RECT 139.370 51.980 139.690 52.040 ;
        RECT 119.060 51.360 148.960 51.840 ;
        RECT 106.140 51.020 107.100 51.230 ;
        RECT 130.170 51.160 130.490 51.220 ;
        RECT 131.565 51.160 131.855 51.205 ;
        RECT 130.170 51.020 131.855 51.160 ;
        RECT 130.170 50.960 130.490 51.020 ;
        RECT 131.565 50.975 131.855 51.020 ;
        RECT 132.930 51.160 133.250 51.220 ;
        RECT 134.325 51.160 134.615 51.205 ;
        RECT 132.930 51.020 134.615 51.160 ;
        RECT 132.930 50.960 133.250 51.020 ;
        RECT 134.325 50.975 134.615 51.020 ;
        RECT 122.315 50.820 122.605 50.865 ;
        RECT 124.205 50.820 124.495 50.865 ;
        RECT 127.325 50.820 127.615 50.865 ;
        RECT 122.315 50.680 127.615 50.820 ;
        RECT 122.315 50.635 122.605 50.680 ;
        RECT 124.205 50.635 124.495 50.680 ;
        RECT 127.325 50.635 127.615 50.680 ;
        RECT 131.090 50.820 131.410 50.880 ;
        RECT 133.850 50.820 134.170 50.880 ;
        RECT 135.705 50.820 135.995 50.865 ;
        RECT 131.090 50.680 131.780 50.820 ;
        RECT 131.090 50.620 131.410 50.680 ;
        RECT 122.810 50.280 123.130 50.540 ;
        RECT 120.970 50.140 121.290 50.200 ;
        RECT 121.445 50.140 121.735 50.185 ;
        RECT 120.970 50.000 121.735 50.140 ;
        RECT 120.970 49.940 121.290 50.000 ;
        RECT 121.445 49.955 121.735 50.000 ;
        RECT 121.910 50.140 122.200 50.185 ;
        RECT 123.745 50.140 124.035 50.185 ;
        RECT 127.325 50.140 127.615 50.185 ;
        RECT 121.910 50.000 127.615 50.140 ;
        RECT 121.910 49.955 122.200 50.000 ;
        RECT 123.745 49.955 124.035 50.000 ;
        RECT 127.325 49.955 127.615 50.000 ;
        RECT 128.330 50.160 128.650 50.200 ;
        RECT 128.330 49.940 128.695 50.160 ;
        RECT 129.710 50.140 130.030 50.200 ;
        RECT 131.640 50.185 131.780 50.680 ;
        RECT 133.850 50.680 135.995 50.820 ;
        RECT 133.850 50.620 134.170 50.680 ;
        RECT 130.645 50.140 130.935 50.185 ;
        RECT 129.710 50.000 130.935 50.140 ;
        RECT 129.710 49.940 130.030 50.000 ;
        RECT 130.645 49.955 130.935 50.000 ;
        RECT 131.565 49.955 131.855 50.185 ;
        RECT 132.470 50.140 132.790 50.200 ;
        RECT 132.470 50.000 134.080 50.140 ;
        RECT 132.470 49.940 132.790 50.000 ;
        RECT 128.405 49.845 128.695 49.940 ;
        RECT 125.105 49.800 125.755 49.845 ;
        RECT 128.405 49.800 128.995 49.845 ;
        RECT 125.105 49.660 128.995 49.800 ;
        RECT 125.105 49.615 125.755 49.660 ;
        RECT 128.705 49.615 128.995 49.660 ;
        RECT 130.185 49.460 130.475 49.505 ;
        RECT 130.630 49.460 130.950 49.520 ;
        RECT 130.185 49.320 130.950 49.460 ;
        RECT 130.185 49.275 130.475 49.320 ;
        RECT 130.630 49.260 130.950 49.320 ;
        RECT 131.550 49.460 131.870 49.520 ;
        RECT 133.405 49.460 133.695 49.505 ;
        RECT 131.550 49.320 133.695 49.460 ;
        RECT 133.940 49.460 134.080 50.000 ;
        RECT 134.400 49.845 134.540 50.680 ;
        RECT 135.705 50.635 135.995 50.680 ;
        RECT 140.290 50.820 140.610 50.880 ;
        RECT 140.765 50.820 141.055 50.865 ;
        RECT 140.290 50.680 141.055 50.820 ;
        RECT 140.290 50.620 140.610 50.680 ;
        RECT 140.765 50.635 141.055 50.680 ;
        RECT 136.150 50.140 136.470 50.200 ;
        RECT 136.625 50.140 136.915 50.185 ;
        RECT 136.150 50.000 136.915 50.140 ;
        RECT 136.150 49.940 136.470 50.000 ;
        RECT 136.625 49.955 136.915 50.000 ;
        RECT 137.070 49.940 137.390 50.200 ;
        RECT 139.370 49.940 139.690 50.200 ;
        RECT 139.845 50.140 140.135 50.185 ;
        RECT 141.670 50.140 141.990 50.200 ;
        RECT 139.845 50.000 141.990 50.140 ;
        RECT 139.845 49.955 140.135 50.000 ;
        RECT 141.670 49.940 141.990 50.000 ;
        RECT 134.245 49.660 134.540 49.845 ;
        RECT 134.245 49.615 134.535 49.660 ;
        RECT 135.245 49.615 135.535 49.845 ;
        RECT 140.765 49.800 141.055 49.845 ;
        RECT 142.130 49.800 142.450 49.860 ;
        RECT 140.765 49.660 142.450 49.800 ;
        RECT 140.765 49.615 141.055 49.660 ;
        RECT 135.320 49.460 135.460 49.615 ;
        RECT 142.130 49.600 142.450 49.660 ;
        RECT 133.940 49.320 135.460 49.460 ;
        RECT 131.550 49.260 131.870 49.320 ;
        RECT 133.405 49.275 133.695 49.320 ;
        RECT 105.490 48.020 106.510 48.980 ;
        RECT 119.060 48.640 148.960 49.120 ;
        RECT 120.985 48.440 121.275 48.485 ;
        RECT 123.270 48.440 123.590 48.500 ;
        RECT 127.410 48.440 127.730 48.500 ;
        RECT 120.985 48.300 127.730 48.440 ;
        RECT 120.985 48.255 121.275 48.300 ;
        RECT 123.270 48.240 123.590 48.300 ;
        RECT 127.410 48.240 127.730 48.300 ;
        RECT 129.710 48.440 130.030 48.500 ;
        RECT 130.630 48.440 130.950 48.500 ;
        RECT 129.710 48.300 130.950 48.440 ;
        RECT 129.710 48.240 130.030 48.300 ;
        RECT 130.630 48.240 130.950 48.300 ;
        RECT 132.010 48.240 132.330 48.500 ;
        RECT 132.485 48.255 132.775 48.485 ;
        RECT 122.465 48.100 122.755 48.145 ;
        RECT 125.705 48.100 126.355 48.145 ;
        RECT 126.950 48.100 127.270 48.160 ;
        RECT 104.020 24.990 104.980 47.510 ;
        RECT 105.520 28.990 106.480 48.020 ;
        RECT 122.465 47.960 127.270 48.100 ;
        RECT 122.465 47.915 123.055 47.960 ;
        RECT 125.705 47.915 126.355 47.960 ;
        RECT 122.765 47.600 123.055 47.915 ;
        RECT 126.950 47.900 127.270 47.960 ;
        RECT 128.345 48.100 128.635 48.145 ;
        RECT 132.560 48.100 132.700 48.255 ;
        RECT 128.345 47.960 132.700 48.100 ;
        RECT 133.390 48.100 133.710 48.160 ;
        RECT 133.865 48.100 134.155 48.145 ;
        RECT 133.390 47.960 134.155 48.100 ;
        RECT 128.345 47.915 128.635 47.960 ;
        RECT 133.390 47.900 133.710 47.960 ;
        RECT 133.865 47.915 134.155 47.960 ;
        RECT 123.845 47.760 124.135 47.805 ;
        RECT 127.425 47.760 127.715 47.805 ;
        RECT 129.260 47.760 129.550 47.805 ;
        RECT 123.845 47.620 129.550 47.760 ;
        RECT 123.845 47.575 124.135 47.620 ;
        RECT 127.425 47.575 127.715 47.620 ;
        RECT 129.260 47.575 129.550 47.620 ;
        RECT 131.105 47.575 131.395 47.805 ;
        RECT 132.010 47.760 132.330 47.820 ;
        RECT 132.485 47.760 132.775 47.805 ;
        RECT 132.010 47.620 132.775 47.760 ;
        RECT 120.970 47.420 121.290 47.480 ;
        RECT 126.490 47.420 126.810 47.480 ;
        RECT 129.725 47.420 130.015 47.465 ;
        RECT 120.970 47.280 130.015 47.420 ;
        RECT 120.970 47.220 121.290 47.280 ;
        RECT 126.490 47.220 126.810 47.280 ;
        RECT 129.725 47.235 130.015 47.280 ;
        RECT 130.170 47.220 130.490 47.480 ;
        RECT 131.180 47.420 131.320 47.575 ;
        RECT 132.010 47.560 132.330 47.620 ;
        RECT 132.485 47.575 132.775 47.620 ;
        RECT 140.290 47.560 140.610 47.820 ;
        RECT 141.210 47.560 141.530 47.820 ;
        RECT 141.670 47.560 141.990 47.820 ;
        RECT 133.850 47.420 134.170 47.480 ;
        RECT 131.180 47.280 134.170 47.420 ;
        RECT 133.850 47.220 134.170 47.280 ;
        RECT 123.845 47.080 124.135 47.125 ;
        RECT 126.965 47.080 127.255 47.125 ;
        RECT 128.855 47.080 129.145 47.125 ;
        RECT 123.845 46.940 129.145 47.080 ;
        RECT 130.260 47.080 130.400 47.220 ;
        RECT 132.470 47.080 132.790 47.140 ;
        RECT 130.260 46.940 132.790 47.080 ;
        RECT 123.845 46.895 124.135 46.940 ;
        RECT 126.965 46.895 127.255 46.940 ;
        RECT 128.855 46.895 129.145 46.940 ;
        RECT 132.470 46.880 132.790 46.940 ;
        RECT 132.930 46.880 133.250 47.140 ;
        RECT 127.410 46.740 127.730 46.800 ;
        RECT 136.150 46.740 136.470 46.800 ;
        RECT 127.410 46.600 136.470 46.740 ;
        RECT 127.410 46.540 127.730 46.600 ;
        RECT 136.150 46.540 136.470 46.600 ;
        RECT 139.370 46.540 139.690 46.800 ;
        RECT 119.060 45.920 148.960 46.400 ;
        RECT 126.965 45.720 127.255 45.765 ;
        RECT 132.930 45.720 133.250 45.780 ;
        RECT 126.965 45.580 133.250 45.720 ;
        RECT 126.965 45.535 127.255 45.580 ;
        RECT 132.930 45.520 133.250 45.580 ;
        RECT 138.860 45.720 139.150 45.765 ;
        RECT 139.370 45.720 139.690 45.780 ;
        RECT 138.860 45.580 139.690 45.720 ;
        RECT 138.860 45.535 139.150 45.580 ;
        RECT 139.370 45.520 139.690 45.580 ;
        RECT 141.670 45.720 141.990 45.780 ;
        RECT 146.285 45.720 146.575 45.765 ;
        RECT 141.670 45.580 146.575 45.720 ;
        RECT 141.670 45.520 141.990 45.580 ;
        RECT 146.285 45.535 146.575 45.580 ;
        RECT 137.070 45.380 137.390 45.440 ;
        RECT 136.700 45.240 137.390 45.380 ;
        RECT 126.030 45.040 126.350 45.100 ;
        RECT 136.700 45.040 136.840 45.240 ;
        RECT 137.070 45.180 137.390 45.240 ;
        RECT 138.415 45.380 138.705 45.425 ;
        RECT 140.305 45.380 140.595 45.425 ;
        RECT 143.425 45.380 143.715 45.425 ;
        RECT 138.415 45.240 143.715 45.380 ;
        RECT 138.415 45.195 138.705 45.240 ;
        RECT 140.305 45.195 140.595 45.240 ;
        RECT 143.425 45.195 143.715 45.240 ;
        RECT 126.030 44.900 136.840 45.040 ;
        RECT 126.030 44.840 126.350 44.900 ;
        RECT 120.510 44.500 120.830 44.760 ;
        RECT 125.585 44.700 125.875 44.745 ;
        RECT 126.490 44.700 126.810 44.760 ;
        RECT 128.420 44.745 128.560 44.900 ;
        RECT 125.585 44.560 126.810 44.700 ;
        RECT 125.585 44.515 125.875 44.560 ;
        RECT 126.490 44.500 126.810 44.560 ;
        RECT 127.425 44.530 127.715 44.575 ;
        RECT 123.270 44.360 123.590 44.420 ;
        RECT 126.965 44.360 127.255 44.405 ;
        RECT 123.270 44.220 127.255 44.360 ;
        RECT 127.425 44.390 128.100 44.530 ;
        RECT 128.345 44.515 128.635 44.745 ;
        RECT 128.805 44.700 129.095 44.745 ;
        RECT 130.170 44.700 130.490 44.760 ;
        RECT 128.805 44.560 130.490 44.700 ;
        RECT 128.805 44.515 129.095 44.560 ;
        RECT 130.170 44.500 130.490 44.560 ;
        RECT 137.070 44.700 137.390 44.760 ;
        RECT 137.545 44.700 137.835 44.745 ;
        RECT 137.070 44.560 137.835 44.700 ;
        RECT 137.070 44.500 137.390 44.560 ;
        RECT 137.545 44.515 137.835 44.560 ;
        RECT 138.010 44.700 138.300 44.745 ;
        RECT 139.845 44.700 140.135 44.745 ;
        RECT 143.425 44.700 143.715 44.745 ;
        RECT 138.010 44.560 143.715 44.700 ;
        RECT 138.010 44.515 138.300 44.560 ;
        RECT 139.845 44.515 140.135 44.560 ;
        RECT 143.425 44.515 143.715 44.560 ;
        RECT 141.210 44.405 141.530 44.420 ;
        RECT 144.505 44.405 144.795 44.720 ;
        RECT 127.425 44.345 127.715 44.390 ;
        RECT 127.960 44.360 128.100 44.390 ;
        RECT 141.205 44.360 141.855 44.405 ;
        RECT 144.505 44.360 145.095 44.405 ;
        RECT 127.960 44.220 128.560 44.360 ;
        RECT 123.270 44.160 123.590 44.220 ;
        RECT 126.965 44.175 127.255 44.220 ;
        RECT 121.430 43.820 121.750 44.080 ;
        RECT 126.030 43.820 126.350 44.080 ;
        RECT 127.870 44.065 128.190 44.080 ;
        RECT 127.870 43.835 128.205 44.065 ;
        RECT 128.420 44.020 128.560 44.220 ;
        RECT 141.205 44.220 145.095 44.360 ;
        RECT 141.205 44.175 141.855 44.220 ;
        RECT 144.805 44.175 145.095 44.220 ;
        RECT 141.210 44.160 141.530 44.175 ;
        RECT 130.630 44.020 130.950 44.080 ;
        RECT 128.420 43.880 130.950 44.020 ;
        RECT 127.870 43.820 128.190 43.835 ;
        RECT 130.630 43.820 130.950 43.880 ;
        RECT 119.060 43.200 148.960 43.680 ;
        RECT 125.570 43.000 125.890 43.060 ;
        RECT 137.875 43.000 138.165 43.045 ;
        RECT 125.570 42.860 138.220 43.000 ;
        RECT 125.570 42.800 125.890 42.860 ;
        RECT 137.875 42.815 138.220 42.860 ;
        RECT 136.610 42.460 136.930 42.720 ;
        RECT 125.585 42.320 125.875 42.365 ;
        RECT 127.870 42.320 128.190 42.380 ;
        RECT 125.585 42.180 128.190 42.320 ;
        RECT 138.080 42.320 138.220 42.815 ;
        RECT 138.925 42.660 139.215 42.705 ;
        RECT 138.925 42.520 140.520 42.660 ;
        RECT 138.925 42.475 139.215 42.520 ;
        RECT 140.380 42.380 140.520 42.520 ;
        RECT 139.370 42.320 139.690 42.380 ;
        RECT 138.080 42.180 139.690 42.320 ;
        RECT 125.585 42.135 125.875 42.180 ;
        RECT 127.870 42.120 128.190 42.180 ;
        RECT 139.370 42.120 139.690 42.180 ;
        RECT 140.290 42.120 140.610 42.380 ;
        RECT 140.765 42.135 141.055 42.365 ;
        RECT 126.030 41.980 126.350 42.040 ;
        RECT 126.965 41.980 127.255 42.025 ;
        RECT 140.840 41.980 140.980 42.135 ;
        RECT 126.030 41.840 127.255 41.980 ;
        RECT 126.030 41.780 126.350 41.840 ;
        RECT 126.965 41.795 127.255 41.840 ;
        RECT 138.080 41.840 140.980 41.980 ;
        RECT 126.490 41.640 126.810 41.700 ;
        RECT 126.490 41.500 130.400 41.640 ;
        RECT 126.490 41.440 126.810 41.500 ;
        RECT 130.260 41.360 130.400 41.500 ;
        RECT 122.350 41.300 122.670 41.360 ;
        RECT 124.665 41.300 124.955 41.345 ;
        RECT 122.350 41.160 124.955 41.300 ;
        RECT 122.350 41.100 122.670 41.160 ;
        RECT 124.665 41.115 124.955 41.160 ;
        RECT 128.790 41.300 129.110 41.360 ;
        RECT 129.265 41.300 129.555 41.345 ;
        RECT 129.710 41.300 130.030 41.360 ;
        RECT 128.790 41.160 130.030 41.300 ;
        RECT 128.790 41.100 129.110 41.160 ;
        RECT 129.265 41.115 129.555 41.160 ;
        RECT 129.710 41.100 130.030 41.160 ;
        RECT 130.170 41.300 130.490 41.360 ;
        RECT 132.010 41.300 132.330 41.360 ;
        RECT 137.085 41.300 137.375 41.345 ;
        RECT 130.170 41.160 137.375 41.300 ;
        RECT 130.170 41.100 130.490 41.160 ;
        RECT 132.010 41.100 132.330 41.160 ;
        RECT 137.085 41.115 137.375 41.160 ;
        RECT 137.530 41.300 137.850 41.360 ;
        RECT 138.080 41.345 138.220 41.840 ;
        RECT 138.005 41.300 138.295 41.345 ;
        RECT 137.530 41.160 138.295 41.300 ;
        RECT 137.530 41.100 137.850 41.160 ;
        RECT 138.005 41.115 138.295 41.160 ;
        RECT 138.450 41.300 138.770 41.360 ;
        RECT 139.385 41.300 139.675 41.345 ;
        RECT 138.450 41.160 139.675 41.300 ;
        RECT 138.450 41.100 138.770 41.160 ;
        RECT 139.385 41.115 139.675 41.160 ;
        RECT 119.060 40.480 148.960 40.960 ;
        RECT 126.030 40.280 126.350 40.340 ;
        RECT 129.725 40.280 130.015 40.325 ;
        RECT 138.450 40.280 138.770 40.340 ;
        RECT 126.030 40.140 130.015 40.280 ;
        RECT 126.030 40.080 126.350 40.140 ;
        RECT 129.725 40.095 130.015 40.140 ;
        RECT 131.180 40.140 138.770 40.280 ;
        RECT 131.180 39.985 131.320 40.140 ;
        RECT 138.450 40.080 138.770 40.140 ;
        RECT 138.910 40.280 139.230 40.340 ;
        RECT 142.605 40.280 142.895 40.325 ;
        RECT 138.910 40.140 142.895 40.280 ;
        RECT 138.910 40.080 139.230 40.140 ;
        RECT 142.605 40.095 142.895 40.140 ;
        RECT 121.855 39.940 122.145 39.985 ;
        RECT 123.745 39.940 124.035 39.985 ;
        RECT 126.865 39.940 127.155 39.985 ;
        RECT 121.855 39.800 127.155 39.940 ;
        RECT 121.855 39.755 122.145 39.800 ;
        RECT 123.745 39.755 124.035 39.800 ;
        RECT 126.865 39.755 127.155 39.800 ;
        RECT 131.105 39.755 131.395 39.985 ;
        RECT 134.735 39.940 135.025 39.985 ;
        RECT 136.625 39.940 136.915 39.985 ;
        RECT 139.745 39.940 140.035 39.985 ;
        RECT 134.735 39.800 140.035 39.940 ;
        RECT 134.735 39.755 135.025 39.800 ;
        RECT 136.625 39.755 136.915 39.800 ;
        RECT 139.745 39.755 140.035 39.800 ;
        RECT 120.970 39.400 121.290 39.660 ;
        RECT 122.350 39.400 122.670 39.660 ;
        RECT 141.210 39.400 141.530 39.660 ;
        RECT 131.565 39.310 131.855 39.355 ;
        RECT 132.010 39.310 132.330 39.320 ;
        RECT 121.450 39.260 121.740 39.305 ;
        RECT 123.285 39.260 123.575 39.305 ;
        RECT 126.865 39.260 127.155 39.305 ;
        RECT 121.450 39.120 127.155 39.260 ;
        RECT 121.450 39.075 121.740 39.120 ;
        RECT 123.285 39.075 123.575 39.120 ;
        RECT 126.865 39.075 127.155 39.120 ;
        RECT 124.645 38.920 125.295 38.965 ;
        RECT 127.410 38.920 127.730 38.980 ;
        RECT 127.945 38.965 128.235 39.280 ;
        RECT 131.565 39.170 132.330 39.310 ;
        RECT 131.565 39.125 131.855 39.170 ;
        RECT 132.010 39.060 132.330 39.170 ;
        RECT 133.865 39.075 134.155 39.305 ;
        RECT 134.330 39.260 134.620 39.305 ;
        RECT 136.165 39.260 136.455 39.305 ;
        RECT 139.745 39.260 140.035 39.305 ;
        RECT 134.330 39.120 140.035 39.260 ;
        RECT 134.330 39.075 134.620 39.120 ;
        RECT 136.165 39.075 136.455 39.120 ;
        RECT 139.745 39.075 140.035 39.120 ;
        RECT 140.825 39.260 141.115 39.280 ;
        RECT 141.300 39.260 141.440 39.400 ;
        RECT 140.825 39.120 141.440 39.260 ;
        RECT 127.945 38.920 128.535 38.965 ;
        RECT 124.645 38.780 128.535 38.920 ;
        RECT 124.645 38.735 125.295 38.780 ;
        RECT 127.410 38.720 127.730 38.780 ;
        RECT 128.245 38.735 128.535 38.780 ;
        RECT 130.170 38.720 130.490 38.980 ;
        RECT 133.940 38.920 134.080 39.075 ;
        RECT 134.770 38.920 135.090 38.980 ;
        RECT 140.825 38.965 141.115 39.120 ;
        RECT 131.180 38.780 135.090 38.920 ;
        RECT 120.970 38.580 121.290 38.640 ;
        RECT 131.180 38.580 131.320 38.780 ;
        RECT 134.770 38.720 135.090 38.780 ;
        RECT 135.245 38.735 135.535 38.965 ;
        RECT 137.525 38.920 138.175 38.965 ;
        RECT 140.825 38.920 141.415 38.965 ;
        RECT 137.525 38.780 141.415 38.920 ;
        RECT 137.525 38.735 138.175 38.780 ;
        RECT 141.125 38.735 141.415 38.780 ;
        RECT 120.970 38.440 131.320 38.580 ;
        RECT 131.565 38.580 131.855 38.625 ;
        RECT 135.320 38.580 135.460 38.735 ;
        RECT 131.565 38.440 135.460 38.580 ;
        RECT 120.970 38.380 121.290 38.440 ;
        RECT 131.565 38.395 131.855 38.440 ;
        RECT 119.060 37.760 148.960 38.240 ;
        RECT 134.325 37.560 134.615 37.605 ;
        RECT 137.530 37.560 137.850 37.620 ;
        RECT 140.290 37.560 140.610 37.620 ;
        RECT 134.325 37.420 140.610 37.560 ;
        RECT 134.325 37.375 134.615 37.420 ;
        RECT 137.530 37.360 137.850 37.420 ;
        RECT 140.290 37.360 140.610 37.420 ;
        RECT 137.070 37.220 137.390 37.280 ;
        RECT 137.990 37.220 138.310 37.280 ;
        RECT 134.860 37.080 138.310 37.220 ;
        RECT 128.345 36.880 128.635 36.925 ;
        RECT 129.710 36.880 130.030 36.940 ;
        RECT 128.345 36.740 130.030 36.880 ;
        RECT 128.345 36.695 128.635 36.740 ;
        RECT 129.710 36.680 130.030 36.740 ;
        RECT 130.170 36.880 130.490 36.940 ;
        RECT 132.930 36.880 133.250 36.940 ;
        RECT 134.860 36.925 135.000 37.080 ;
        RECT 137.070 37.020 137.390 37.080 ;
        RECT 137.990 37.020 138.310 37.080 ;
        RECT 138.905 37.220 139.555 37.265 ;
        RECT 141.670 37.220 141.990 37.280 ;
        RECT 142.505 37.220 142.795 37.265 ;
        RECT 138.905 37.080 142.795 37.220 ;
        RECT 138.905 37.035 139.555 37.080 ;
        RECT 141.670 37.020 141.990 37.080 ;
        RECT 142.205 37.035 142.795 37.080 ;
        RECT 133.405 36.880 133.695 36.925 ;
        RECT 130.170 36.740 133.695 36.880 ;
        RECT 130.170 36.680 130.490 36.740 ;
        RECT 132.930 36.680 133.250 36.740 ;
        RECT 133.405 36.695 133.695 36.740 ;
        RECT 134.785 36.695 135.075 36.925 ;
        RECT 135.230 36.680 135.550 36.940 ;
        RECT 135.710 36.880 136.000 36.925 ;
        RECT 137.545 36.880 137.835 36.925 ;
        RECT 141.125 36.880 141.415 36.925 ;
        RECT 135.710 36.740 141.415 36.880 ;
        RECT 135.710 36.695 136.000 36.740 ;
        RECT 137.545 36.695 137.835 36.740 ;
        RECT 141.125 36.695 141.415 36.740 ;
        RECT 142.205 36.720 142.495 37.035 ;
        RECT 120.510 36.340 120.830 36.600 ;
        RECT 121.905 36.540 122.195 36.585 ;
        RECT 123.730 36.540 124.050 36.600 ;
        RECT 126.030 36.540 126.350 36.600 ;
        RECT 121.905 36.400 126.350 36.540 ;
        RECT 121.905 36.355 122.195 36.400 ;
        RECT 123.730 36.340 124.050 36.400 ;
        RECT 126.030 36.340 126.350 36.400 ;
        RECT 136.610 36.340 136.930 36.600 ;
        RECT 136.115 36.200 136.405 36.245 ;
        RECT 138.005 36.200 138.295 36.245 ;
        RECT 141.125 36.200 141.415 36.245 ;
        RECT 136.115 36.060 141.415 36.200 ;
        RECT 136.115 36.015 136.405 36.060 ;
        RECT 138.005 36.015 138.295 36.060 ;
        RECT 141.125 36.015 141.415 36.060 ;
        RECT 133.405 35.860 133.695 35.905 ;
        RECT 137.070 35.860 137.390 35.920 ;
        RECT 133.405 35.720 137.390 35.860 ;
        RECT 133.405 35.675 133.695 35.720 ;
        RECT 137.070 35.660 137.390 35.720 ;
        RECT 138.450 35.860 138.770 35.920 ;
        RECT 143.985 35.860 144.275 35.905 ;
        RECT 138.450 35.720 144.275 35.860 ;
        RECT 138.450 35.660 138.770 35.720 ;
        RECT 143.985 35.675 144.275 35.720 ;
        RECT 119.060 35.040 148.960 35.520 ;
        RECT 120.525 34.840 120.815 34.885 ;
        RECT 121.890 34.840 122.210 34.900 ;
        RECT 120.525 34.700 122.210 34.840 ;
        RECT 120.525 34.655 120.815 34.700 ;
        RECT 121.890 34.640 122.210 34.700 ;
        RECT 136.165 34.840 136.455 34.885 ;
        RECT 136.610 34.840 136.930 34.900 ;
        RECT 136.165 34.700 136.930 34.840 ;
        RECT 136.165 34.655 136.455 34.700 ;
        RECT 136.610 34.640 136.930 34.700 ;
        RECT 138.005 34.840 138.295 34.885 ;
        RECT 138.450 34.840 138.770 34.900 ;
        RECT 138.005 34.700 138.770 34.840 ;
        RECT 138.005 34.655 138.295 34.700 ;
        RECT 138.450 34.640 138.770 34.700 ;
        RECT 123.385 34.500 123.675 34.545 ;
        RECT 126.505 34.500 126.795 34.545 ;
        RECT 128.395 34.500 128.685 34.545 ;
        RECT 123.385 34.360 128.685 34.500 ;
        RECT 123.385 34.315 123.675 34.360 ;
        RECT 126.505 34.315 126.795 34.360 ;
        RECT 128.395 34.315 128.685 34.360 ;
        RECT 122.305 33.525 122.595 33.840 ;
        RECT 123.385 33.820 123.675 33.865 ;
        RECT 126.965 33.820 127.255 33.865 ;
        RECT 128.800 33.820 129.090 33.865 ;
        RECT 123.385 33.680 129.090 33.820 ;
        RECT 123.385 33.635 123.675 33.680 ;
        RECT 126.965 33.635 127.255 33.680 ;
        RECT 128.800 33.635 129.090 33.680 ;
        RECT 129.265 33.820 129.555 33.865 ;
        RECT 129.710 33.820 130.030 33.880 ;
        RECT 132.010 33.820 132.330 33.880 ;
        RECT 129.265 33.680 132.330 33.820 ;
        RECT 129.265 33.635 129.555 33.680 ;
        RECT 129.710 33.620 130.030 33.680 ;
        RECT 132.010 33.620 132.330 33.680 ;
        RECT 132.485 33.820 132.775 33.865 ;
        RECT 133.390 33.820 133.710 33.880 ;
        RECT 132.485 33.680 133.710 33.820 ;
        RECT 132.485 33.635 132.775 33.680 ;
        RECT 133.390 33.620 133.710 33.680 ;
        RECT 137.070 33.620 137.390 33.880 ;
        RECT 137.530 33.820 137.850 33.880 ;
        RECT 138.465 33.820 138.755 33.865 ;
        RECT 141.210 33.820 141.530 33.880 ;
        RECT 137.530 33.680 141.530 33.820 ;
        RECT 137.530 33.620 137.850 33.680 ;
        RECT 138.465 33.635 138.755 33.680 ;
        RECT 141.210 33.620 141.530 33.680 ;
        RECT 122.005 33.480 122.595 33.525 ;
        RECT 125.245 33.480 125.895 33.525 ;
        RECT 127.410 33.480 127.730 33.540 ;
        RECT 122.005 33.340 127.730 33.480 ;
        RECT 122.005 33.295 122.295 33.340 ;
        RECT 125.245 33.295 125.895 33.340 ;
        RECT 127.410 33.280 127.730 33.340 ;
        RECT 127.870 33.280 128.190 33.540 ;
        RECT 132.010 33.140 132.330 33.200 ;
        RECT 132.930 33.140 133.250 33.200 ;
        RECT 133.405 33.140 133.695 33.185 ;
        RECT 132.010 33.000 133.695 33.140 ;
        RECT 132.010 32.940 132.330 33.000 ;
        RECT 132.930 32.940 133.250 33.000 ;
        RECT 133.405 32.955 133.695 33.000 ;
        RECT 119.060 32.320 148.960 32.800 ;
        RECT 127.870 32.120 128.190 32.180 ;
        RECT 129.265 32.120 129.555 32.165 ;
        RECT 127.870 31.980 129.555 32.120 ;
        RECT 127.870 31.920 128.190 31.980 ;
        RECT 129.265 31.935 129.555 31.980 ;
        RECT 132.485 31.780 132.775 31.825 ;
        RECT 131.640 31.640 132.775 31.780 ;
        RECT 121.890 31.440 122.210 31.500 ;
        RECT 125.585 31.440 125.875 31.485 ;
        RECT 121.890 31.300 125.875 31.440 ;
        RECT 121.890 31.240 122.210 31.300 ;
        RECT 125.585 31.255 125.875 31.300 ;
        RECT 130.185 31.440 130.475 31.485 ;
        RECT 131.640 31.440 131.780 31.640 ;
        RECT 132.485 31.595 132.775 31.640 ;
        RECT 130.185 31.300 131.780 31.440 ;
        RECT 130.185 31.255 130.475 31.300 ;
        RECT 132.010 31.240 132.330 31.500 ;
        RECT 132.945 31.440 133.235 31.485 ;
        RECT 132.945 31.300 141.440 31.440 ;
        RECT 132.945 31.255 133.235 31.300 ;
        RECT 141.300 31.160 141.440 31.300 ;
        RECT 131.565 31.100 131.855 31.145 ;
        RECT 137.070 31.100 137.390 31.160 ;
        RECT 131.565 30.960 137.390 31.100 ;
        RECT 131.565 30.915 131.855 30.960 ;
        RECT 137.070 30.900 137.390 30.960 ;
        RECT 141.210 31.100 141.530 31.160 ;
        RECT 141.685 31.100 141.975 31.145 ;
        RECT 141.210 30.960 141.975 31.100 ;
        RECT 141.210 30.900 141.530 30.960 ;
        RECT 141.685 30.915 141.975 30.960 ;
        RECT 128.805 30.760 129.095 30.805 ;
        RECT 131.105 30.760 131.395 30.805 ;
        RECT 128.805 30.620 131.395 30.760 ;
        RECT 128.805 30.575 129.095 30.620 ;
        RECT 131.105 30.575 131.395 30.620 ;
        RECT 136.610 30.420 136.930 30.480 ;
        RECT 138.925 30.420 139.215 30.465 ;
        RECT 136.610 30.280 139.215 30.420 ;
        RECT 136.610 30.220 136.930 30.280 ;
        RECT 138.925 30.235 139.215 30.280 ;
        RECT 119.060 29.600 148.960 30.080 ;
        RECT 124.190 29.400 124.510 29.460 ;
        RECT 124.190 29.260 145.580 29.400 ;
        RECT 124.190 29.200 124.510 29.260 ;
        RECT 127.410 28.860 127.730 29.120 ;
        RECT 136.115 29.060 136.405 29.105 ;
        RECT 138.005 29.060 138.295 29.105 ;
        RECT 141.125 29.060 141.415 29.105 ;
        RECT 136.115 28.920 141.415 29.060 ;
        RECT 136.115 28.875 136.405 28.920 ;
        RECT 138.005 28.875 138.295 28.920 ;
        RECT 141.125 28.875 141.415 28.920 ;
        RECT 121.520 28.580 129.480 28.720 ;
        RECT 121.520 28.440 121.660 28.580 ;
        RECT 121.430 28.180 121.750 28.440 ;
        RECT 121.905 28.380 122.195 28.425 ;
        RECT 122.825 28.380 123.115 28.425 ;
        RECT 121.905 28.240 123.115 28.380 ;
        RECT 121.905 28.195 122.195 28.240 ;
        RECT 122.825 28.195 123.115 28.240 ;
        RECT 124.190 28.180 124.510 28.440 ;
        RECT 126.030 28.180 126.350 28.440 ;
        RECT 129.340 28.425 129.480 28.580 ;
        RECT 136.610 28.520 136.930 28.780 ;
        RECT 145.440 28.765 145.580 29.260 ;
        RECT 145.365 28.535 145.655 28.765 ;
        RECT 129.265 28.195 129.555 28.425 ;
        RECT 129.725 28.380 130.015 28.425 ;
        RECT 132.010 28.380 132.330 28.440 ;
        RECT 129.725 28.240 132.330 28.380 ;
        RECT 129.725 28.195 130.015 28.240 ;
        RECT 123.285 28.040 123.575 28.085 ;
        RECT 129.800 28.040 129.940 28.195 ;
        RECT 132.010 28.180 132.330 28.240 ;
        RECT 132.470 28.380 132.790 28.440 ;
        RECT 135.245 28.380 135.535 28.425 ;
        RECT 132.470 28.240 135.535 28.380 ;
        RECT 132.470 28.180 132.790 28.240 ;
        RECT 135.245 28.195 135.535 28.240 ;
        RECT 135.710 28.380 136.000 28.425 ;
        RECT 137.545 28.380 137.835 28.425 ;
        RECT 141.125 28.380 141.415 28.425 ;
        RECT 135.710 28.240 141.415 28.380 ;
        RECT 135.710 28.195 136.000 28.240 ;
        RECT 137.545 28.195 137.835 28.240 ;
        RECT 141.125 28.195 141.415 28.240 ;
        RECT 123.285 27.900 129.940 28.040 ;
        RECT 138.905 28.040 139.555 28.085 ;
        RECT 141.670 28.040 141.990 28.100 ;
        RECT 142.205 28.085 142.495 28.400 ;
        RECT 142.205 28.040 142.795 28.085 ;
        RECT 138.905 27.900 142.795 28.040 ;
        RECT 123.285 27.855 123.575 27.900 ;
        RECT 138.905 27.855 139.555 27.900 ;
        RECT 141.670 27.840 141.990 27.900 ;
        RECT 142.505 27.855 142.795 27.900 ;
        RECT 124.650 27.700 124.970 27.760 ;
        RECT 125.125 27.700 125.415 27.745 ;
        RECT 124.650 27.560 125.415 27.700 ;
        RECT 124.650 27.500 124.970 27.560 ;
        RECT 125.125 27.515 125.415 27.560 ;
        RECT 128.330 27.500 128.650 27.760 ;
        RECT 119.060 26.880 148.960 27.360 ;
        RECT 127.410 26.680 127.730 26.740 ;
        RECT 131.795 26.680 132.085 26.725 ;
        RECT 132.930 26.680 133.250 26.740 ;
        RECT 127.410 26.540 130.400 26.680 ;
        RECT 127.410 26.480 127.730 26.540 ;
        RECT 123.750 26.340 124.040 26.385 ;
        RECT 125.610 26.340 125.900 26.385 ;
        RECT 123.750 26.200 125.900 26.340 ;
        RECT 123.750 26.155 124.040 26.200 ;
        RECT 125.610 26.155 125.900 26.200 ;
        RECT 126.530 26.340 126.820 26.385 ;
        RECT 129.790 26.340 130.080 26.385 ;
        RECT 130.260 26.340 130.400 26.540 ;
        RECT 131.795 26.540 133.250 26.680 ;
        RECT 131.795 26.495 132.085 26.540 ;
        RECT 132.930 26.480 133.250 26.540 ;
        RECT 133.940 26.540 140.520 26.680 ;
        RECT 133.940 26.340 134.080 26.540 ;
        RECT 126.530 26.200 134.080 26.340 ;
        RECT 136.145 26.340 136.795 26.385 ;
        RECT 139.745 26.340 140.035 26.385 ;
        RECT 140.380 26.340 140.520 26.540 ;
        RECT 141.210 26.480 141.530 26.740 ;
        RECT 141.670 26.340 141.990 26.400 ;
        RECT 136.145 26.200 141.990 26.340 ;
        RECT 126.530 26.155 126.820 26.200 ;
        RECT 129.790 26.155 130.080 26.200 ;
        RECT 136.145 26.155 136.795 26.200 ;
        RECT 139.445 26.155 140.035 26.200 ;
        RECT 125.685 26.000 125.900 26.155 ;
        RECT 127.930 26.000 128.220 26.045 ;
        RECT 122.900 25.860 125.340 26.000 ;
        RECT 125.685 25.860 128.220 26.000 ;
        RECT 121.890 25.660 122.210 25.720 ;
        RECT 122.900 25.705 123.040 25.860 ;
        RECT 122.825 25.660 123.115 25.705 ;
        RECT 121.890 25.520 123.115 25.660 ;
        RECT 121.890 25.460 122.210 25.520 ;
        RECT 122.825 25.475 123.115 25.520 ;
        RECT 124.650 25.460 124.970 25.720 ;
        RECT 125.200 25.660 125.340 25.860 ;
        RECT 127.930 25.815 128.220 25.860 ;
        RECT 132.950 26.000 133.240 26.045 ;
        RECT 134.785 26.000 135.075 26.045 ;
        RECT 138.365 26.000 138.655 26.045 ;
        RECT 132.950 25.860 138.655 26.000 ;
        RECT 132.950 25.815 133.240 25.860 ;
        RECT 134.785 25.815 135.075 25.860 ;
        RECT 138.365 25.815 138.655 25.860 ;
        RECT 139.445 25.840 139.735 26.155 ;
        RECT 141.670 26.140 141.990 26.200 ;
        RECT 132.470 25.660 132.790 25.720 ;
        RECT 125.200 25.520 132.790 25.660 ;
        RECT 132.470 25.460 132.790 25.520 ;
        RECT 133.865 25.660 134.155 25.705 ;
        RECT 137.070 25.660 137.390 25.720 ;
        RECT 133.865 25.520 137.390 25.660 ;
        RECT 133.865 25.475 134.155 25.520 ;
        RECT 137.070 25.460 137.390 25.520 ;
        RECT 123.290 25.320 123.580 25.365 ;
        RECT 125.150 25.320 125.440 25.365 ;
        RECT 127.930 25.320 128.220 25.365 ;
        RECT 123.290 25.180 128.220 25.320 ;
        RECT 123.290 25.135 123.580 25.180 ;
        RECT 125.150 25.135 125.440 25.180 ;
        RECT 127.930 25.135 128.220 25.180 ;
        RECT 133.355 25.320 133.645 25.365 ;
        RECT 135.245 25.320 135.535 25.365 ;
        RECT 138.365 25.320 138.655 25.365 ;
        RECT 133.355 25.180 138.655 25.320 ;
        RECT 133.355 25.135 133.645 25.180 ;
        RECT 135.245 25.135 135.535 25.180 ;
        RECT 138.365 25.135 138.655 25.180 ;
        RECT 119.060 24.160 148.960 24.640 ;
        RECT 135.705 23.960 135.995 24.005 ;
        RECT 137.070 23.960 137.390 24.020 ;
        RECT 135.705 23.820 137.390 23.960 ;
        RECT 135.705 23.775 135.995 23.820 ;
        RECT 137.070 23.760 137.390 23.820 ;
        RECT 122.775 23.620 123.065 23.665 ;
        RECT 124.665 23.620 124.955 23.665 ;
        RECT 127.785 23.620 128.075 23.665 ;
        RECT 122.775 23.480 128.075 23.620 ;
        RECT 122.775 23.435 123.065 23.480 ;
        RECT 124.665 23.435 124.955 23.480 ;
        RECT 127.785 23.435 128.075 23.480 ;
        RECT 121.890 23.080 122.210 23.340 ;
        RECT 123.285 23.280 123.575 23.325 ;
        RECT 128.330 23.280 128.650 23.340 ;
        RECT 123.285 23.140 128.650 23.280 ;
        RECT 123.285 23.095 123.575 23.140 ;
        RECT 128.330 23.080 128.650 23.140 ;
        RECT 130.645 23.280 130.935 23.325 ;
        RECT 132.485 23.280 132.775 23.325 ;
        RECT 130.645 23.140 132.775 23.280 ;
        RECT 130.645 23.095 130.935 23.140 ;
        RECT 132.485 23.095 132.775 23.140 ;
        RECT 122.370 22.940 122.660 22.985 ;
        RECT 124.205 22.940 124.495 22.985 ;
        RECT 127.785 22.940 128.075 22.985 ;
        RECT 122.370 22.800 128.075 22.940 ;
        RECT 122.370 22.755 122.660 22.800 ;
        RECT 124.205 22.755 124.495 22.800 ;
        RECT 127.785 22.755 128.075 22.800 ;
        RECT 125.565 22.600 126.215 22.645 ;
        RECT 126.950 22.600 127.270 22.660 ;
        RECT 128.865 22.645 129.155 22.960 ;
        RECT 128.865 22.600 129.455 22.645 ;
        RECT 125.565 22.460 129.455 22.600 ;
        RECT 125.565 22.415 126.215 22.460 ;
        RECT 126.950 22.400 127.270 22.460 ;
        RECT 129.165 22.415 129.455 22.460 ;
        RECT 119.060 21.440 148.960 21.920 ;
        RECT 100.680 20.840 101.640 20.970 ;
        RECT 119.060 18.720 148.960 19.200 ;
        RECT 119.060 16.000 148.960 16.480 ;
      LAYER met2 ;
        RECT 130.530 109.820 130.810 109.855 ;
        RECT 130.520 109.550 130.820 109.820 ;
        RECT 137.200 109.770 137.500 109.780 ;
        RECT 130.520 108.630 130.870 109.550 ;
        RECT 137.165 109.490 137.535 109.770 ;
        RECT 43.600 108.170 43.880 108.205 ;
        RECT 43.590 107.870 45.460 108.170 ;
        RECT 43.600 107.835 43.880 107.870 ;
        RECT 130.570 101.520 130.870 108.630 ;
        RECT 133.090 109.015 133.390 109.020 ;
        RECT 133.090 108.980 133.470 109.015 ;
        RECT 133.090 108.030 133.480 108.980 ;
        RECT 137.200 108.950 137.500 109.490 ;
        RECT 133.090 103.310 133.390 108.030 ;
        RECT 137.200 106.970 137.540 108.950 ;
        RECT 159.320 108.640 160.660 108.860 ;
        RECT 145.060 107.760 160.660 108.640 ;
        RECT 145.080 107.585 146.000 107.760 ;
        RECT 159.320 107.560 160.660 107.760 ;
        RECT 133.100 103.275 133.380 103.310 ;
        RECT 137.240 102.250 137.540 106.970 ;
        RECT 142.400 106.350 143.280 106.690 ;
        RECT 145.100 106.350 145.980 106.690 ;
        RECT 142.400 105.150 143.280 105.490 ;
        RECT 145.100 105.150 145.980 105.490 ;
        RECT 138.150 104.990 138.430 105.025 ;
        RECT 137.250 102.215 137.530 102.250 ;
        RECT 5.500 57.180 7.500 101.000 ;
        RECT 5.500 55.180 7.560 57.180 ;
        RECT 5.500 47.000 7.500 55.180 ;
        RECT 8.000 53.495 10.000 101.000 ;
        RECT 138.140 100.690 138.440 104.990 ;
        RECT 142.400 104.350 143.280 104.690 ;
        RECT 145.100 104.350 145.980 104.690 ;
        RECT 142.400 102.750 143.280 103.090 ;
        RECT 145.100 102.750 145.980 103.090 ;
        RECT 142.400 101.950 143.280 102.290 ;
        RECT 42.935 93.480 47.550 94.520 ;
        RECT 79.140 94.480 80.100 94.510 ;
        RECT 79.140 93.520 81.980 94.480 ;
        RECT 142.400 94.455 143.280 100.960 ;
        RECT 79.140 93.490 80.100 93.520 ;
        RECT 81.020 93.475 81.980 93.520 ;
        RECT 144.270 92.940 144.570 100.920 ;
        RECT 145.100 100.350 145.980 100.690 ;
        RECT 144.280 92.905 144.560 92.940 ;
        RECT 118.230 91.660 118.510 91.695 ;
        RECT 118.220 90.800 118.520 91.660 ;
        RECT 121.300 90.890 121.580 90.925 ;
        RECT 118.090 87.370 118.650 90.800 ;
        RECT 121.290 90.590 122.790 90.890 ;
        RECT 121.300 90.555 121.580 90.590 ;
        RECT 122.230 87.370 122.790 90.590 ;
        RECT 126.370 87.370 126.930 90.800 ;
        RECT 130.510 87.370 131.070 90.800 ;
        RECT 118.090 87.230 120.280 87.370 ;
        RECT 118.090 86.800 118.650 87.230 ;
        RECT 120.140 83.890 120.280 87.230 ;
        RECT 122.230 87.230 123.500 87.370 ;
        RECT 122.230 86.800 122.790 87.230 ;
        RECT 123.360 83.890 123.500 87.230 ;
        RECT 125.200 87.230 126.930 87.370 ;
        RECT 125.200 83.890 125.340 87.230 ;
        RECT 126.370 86.800 126.930 87.230 ;
        RECT 129.340 87.230 131.070 87.370 ;
        RECT 129.340 83.890 129.480 87.230 ;
        RECT 130.510 86.800 131.070 87.230 ;
        RECT 134.650 87.370 135.210 90.800 ;
        RECT 138.790 88.520 139.350 90.800 ;
        RECT 138.440 88.510 140.250 88.520 ;
        RECT 138.440 88.230 140.285 88.510 ;
        RECT 142.930 88.450 143.490 90.800 ;
        RECT 142.930 88.440 145.090 88.450 ;
        RECT 138.440 88.220 140.250 88.230 ;
        RECT 138.790 87.370 139.350 88.220 ;
        RECT 142.930 88.160 145.125 88.440 ;
        RECT 142.930 88.150 145.090 88.160 ;
        RECT 142.930 87.370 143.490 88.150 ;
        RECT 147.070 87.720 147.630 90.800 ;
        RECT 147.070 87.370 147.660 87.720 ;
        RECT 134.650 87.230 137.300 87.370 ;
        RECT 134.650 86.800 135.210 87.230 ;
        RECT 134.440 84.055 136.320 84.425 ;
        RECT 120.080 83.570 120.340 83.890 ;
        RECT 123.300 83.570 123.560 83.890 ;
        RECT 125.140 83.570 125.400 83.890 ;
        RECT 129.280 83.570 129.540 83.890 ;
        RECT 129.280 82.890 129.540 83.210 ;
        RECT 126.060 82.550 126.320 82.870 ;
        RECT 126.520 82.550 126.780 82.870 ;
        RECT 126.120 82.190 126.260 82.550 ;
        RECT 126.060 81.870 126.320 82.190 ;
        RECT 121.460 80.170 121.720 80.490 ;
        RECT 121.000 79.150 121.260 79.470 ;
        RECT 121.060 78.645 121.200 79.150 ;
        RECT 120.990 78.275 121.270 78.645 ;
        RECT 48.310 75.000 102.980 75.010 ;
        RECT 48.310 74.050 103.530 75.000 ;
        RECT 120.540 74.730 120.800 75.050 ;
        RECT 102.470 74.000 103.530 74.050 ;
        RECT 66.720 73.470 67.680 73.500 ;
        RECT 42.490 72.510 67.680 73.470 ;
        RECT 66.720 72.480 67.680 72.510 ;
        RECT 28.500 72.430 29.500 72.460 ;
        RECT 82.500 72.430 83.500 72.460 ;
        RECT 16.470 71.430 29.500 72.430 ;
        RECT 28.500 71.400 29.500 71.430 ;
        RECT 29.990 71.510 30.950 71.540 ;
        RECT 49.020 71.510 49.980 71.540 ;
        RECT 29.990 70.550 49.980 71.510 ;
        RECT 70.470 71.430 83.500 72.430 ;
        RECT 82.500 71.400 83.500 71.430 ;
        RECT 29.990 70.520 30.950 70.550 ;
        RECT 49.020 70.520 49.980 70.550 ;
        RECT 61.990 70.190 63.010 71.010 ;
        RECT 64.040 70.190 64.360 70.220 ;
        RECT 19.790 69.050 42.510 70.010 ;
        RECT 57.010 69.870 64.360 70.190 ;
        RECT 64.040 69.840 64.360 69.870 ;
        RECT 66.720 69.470 67.680 69.500 ;
        RECT 59.090 68.510 67.680 69.470 ;
        RECT 73.790 69.050 96.510 70.010 ;
        RECT 120.600 69.610 120.740 74.730 ;
        RECT 120.540 69.290 120.800 69.610 ;
        RECT 66.720 68.480 67.680 68.510 ;
        RECT 32.720 66.810 33.680 66.840 ;
        RECT 38.140 66.830 39.100 66.860 ;
        RECT 22.490 65.850 33.680 66.810 ;
        RECT 35.490 65.870 40.910 66.830 ;
        RECT 32.720 65.820 33.680 65.850 ;
        RECT 38.140 65.840 39.100 65.870 ;
        RECT 19.720 65.470 20.680 65.500 ;
        RECT 19.720 64.510 36.510 65.470 ;
        RECT 48.310 65.250 49.330 66.210 ;
        RECT 61.990 66.190 63.010 67.010 ;
        RECT 86.720 66.810 87.680 66.840 ;
        RECT 92.140 66.830 93.100 66.860 ;
        RECT 64.040 66.190 64.360 66.220 ;
        RECT 57.010 65.870 64.360 66.190 ;
        RECT 64.040 65.840 64.360 65.870 ;
        RECT 76.490 65.850 87.680 66.810 ;
        RECT 89.490 65.870 94.910 66.830 ;
        RECT 86.720 65.820 87.680 65.850 ;
        RECT 92.140 65.840 93.100 65.870 ;
        RECT 66.720 65.470 67.680 65.500 ;
        RECT 48.340 65.180 49.300 65.250 ;
        RECT 59.090 64.510 67.680 65.470 ;
        RECT 19.720 64.480 20.680 64.510 ;
        RECT 66.720 64.480 67.680 64.510 ;
        RECT 73.720 65.470 74.680 65.500 ;
        RECT 73.720 64.510 90.510 65.470 ;
        RECT 108.140 65.360 108.440 65.370 ;
        RECT 108.105 65.080 108.475 65.360 ;
        RECT 108.140 64.780 108.440 65.080 ;
        RECT 95.370 64.755 115.200 64.780 ;
        RECT 73.720 64.480 74.680 64.510 ;
        RECT 95.370 63.605 115.220 64.755 ;
        RECT 118.230 64.675 118.510 65.045 ;
        RECT 118.300 64.510 118.440 64.675 ;
        RECT 118.240 64.190 118.500 64.510 ;
        RECT 95.370 63.580 115.200 63.605 ;
        RECT 51.000 63.505 55.530 63.530 ;
        RECT 25.720 62.830 26.680 62.860 ;
        RECT 32.140 62.830 33.100 62.860 ;
        RECT 25.720 61.870 33.100 62.830 ;
        RECT 25.720 61.840 26.680 61.870 ;
        RECT 32.140 61.840 33.100 61.870 ;
        RECT 34.190 61.850 39.510 62.810 ;
        RECT 50.980 62.555 55.530 63.505 ;
        RECT 51.000 62.530 55.530 62.555 ;
        RECT 61.990 62.190 63.010 63.010 ;
        RECT 79.720 62.830 80.680 62.860 ;
        RECT 86.140 62.830 87.100 62.860 ;
        RECT 64.040 62.190 64.360 62.220 ;
        RECT 57.010 61.870 64.360 62.190 ;
        RECT 64.040 61.840 64.360 61.870 ;
        RECT 79.720 61.870 87.100 62.830 ;
        RECT 79.720 61.840 80.680 61.870 ;
        RECT 86.140 61.840 87.100 61.870 ;
        RECT 88.190 61.850 93.510 62.810 ;
        RECT 62.020 61.470 62.980 61.500 ;
        RECT 66.720 61.470 67.680 61.500 ;
        RECT 30.790 59.950 35.210 60.910 ;
        RECT 59.090 60.510 67.680 61.470 ;
        RECT 62.020 60.480 62.980 60.510 ;
        RECT 66.720 60.480 67.680 60.510 ;
        RECT 48.340 60.190 48.660 60.220 ;
        RECT 43.190 59.870 48.660 60.190 ;
        RECT 84.790 59.950 89.210 60.910 ;
        RECT 48.340 59.840 48.660 59.870 ;
        RECT 95.490 59.520 98.850 60.480 ;
        RECT 32.140 59.010 33.100 59.040 ;
        RECT 38.140 59.010 39.100 59.040 ;
        RECT 86.140 59.010 87.100 59.040 ;
        RECT 92.140 59.010 93.100 59.040 ;
        RECT 16.490 58.050 22.010 59.010 ;
        RECT 22.490 58.050 33.100 59.010 ;
        RECT 34.190 58.050 39.100 59.010 ;
        RECT 61.990 58.190 63.010 59.010 ;
        RECT 64.040 58.190 64.360 58.220 ;
        RECT 32.140 58.020 33.100 58.050 ;
        RECT 38.140 58.020 39.100 58.050 ;
        RECT 57.010 57.870 64.360 58.190 ;
        RECT 70.490 58.050 76.010 59.010 ;
        RECT 76.490 58.050 87.100 59.010 ;
        RECT 88.190 58.050 93.100 59.010 ;
        RECT 86.140 58.020 87.100 58.050 ;
        RECT 92.140 58.020 93.100 58.050 ;
        RECT 64.040 57.840 64.360 57.870 ;
        RECT 52.720 57.470 53.680 57.500 ;
        RECT 66.720 57.470 67.680 57.500 ;
        RECT 38.490 56.450 40.910 57.410 ;
        RECT 45.090 56.510 57.510 57.470 ;
        RECT 59.090 56.510 67.680 57.470 ;
        RECT 106.720 57.440 107.680 57.470 ;
        RECT 52.720 56.480 53.680 56.510 ;
        RECT 66.720 56.480 67.680 56.510 ;
        RECT 92.490 56.450 94.910 57.410 ;
        RECT 99.090 56.480 107.680 57.440 ;
        RECT 106.720 56.450 107.680 56.480 ;
        RECT 61.620 55.255 62.950 55.280 ;
        RECT 25.140 55.010 26.100 55.040 ;
        RECT 27.020 55.010 27.980 55.040 ;
        RECT 19.720 54.830 20.680 54.860 ;
        RECT 19.720 53.870 22.010 54.830 ;
        RECT 25.140 54.050 27.980 55.010 ;
        RECT 61.620 54.805 62.970 55.255 ;
        RECT 79.140 55.010 80.100 55.040 ;
        RECT 81.020 55.010 81.980 55.040 ;
        RECT 73.720 54.830 74.680 54.860 ;
        RECT 61.620 54.780 62.950 54.805 ;
        RECT 50.040 54.190 50.360 54.220 ;
        RECT 64.040 54.190 64.360 54.220 ;
        RECT 25.140 54.020 26.100 54.050 ;
        RECT 27.020 54.020 27.980 54.050 ;
        RECT 41.810 53.870 50.360 54.190 ;
        RECT 57.010 53.870 64.360 54.190 ;
        RECT 19.720 53.840 20.680 53.870 ;
        RECT 50.040 53.840 50.360 53.870 ;
        RECT 64.040 53.840 64.360 53.870 ;
        RECT 73.720 53.870 76.010 54.830 ;
        RECT 79.140 54.050 81.980 55.010 ;
        RECT 104.040 54.160 104.360 54.190 ;
        RECT 79.140 54.020 80.100 54.050 ;
        RECT 81.020 54.020 81.980 54.050 ;
        RECT 73.720 53.840 74.680 53.870 ;
        RECT 97.010 53.840 104.360 54.160 ;
        RECT 104.040 53.810 104.360 53.840 ;
        RECT 35.500 53.550 36.500 53.560 ;
        RECT 8.000 51.495 10.210 53.495 ;
        RECT 35.470 52.510 105.250 53.550 ;
        RECT 35.500 52.500 36.500 52.510 ;
        RECT 22.500 52.230 23.500 52.260 ;
        RECT 76.500 52.230 77.500 52.260 ;
        RECT 106.000 52.230 107.000 52.260 ;
        RECT 8.000 51.030 10.000 51.495 ;
        RECT 16.470 51.230 107.200 52.230 ;
        RECT 22.500 51.200 23.500 51.230 ;
        RECT 76.500 51.200 77.500 51.230 ;
        RECT 106.000 51.200 107.000 51.230 ;
        RECT 8.000 49.030 14.030 51.030 ;
        RECT 53.500 50.530 54.500 50.575 ;
        RECT 29.970 49.530 54.500 50.530 ;
        RECT 61.470 49.530 85.030 50.530 ;
        RECT 120.530 49.715 120.810 50.085 ;
        RECT 121.000 49.910 121.260 50.230 ;
        RECT 49.970 49.500 51.030 49.530 ;
        RECT 5.470 45.000 7.530 47.000 ;
        RECT 5.500 6.000 7.500 45.000 ;
        RECT 8.000 18.000 10.000 49.030 ;
        RECT 105.520 48.980 106.480 49.010 ;
        RECT 74.990 48.020 106.480 48.980 ;
        RECT 105.520 47.990 106.480 48.020 ;
        RECT 20.990 46.520 105.010 47.480 ;
        RECT 120.600 44.790 120.740 49.715 ;
        RECT 121.060 47.510 121.200 49.910 ;
        RECT 121.000 47.190 121.260 47.510 ;
        RECT 120.540 44.470 120.800 44.790 ;
        RECT 121.060 39.690 121.200 47.190 ;
        RECT 121.520 45.370 121.660 80.170 ;
        RECT 125.600 79.830 125.860 80.150 ;
        RECT 121.920 79.150 122.180 79.470 ;
        RECT 121.980 75.390 122.120 79.150 ;
        RECT 121.920 75.070 122.180 75.390 ;
        RECT 124.680 73.710 124.940 74.030 ;
        RECT 124.740 72.330 124.880 73.710 ;
        RECT 124.680 72.010 124.940 72.330 ;
        RECT 121.920 70.990 122.180 71.310 ;
        RECT 121.980 69.950 122.120 70.990 ;
        RECT 121.920 69.630 122.180 69.950 ;
        RECT 124.740 68.590 124.880 72.010 ;
        RECT 124.680 68.270 124.940 68.590 ;
        RECT 122.380 65.890 122.640 66.210 ;
        RECT 122.440 64.850 122.580 65.890 ;
        RECT 122.380 64.530 122.640 64.850 ;
        RECT 124.740 63.150 124.880 68.270 ;
        RECT 124.680 62.830 124.940 63.150 ;
        RECT 124.220 55.350 124.480 55.670 ;
        RECT 122.840 54.670 123.100 54.990 ;
        RECT 122.900 50.570 123.040 54.670 ;
        RECT 124.280 53.630 124.420 55.350 ;
        RECT 124.220 53.310 124.480 53.630 ;
        RECT 123.760 52.970 124.020 53.290 ;
        RECT 122.840 50.250 123.100 50.570 ;
        RECT 123.300 48.210 123.560 48.530 ;
        RECT 121.520 45.230 122.120 45.370 ;
        RECT 121.460 43.790 121.720 44.110 ;
        RECT 43.990 38.520 52.510 39.480 ;
        RECT 121.000 39.370 121.260 39.690 ;
        RECT 73.470 38.270 76.665 39.270 ;
        RECT 121.060 38.670 121.200 39.370 ;
        RECT 121.000 38.350 121.260 38.670 ;
        RECT 58.860 37.250 59.820 37.280 ;
        RECT 66.520 37.250 67.480 37.280 ;
        RECT 75.420 37.250 76.380 37.280 ;
        RECT 18.970 35.500 49.060 36.500 ;
        RECT 58.860 36.290 76.380 37.250 ;
        RECT 58.860 36.260 59.820 36.290 ;
        RECT 66.520 36.260 67.480 36.290 ;
        RECT 75.420 36.260 76.380 36.290 ;
        RECT 94.280 36.440 95.240 36.470 ;
        RECT 94.280 35.480 100.010 36.440 ;
        RECT 120.540 36.310 120.800 36.630 ;
        RECT 120.600 35.805 120.740 36.310 ;
        RECT 94.280 35.450 95.240 35.480 ;
        RECT 120.530 35.435 120.810 35.805 ;
        RECT 37.000 34.000 38.000 34.030 ;
        RECT 37.000 33.000 41.530 34.000 ;
        RECT 37.000 32.970 38.000 33.000 ;
        RECT 40.230 31.120 45.010 32.080 ;
        RECT 52.490 32.020 66.190 32.980 ;
        RECT 79.590 32.820 82.330 33.780 ;
        RECT 94.280 32.440 95.240 32.470 ;
        RECT 94.280 31.480 100.010 32.440 ;
        RECT 94.280 31.450 95.240 31.480 ;
        RECT 82.970 30.280 84.030 30.500 ;
        RECT 42.280 29.800 43.240 29.830 ;
        RECT 52.520 29.800 53.480 29.830 ;
        RECT 42.280 28.840 53.480 29.800 ;
        RECT 62.020 29.320 87.610 30.280 ;
        RECT 100.970 29.980 106.000 30.000 ;
        RECT 100.970 29.020 106.510 29.980 ;
        RECT 100.970 29.000 106.000 29.020 ;
        RECT 42.280 28.810 43.240 28.840 ;
        RECT 52.520 28.810 53.480 28.840 ;
        RECT 121.520 28.470 121.660 43.790 ;
        RECT 121.980 34.930 122.120 45.230 ;
        RECT 123.360 44.450 123.500 48.210 ;
        RECT 123.300 44.130 123.560 44.450 ;
        RECT 122.380 41.070 122.640 41.390 ;
        RECT 122.440 39.690 122.580 41.070 ;
        RECT 122.380 39.370 122.640 39.690 ;
        RECT 123.820 36.630 123.960 52.970 ;
        RECT 124.740 45.370 124.880 62.830 ;
        RECT 124.280 45.230 124.880 45.370 ;
        RECT 123.760 36.310 124.020 36.630 ;
        RECT 121.920 34.610 122.180 34.930 ;
        RECT 121.980 31.530 122.120 34.610 ;
        RECT 121.920 31.210 122.180 31.530 ;
        RECT 124.280 29.490 124.420 45.230 ;
        RECT 125.660 43.090 125.800 79.830 ;
        RECT 126.580 78.450 126.720 82.550 ;
        RECT 127.900 81.870 128.160 82.190 ;
        RECT 128.360 81.870 128.620 82.190 ;
        RECT 127.440 79.490 127.700 79.810 ;
        RECT 126.520 78.130 126.780 78.450 ;
        RECT 127.500 77.770 127.640 79.490 ;
        RECT 127.440 77.450 127.700 77.770 ;
        RECT 127.500 74.030 127.640 77.450 ;
        RECT 127.440 73.710 127.700 74.030 ;
        RECT 126.060 70.990 126.320 71.310 ;
        RECT 126.120 45.130 126.260 70.990 ;
        RECT 127.960 67.570 128.100 81.870 ;
        RECT 128.420 81.170 128.560 81.870 ;
        RECT 128.360 80.850 128.620 81.170 ;
        RECT 128.360 76.430 128.620 76.750 ;
        RECT 128.420 75.390 128.560 76.430 ;
        RECT 128.360 75.070 128.620 75.390 ;
        RECT 128.420 69.950 128.560 75.070 ;
        RECT 129.340 74.710 129.480 82.890 ;
        RECT 130.200 82.210 130.460 82.530 ;
        RECT 129.740 76.770 130.000 77.090 ;
        RECT 129.280 74.390 129.540 74.710 ;
        RECT 129.800 74.370 129.940 76.770 ;
        RECT 129.740 74.050 130.000 74.370 ;
        RECT 130.260 72.330 130.400 82.210 ;
        RECT 132.500 81.870 132.760 82.190 ;
        RECT 136.640 81.870 136.900 82.190 ;
        RECT 131.120 79.830 131.380 80.150 ;
        RECT 131.180 78.450 131.320 79.830 ;
        RECT 131.580 79.150 131.840 79.470 ;
        RECT 131.120 78.130 131.380 78.450 ;
        RECT 131.640 77.430 131.780 79.150 ;
        RECT 131.580 77.110 131.840 77.430 ;
        RECT 131.640 75.730 131.780 77.110 ;
        RECT 131.580 75.410 131.840 75.730 ;
        RECT 132.560 75.390 132.700 81.870 ;
        RECT 132.960 80.510 133.220 80.830 ;
        RECT 133.020 76.750 133.160 80.510 ;
        RECT 134.440 78.615 136.320 78.985 ;
        RECT 136.700 77.090 136.840 81.870 ;
        RECT 137.160 80.150 137.300 87.230 ;
        RECT 138.790 87.230 140.520 87.370 ;
        RECT 138.790 86.800 139.350 87.230 ;
        RECT 140.380 83.890 140.520 87.230 ;
        RECT 142.930 87.230 144.200 87.370 ;
        RECT 142.930 86.800 143.490 87.230 ;
        RECT 140.320 83.570 140.580 83.890 ;
        RECT 137.560 82.550 137.820 82.870 ;
        RECT 137.620 81.170 137.760 82.550 ;
        RECT 142.620 81.870 142.880 82.190 ;
        RECT 138.140 81.335 140.020 81.705 ;
        RECT 142.680 81.170 142.820 81.870 ;
        RECT 137.560 80.850 137.820 81.170 ;
        RECT 142.620 80.850 142.880 81.170 ;
        RECT 137.100 79.830 137.360 80.150 ;
        RECT 143.080 79.830 143.340 80.150 ;
        RECT 141.700 79.490 141.960 79.810 ;
        RECT 140.780 79.150 141.040 79.470 ;
        RECT 140.840 77.770 140.980 79.150 ;
        RECT 140.780 77.450 141.040 77.770 ;
        RECT 137.100 77.110 137.360 77.430 ;
        RECT 136.640 76.770 136.900 77.090 ;
        RECT 132.960 76.430 133.220 76.750 ;
        RECT 133.880 76.430 134.140 76.750 ;
        RECT 132.500 75.070 132.760 75.390 ;
        RECT 132.040 74.390 132.300 74.710 ;
        RECT 130.200 72.010 130.460 72.330 ;
        RECT 130.260 70.290 130.400 72.010 ;
        RECT 130.200 69.970 130.460 70.290 ;
        RECT 128.360 69.630 128.620 69.950 ;
        RECT 127.900 67.250 128.160 67.570 ;
        RECT 127.900 66.290 128.160 66.550 ;
        RECT 128.420 66.290 128.560 69.630 ;
        RECT 132.100 68.330 132.240 74.390 ;
        RECT 132.100 68.190 132.700 68.330 ;
        RECT 132.040 67.250 132.300 67.570 ;
        RECT 128.820 66.570 129.080 66.890 ;
        RECT 127.900 66.230 128.560 66.290 ;
        RECT 127.960 66.150 128.560 66.230 ;
        RECT 127.440 63.510 127.700 63.830 ;
        RECT 126.520 63.170 126.780 63.490 ;
        RECT 126.580 61.110 126.720 63.170 ;
        RECT 126.520 60.790 126.780 61.110 ;
        RECT 126.580 58.390 126.720 60.790 ;
        RECT 126.520 58.070 126.780 58.390 ;
        RECT 126.580 47.510 126.720 58.070 ;
        RECT 126.980 57.390 127.240 57.710 ;
        RECT 127.040 53.290 127.180 57.390 ;
        RECT 126.980 52.970 127.240 53.290 ;
        RECT 127.500 48.530 127.640 63.510 ;
        RECT 128.420 53.970 128.560 66.150 ;
        RECT 128.360 53.650 128.620 53.970 ;
        RECT 128.420 50.230 128.560 53.650 ;
        RECT 128.360 49.910 128.620 50.230 ;
        RECT 127.440 48.210 127.700 48.530 ;
        RECT 126.980 47.870 127.240 48.190 ;
        RECT 126.520 47.190 126.780 47.510 ;
        RECT 127.040 45.370 127.180 47.870 ;
        RECT 127.500 46.830 127.640 48.210 ;
        RECT 127.440 46.510 127.700 46.830 ;
        RECT 127.040 45.230 127.640 45.370 ;
        RECT 126.060 44.810 126.320 45.130 ;
        RECT 126.120 44.110 126.260 44.810 ;
        RECT 126.520 44.470 126.780 44.790 ;
        RECT 126.060 43.790 126.320 44.110 ;
        RECT 125.600 42.770 125.860 43.090 ;
        RECT 126.120 42.070 126.260 43.790 ;
        RECT 126.060 41.750 126.320 42.070 ;
        RECT 126.120 40.370 126.260 41.750 ;
        RECT 126.580 41.730 126.720 44.470 ;
        RECT 126.520 41.410 126.780 41.730 ;
        RECT 126.060 40.050 126.320 40.370 ;
        RECT 127.500 39.010 127.640 45.230 ;
        RECT 127.900 43.790 128.160 44.110 ;
        RECT 127.960 42.410 128.100 43.790 ;
        RECT 127.900 42.090 128.160 42.410 ;
        RECT 128.880 41.390 129.020 66.570 ;
        RECT 132.100 64.170 132.240 67.250 ;
        RECT 132.040 63.850 132.300 64.170 ;
        RECT 129.280 58.070 129.540 58.390 ;
        RECT 129.340 56.690 129.480 58.070 ;
        RECT 129.280 56.370 129.540 56.690 ;
        RECT 132.560 56.350 132.700 68.190 ;
        RECT 133.940 58.390 134.080 76.430 ;
        RECT 137.160 75.810 137.300 77.110 ;
        RECT 138.140 75.895 140.020 76.265 ;
        RECT 137.160 75.670 137.760 75.810 ;
        RECT 137.620 75.390 137.760 75.670 ;
        RECT 137.560 75.070 137.820 75.390 ;
        RECT 136.640 74.390 136.900 74.710 ;
        RECT 134.440 73.175 136.320 73.545 ;
        RECT 136.700 70.290 136.840 74.390 ;
        RECT 137.620 71.990 137.760 75.070 ;
        RECT 137.560 71.670 137.820 71.990 ;
        RECT 136.640 69.970 136.900 70.290 ;
        RECT 134.440 67.735 136.320 68.105 ;
        RECT 137.620 67.570 137.760 71.670 ;
        RECT 140.320 70.990 140.580 71.310 ;
        RECT 140.780 70.990 141.040 71.310 ;
        RECT 138.140 70.455 140.020 70.825 ;
        RECT 140.380 70.290 140.520 70.990 ;
        RECT 140.320 69.970 140.580 70.290 ;
        RECT 140.320 68.950 140.580 69.270 ;
        RECT 137.560 67.250 137.820 67.570 ;
        RECT 136.640 65.890 136.900 66.210 ;
        RECT 134.440 62.295 136.320 62.665 ;
        RECT 136.180 60.790 136.440 61.110 ;
        RECT 133.880 58.130 134.140 58.390 ;
        RECT 133.480 58.070 134.140 58.130 ;
        RECT 133.480 57.990 134.080 58.070 ;
        RECT 131.580 56.030 131.840 56.350 ;
        RECT 132.500 56.030 132.760 56.350 ;
        RECT 130.200 55.350 130.460 55.670 ;
        RECT 129.740 53.310 130.000 53.630 ;
        RECT 129.280 52.970 129.540 53.290 ;
        RECT 128.820 41.070 129.080 41.390 ;
        RECT 127.440 38.690 127.700 39.010 ;
        RECT 126.060 36.310 126.320 36.630 ;
        RECT 124.220 29.170 124.480 29.490 ;
        RECT 124.280 28.470 124.420 29.170 ;
        RECT 126.120 28.470 126.260 36.310 ;
        RECT 127.500 33.570 127.640 38.690 ;
        RECT 127.440 33.250 127.700 33.570 ;
        RECT 127.900 33.250 128.160 33.570 ;
        RECT 127.500 29.150 127.640 33.250 ;
        RECT 127.960 32.210 128.100 33.250 ;
        RECT 127.900 31.890 128.160 32.210 ;
        RECT 127.440 28.830 127.700 29.150 ;
        RECT 94.280 28.440 95.240 28.470 ;
        RECT 38.970 27.000 92.030 28.000 ;
        RECT 94.280 27.480 100.010 28.440 ;
        RECT 121.460 28.150 121.720 28.470 ;
        RECT 124.220 28.150 124.480 28.470 ;
        RECT 126.060 28.150 126.320 28.470 ;
        RECT 94.280 27.450 95.240 27.480 ;
        RECT 124.680 27.470 124.940 27.790 ;
        RECT 49.000 26.955 50.000 27.000 ;
        RECT 69.660 26.180 70.620 26.210 ;
        RECT 84.020 26.180 84.980 26.210 ;
        RECT 42.250 25.800 43.270 25.980 ;
        RECT 49.970 25.800 51.030 26.000 ;
        RECT 20.975 24.840 58.510 25.800 ;
        RECT 69.660 25.220 87.610 26.180 ;
        RECT 100.970 25.980 105.000 26.000 ;
        RECT 69.660 25.190 70.620 25.220 ;
        RECT 84.020 25.190 84.980 25.220 ;
        RECT 100.970 25.020 105.010 25.980 ;
        RECT 124.740 25.750 124.880 27.470 ;
        RECT 127.500 26.770 127.640 28.830 ;
        RECT 128.360 27.470 128.620 27.790 ;
        RECT 127.440 26.450 127.700 26.770 ;
        RECT 121.920 25.430 122.180 25.750 ;
        RECT 124.680 25.430 124.940 25.750 ;
        RECT 100.970 25.000 105.000 25.020 ;
        RECT 94.280 24.440 95.240 24.470 ;
        RECT 73.500 24.000 74.500 24.030 ;
        RECT 89.000 24.000 90.000 24.030 ;
        RECT 36.970 23.000 41.530 24.000 ;
        RECT 45.970 23.000 90.000 24.000 ;
        RECT 94.280 23.480 100.010 24.440 ;
        RECT 94.280 23.450 95.240 23.480 ;
        RECT 121.980 23.370 122.120 25.430 ;
        RECT 121.920 23.050 122.180 23.370 ;
        RECT 73.500 22.970 74.500 23.000 ;
        RECT 89.000 22.970 90.000 23.000 ;
        RECT 127.500 22.770 127.640 26.450 ;
        RECT 128.420 23.370 128.560 27.470 ;
        RECT 128.360 23.050 128.620 23.370 ;
        RECT 127.040 22.690 127.640 22.770 ;
        RECT 126.980 22.630 127.640 22.690 ;
        RECT 126.980 22.370 127.240 22.630 ;
        RECT 88.970 21.000 98.530 22.000 ;
        RECT 100.970 21.000 103.530 22.000 ;
        RECT 129.340 21.525 129.480 52.970 ;
        RECT 129.800 50.230 129.940 53.310 ;
        RECT 130.260 51.250 130.400 55.350 ;
        RECT 130.660 55.010 130.920 55.330 ;
        RECT 130.200 50.930 130.460 51.250 ;
        RECT 129.740 49.910 130.000 50.230 ;
        RECT 129.800 48.530 129.940 49.910 ;
        RECT 130.720 49.550 130.860 55.010 ;
        RECT 131.120 51.950 131.380 52.270 ;
        RECT 131.180 50.910 131.320 51.950 ;
        RECT 131.120 50.590 131.380 50.910 ;
        RECT 131.640 49.550 131.780 56.030 ;
        RECT 132.040 55.690 132.300 56.010 ;
        RECT 130.660 49.230 130.920 49.550 ;
        RECT 131.580 49.230 131.840 49.550 ;
        RECT 132.100 48.530 132.240 55.690 ;
        RECT 132.560 55.330 132.700 56.030 ;
        RECT 133.480 55.670 133.620 57.990 ;
        RECT 136.240 57.710 136.380 60.790 ;
        RECT 136.180 57.390 136.440 57.710 ;
        RECT 134.440 56.855 136.320 57.225 ;
        RECT 133.420 55.350 133.680 55.670 ;
        RECT 133.880 55.350 134.140 55.670 ;
        RECT 132.500 55.010 132.760 55.330 ;
        RECT 132.560 50.230 132.700 55.010 ;
        RECT 132.960 54.670 133.220 54.990 ;
        RECT 133.020 51.250 133.160 54.670 ;
        RECT 133.420 52.630 133.680 52.950 ;
        RECT 132.960 50.930 133.220 51.250 ;
        RECT 132.500 49.910 132.760 50.230 ;
        RECT 133.020 49.290 133.160 50.930 ;
        RECT 132.560 49.150 133.160 49.290 ;
        RECT 129.740 48.210 130.000 48.530 ;
        RECT 130.660 48.210 130.920 48.530 ;
        RECT 132.040 48.210 132.300 48.530 ;
        RECT 130.200 47.190 130.460 47.510 ;
        RECT 130.260 44.790 130.400 47.190 ;
        RECT 130.200 44.470 130.460 44.790 ;
        RECT 130.260 41.390 130.400 44.470 ;
        RECT 130.720 44.110 130.860 48.210 ;
        RECT 132.100 47.850 132.240 48.210 ;
        RECT 132.040 47.530 132.300 47.850 ;
        RECT 132.560 47.170 132.700 49.150 ;
        RECT 133.480 48.190 133.620 52.630 ;
        RECT 133.940 50.910 134.080 55.350 ;
        RECT 135.260 54.670 135.520 54.990 ;
        RECT 135.720 54.670 135.980 54.990 ;
        RECT 135.320 52.270 135.460 54.670 ;
        RECT 135.780 53.970 135.920 54.670 ;
        RECT 136.700 53.970 136.840 65.890 ;
        RECT 138.140 65.015 140.020 65.385 ;
        RECT 140.380 64.250 140.520 68.950 ;
        RECT 140.840 67.570 140.980 70.990 ;
        RECT 141.760 69.270 141.900 79.490 ;
        RECT 142.160 76.770 142.420 77.090 ;
        RECT 142.220 71.650 142.360 76.770 ;
        RECT 142.620 73.710 142.880 74.030 ;
        RECT 142.680 72.330 142.820 73.710 ;
        RECT 142.620 72.010 142.880 72.330 ;
        RECT 142.160 71.330 142.420 71.650 ;
        RECT 141.700 68.950 141.960 69.270 ;
        RECT 140.780 67.250 141.040 67.570 ;
        RECT 141.760 66.890 141.900 68.950 ;
        RECT 141.700 66.570 141.960 66.890 ;
        RECT 141.240 65.890 141.500 66.210 ;
        RECT 141.300 64.850 141.440 65.890 ;
        RECT 141.240 64.530 141.500 64.850 ;
        RECT 139.920 64.170 140.980 64.250 ;
        RECT 139.860 64.110 140.980 64.170 ;
        RECT 139.860 63.850 140.120 64.110 ;
        RECT 137.560 62.830 137.820 63.150 ;
        RECT 137.100 60.110 137.360 60.430 ;
        RECT 137.160 59.410 137.300 60.110 ;
        RECT 137.100 59.090 137.360 59.410 ;
        RECT 137.620 58.050 137.760 62.830 ;
        RECT 138.140 59.575 140.020 59.945 ;
        RECT 140.840 58.390 140.980 64.110 ;
        RECT 141.700 63.510 141.960 63.830 ;
        RECT 141.240 63.170 141.500 63.490 ;
        RECT 141.300 58.390 141.440 63.170 ;
        RECT 141.760 59.410 141.900 63.510 ;
        RECT 141.700 59.090 141.960 59.410 ;
        RECT 140.780 58.070 141.040 58.390 ;
        RECT 141.240 58.070 141.500 58.390 ;
        RECT 137.560 57.730 137.820 58.050 ;
        RECT 137.100 57.390 137.360 57.710 ;
        RECT 138.480 57.390 138.740 57.710 ;
        RECT 137.160 56.010 137.300 57.390 ;
        RECT 138.540 56.010 138.680 57.390 ;
        RECT 137.100 55.690 137.360 56.010 ;
        RECT 138.480 55.690 138.740 56.010 ;
        RECT 138.140 54.135 140.020 54.505 ;
        RECT 135.720 53.650 135.980 53.970 ;
        RECT 136.640 53.650 136.900 53.970 ;
        RECT 135.260 51.950 135.520 52.270 ;
        RECT 134.440 51.415 136.320 51.785 ;
        RECT 133.880 50.590 134.140 50.910 ;
        RECT 133.420 47.870 133.680 48.190 ;
        RECT 132.500 46.850 132.760 47.170 ;
        RECT 132.960 46.850 133.220 47.170 ;
        RECT 133.020 45.810 133.160 46.850 ;
        RECT 132.960 45.490 133.220 45.810 ;
        RECT 130.660 43.790 130.920 44.110 ;
        RECT 129.740 41.070 130.000 41.390 ;
        RECT 130.200 41.070 130.460 41.390 ;
        RECT 129.800 36.970 129.940 41.070 ;
        RECT 130.720 40.450 130.860 43.790 ;
        RECT 132.040 41.070 132.300 41.390 ;
        RECT 130.260 40.310 130.860 40.450 ;
        RECT 130.260 39.010 130.400 40.310 ;
        RECT 132.100 39.350 132.240 41.070 ;
        RECT 132.040 39.030 132.300 39.350 ;
        RECT 130.200 38.690 130.460 39.010 ;
        RECT 130.260 36.970 130.400 38.690 ;
        RECT 129.740 36.650 130.000 36.970 ;
        RECT 130.200 36.650 130.460 36.970 ;
        RECT 132.960 36.650 133.220 36.970 ;
        RECT 129.800 33.910 129.940 36.650 ;
        RECT 129.740 33.590 130.000 33.910 ;
        RECT 132.040 33.650 132.300 33.910 ;
        RECT 132.040 33.590 132.700 33.650 ;
        RECT 132.100 33.510 132.700 33.590 ;
        RECT 132.040 32.910 132.300 33.230 ;
        RECT 132.100 31.530 132.240 32.910 ;
        RECT 132.040 31.210 132.300 31.530 ;
        RECT 132.100 28.470 132.240 31.210 ;
        RECT 132.560 28.470 132.700 33.510 ;
        RECT 133.020 33.230 133.160 36.650 ;
        RECT 133.480 33.910 133.620 47.870 ;
        RECT 133.940 47.510 134.080 50.590 ;
        RECT 136.180 49.910 136.440 50.230 ;
        RECT 133.880 47.190 134.140 47.510 ;
        RECT 136.240 46.830 136.380 49.910 ;
        RECT 136.180 46.510 136.440 46.830 ;
        RECT 134.440 45.975 136.320 46.345 ;
        RECT 136.700 42.750 136.840 53.650 ;
        RECT 140.840 53.290 140.980 58.070 ;
        RECT 140.780 52.970 141.040 53.290 ;
        RECT 141.300 52.610 141.440 58.070 ;
        RECT 141.760 56.690 141.900 59.090 ;
        RECT 142.220 58.730 142.360 71.330 ;
        RECT 143.140 63.830 143.280 79.830 ;
        RECT 144.060 75.730 144.200 87.230 ;
        RECT 146.360 87.230 147.660 87.370 ;
        RECT 144.460 82.550 144.720 82.870 ;
        RECT 145.380 82.550 145.640 82.870 ;
        RECT 144.520 78.450 144.660 82.550 ;
        RECT 144.460 78.130 144.720 78.450 ;
        RECT 144.000 75.410 144.260 75.730 ;
        RECT 143.540 75.070 143.800 75.390 ;
        RECT 143.080 63.510 143.340 63.830 ;
        RECT 143.600 60.770 143.740 75.070 ;
        RECT 144.520 75.050 144.660 78.130 ;
        RECT 144.460 74.730 144.720 75.050 ;
        RECT 145.440 74.030 145.580 82.550 ;
        RECT 146.360 81.170 146.500 87.230 ;
        RECT 147.070 86.800 147.660 87.230 ;
        RECT 147.360 85.670 147.660 86.800 ;
        RECT 147.325 85.390 147.695 85.670 ;
        RECT 147.360 85.380 147.660 85.390 ;
        RECT 146.300 80.850 146.560 81.170 ;
        RECT 146.300 80.170 146.560 80.490 ;
        RECT 145.380 73.710 145.640 74.030 ;
        RECT 146.360 71.310 146.500 80.170 ;
        RECT 146.300 70.990 146.560 71.310 ;
        RECT 144.000 65.550 144.260 65.870 ;
        RECT 144.060 64.170 144.200 65.550 ;
        RECT 146.360 64.170 146.500 70.990 ;
        RECT 144.000 63.850 144.260 64.170 ;
        RECT 146.300 63.850 146.560 64.170 ;
        RECT 144.060 62.130 144.200 63.850 ;
        RECT 144.000 61.810 144.260 62.130 ;
        RECT 143.540 60.450 143.800 60.770 ;
        RECT 143.600 59.070 143.740 60.450 ;
        RECT 144.060 59.410 144.200 61.810 ;
        RECT 144.000 59.090 144.260 59.410 ;
        RECT 143.540 58.750 143.800 59.070 ;
        RECT 142.160 58.410 142.420 58.730 ;
        RECT 143.080 58.410 143.340 58.730 ;
        RECT 142.160 57.730 142.420 58.050 ;
        RECT 141.700 56.370 141.960 56.690 ;
        RECT 142.220 53.970 142.360 57.730 ;
        RECT 143.140 53.970 143.280 58.410 ;
        RECT 143.600 55.670 143.740 58.750 ;
        RECT 144.000 58.410 144.260 58.730 ;
        RECT 143.540 55.350 143.800 55.670 ;
        RECT 144.060 53.970 144.200 58.410 ;
        RECT 144.460 56.370 144.720 56.690 ;
        RECT 142.160 53.650 142.420 53.970 ;
        RECT 143.080 53.650 143.340 53.970 ;
        RECT 144.000 53.650 144.260 53.970 ;
        RECT 141.700 53.310 141.960 53.630 ;
        RECT 141.240 52.290 141.500 52.610 ;
        RECT 139.400 51.950 139.660 52.270 ;
        RECT 139.460 50.230 139.600 51.950 ;
        RECT 140.320 50.590 140.580 50.910 ;
        RECT 137.100 49.910 137.360 50.230 ;
        RECT 139.400 49.910 139.660 50.230 ;
        RECT 137.160 45.470 137.300 49.910 ;
        RECT 138.140 48.695 140.020 49.065 ;
        RECT 140.380 47.850 140.520 50.590 ;
        RECT 141.300 47.850 141.440 52.290 ;
        RECT 141.760 50.230 141.900 53.310 ;
        RECT 141.700 49.910 141.960 50.230 ;
        RECT 141.760 47.850 141.900 49.910 ;
        RECT 142.220 49.890 142.360 53.650 ;
        RECT 144.520 53.630 144.660 56.370 ;
        RECT 144.460 53.370 144.720 53.630 ;
        RECT 142.680 53.310 144.720 53.370 ;
        RECT 142.680 53.290 144.660 53.310 ;
        RECT 142.620 53.230 144.660 53.290 ;
        RECT 142.620 52.970 142.880 53.230 ;
        RECT 142.160 49.570 142.420 49.890 ;
        RECT 140.320 47.530 140.580 47.850 ;
        RECT 141.240 47.530 141.500 47.850 ;
        RECT 141.700 47.530 141.960 47.850 ;
        RECT 139.400 46.510 139.660 46.830 ;
        RECT 139.460 45.810 139.600 46.510 ;
        RECT 141.760 45.810 141.900 47.530 ;
        RECT 139.400 45.490 139.660 45.810 ;
        RECT 141.700 45.490 141.960 45.810 ;
        RECT 137.100 45.150 137.360 45.470 ;
        RECT 137.100 44.470 137.360 44.790 ;
        RECT 136.640 42.430 136.900 42.750 ;
        RECT 137.160 41.810 137.300 44.470 ;
        RECT 141.240 44.130 141.500 44.450 ;
        RECT 138.140 43.255 140.020 43.625 ;
        RECT 139.400 42.090 139.660 42.410 ;
        RECT 140.320 42.090 140.580 42.410 ;
        RECT 139.460 41.810 139.600 42.090 ;
        RECT 136.700 41.670 137.300 41.810 ;
        RECT 139.000 41.670 139.600 41.810 ;
        RECT 134.440 40.535 136.320 40.905 ;
        RECT 134.800 38.690 135.060 39.010 ;
        RECT 134.860 38.410 135.000 38.690 ;
        RECT 136.700 38.410 136.840 41.670 ;
        RECT 137.560 41.130 137.820 41.390 ;
        RECT 134.860 38.270 136.840 38.410 ;
        RECT 137.160 41.070 137.820 41.130 ;
        RECT 138.480 41.070 138.740 41.390 ;
        RECT 137.160 40.990 137.760 41.070 ;
        RECT 135.320 36.970 135.460 38.270 ;
        RECT 137.160 37.310 137.300 40.990 ;
        RECT 138.540 40.370 138.680 41.070 ;
        RECT 139.000 40.370 139.140 41.670 ;
        RECT 138.480 40.050 138.740 40.370 ;
        RECT 138.940 40.050 139.200 40.370 ;
        RECT 138.140 37.815 140.020 38.185 ;
        RECT 140.380 37.650 140.520 42.090 ;
        RECT 141.300 39.690 141.440 44.130 ;
        RECT 141.240 39.370 141.500 39.690 ;
        RECT 141.300 38.410 141.440 39.370 ;
        RECT 141.300 38.270 141.900 38.410 ;
        RECT 137.560 37.330 137.820 37.650 ;
        RECT 140.320 37.330 140.580 37.650 ;
        RECT 137.100 36.990 137.360 37.310 ;
        RECT 135.260 36.650 135.520 36.970 ;
        RECT 136.640 36.310 136.900 36.630 ;
        RECT 134.440 35.095 136.320 35.465 ;
        RECT 136.700 34.930 136.840 36.310 ;
        RECT 137.100 35.630 137.360 35.950 ;
        RECT 136.640 34.610 136.900 34.930 ;
        RECT 137.160 33.910 137.300 35.630 ;
        RECT 137.620 33.910 137.760 37.330 ;
        RECT 141.760 37.310 141.900 38.270 ;
        RECT 138.020 37.050 138.280 37.310 ;
        RECT 138.020 36.990 138.680 37.050 ;
        RECT 141.700 36.990 141.960 37.310 ;
        RECT 138.080 36.910 138.680 36.990 ;
        RECT 138.540 35.950 138.680 36.910 ;
        RECT 138.480 35.630 138.740 35.950 ;
        RECT 138.540 34.930 138.680 35.630 ;
        RECT 138.480 34.610 138.740 34.930 ;
        RECT 133.420 33.590 133.680 33.910 ;
        RECT 137.100 33.590 137.360 33.910 ;
        RECT 137.560 33.590 137.820 33.910 ;
        RECT 141.240 33.590 141.500 33.910 ;
        RECT 132.960 32.910 133.220 33.230 ;
        RECT 132.040 28.150 132.300 28.470 ;
        RECT 132.500 28.150 132.760 28.470 ;
        RECT 132.560 25.750 132.700 28.150 ;
        RECT 133.480 26.850 133.620 33.590 ;
        RECT 138.140 32.375 140.020 32.745 ;
        RECT 141.300 31.190 141.440 33.590 ;
        RECT 137.100 30.870 137.360 31.190 ;
        RECT 141.240 30.870 141.500 31.190 ;
        RECT 136.640 30.190 136.900 30.510 ;
        RECT 134.440 29.655 136.320 30.025 ;
        RECT 136.700 28.810 136.840 30.190 ;
        RECT 136.640 28.490 136.900 28.810 ;
        RECT 133.020 26.770 133.620 26.850 ;
        RECT 132.960 26.710 133.620 26.770 ;
        RECT 132.960 26.450 133.220 26.710 ;
        RECT 137.160 25.750 137.300 30.870 ;
        RECT 138.140 26.935 140.020 27.305 ;
        RECT 141.300 26.770 141.440 30.870 ;
        RECT 141.760 28.130 141.900 36.990 ;
        RECT 141.700 27.810 141.960 28.130 ;
        RECT 141.240 26.450 141.500 26.770 ;
        RECT 141.760 26.430 141.900 27.810 ;
        RECT 141.700 26.110 141.960 26.430 ;
        RECT 132.500 25.430 132.760 25.750 ;
        RECT 137.100 25.430 137.360 25.750 ;
        RECT 134.440 24.215 136.320 24.585 ;
        RECT 137.160 24.050 137.300 25.430 ;
        RECT 137.100 23.730 137.360 24.050 ;
        RECT 129.270 21.155 129.550 21.525 ;
        RECT 138.140 21.495 140.020 21.865 ;
        RECT 134.440 18.775 136.320 19.145 ;
        RECT 12.000 18.000 14.000 18.030 ;
        RECT 8.000 16.000 14.000 18.000 ;
        RECT 138.140 16.055 140.020 16.425 ;
        RECT 8.000 6.000 10.000 16.000 ;
        RECT 12.000 15.970 14.000 16.000 ;
        RECT 151.000 6.000 153.000 96.145 ;
        RECT 153.500 6.000 155.500 99.215 ;
      LAYER met3 ;
        RECT 143.810 110.080 144.190 110.090 ;
        RECT 149.880 110.080 150.260 110.090 ;
        RECT 130.505 109.820 130.835 109.835 ;
        RECT 135.510 109.820 135.890 109.830 ;
        RECT 130.505 109.520 135.890 109.820 ;
        RECT 130.505 109.505 130.835 109.520 ;
        RECT 135.510 109.510 135.890 109.520 ;
        RECT 137.185 109.780 137.515 109.795 ;
        RECT 141.030 109.780 141.410 109.790 ;
        RECT 137.185 109.480 141.410 109.780 ;
        RECT 143.810 109.780 150.260 110.080 ;
        RECT 143.810 109.770 144.190 109.780 ;
        RECT 149.880 109.770 150.260 109.780 ;
        RECT 137.185 109.465 137.515 109.480 ;
        RECT 141.030 109.470 141.410 109.480 ;
        RECT 133.165 108.980 133.495 108.995 ;
        RECT 138.270 108.980 138.650 108.990 ;
        RECT 133.165 108.680 138.650 108.980 ;
        RECT 133.165 108.665 133.495 108.680 ;
        RECT 138.270 108.670 138.650 108.680 ;
        RECT 42.040 108.170 42.360 108.210 ;
        RECT 43.575 108.170 43.905 108.185 ;
        RECT 42.040 107.870 43.905 108.170 ;
        RECT 42.040 107.830 42.360 107.870 ;
        RECT 43.575 107.855 43.905 107.870 ;
        RECT 94.140 106.440 94.460 106.480 ;
        RECT 108.100 106.440 108.480 106.450 ;
        RECT 94.140 106.140 108.480 106.440 ;
        RECT 94.140 106.100 94.460 106.140 ;
        RECT 108.100 106.130 108.480 106.140 ;
        RECT 91.340 104.990 91.720 105.000 ;
        RECT 138.125 104.990 138.455 105.005 ;
        RECT 91.340 104.690 138.455 104.990 ;
        RECT 91.340 104.680 91.720 104.690 ;
        RECT 138.125 104.675 138.455 104.690 ;
        RECT 112.270 103.610 112.650 103.620 ;
        RECT 133.075 103.610 133.405 103.625 ;
        RECT 112.270 103.310 133.405 103.610 ;
        RECT 112.270 103.300 112.650 103.310 ;
        RECT 133.075 103.295 133.405 103.310 ;
        RECT 38.910 102.880 39.290 102.890 ;
        RECT 110.040 102.880 110.420 102.890 ;
        RECT 38.910 102.580 110.420 102.880 ;
        RECT 38.910 102.570 39.290 102.580 ;
        RECT 110.040 102.570 110.420 102.580 ;
        RECT 113.100 102.550 113.480 102.560 ;
        RECT 137.225 102.550 137.555 102.565 ;
        RECT 113.100 102.250 137.555 102.550 ;
        RECT 113.100 102.240 113.480 102.250 ;
        RECT 137.225 102.235 137.555 102.250 ;
        RECT 5.500 99.130 135.650 101.000 ;
        RECT 142.400 100.100 143.280 107.700 ;
        RECT 145.100 100.100 145.980 108.440 ;
        RECT 159.380 107.580 160.510 108.820 ;
        RECT 153.475 99.130 155.525 99.195 ;
        RECT 5.500 99.000 155.590 99.130 ;
        RECT 5.500 96.500 132.050 98.500 ;
        RECT 133.650 97.130 155.590 99.000 ;
        RECT 130.050 96.140 132.050 96.500 ;
        RECT 42.955 94.520 43.995 94.545 ;
        RECT 38.450 93.480 43.995 94.520 ;
        RECT 80.995 93.495 83.510 94.455 ;
        RECT 130.050 94.140 155.590 96.140 ;
        RECT 150.975 94.125 153.025 94.140 ;
        RECT 42.955 93.455 43.995 93.480 ;
        RECT 110.040 93.240 110.420 93.250 ;
        RECT 144.255 93.240 144.585 93.255 ;
        RECT 110.040 92.940 144.585 93.240 ;
        RECT 110.040 92.930 110.420 92.940 ;
        RECT 144.255 92.925 144.585 92.940 ;
        RECT 72.060 91.660 72.380 91.700 ;
        RECT 118.205 91.660 118.535 91.675 ;
        RECT 72.060 91.360 118.535 91.660 ;
        RECT 72.060 91.320 72.380 91.360 ;
        RECT 118.205 91.345 118.535 91.360 ;
        RECT 69.270 90.890 69.650 90.900 ;
        RECT 121.275 90.890 121.605 90.905 ;
        RECT 69.270 90.590 121.605 90.890 ;
        RECT 69.270 90.580 69.650 90.590 ;
        RECT 121.275 90.575 121.605 90.590 ;
        RECT 66.540 90.050 66.860 90.090 ;
        RECT 126.455 90.050 126.785 90.065 ;
        RECT 66.540 89.750 126.810 90.050 ;
        RECT 66.540 89.710 66.860 89.750 ;
        RECT 126.455 89.735 126.785 89.750 ;
        RECT 63.750 89.310 64.130 89.320 ;
        RECT 130.555 89.310 130.885 89.325 ;
        RECT 63.750 89.010 130.885 89.310 ;
        RECT 63.750 89.000 64.130 89.010 ;
        RECT 130.555 88.995 130.885 89.010 ;
        RECT 60.990 88.420 61.370 88.430 ;
        RECT 134.665 88.420 134.995 88.435 ;
        RECT 60.990 88.120 134.995 88.420 ;
        RECT 139.935 88.205 140.265 88.535 ;
        RECT 60.990 88.110 61.370 88.120 ;
        RECT 134.665 88.105 134.995 88.120 ;
        RECT 58.230 87.470 58.610 87.480 ;
        RECT 139.950 87.470 140.250 88.205 ;
        RECT 144.775 88.135 145.105 88.465 ;
        RECT 58.230 87.170 140.250 87.470 ;
        RECT 58.230 87.160 58.610 87.170 ;
        RECT 55.500 86.520 55.820 86.560 ;
        RECT 144.790 86.520 145.090 88.135 ;
        RECT 55.500 86.220 145.160 86.520 ;
        RECT 55.500 86.180 55.820 86.220 ;
        RECT 52.710 85.680 53.090 85.690 ;
        RECT 147.345 85.680 147.675 85.695 ;
        RECT 52.710 85.380 147.710 85.680 ;
        RECT 52.710 85.370 53.090 85.380 ;
        RECT 147.345 85.365 147.675 85.380 ;
        RECT 134.390 84.075 136.370 84.405 ;
        RECT 91.350 81.640 91.730 81.650 ;
        RECT 91.350 81.340 116.080 81.640 ;
        RECT 138.090 81.355 140.070 81.685 ;
        RECT 91.350 81.330 91.730 81.340 ;
        RECT 115.780 79.060 116.080 81.340 ;
        RECT 114.000 78.610 118.000 79.060 ;
        RECT 134.390 78.635 136.370 78.965 ;
        RECT 120.965 78.610 121.295 78.625 ;
        RECT 114.000 78.310 121.295 78.610 ;
        RECT 114.000 77.860 118.000 78.310 ;
        RECT 120.965 78.295 121.295 78.310 ;
        RECT 15.500 71.830 20.900 77.230 ;
        RECT 23.300 71.830 28.700 77.230 ;
        RECT 30.500 71.830 35.900 77.230 ;
        RECT 38.300 71.830 43.700 77.230 ;
        RECT 138.090 75.915 140.070 76.245 ;
        RECT 134.390 73.195 136.370 73.525 ;
        RECT 18.000 69.430 18.400 71.830 ;
        RECT 25.800 69.430 26.200 71.830 ;
        RECT 33.000 69.430 33.400 71.830 ;
        RECT 40.800 69.430 41.200 71.830 ;
        RECT 138.090 70.475 140.070 70.805 ;
        RECT 15.500 64.530 20.900 69.430 ;
        RECT 23.300 64.530 28.700 69.430 ;
        RECT 30.500 64.530 35.900 69.430 ;
        RECT 38.300 64.530 43.700 69.430 ;
        RECT 153.500 69.265 159.010 69.670 ;
        RECT 134.390 67.755 136.370 68.085 ;
        RECT 153.500 68.075 160.495 69.265 ;
        RECT 153.500 67.670 159.010 68.075 ;
        RECT 48.340 64.530 49.300 66.210 ;
        RECT 108.130 66.040 108.450 66.420 ;
        RECT 108.140 65.385 108.440 66.040 ;
        RECT 108.125 65.055 108.455 65.385 ;
        RECT 138.090 65.035 140.070 65.365 ;
        RECT 51.000 65.025 52.000 65.030 ;
        RECT 15.500 64.030 49.300 64.530 ;
        RECT 50.975 64.035 52.025 65.025 ;
        RECT 118.205 65.010 118.535 65.025 ;
        RECT 117.990 64.780 118.535 65.010 ;
        RECT 114.000 64.695 118.535 64.780 ;
        RECT 5.540 57.180 7.540 57.205 ;
        RECT 1.990 56.940 7.540 57.180 ;
        RECT 0.190 55.420 7.540 56.940 ;
        RECT 15.500 56.830 20.900 62.230 ;
        RECT 23.300 56.830 28.700 62.230 ;
        RECT 30.500 56.830 35.900 62.230 ;
        RECT 38.300 56.830 43.700 62.230 ;
        RECT 1.990 55.180 7.540 55.420 ;
        RECT 5.540 55.155 7.540 55.180 ;
        RECT 18.000 54.430 18.400 56.830 ;
        RECT 25.800 54.430 26.200 56.830 ;
        RECT 33.000 54.430 33.400 56.830 ;
        RECT 40.800 54.430 41.200 56.830 ;
        RECT 8.190 53.495 10.190 53.520 ;
        RECT 2.365 51.495 10.190 53.495 ;
        RECT 8.190 51.470 10.190 51.495 ;
        RECT 15.500 49.530 20.900 54.430 ;
        RECT 23.300 49.530 28.700 54.430 ;
        RECT 30.500 49.530 35.900 54.430 ;
        RECT 38.300 49.530 43.700 54.430 ;
        RECT 48.340 49.530 49.300 64.030 ;
        RECT 15.500 49.030 49.300 49.530 ;
        RECT 51.000 49.000 52.000 64.035 ;
        RECT 114.000 64.030 118.290 64.695 ;
        RECT 151.000 64.115 158.635 66.115 ;
        RECT 114.000 63.580 118.000 64.030 ;
        RECT 134.390 62.315 136.370 62.645 ;
        RECT 138.090 59.595 140.070 59.925 ;
        RECT 53.500 54.030 58.900 59.430 ;
        RECT 62.450 54.530 62.950 55.280 ;
        RECT 64.500 54.530 69.900 59.430 ;
        RECT 134.390 56.875 136.370 57.205 ;
        RECT 61.500 54.030 69.900 54.530 ;
        RECT 138.090 54.155 140.070 54.485 ;
        RECT 53.500 50.555 54.500 54.030 ;
        RECT 134.390 51.435 136.370 51.765 ;
        RECT 53.475 49.555 54.525 50.555 ;
        RECT 112.270 50.050 112.650 50.060 ;
        RECT 114.000 50.050 118.000 50.500 ;
        RECT 120.505 50.050 120.835 50.065 ;
        RECT 112.270 49.750 120.835 50.050 ;
        RECT 112.270 49.740 112.650 49.750 ;
        RECT 114.000 49.300 118.000 49.750 ;
        RECT 120.505 49.735 120.835 49.750 ;
        RECT 138.090 48.715 140.070 49.045 ;
        RECT 134.390 45.995 136.370 46.325 ;
        RECT 138.090 43.275 140.070 43.605 ;
        RECT 134.390 40.555 136.370 40.885 ;
        RECT 138.090 37.835 140.070 38.165 ;
        RECT 113.100 35.770 113.480 35.780 ;
        RECT 114.000 35.770 118.000 36.220 ;
        RECT 120.505 35.770 120.835 35.785 ;
        RECT 113.100 35.470 120.835 35.770 ;
        RECT 113.100 35.460 113.480 35.470 ;
        RECT 114.000 35.020 118.000 35.470 ;
        RECT 120.505 35.455 120.835 35.470 ;
        RECT 134.390 35.115 136.370 35.445 ;
        RECT 138.090 32.395 140.070 32.725 ;
        RECT 134.390 29.675 136.370 30.005 ;
        RECT 48.975 26.975 50.025 27.975 ;
        RECT 20.995 25.775 21.955 25.825 ;
        RECT 20.995 24.815 22.005 25.775 ;
        RECT 21.020 22.000 21.980 24.815 ;
        RECT 49.000 23.900 50.000 26.975 ;
        RECT 138.090 26.955 140.070 27.285 ;
        RECT 134.390 24.235 136.370 24.565 ;
        RECT 23.500 23.000 28.900 23.900 ;
        RECT 30.500 23.000 35.900 23.900 ;
        RECT 47.000 23.000 52.400 23.900 ;
        RECT 23.500 22.000 52.400 23.000 ;
        RECT 23.500 18.500 28.900 22.000 ;
        RECT 30.500 18.500 35.900 22.000 ;
        RECT 47.000 18.500 52.400 22.000 ;
        RECT 73.475 21.970 74.475 24.025 ;
        RECT 111.980 21.490 112.300 21.530 ;
        RECT 114.000 21.490 118.000 21.940 ;
        RECT 138.090 21.515 140.070 21.845 ;
        RECT 129.245 21.490 129.575 21.505 ;
        RECT 111.980 21.190 129.575 21.490 ;
        RECT 111.980 21.150 112.300 21.190 ;
        RECT 114.000 20.740 118.000 21.190 ;
        RECT 129.245 21.175 129.575 21.190 ;
        RECT 134.390 18.795 136.370 19.125 ;
        RECT 138.090 16.075 140.070 16.405 ;
        RECT 111.980 11.330 112.300 11.370 ;
        RECT 149.880 11.330 150.260 11.340 ;
        RECT 111.980 11.030 150.260 11.330 ;
        RECT 111.980 10.990 112.300 11.030 ;
        RECT 149.880 11.020 150.260 11.030 ;
        RECT 5.500 8.500 155.500 10.500 ;
        RECT 138.085 8.000 140.075 8.025 ;
        RECT 5.500 6.000 155.500 8.000 ;
        RECT 138.085 5.975 140.075 6.000 ;
        RECT 2.400 2.400 158.600 4.400 ;
        RECT 0.000 0.000 161.000 2.000 ;
      LAYER met4 ;
        RECT 144.130 110.520 144.150 111.180 ;
        RECT 30.670 110.060 30.970 110.520 ;
        RECT 33.430 110.090 33.730 110.520 ;
        RECT 36.190 110.090 36.490 110.520 ;
        RECT 38.950 110.120 39.250 110.520 ;
        RECT 41.710 110.040 42.010 110.520 ;
        RECT 44.470 110.060 44.770 110.520 ;
        RECT 47.230 110.010 47.530 110.520 ;
        RECT 49.990 110.000 50.290 110.520 ;
        RECT 30.670 109.520 30.970 109.760 ;
        RECT 33.430 109.520 33.730 109.790 ;
        RECT 36.190 109.520 36.490 109.790 ;
        RECT 38.950 109.520 39.250 109.820 ;
        RECT 41.710 109.520 42.010 109.740 ;
        RECT 44.470 109.520 44.770 109.760 ;
        RECT 47.230 109.520 47.530 109.710 ;
        RECT 49.990 109.520 50.290 109.700 ;
        RECT 30.470 109.220 50.290 109.520 ;
        RECT 36.190 109.210 36.490 109.220 ;
        RECT 42.050 108.185 42.350 109.220 ;
        RECT 42.035 107.855 42.365 108.185 ;
        RECT 38.935 102.565 39.265 102.895 ;
        RECT 38.950 94.525 39.250 102.565 ;
        RECT 38.475 93.475 39.515 94.525 ;
        RECT 52.750 85.695 53.050 110.520 ;
        RECT 55.510 86.535 55.810 110.520 ;
        RECT 58.270 87.485 58.570 110.520 ;
        RECT 61.030 88.435 61.330 110.520 ;
        RECT 63.790 89.325 64.090 110.520 ;
        RECT 66.550 90.065 66.850 110.520 ;
        RECT 69.310 90.905 69.610 110.520 ;
        RECT 72.070 91.675 72.370 110.520 ;
        RECT 91.390 105.005 91.690 110.520 ;
        RECT 94.150 106.455 94.450 110.520 ;
        RECT 135.550 109.835 135.850 110.520 ;
        RECT 135.535 109.505 135.865 109.835 ;
        RECT 138.310 108.995 138.610 110.520 ;
        RECT 141.070 109.795 141.370 110.520 ;
        RECT 143.850 110.095 144.150 110.520 ;
        RECT 141.055 109.465 141.385 109.795 ;
        RECT 143.835 109.765 144.165 110.095 ;
        RECT 149.905 109.765 150.235 110.095 ;
        RECT 138.295 108.665 138.625 108.995 ;
        RECT 94.135 106.125 94.465 106.455 ;
        RECT 108.125 106.125 108.455 106.455 ;
        RECT 94.150 105.890 94.450 106.125 ;
        RECT 91.365 104.675 91.695 105.005 ;
        RECT 83.110 98.065 83.410 101.000 ;
        RECT 83.110 94.460 83.480 98.065 ;
        RECT 82.525 94.095 83.485 94.460 ;
        RECT 82.525 93.765 83.495 94.095 ;
        RECT 82.525 93.490 83.485 93.765 ;
        RECT 72.055 91.345 72.385 91.675 ;
        RECT 69.295 90.575 69.625 90.905 ;
        RECT 66.535 89.735 66.865 90.065 ;
        RECT 63.775 88.995 64.105 89.325 ;
        RECT 61.015 88.105 61.345 88.435 ;
        RECT 58.255 87.155 58.585 87.485 ;
        RECT 55.495 86.205 55.825 86.535 ;
        RECT 52.735 85.365 53.065 85.695 ;
        RECT 91.390 81.655 91.690 104.675 ;
        RECT 91.375 81.325 91.705 81.655 ;
        RECT 15.500 71.830 20.900 77.230 ;
        RECT 23.300 71.830 28.700 77.230 ;
        RECT 30.500 71.830 35.900 77.230 ;
        RECT 38.300 71.830 43.700 77.230 ;
        RECT 18.000 69.430 18.400 71.830 ;
        RECT 25.800 69.430 26.200 71.830 ;
        RECT 33.000 69.430 33.400 71.830 ;
        RECT 40.800 69.430 41.200 71.830 ;
        RECT 15.500 64.530 20.900 69.430 ;
        RECT 23.300 64.530 28.700 69.430 ;
        RECT 30.500 64.530 35.900 69.430 ;
        RECT 38.300 64.530 43.700 69.430 ;
        RECT 108.140 66.395 108.440 106.125 ;
        RECT 112.295 103.295 112.625 103.625 ;
        RECT 110.065 102.565 110.395 102.895 ;
        RECT 110.080 93.255 110.380 102.565 ;
        RECT 110.065 92.925 110.395 93.255 ;
        RECT 108.125 66.065 108.455 66.395 ;
        RECT 51.000 64.530 52.000 65.030 ;
        RECT 15.500 64.030 52.000 64.530 ;
        RECT 15.500 56.830 20.900 62.230 ;
        RECT 23.300 56.830 28.700 62.230 ;
        RECT 30.500 56.830 35.900 62.230 ;
        RECT 38.300 56.830 43.700 62.230 ;
        RECT 18.000 54.430 18.400 56.830 ;
        RECT 25.800 54.430 26.200 56.830 ;
        RECT 33.000 54.430 33.400 56.830 ;
        RECT 40.800 54.430 41.200 56.830 ;
        RECT 53.500 54.530 58.900 59.430 ;
        RECT 61.545 54.530 62.055 54.535 ;
        RECT 2.390 51.490 2.400 53.500 ;
        RECT 15.500 49.530 20.900 54.430 ;
        RECT 23.300 49.530 28.700 54.430 ;
        RECT 30.500 49.530 35.900 54.430 ;
        RECT 38.300 49.530 43.700 54.430 ;
        RECT 53.500 54.030 62.055 54.530 ;
        RECT 64.500 54.030 69.900 59.430 ;
        RECT 61.545 54.025 62.055 54.030 ;
        RECT 50.995 49.530 52.005 50.025 ;
        RECT 65.250 49.530 65.750 54.030 ;
        RECT 112.310 50.065 112.610 103.295 ;
        RECT 113.125 102.235 113.455 102.565 ;
        RECT 112.295 49.735 112.625 50.065 ;
        RECT 15.500 49.030 65.750 49.530 ;
        RECT 50.995 49.025 52.005 49.030 ;
        RECT 113.140 35.785 113.440 102.235 ;
        RECT 113.125 35.455 113.455 35.785 ;
        RECT 23.500 22.985 28.900 23.900 ;
        RECT 30.500 22.985 35.900 23.900 ;
        RECT 21.015 22.025 35.900 22.985 ;
        RECT 23.500 18.500 28.900 22.025 ;
        RECT 30.500 18.500 35.900 22.025 ;
        RECT 47.000 22.995 52.400 23.900 ;
        RECT 47.000 21.995 74.480 22.995 ;
        RECT 47.000 18.500 52.400 21.995 ;
        RECT 111.975 21.175 112.305 21.505 ;
        RECT 111.990 11.345 112.290 21.175 ;
        RECT 111.975 11.015 112.305 11.345 ;
        RECT 134.380 8.500 136.380 84.480 ;
        RECT 138.080 6.000 140.080 84.480 ;
        RECT 149.920 11.345 150.220 109.765 ;
        RECT 156.600 66.120 158.600 111.520 ;
        RECT 156.600 64.110 158.610 66.120 ;
        RECT 149.905 11.015 150.235 11.345 ;
        RECT 156.600 0.000 158.600 64.110 ;
        RECT 159.000 0.000 161.000 111.520 ;
  END
END tt_um_lelo_gr04_analogicus
END LIBRARY

